VERSION 5.8 ;
BUSBITCHARS "[]" ;
DIVIDERCHAR "/" ;
UNITS
    DATABASE MICRONS 1000 ;
END UNITS

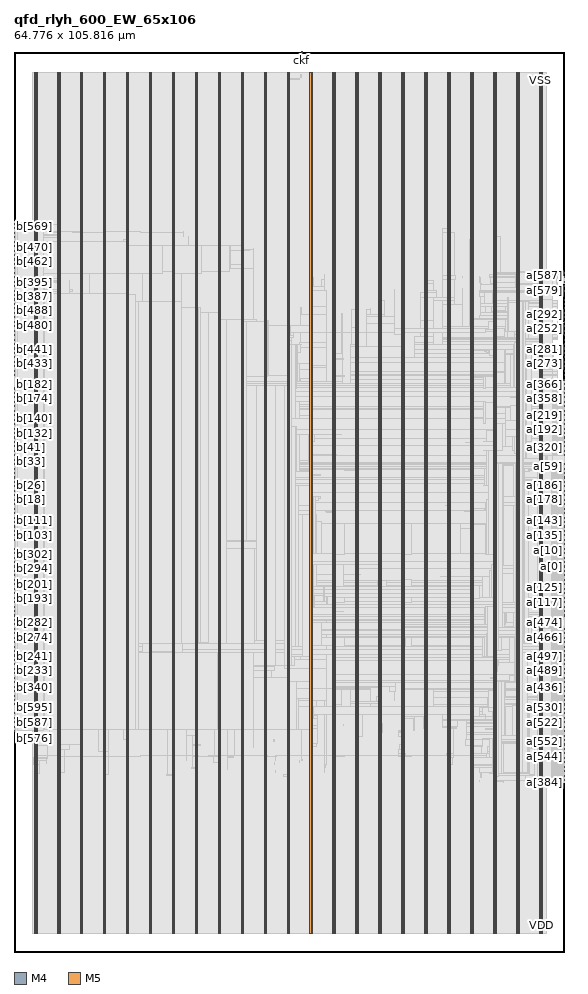
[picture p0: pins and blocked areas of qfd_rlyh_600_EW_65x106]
MACRO qfd_rlyh_600_EW_65x106
  FOREIGN qfd_rlyh_600_EW_65x106 0 0 ;
  CLASS BLOCK ;
  SIZE 64.776 BY 105.816 ;
  PIN a[0]
    DIRECTION INPUT ;
    USE SIGNAL ;
    PORT
      LAYER M4 ;
        RECT  64.692 45.264 64.776 45.288 ;
    END
  END a[0]
  PIN a[100]
    DIRECTION INPUT ;
    USE SIGNAL ;
    PORT
      LAYER M4 ;
        RECT  64.692 39.504 64.776 39.528 ;
    END
  END a[100]
  PIN a[101]
    DIRECTION INPUT ;
    USE SIGNAL ;
    PORT
      LAYER M4 ;
        RECT  64.692 39.6 64.776 39.624 ;
    END
  END a[101]
  PIN a[102]
    DIRECTION INPUT ;
    USE SIGNAL ;
    PORT
      LAYER M4 ;
        RECT  64.692 39.696 64.776 39.72 ;
    END
  END a[102]
  PIN a[103]
    DIRECTION INPUT ;
    USE SIGNAL ;
    PORT
      LAYER M4 ;
        RECT  64.692 39.792 64.776 39.816 ;
    END
  END a[103]
  PIN a[104]
    DIRECTION INPUT ;
    USE SIGNAL ;
    PORT
      LAYER M4 ;
        RECT  64.692 39.888 64.776 39.912 ;
    END
  END a[104]
  PIN a[105]
    DIRECTION INPUT ;
    USE SIGNAL ;
    PORT
      LAYER M4 ;
        RECT  64.692 39.984 64.776 40.008 ;
    END
  END a[105]
  PIN a[106]
    DIRECTION INPUT ;
    USE SIGNAL ;
    PORT
      LAYER M4 ;
        RECT  64.692 40.08 64.776 40.104 ;
    END
  END a[106]
  PIN a[107]
    DIRECTION INPUT ;
    USE SIGNAL ;
    PORT
      LAYER M4 ;
        RECT  64.692 40.176 64.776 40.2 ;
    END
  END a[107]
  PIN a[108]
    DIRECTION INPUT ;
    USE SIGNAL ;
    PORT
      LAYER M4 ;
        RECT  64.692 40.272 64.776 40.296 ;
    END
  END a[108]
  PIN a[109]
    DIRECTION INPUT ;
    USE SIGNAL ;
    PORT
      LAYER M4 ;
        RECT  64.692 40.368 64.776 40.392 ;
    END
  END a[109]
  PIN a[10]
    DIRECTION INPUT ;
    USE SIGNAL ;
    PORT
      LAYER M4 ;
        RECT  64.692 46.224 64.776 46.248 ;
    END
  END a[10]
  PIN a[110]
    DIRECTION INPUT ;
    USE SIGNAL ;
    PORT
      LAYER M4 ;
        RECT  64.692 40.464 64.776 40.488 ;
    END
  END a[110]
  PIN a[111]
    DIRECTION INPUT ;
    USE SIGNAL ;
    PORT
      LAYER M4 ;
        RECT  64.692 40.56 64.776 40.584 ;
    END
  END a[111]
  PIN a[112]
    DIRECTION INPUT ;
    USE SIGNAL ;
    PORT
      LAYER M4 ;
        RECT  64.692 40.656 64.776 40.68 ;
    END
  END a[112]
  PIN a[113]
    DIRECTION INPUT ;
    USE SIGNAL ;
    PORT
      LAYER M4 ;
        RECT  64.692 40.752 64.776 40.776 ;
    END
  END a[113]
  PIN a[114]
    DIRECTION INPUT ;
    USE SIGNAL ;
    PORT
      LAYER M4 ;
        RECT  64.692 40.848 64.776 40.872 ;
    END
  END a[114]
  PIN a[115]
    DIRECTION INPUT ;
    USE SIGNAL ;
    PORT
      LAYER M4 ;
        RECT  64.692 40.944 64.776 40.968 ;
    END
  END a[115]
  PIN a[116]
    DIRECTION INPUT ;
    USE SIGNAL ;
    PORT
      LAYER M4 ;
        RECT  64.692 41.04 64.776 41.064 ;
    END
  END a[116]
  PIN a[117]
    DIRECTION INPUT ;
    USE SIGNAL ;
    PORT
      LAYER M4 ;
        RECT  64.692 41.136 64.776 41.16 ;
    END
  END a[117]
  PIN a[118]
    DIRECTION INPUT ;
    USE SIGNAL ;
    PORT
      LAYER M4 ;
        RECT  64.692 41.232 64.776 41.256 ;
    END
  END a[118]
  PIN a[119]
    DIRECTION INPUT ;
    USE SIGNAL ;
    PORT
      LAYER M4 ;
        RECT  64.692 41.328 64.776 41.352 ;
    END
  END a[119]
  PIN a[11]
    DIRECTION INPUT ;
    USE SIGNAL ;
    PORT
      LAYER M4 ;
        RECT  64.692 46.32 64.776 46.344 ;
    END
  END a[11]
  PIN a[120]
    DIRECTION INPUT ;
    USE SIGNAL ;
    PORT
      LAYER M4 ;
        RECT  64.692 41.424 64.776 41.448 ;
    END
  END a[120]
  PIN a[121]
    DIRECTION INPUT ;
    USE SIGNAL ;
    PORT
      LAYER M4 ;
        RECT  64.692 41.52 64.776 41.544 ;
    END
  END a[121]
  PIN a[122]
    DIRECTION INPUT ;
    USE SIGNAL ;
    PORT
      LAYER M4 ;
        RECT  64.692 41.616 64.776 41.64 ;
    END
  END a[122]
  PIN a[123]
    DIRECTION INPUT ;
    USE SIGNAL ;
    PORT
      LAYER M4 ;
        RECT  64.692 41.712 64.776 41.736 ;
    END
  END a[123]
  PIN a[124]
    DIRECTION INPUT ;
    USE SIGNAL ;
    PORT
      LAYER M4 ;
        RECT  64.692 41.808 64.776 41.832 ;
    END
  END a[124]
  PIN a[125]
    DIRECTION INPUT ;
    USE SIGNAL ;
    PORT
      LAYER M4 ;
        RECT  64.692 41.904 64.776 41.928 ;
    END
  END a[125]
  PIN a[126]
    DIRECTION INPUT ;
    USE SIGNAL ;
    PORT
      LAYER M4 ;
        RECT  64.692 42 64.776 42.024 ;
    END
  END a[126]
  PIN a[127]
    DIRECTION INPUT ;
    USE SIGNAL ;
    PORT
      LAYER M4 ;
        RECT  64.692 42.096 64.776 42.12 ;
    END
  END a[127]
  PIN a[128]
    DIRECTION INPUT ;
    USE SIGNAL ;
    PORT
      LAYER M4 ;
        RECT  64.692 48.336 64.776 48.36 ;
    END
  END a[128]
  PIN a[129]
    DIRECTION INPUT ;
    USE SIGNAL ;
    PORT
      LAYER M4 ;
        RECT  64.692 48.432 64.776 48.456 ;
    END
  END a[129]
  PIN a[12]
    DIRECTION INPUT ;
    USE SIGNAL ;
    PORT
      LAYER M4 ;
        RECT  64.692 46.416 64.776 46.44 ;
    END
  END a[12]
  PIN a[130]
    DIRECTION INPUT ;
    USE SIGNAL ;
    PORT
      LAYER M4 ;
        RECT  64.692 48.528 64.776 48.552 ;
    END
  END a[130]
  PIN a[131]
    DIRECTION INPUT ;
    USE SIGNAL ;
    PORT
      LAYER M4 ;
        RECT  64.692 48.624 64.776 48.648 ;
    END
  END a[131]
  PIN a[132]
    DIRECTION INPUT ;
    USE SIGNAL ;
    PORT
      LAYER M4 ;
        RECT  64.692 48.72 64.776 48.744 ;
    END
  END a[132]
  PIN a[133]
    DIRECTION INPUT ;
    USE SIGNAL ;
    PORT
      LAYER M4 ;
        RECT  64.692 48.816 64.776 48.84 ;
    END
  END a[133]
  PIN a[134]
    DIRECTION INPUT ;
    USE SIGNAL ;
    PORT
      LAYER M4 ;
        RECT  64.692 48.912 64.776 48.936 ;
    END
  END a[134]
  PIN a[135]
    DIRECTION INPUT ;
    USE SIGNAL ;
    PORT
      LAYER M4 ;
        RECT  64.692 49.008 64.776 49.032 ;
    END
  END a[135]
  PIN a[136]
    DIRECTION INPUT ;
    USE SIGNAL ;
    PORT
      LAYER M4 ;
        RECT  64.692 49.104 64.776 49.128 ;
    END
  END a[136]
  PIN a[137]
    DIRECTION INPUT ;
    USE SIGNAL ;
    PORT
      LAYER M4 ;
        RECT  64.692 49.2 64.776 49.224 ;
    END
  END a[137]
  PIN a[138]
    DIRECTION INPUT ;
    USE SIGNAL ;
    PORT
      LAYER M4 ;
        RECT  64.692 49.296 64.776 49.32 ;
    END
  END a[138]
  PIN a[139]
    DIRECTION INPUT ;
    USE SIGNAL ;
    PORT
      LAYER M4 ;
        RECT  64.692 49.392 64.776 49.416 ;
    END
  END a[139]
  PIN a[13]
    DIRECTION INPUT ;
    USE SIGNAL ;
    PORT
      LAYER M4 ;
        RECT  64.692 46.512 64.776 46.536 ;
    END
  END a[13]
  PIN a[140]
    DIRECTION INPUT ;
    USE SIGNAL ;
    PORT
      LAYER M4 ;
        RECT  64.692 49.488 64.776 49.512 ;
    END
  END a[140]
  PIN a[141]
    DIRECTION INPUT ;
    USE SIGNAL ;
    PORT
      LAYER M4 ;
        RECT  64.692 49.584 64.776 49.608 ;
    END
  END a[141]
  PIN a[142]
    DIRECTION INPUT ;
    USE SIGNAL ;
    PORT
      LAYER M4 ;
        RECT  64.692 49.68 64.776 49.704 ;
    END
  END a[142]
  PIN a[143]
    DIRECTION INPUT ;
    USE SIGNAL ;
    PORT
      LAYER M4 ;
        RECT  64.692 49.776 64.776 49.8 ;
    END
  END a[143]
  PIN a[144]
    DIRECTION INPUT ;
    USE SIGNAL ;
    PORT
      LAYER M4 ;
        RECT  64.692 49.872 64.776 49.896 ;
    END
  END a[144]
  PIN a[145]
    DIRECTION INPUT ;
    USE SIGNAL ;
    PORT
      LAYER M4 ;
        RECT  64.692 49.968 64.776 49.992 ;
    END
  END a[145]
  PIN a[146]
    DIRECTION INPUT ;
    USE SIGNAL ;
    PORT
      LAYER M4 ;
        RECT  64.692 50.064 64.776 50.088 ;
    END
  END a[146]
  PIN a[147]
    DIRECTION INPUT ;
    USE SIGNAL ;
    PORT
      LAYER M4 ;
        RECT  64.692 50.16 64.776 50.184 ;
    END
  END a[147]
  PIN a[148]
    DIRECTION INPUT ;
    USE SIGNAL ;
    PORT
      LAYER M4 ;
        RECT  64.692 50.256 64.776 50.28 ;
    END
  END a[148]
  PIN a[149]
    DIRECTION INPUT ;
    USE SIGNAL ;
    PORT
      LAYER M4 ;
        RECT  64.692 50.352 64.776 50.376 ;
    END
  END a[149]
  PIN a[14]
    DIRECTION INPUT ;
    USE SIGNAL ;
    PORT
      LAYER M4 ;
        RECT  64.692 46.608 64.776 46.632 ;
    END
  END a[14]
  PIN a[150]
    DIRECTION INPUT ;
    USE SIGNAL ;
    PORT
      LAYER M4 ;
        RECT  64.692 50.448 64.776 50.472 ;
    END
  END a[150]
  PIN a[151]
    DIRECTION INPUT ;
    USE SIGNAL ;
    PORT
      LAYER M4 ;
        RECT  64.692 50.544 64.776 50.568 ;
    END
  END a[151]
  PIN a[152]
    DIRECTION INPUT ;
    USE SIGNAL ;
    PORT
      LAYER M4 ;
        RECT  64.692 50.64 64.776 50.664 ;
    END
  END a[152]
  PIN a[153]
    DIRECTION INPUT ;
    USE SIGNAL ;
    PORT
      LAYER M4 ;
        RECT  64.692 50.736 64.776 50.76 ;
    END
  END a[153]
  PIN a[154]
    DIRECTION INPUT ;
    USE SIGNAL ;
    PORT
      LAYER M4 ;
        RECT  64.692 50.832 64.776 50.856 ;
    END
  END a[154]
  PIN a[155]
    DIRECTION INPUT ;
    USE SIGNAL ;
    PORT
      LAYER M4 ;
        RECT  64.692 50.928 64.776 50.952 ;
    END
  END a[155]
  PIN a[156]
    DIRECTION INPUT ;
    USE SIGNAL ;
    PORT
      LAYER M4 ;
        RECT  64.692 51.024 64.776 51.048 ;
    END
  END a[156]
  PIN a[157]
    DIRECTION INPUT ;
    USE SIGNAL ;
    PORT
      LAYER M4 ;
        RECT  64.692 51.12 64.776 51.144 ;
    END
  END a[157]
  PIN a[158]
    DIRECTION INPUT ;
    USE SIGNAL ;
    PORT
      LAYER M4 ;
        RECT  64.692 51.216 64.776 51.24 ;
    END
  END a[158]
  PIN a[159]
    DIRECTION INPUT ;
    USE SIGNAL ;
    PORT
      LAYER M4 ;
        RECT  64.692 51.312 64.776 51.336 ;
    END
  END a[159]
  PIN a[15]
    DIRECTION INPUT ;
    USE SIGNAL ;
    PORT
      LAYER M4 ;
        RECT  64.692 46.704 64.776 46.728 ;
    END
  END a[15]
  PIN a[160]
    DIRECTION INPUT ;
    USE SIGNAL ;
    PORT
      LAYER M4 ;
        RECT  64.692 51.408 64.776 51.432 ;
    END
  END a[160]
  PIN a[161]
    DIRECTION INPUT ;
    USE SIGNAL ;
    PORT
      LAYER M4 ;
        RECT  64.692 51.504 64.776 51.528 ;
    END
  END a[161]
  PIN a[162]
    DIRECTION INPUT ;
    USE SIGNAL ;
    PORT
      LAYER M4 ;
        RECT  64.692 51.6 64.776 51.624 ;
    END
  END a[162]
  PIN a[163]
    DIRECTION INPUT ;
    USE SIGNAL ;
    PORT
      LAYER M4 ;
        RECT  64.692 51.696 64.776 51.72 ;
    END
  END a[163]
  PIN a[164]
    DIRECTION INPUT ;
    USE SIGNAL ;
    PORT
      LAYER M4 ;
        RECT  64.692 51.792 64.776 51.816 ;
    END
  END a[164]
  PIN a[165]
    DIRECTION INPUT ;
    USE SIGNAL ;
    PORT
      LAYER M4 ;
        RECT  64.692 51.888 64.776 51.912 ;
    END
  END a[165]
  PIN a[166]
    DIRECTION INPUT ;
    USE SIGNAL ;
    PORT
      LAYER M4 ;
        RECT  64.692 51.984 64.776 52.008 ;
    END
  END a[166]
  PIN a[167]
    DIRECTION INPUT ;
    USE SIGNAL ;
    PORT
      LAYER M4 ;
        RECT  64.692 52.08 64.776 52.104 ;
    END
  END a[167]
  PIN a[168]
    DIRECTION INPUT ;
    USE SIGNAL ;
    PORT
      LAYER M4 ;
        RECT  64.692 52.176 64.776 52.2 ;
    END
  END a[168]
  PIN a[169]
    DIRECTION INPUT ;
    USE SIGNAL ;
    PORT
      LAYER M4 ;
        RECT  64.692 52.272 64.776 52.296 ;
    END
  END a[169]
  PIN a[16]
    DIRECTION INPUT ;
    USE SIGNAL ;
    PORT
      LAYER M4 ;
        RECT  64.692 46.8 64.776 46.824 ;
    END
  END a[16]
  PIN a[170]
    DIRECTION INPUT ;
    USE SIGNAL ;
    PORT
      LAYER M4 ;
        RECT  64.692 52.368 64.776 52.392 ;
    END
  END a[170]
  PIN a[171]
    DIRECTION INPUT ;
    USE SIGNAL ;
    PORT
      LAYER M4 ;
        RECT  64.692 52.464 64.776 52.488 ;
    END
  END a[171]
  PIN a[172]
    DIRECTION INPUT ;
    USE SIGNAL ;
    PORT
      LAYER M4 ;
        RECT  64.692 52.56 64.776 52.584 ;
    END
  END a[172]
  PIN a[173]
    DIRECTION INPUT ;
    USE SIGNAL ;
    PORT
      LAYER M4 ;
        RECT  64.692 52.656 64.776 52.68 ;
    END
  END a[173]
  PIN a[174]
    DIRECTION INPUT ;
    USE SIGNAL ;
    PORT
      LAYER M4 ;
        RECT  64.692 52.752 64.776 52.776 ;
    END
  END a[174]
  PIN a[175]
    DIRECTION INPUT ;
    USE SIGNAL ;
    PORT
      LAYER M4 ;
        RECT  64.692 52.848 64.776 52.872 ;
    END
  END a[175]
  PIN a[176]
    DIRECTION INPUT ;
    USE SIGNAL ;
    PORT
      LAYER M4 ;
        RECT  64.692 52.944 64.776 52.968 ;
    END
  END a[176]
  PIN a[177]
    DIRECTION INPUT ;
    USE SIGNAL ;
    PORT
      LAYER M4 ;
        RECT  64.692 53.04 64.776 53.064 ;
    END
  END a[177]
  PIN a[178]
    DIRECTION INPUT ;
    USE SIGNAL ;
    PORT
      LAYER M4 ;
        RECT  64.692 53.136 64.776 53.16 ;
    END
  END a[178]
  PIN a[179]
    DIRECTION INPUT ;
    USE SIGNAL ;
    PORT
      LAYER M4 ;
        RECT  64.692 53.232 64.776 53.256 ;
    END
  END a[179]
  PIN a[17]
    DIRECTION INPUT ;
    USE SIGNAL ;
    PORT
      LAYER M4 ;
        RECT  64.692 46.896 64.776 46.92 ;
    END
  END a[17]
  PIN a[180]
    DIRECTION INPUT ;
    USE SIGNAL ;
    PORT
      LAYER M4 ;
        RECT  64.692 53.328 64.776 53.352 ;
    END
  END a[180]
  PIN a[181]
    DIRECTION INPUT ;
    USE SIGNAL ;
    PORT
      LAYER M4 ;
        RECT  64.692 53.424 64.776 53.448 ;
    END
  END a[181]
  PIN a[182]
    DIRECTION INPUT ;
    USE SIGNAL ;
    PORT
      LAYER M4 ;
        RECT  64.692 53.52 64.776 53.544 ;
    END
  END a[182]
  PIN a[183]
    DIRECTION INPUT ;
    USE SIGNAL ;
    PORT
      LAYER M4 ;
        RECT  64.692 53.616 64.776 53.64 ;
    END
  END a[183]
  PIN a[184]
    DIRECTION INPUT ;
    USE SIGNAL ;
    PORT
      LAYER M4 ;
        RECT  64.692 53.712 64.776 53.736 ;
    END
  END a[184]
  PIN a[185]
    DIRECTION INPUT ;
    USE SIGNAL ;
    PORT
      LAYER M4 ;
        RECT  64.692 53.808 64.776 53.832 ;
    END
  END a[185]
  PIN a[186]
    DIRECTION INPUT ;
    USE SIGNAL ;
    PORT
      LAYER M4 ;
        RECT  64.692 53.904 64.776 53.928 ;
    END
  END a[186]
  PIN a[187]
    DIRECTION INPUT ;
    USE SIGNAL ;
    PORT
      LAYER M4 ;
        RECT  64.692 54 64.776 54.024 ;
    END
  END a[187]
  PIN a[188]
    DIRECTION INPUT ;
    USE SIGNAL ;
    PORT
      LAYER M4 ;
        RECT  64.692 54.096 64.776 54.12 ;
    END
  END a[188]
  PIN a[189]
    DIRECTION INPUT ;
    USE SIGNAL ;
    PORT
      LAYER M4 ;
        RECT  64.692 54.192 64.776 54.216 ;
    END
  END a[189]
  PIN a[18]
    DIRECTION INPUT ;
    USE SIGNAL ;
    PORT
      LAYER M4 ;
        RECT  64.692 46.992 64.776 47.016 ;
    END
  END a[18]
  PIN a[190]
    DIRECTION INPUT ;
    USE SIGNAL ;
    PORT
      LAYER M4 ;
        RECT  64.692 54.288 64.776 54.312 ;
    END
  END a[190]
  PIN a[191]
    DIRECTION INPUT ;
    USE SIGNAL ;
    PORT
      LAYER M4 ;
        RECT  64.692 54.384 64.776 54.408 ;
    END
  END a[191]
  PIN a[192]
    DIRECTION INPUT ;
    USE SIGNAL ;
    PORT
      LAYER M4 ;
        RECT  64.692 61.392 64.776 61.416 ;
    END
  END a[192]
  PIN a[193]
    DIRECTION INPUT ;
    USE SIGNAL ;
    PORT
      LAYER M4 ;
        RECT  64.692 61.488 64.776 61.512 ;
    END
  END a[193]
  PIN a[194]
    DIRECTION INPUT ;
    USE SIGNAL ;
    PORT
      LAYER M4 ;
        RECT  64.692 61.584 64.776 61.608 ;
    END
  END a[194]
  PIN a[195]
    DIRECTION INPUT ;
    USE SIGNAL ;
    PORT
      LAYER M4 ;
        RECT  64.692 61.68 64.776 61.704 ;
    END
  END a[195]
  PIN a[196]
    DIRECTION INPUT ;
    USE SIGNAL ;
    PORT
      LAYER M4 ;
        RECT  64.692 61.776 64.776 61.8 ;
    END
  END a[196]
  PIN a[197]
    DIRECTION INPUT ;
    USE SIGNAL ;
    PORT
      LAYER M4 ;
        RECT  64.692 61.872 64.776 61.896 ;
    END
  END a[197]
  PIN a[198]
    DIRECTION INPUT ;
    USE SIGNAL ;
    PORT
      LAYER M4 ;
        RECT  64.692 61.968 64.776 61.992 ;
    END
  END a[198]
  PIN a[199]
    DIRECTION INPUT ;
    USE SIGNAL ;
    PORT
      LAYER M4 ;
        RECT  64.692 62.064 64.776 62.088 ;
    END
  END a[199]
  PIN a[19]
    DIRECTION INPUT ;
    USE SIGNAL ;
    PORT
      LAYER M4 ;
        RECT  64.692 47.088 64.776 47.112 ;
    END
  END a[19]
  PIN a[1]
    DIRECTION INPUT ;
    USE SIGNAL ;
    PORT
      LAYER M4 ;
        RECT  64.692 45.36 64.776 45.384 ;
    END
  END a[1]
  PIN a[200]
    DIRECTION INPUT ;
    USE SIGNAL ;
    PORT
      LAYER M4 ;
        RECT  64.692 62.16 64.776 62.184 ;
    END
  END a[200]
  PIN a[201]
    DIRECTION INPUT ;
    USE SIGNAL ;
    PORT
      LAYER M4 ;
        RECT  64.692 62.256 64.776 62.28 ;
    END
  END a[201]
  PIN a[202]
    DIRECTION INPUT ;
    USE SIGNAL ;
    PORT
      LAYER M4 ;
        RECT  64.692 62.352 64.776 62.376 ;
    END
  END a[202]
  PIN a[203]
    DIRECTION INPUT ;
    USE SIGNAL ;
    PORT
      LAYER M4 ;
        RECT  64.692 62.448 64.776 62.472 ;
    END
  END a[203]
  PIN a[204]
    DIRECTION INPUT ;
    USE SIGNAL ;
    PORT
      LAYER M4 ;
        RECT  64.692 62.544 64.776 62.568 ;
    END
  END a[204]
  PIN a[205]
    DIRECTION INPUT ;
    USE SIGNAL ;
    PORT
      LAYER M4 ;
        RECT  64.692 62.64 64.776 62.664 ;
    END
  END a[205]
  PIN a[206]
    DIRECTION INPUT ;
    USE SIGNAL ;
    PORT
      LAYER M4 ;
        RECT  64.692 62.736 64.776 62.76 ;
    END
  END a[206]
  PIN a[207]
    DIRECTION INPUT ;
    USE SIGNAL ;
    PORT
      LAYER M4 ;
        RECT  64.692 62.832 64.776 62.856 ;
    END
  END a[207]
  PIN a[208]
    DIRECTION INPUT ;
    USE SIGNAL ;
    PORT
      LAYER M4 ;
        RECT  64.692 62.928 64.776 62.952 ;
    END
  END a[208]
  PIN a[209]
    DIRECTION INPUT ;
    USE SIGNAL ;
    PORT
      LAYER M4 ;
        RECT  64.692 63.024 64.776 63.048 ;
    END
  END a[209]
  PIN a[20]
    DIRECTION INPUT ;
    USE SIGNAL ;
    PORT
      LAYER M4 ;
        RECT  64.692 47.184 64.776 47.208 ;
    END
  END a[20]
  PIN a[210]
    DIRECTION INPUT ;
    USE SIGNAL ;
    PORT
      LAYER M4 ;
        RECT  64.692 63.12 64.776 63.144 ;
    END
  END a[210]
  PIN a[211]
    DIRECTION INPUT ;
    USE SIGNAL ;
    PORT
      LAYER M4 ;
        RECT  64.692 63.216 64.776 63.24 ;
    END
  END a[211]
  PIN a[212]
    DIRECTION INPUT ;
    USE SIGNAL ;
    PORT
      LAYER M4 ;
        RECT  64.692 63.312 64.776 63.336 ;
    END
  END a[212]
  PIN a[213]
    DIRECTION INPUT ;
    USE SIGNAL ;
    PORT
      LAYER M4 ;
        RECT  64.692 63.408 64.776 63.432 ;
    END
  END a[213]
  PIN a[214]
    DIRECTION INPUT ;
    USE SIGNAL ;
    PORT
      LAYER M4 ;
        RECT  64.692 63.504 64.776 63.528 ;
    END
  END a[214]
  PIN a[215]
    DIRECTION INPUT ;
    USE SIGNAL ;
    PORT
      LAYER M4 ;
        RECT  64.692 63.6 64.776 63.624 ;
    END
  END a[215]
  PIN a[216]
    DIRECTION INPUT ;
    USE SIGNAL ;
    PORT
      LAYER M4 ;
        RECT  64.692 63.696 64.776 63.72 ;
    END
  END a[216]
  PIN a[217]
    DIRECTION INPUT ;
    USE SIGNAL ;
    PORT
      LAYER M4 ;
        RECT  64.692 63.792 64.776 63.816 ;
    END
  END a[217]
  PIN a[218]
    DIRECTION INPUT ;
    USE SIGNAL ;
    PORT
      LAYER M4 ;
        RECT  64.692 63.888 64.776 63.912 ;
    END
  END a[218]
  PIN a[219]
    DIRECTION INPUT ;
    USE SIGNAL ;
    PORT
      LAYER M4 ;
        RECT  64.692 63.984 64.776 64.008 ;
    END
  END a[219]
  PIN a[21]
    DIRECTION INPUT ;
    USE SIGNAL ;
    PORT
      LAYER M4 ;
        RECT  64.692 47.28 64.776 47.304 ;
    END
  END a[21]
  PIN a[220]
    DIRECTION INPUT ;
    USE SIGNAL ;
    PORT
      LAYER M4 ;
        RECT  64.692 64.08 64.776 64.104 ;
    END
  END a[220]
  PIN a[221]
    DIRECTION INPUT ;
    USE SIGNAL ;
    PORT
      LAYER M4 ;
        RECT  64.692 64.176 64.776 64.2 ;
    END
  END a[221]
  PIN a[222]
    DIRECTION INPUT ;
    USE SIGNAL ;
    PORT
      LAYER M4 ;
        RECT  64.692 64.272 64.776 64.296 ;
    END
  END a[222]
  PIN a[223]
    DIRECTION INPUT ;
    USE SIGNAL ;
    PORT
      LAYER M4 ;
        RECT  64.692 64.368 64.776 64.392 ;
    END
  END a[223]
  PIN a[224]
    DIRECTION INPUT ;
    USE SIGNAL ;
    PORT
      LAYER M4 ;
        RECT  64.692 70.608 64.776 70.632 ;
    END
  END a[224]
  PIN a[225]
    DIRECTION INPUT ;
    USE SIGNAL ;
    PORT
      LAYER M4 ;
        RECT  64.692 70.704 64.776 70.728 ;
    END
  END a[225]
  PIN a[226]
    DIRECTION INPUT ;
    USE SIGNAL ;
    PORT
      LAYER M4 ;
        RECT  64.692 70.8 64.776 70.824 ;
    END
  END a[226]
  PIN a[227]
    DIRECTION INPUT ;
    USE SIGNAL ;
    PORT
      LAYER M4 ;
        RECT  64.692 70.896 64.776 70.92 ;
    END
  END a[227]
  PIN a[228]
    DIRECTION INPUT ;
    USE SIGNAL ;
    PORT
      LAYER M4 ;
        RECT  64.692 70.992 64.776 71.016 ;
    END
  END a[228]
  PIN a[229]
    DIRECTION INPUT ;
    USE SIGNAL ;
    PORT
      LAYER M4 ;
        RECT  64.692 71.088 64.776 71.112 ;
    END
  END a[229]
  PIN a[22]
    DIRECTION INPUT ;
    USE SIGNAL ;
    PORT
      LAYER M4 ;
        RECT  64.692 47.376 64.776 47.4 ;
    END
  END a[22]
  PIN a[230]
    DIRECTION INPUT ;
    USE SIGNAL ;
    PORT
      LAYER M4 ;
        RECT  64.692 71.184 64.776 71.208 ;
    END
  END a[230]
  PIN a[231]
    DIRECTION INPUT ;
    USE SIGNAL ;
    PORT
      LAYER M4 ;
        RECT  64.692 71.28 64.776 71.304 ;
    END
  END a[231]
  PIN a[232]
    DIRECTION INPUT ;
    USE SIGNAL ;
    PORT
      LAYER M4 ;
        RECT  64.692 71.376 64.776 71.4 ;
    END
  END a[232]
  PIN a[233]
    DIRECTION INPUT ;
    USE SIGNAL ;
    PORT
      LAYER M4 ;
        RECT  64.692 71.472 64.776 71.496 ;
    END
  END a[233]
  PIN a[234]
    DIRECTION INPUT ;
    USE SIGNAL ;
    PORT
      LAYER M4 ;
        RECT  64.692 71.568 64.776 71.592 ;
    END
  END a[234]
  PIN a[235]
    DIRECTION INPUT ;
    USE SIGNAL ;
    PORT
      LAYER M4 ;
        RECT  64.692 71.664 64.776 71.688 ;
    END
  END a[235]
  PIN a[236]
    DIRECTION INPUT ;
    USE SIGNAL ;
    PORT
      LAYER M4 ;
        RECT  64.692 71.76 64.776 71.784 ;
    END
  END a[236]
  PIN a[237]
    DIRECTION INPUT ;
    USE SIGNAL ;
    PORT
      LAYER M4 ;
        RECT  64.692 71.856 64.776 71.88 ;
    END
  END a[237]
  PIN a[238]
    DIRECTION INPUT ;
    USE SIGNAL ;
    PORT
      LAYER M4 ;
        RECT  64.692 71.952 64.776 71.976 ;
    END
  END a[238]
  PIN a[239]
    DIRECTION INPUT ;
    USE SIGNAL ;
    PORT
      LAYER M4 ;
        RECT  64.692 72.048 64.776 72.072 ;
    END
  END a[239]
  PIN a[23]
    DIRECTION INPUT ;
    USE SIGNAL ;
    PORT
      LAYER M4 ;
        RECT  64.692 47.472 64.776 47.496 ;
    END
  END a[23]
  PIN a[240]
    DIRECTION INPUT ;
    USE SIGNAL ;
    PORT
      LAYER M4 ;
        RECT  64.692 72.144 64.776 72.168 ;
    END
  END a[240]
  PIN a[241]
    DIRECTION INPUT ;
    USE SIGNAL ;
    PORT
      LAYER M4 ;
        RECT  64.692 72.24 64.776 72.264 ;
    END
  END a[241]
  PIN a[242]
    DIRECTION INPUT ;
    USE SIGNAL ;
    PORT
      LAYER M4 ;
        RECT  64.692 72.336 64.776 72.36 ;
    END
  END a[242]
  PIN a[243]
    DIRECTION INPUT ;
    USE SIGNAL ;
    PORT
      LAYER M4 ;
        RECT  64.692 72.432 64.776 72.456 ;
    END
  END a[243]
  PIN a[244]
    DIRECTION INPUT ;
    USE SIGNAL ;
    PORT
      LAYER M4 ;
        RECT  64.692 72.528 64.776 72.552 ;
    END
  END a[244]
  PIN a[245]
    DIRECTION INPUT ;
    USE SIGNAL ;
    PORT
      LAYER M4 ;
        RECT  64.692 72.624 64.776 72.648 ;
    END
  END a[245]
  PIN a[246]
    DIRECTION INPUT ;
    USE SIGNAL ;
    PORT
      LAYER M4 ;
        RECT  64.692 72.72 64.776 72.744 ;
    END
  END a[246]
  PIN a[247]
    DIRECTION INPUT ;
    USE SIGNAL ;
    PORT
      LAYER M4 ;
        RECT  64.692 72.816 64.776 72.84 ;
    END
  END a[247]
  PIN a[248]
    DIRECTION INPUT ;
    USE SIGNAL ;
    PORT
      LAYER M4 ;
        RECT  64.692 72.912 64.776 72.936 ;
    END
  END a[248]
  PIN a[249]
    DIRECTION INPUT ;
    USE SIGNAL ;
    PORT
      LAYER M4 ;
        RECT  64.692 73.008 64.776 73.032 ;
    END
  END a[249]
  PIN a[24]
    DIRECTION INPUT ;
    USE SIGNAL ;
    PORT
      LAYER M4 ;
        RECT  64.692 47.568 64.776 47.592 ;
    END
  END a[24]
  PIN a[250]
    DIRECTION INPUT ;
    USE SIGNAL ;
    PORT
      LAYER M4 ;
        RECT  64.692 73.104 64.776 73.128 ;
    END
  END a[250]
  PIN a[251]
    DIRECTION INPUT ;
    USE SIGNAL ;
    PORT
      LAYER M4 ;
        RECT  64.692 73.2 64.776 73.224 ;
    END
  END a[251]
  PIN a[252]
    DIRECTION INPUT ;
    USE SIGNAL ;
    PORT
      LAYER M4 ;
        RECT  64.692 73.296 64.776 73.32 ;
    END
  END a[252]
  PIN a[253]
    DIRECTION INPUT ;
    USE SIGNAL ;
    PORT
      LAYER M4 ;
        RECT  64.692 73.392 64.776 73.416 ;
    END
  END a[253]
  PIN a[254]
    DIRECTION INPUT ;
    USE SIGNAL ;
    PORT
      LAYER M4 ;
        RECT  64.692 73.488 64.776 73.512 ;
    END
  END a[254]
  PIN a[255]
    DIRECTION INPUT ;
    USE SIGNAL ;
    PORT
      LAYER M4 ;
        RECT  64.692 73.584 64.776 73.608 ;
    END
  END a[255]
  PIN a[256]
    DIRECTION INPUT ;
    USE SIGNAL ;
    PORT
      LAYER M4 ;
        RECT  64.692 67.536 64.776 67.56 ;
    END
  END a[256]
  PIN a[257]
    DIRECTION INPUT ;
    USE SIGNAL ;
    PORT
      LAYER M4 ;
        RECT  64.692 67.632 64.776 67.656 ;
    END
  END a[257]
  PIN a[258]
    DIRECTION INPUT ;
    USE SIGNAL ;
    PORT
      LAYER M4 ;
        RECT  64.692 67.728 64.776 67.752 ;
    END
  END a[258]
  PIN a[259]
    DIRECTION INPUT ;
    USE SIGNAL ;
    PORT
      LAYER M4 ;
        RECT  64.692 67.824 64.776 67.848 ;
    END
  END a[259]
  PIN a[25]
    DIRECTION INPUT ;
    USE SIGNAL ;
    PORT
      LAYER M4 ;
        RECT  64.692 47.664 64.776 47.688 ;
    END
  END a[25]
  PIN a[260]
    DIRECTION INPUT ;
    USE SIGNAL ;
    PORT
      LAYER M4 ;
        RECT  64.692 67.92 64.776 67.944 ;
    END
  END a[260]
  PIN a[261]
    DIRECTION INPUT ;
    USE SIGNAL ;
    PORT
      LAYER M4 ;
        RECT  64.692 68.016 64.776 68.04 ;
    END
  END a[261]
  PIN a[262]
    DIRECTION INPUT ;
    USE SIGNAL ;
    PORT
      LAYER M4 ;
        RECT  64.692 68.112 64.776 68.136 ;
    END
  END a[262]
  PIN a[263]
    DIRECTION INPUT ;
    USE SIGNAL ;
    PORT
      LAYER M4 ;
        RECT  64.692 68.208 64.776 68.232 ;
    END
  END a[263]
  PIN a[264]
    DIRECTION INPUT ;
    USE SIGNAL ;
    PORT
      LAYER M4 ;
        RECT  64.692 68.304 64.776 68.328 ;
    END
  END a[264]
  PIN a[265]
    DIRECTION INPUT ;
    USE SIGNAL ;
    PORT
      LAYER M4 ;
        RECT  64.692 68.4 64.776 68.424 ;
    END
  END a[265]
  PIN a[266]
    DIRECTION INPUT ;
    USE SIGNAL ;
    PORT
      LAYER M4 ;
        RECT  64.692 68.496 64.776 68.52 ;
    END
  END a[266]
  PIN a[267]
    DIRECTION INPUT ;
    USE SIGNAL ;
    PORT
      LAYER M4 ;
        RECT  64.692 68.592 64.776 68.616 ;
    END
  END a[267]
  PIN a[268]
    DIRECTION INPUT ;
    USE SIGNAL ;
    PORT
      LAYER M4 ;
        RECT  64.692 68.688 64.776 68.712 ;
    END
  END a[268]
  PIN a[269]
    DIRECTION INPUT ;
    USE SIGNAL ;
    PORT
      LAYER M4 ;
        RECT  64.692 68.784 64.776 68.808 ;
    END
  END a[269]
  PIN a[26]
    DIRECTION INPUT ;
    USE SIGNAL ;
    PORT
      LAYER M4 ;
        RECT  64.692 47.76 64.776 47.784 ;
    END
  END a[26]
  PIN a[270]
    DIRECTION INPUT ;
    USE SIGNAL ;
    PORT
      LAYER M4 ;
        RECT  64.692 68.88 64.776 68.904 ;
    END
  END a[270]
  PIN a[271]
    DIRECTION INPUT ;
    USE SIGNAL ;
    PORT
      LAYER M4 ;
        RECT  64.692 68.976 64.776 69 ;
    END
  END a[271]
  PIN a[272]
    DIRECTION INPUT ;
    USE SIGNAL ;
    PORT
      LAYER M4 ;
        RECT  64.692 69.072 64.776 69.096 ;
    END
  END a[272]
  PIN a[273]
    DIRECTION INPUT ;
    USE SIGNAL ;
    PORT
      LAYER M4 ;
        RECT  64.692 69.168 64.776 69.192 ;
    END
  END a[273]
  PIN a[274]
    DIRECTION INPUT ;
    USE SIGNAL ;
    PORT
      LAYER M4 ;
        RECT  64.692 69.264 64.776 69.288 ;
    END
  END a[274]
  PIN a[275]
    DIRECTION INPUT ;
    USE SIGNAL ;
    PORT
      LAYER M4 ;
        RECT  64.692 69.36 64.776 69.384 ;
    END
  END a[275]
  PIN a[276]
    DIRECTION INPUT ;
    USE SIGNAL ;
    PORT
      LAYER M4 ;
        RECT  64.692 69.456 64.776 69.48 ;
    END
  END a[276]
  PIN a[277]
    DIRECTION INPUT ;
    USE SIGNAL ;
    PORT
      LAYER M4 ;
        RECT  64.692 69.552 64.776 69.576 ;
    END
  END a[277]
  PIN a[278]
    DIRECTION INPUT ;
    USE SIGNAL ;
    PORT
      LAYER M4 ;
        RECT  64.692 69.648 64.776 69.672 ;
    END
  END a[278]
  PIN a[279]
    DIRECTION INPUT ;
    USE SIGNAL ;
    PORT
      LAYER M4 ;
        RECT  64.692 69.744 64.776 69.768 ;
    END
  END a[279]
  PIN a[27]
    DIRECTION INPUT ;
    USE SIGNAL ;
    PORT
      LAYER M4 ;
        RECT  64.692 47.856 64.776 47.88 ;
    END
  END a[27]
  PIN a[280]
    DIRECTION INPUT ;
    USE SIGNAL ;
    PORT
      LAYER M4 ;
        RECT  64.692 69.84 64.776 69.864 ;
    END
  END a[280]
  PIN a[281]
    DIRECTION INPUT ;
    USE SIGNAL ;
    PORT
      LAYER M4 ;
        RECT  64.692 69.936 64.776 69.96 ;
    END
  END a[281]
  PIN a[282]
    DIRECTION INPUT ;
    USE SIGNAL ;
    PORT
      LAYER M4 ;
        RECT  64.692 70.032 64.776 70.056 ;
    END
  END a[282]
  PIN a[283]
    DIRECTION INPUT ;
    USE SIGNAL ;
    PORT
      LAYER M4 ;
        RECT  64.692 70.128 64.776 70.152 ;
    END
  END a[283]
  PIN a[284]
    DIRECTION INPUT ;
    USE SIGNAL ;
    PORT
      LAYER M4 ;
        RECT  64.692 70.224 64.776 70.248 ;
    END
  END a[284]
  PIN a[285]
    DIRECTION INPUT ;
    USE SIGNAL ;
    PORT
      LAYER M4 ;
        RECT  64.692 70.32 64.776 70.344 ;
    END
  END a[285]
  PIN a[286]
    DIRECTION INPUT ;
    USE SIGNAL ;
    PORT
      LAYER M4 ;
        RECT  64.692 70.416 64.776 70.44 ;
    END
  END a[286]
  PIN a[287]
    DIRECTION INPUT ;
    USE SIGNAL ;
    PORT
      LAYER M4 ;
        RECT  64.692 70.512 64.776 70.536 ;
    END
  END a[287]
  PIN a[288]
    DIRECTION INPUT ;
    USE SIGNAL ;
    PORT
      LAYER M4 ;
        RECT  64.692 73.68 64.776 73.704 ;
    END
  END a[288]
  PIN a[289]
    DIRECTION INPUT ;
    USE SIGNAL ;
    PORT
      LAYER M4 ;
        RECT  64.692 73.776 64.776 73.8 ;
    END
  END a[289]
  PIN a[28]
    DIRECTION INPUT ;
    USE SIGNAL ;
    PORT
      LAYER M4 ;
        RECT  64.692 47.952 64.776 47.976 ;
    END
  END a[28]
  PIN a[290]
    DIRECTION INPUT ;
    USE SIGNAL ;
    PORT
      LAYER M4 ;
        RECT  64.692 73.872 64.776 73.896 ;
    END
  END a[290]
  PIN a[291]
    DIRECTION INPUT ;
    USE SIGNAL ;
    PORT
      LAYER M4 ;
        RECT  64.692 73.968 64.776 73.992 ;
    END
  END a[291]
  PIN a[292]
    DIRECTION INPUT ;
    USE SIGNAL ;
    PORT
      LAYER M4 ;
        RECT  64.692 74.064 64.776 74.088 ;
    END
  END a[292]
  PIN a[293]
    DIRECTION INPUT ;
    USE SIGNAL ;
    PORT
      LAYER M4 ;
        RECT  64.692 74.16 64.776 74.184 ;
    END
  END a[293]
  PIN a[294]
    DIRECTION INPUT ;
    USE SIGNAL ;
    PORT
      LAYER M4 ;
        RECT  64.692 74.256 64.776 74.28 ;
    END
  END a[294]
  PIN a[295]
    DIRECTION INPUT ;
    USE SIGNAL ;
    PORT
      LAYER M4 ;
        RECT  64.692 74.352 64.776 74.376 ;
    END
  END a[295]
  PIN a[296]
    DIRECTION INPUT ;
    USE SIGNAL ;
    PORT
      LAYER M4 ;
        RECT  64.692 74.448 64.776 74.472 ;
    END
  END a[296]
  PIN a[297]
    DIRECTION INPUT ;
    USE SIGNAL ;
    PORT
      LAYER M4 ;
        RECT  64.692 74.544 64.776 74.568 ;
    END
  END a[297]
  PIN a[298]
    DIRECTION INPUT ;
    USE SIGNAL ;
    PORT
      LAYER M4 ;
        RECT  64.692 74.64 64.776 74.664 ;
    END
  END a[298]
  PIN a[299]
    DIRECTION INPUT ;
    USE SIGNAL ;
    PORT
      LAYER M4 ;
        RECT  64.692 74.736 64.776 74.76 ;
    END
  END a[299]
  PIN a[29]
    DIRECTION INPUT ;
    USE SIGNAL ;
    PORT
      LAYER M4 ;
        RECT  64.692 48.048 64.776 48.072 ;
    END
  END a[29]
  PIN a[2]
    DIRECTION INPUT ;
    USE SIGNAL ;
    PORT
      LAYER M4 ;
        RECT  64.692 45.456 64.776 45.48 ;
    END
  END a[2]
  PIN a[300]
    DIRECTION INPUT ;
    USE SIGNAL ;
    PORT
      LAYER M4 ;
        RECT  64.692 74.832 64.776 74.856 ;
    END
  END a[300]
  PIN a[301]
    DIRECTION INPUT ;
    USE SIGNAL ;
    PORT
      LAYER M4 ;
        RECT  64.692 74.928 64.776 74.952 ;
    END
  END a[301]
  PIN a[302]
    DIRECTION INPUT ;
    USE SIGNAL ;
    PORT
      LAYER M4 ;
        RECT  64.692 75.024 64.776 75.048 ;
    END
  END a[302]
  PIN a[303]
    DIRECTION INPUT ;
    USE SIGNAL ;
    PORT
      LAYER M4 ;
        RECT  64.692 75.12 64.776 75.144 ;
    END
  END a[303]
  PIN a[304]
    DIRECTION INPUT ;
    USE SIGNAL ;
    PORT
      LAYER M4 ;
        RECT  64.692 75.216 64.776 75.24 ;
    END
  END a[304]
  PIN a[305]
    DIRECTION INPUT ;
    USE SIGNAL ;
    PORT
      LAYER M4 ;
        RECT  64.692 75.312 64.776 75.336 ;
    END
  END a[305]
  PIN a[306]
    DIRECTION INPUT ;
    USE SIGNAL ;
    PORT
      LAYER M4 ;
        RECT  64.692 75.408 64.776 75.432 ;
    END
  END a[306]
  PIN a[307]
    DIRECTION INPUT ;
    USE SIGNAL ;
    PORT
      LAYER M4 ;
        RECT  64.692 75.504 64.776 75.528 ;
    END
  END a[307]
  PIN a[308]
    DIRECTION INPUT ;
    USE SIGNAL ;
    PORT
      LAYER M4 ;
        RECT  64.692 75.6 64.776 75.624 ;
    END
  END a[308]
  PIN a[309]
    DIRECTION INPUT ;
    USE SIGNAL ;
    PORT
      LAYER M4 ;
        RECT  64.692 75.696 64.776 75.72 ;
    END
  END a[309]
  PIN a[30]
    DIRECTION INPUT ;
    USE SIGNAL ;
    PORT
      LAYER M4 ;
        RECT  64.692 48.144 64.776 48.168 ;
    END
  END a[30]
  PIN a[310]
    DIRECTION INPUT ;
    USE SIGNAL ;
    PORT
      LAYER M4 ;
        RECT  64.692 75.792 64.776 75.816 ;
    END
  END a[310]
  PIN a[311]
    DIRECTION INPUT ;
    USE SIGNAL ;
    PORT
      LAYER M4 ;
        RECT  64.692 75.888 64.776 75.912 ;
    END
  END a[311]
  PIN a[312]
    DIRECTION INPUT ;
    USE SIGNAL ;
    PORT
      LAYER M4 ;
        RECT  64.692 75.984 64.776 76.008 ;
    END
  END a[312]
  PIN a[313]
    DIRECTION INPUT ;
    USE SIGNAL ;
    PORT
      LAYER M4 ;
        RECT  64.692 76.08 64.776 76.104 ;
    END
  END a[313]
  PIN a[314]
    DIRECTION INPUT ;
    USE SIGNAL ;
    PORT
      LAYER M4 ;
        RECT  64.692 76.176 64.776 76.2 ;
    END
  END a[314]
  PIN a[315]
    DIRECTION INPUT ;
    USE SIGNAL ;
    PORT
      LAYER M4 ;
        RECT  64.692 76.272 64.776 76.296 ;
    END
  END a[315]
  PIN a[316]
    DIRECTION INPUT ;
    USE SIGNAL ;
    PORT
      LAYER M4 ;
        RECT  64.692 76.368 64.776 76.392 ;
    END
  END a[316]
  PIN a[317]
    DIRECTION INPUT ;
    USE SIGNAL ;
    PORT
      LAYER M4 ;
        RECT  64.692 76.464 64.776 76.488 ;
    END
  END a[317]
  PIN a[318]
    DIRECTION INPUT ;
    USE SIGNAL ;
    PORT
      LAYER M4 ;
        RECT  64.692 76.56 64.776 76.584 ;
    END
  END a[318]
  PIN a[319]
    DIRECTION INPUT ;
    USE SIGNAL ;
    PORT
      LAYER M4 ;
        RECT  64.692 76.656 64.776 76.68 ;
    END
  END a[319]
  PIN a[31]
    DIRECTION INPUT ;
    USE SIGNAL ;
    PORT
      LAYER M4 ;
        RECT  64.692 48.24 64.776 48.264 ;
    END
  END a[31]
  PIN a[320]
    DIRECTION INPUT ;
    USE SIGNAL ;
    PORT
      LAYER M4 ;
        RECT  64.692 58.32 64.776 58.344 ;
    END
  END a[320]
  PIN a[321]
    DIRECTION INPUT ;
    USE SIGNAL ;
    PORT
      LAYER M4 ;
        RECT  64.692 58.416 64.776 58.44 ;
    END
  END a[321]
  PIN a[322]
    DIRECTION INPUT ;
    USE SIGNAL ;
    PORT
      LAYER M4 ;
        RECT  64.692 58.512 64.776 58.536 ;
    END
  END a[322]
  PIN a[323]
    DIRECTION INPUT ;
    USE SIGNAL ;
    PORT
      LAYER M4 ;
        RECT  64.692 58.608 64.776 58.632 ;
    END
  END a[323]
  PIN a[324]
    DIRECTION INPUT ;
    USE SIGNAL ;
    PORT
      LAYER M4 ;
        RECT  64.692 58.704 64.776 58.728 ;
    END
  END a[324]
  PIN a[325]
    DIRECTION INPUT ;
    USE SIGNAL ;
    PORT
      LAYER M4 ;
        RECT  64.692 58.8 64.776 58.824 ;
    END
  END a[325]
  PIN a[326]
    DIRECTION INPUT ;
    USE SIGNAL ;
    PORT
      LAYER M4 ;
        RECT  64.692 58.896 64.776 58.92 ;
    END
  END a[326]
  PIN a[327]
    DIRECTION INPUT ;
    USE SIGNAL ;
    PORT
      LAYER M4 ;
        RECT  64.692 58.992 64.776 59.016 ;
    END
  END a[327]
  PIN a[328]
    DIRECTION INPUT ;
    USE SIGNAL ;
    PORT
      LAYER M4 ;
        RECT  64.692 59.088 64.776 59.112 ;
    END
  END a[328]
  PIN a[329]
    DIRECTION INPUT ;
    USE SIGNAL ;
    PORT
      LAYER M4 ;
        RECT  64.692 59.184 64.776 59.208 ;
    END
  END a[329]
  PIN a[32]
    DIRECTION INPUT ;
    USE SIGNAL ;
    PORT
      LAYER M4 ;
        RECT  64.692 54.48 64.776 54.504 ;
    END
  END a[32]
  PIN a[330]
    DIRECTION INPUT ;
    USE SIGNAL ;
    PORT
      LAYER M4 ;
        RECT  64.692 59.28 64.776 59.304 ;
    END
  END a[330]
  PIN a[331]
    DIRECTION INPUT ;
    USE SIGNAL ;
    PORT
      LAYER M4 ;
        RECT  64.692 59.376 64.776 59.4 ;
    END
  END a[331]
  PIN a[332]
    DIRECTION INPUT ;
    USE SIGNAL ;
    PORT
      LAYER M4 ;
        RECT  64.692 59.472 64.776 59.496 ;
    END
  END a[332]
  PIN a[333]
    DIRECTION INPUT ;
    USE SIGNAL ;
    PORT
      LAYER M4 ;
        RECT  64.692 59.568 64.776 59.592 ;
    END
  END a[333]
  PIN a[334]
    DIRECTION INPUT ;
    USE SIGNAL ;
    PORT
      LAYER M4 ;
        RECT  64.692 59.664 64.776 59.688 ;
    END
  END a[334]
  PIN a[335]
    DIRECTION INPUT ;
    USE SIGNAL ;
    PORT
      LAYER M4 ;
        RECT  64.692 59.76 64.776 59.784 ;
    END
  END a[335]
  PIN a[336]
    DIRECTION INPUT ;
    USE SIGNAL ;
    PORT
      LAYER M4 ;
        RECT  64.692 59.856 64.776 59.88 ;
    END
  END a[336]
  PIN a[337]
    DIRECTION INPUT ;
    USE SIGNAL ;
    PORT
      LAYER M4 ;
        RECT  64.692 59.952 64.776 59.976 ;
    END
  END a[337]
  PIN a[338]
    DIRECTION INPUT ;
    USE SIGNAL ;
    PORT
      LAYER M4 ;
        RECT  64.692 60.048 64.776 60.072 ;
    END
  END a[338]
  PIN a[339]
    DIRECTION INPUT ;
    USE SIGNAL ;
    PORT
      LAYER M4 ;
        RECT  64.692 60.144 64.776 60.168 ;
    END
  END a[339]
  PIN a[33]
    DIRECTION INPUT ;
    USE SIGNAL ;
    PORT
      LAYER M4 ;
        RECT  64.692 54.576 64.776 54.6 ;
    END
  END a[33]
  PIN a[340]
    DIRECTION INPUT ;
    USE SIGNAL ;
    PORT
      LAYER M4 ;
        RECT  64.692 60.24 64.776 60.264 ;
    END
  END a[340]
  PIN a[341]
    DIRECTION INPUT ;
    USE SIGNAL ;
    PORT
      LAYER M4 ;
        RECT  64.692 60.336 64.776 60.36 ;
    END
  END a[341]
  PIN a[342]
    DIRECTION INPUT ;
    USE SIGNAL ;
    PORT
      LAYER M4 ;
        RECT  64.692 60.432 64.776 60.456 ;
    END
  END a[342]
  PIN a[343]
    DIRECTION INPUT ;
    USE SIGNAL ;
    PORT
      LAYER M4 ;
        RECT  64.692 60.528 64.776 60.552 ;
    END
  END a[343]
  PIN a[344]
    DIRECTION INPUT ;
    USE SIGNAL ;
    PORT
      LAYER M4 ;
        RECT  64.692 60.624 64.776 60.648 ;
    END
  END a[344]
  PIN a[345]
    DIRECTION INPUT ;
    USE SIGNAL ;
    PORT
      LAYER M4 ;
        RECT  64.692 60.72 64.776 60.744 ;
    END
  END a[345]
  PIN a[346]
    DIRECTION INPUT ;
    USE SIGNAL ;
    PORT
      LAYER M4 ;
        RECT  64.692 60.816 64.776 60.84 ;
    END
  END a[346]
  PIN a[347]
    DIRECTION INPUT ;
    USE SIGNAL ;
    PORT
      LAYER M4 ;
        RECT  64.692 60.912 64.776 60.936 ;
    END
  END a[347]
  PIN a[348]
    DIRECTION INPUT ;
    USE SIGNAL ;
    PORT
      LAYER M4 ;
        RECT  64.692 61.008 64.776 61.032 ;
    END
  END a[348]
  PIN a[349]
    DIRECTION INPUT ;
    USE SIGNAL ;
    PORT
      LAYER M4 ;
        RECT  64.692 61.104 64.776 61.128 ;
    END
  END a[349]
  PIN a[34]
    DIRECTION INPUT ;
    USE SIGNAL ;
    PORT
      LAYER M4 ;
        RECT  64.692 54.672 64.776 54.696 ;
    END
  END a[34]
  PIN a[350]
    DIRECTION INPUT ;
    USE SIGNAL ;
    PORT
      LAYER M4 ;
        RECT  64.692 61.2 64.776 61.224 ;
    END
  END a[350]
  PIN a[351]
    DIRECTION INPUT ;
    USE SIGNAL ;
    PORT
      LAYER M4 ;
        RECT  64.692 61.296 64.776 61.32 ;
    END
  END a[351]
  PIN a[352]
    DIRECTION INPUT ;
    USE SIGNAL ;
    PORT
      LAYER M4 ;
        RECT  64.692 64.464 64.776 64.488 ;
    END
  END a[352]
  PIN a[353]
    DIRECTION INPUT ;
    USE SIGNAL ;
    PORT
      LAYER M4 ;
        RECT  64.692 64.56 64.776 64.584 ;
    END
  END a[353]
  PIN a[354]
    DIRECTION INPUT ;
    USE SIGNAL ;
    PORT
      LAYER M4 ;
        RECT  64.692 64.656 64.776 64.68 ;
    END
  END a[354]
  PIN a[355]
    DIRECTION INPUT ;
    USE SIGNAL ;
    PORT
      LAYER M4 ;
        RECT  64.692 64.752 64.776 64.776 ;
    END
  END a[355]
  PIN a[356]
    DIRECTION INPUT ;
    USE SIGNAL ;
    PORT
      LAYER M4 ;
        RECT  64.692 64.848 64.776 64.872 ;
    END
  END a[356]
  PIN a[357]
    DIRECTION INPUT ;
    USE SIGNAL ;
    PORT
      LAYER M4 ;
        RECT  64.692 64.944 64.776 64.968 ;
    END
  END a[357]
  PIN a[358]
    DIRECTION INPUT ;
    USE SIGNAL ;
    PORT
      LAYER M4 ;
        RECT  64.692 65.04 64.776 65.064 ;
    END
  END a[358]
  PIN a[359]
    DIRECTION INPUT ;
    USE SIGNAL ;
    PORT
      LAYER M4 ;
        RECT  64.692 65.136 64.776 65.16 ;
    END
  END a[359]
  PIN a[35]
    DIRECTION INPUT ;
    USE SIGNAL ;
    PORT
      LAYER M4 ;
        RECT  64.692 54.768 64.776 54.792 ;
    END
  END a[35]
  PIN a[360]
    DIRECTION INPUT ;
    USE SIGNAL ;
    PORT
      LAYER M4 ;
        RECT  64.692 65.232 64.776 65.256 ;
    END
  END a[360]
  PIN a[361]
    DIRECTION INPUT ;
    USE SIGNAL ;
    PORT
      LAYER M4 ;
        RECT  64.692 65.328 64.776 65.352 ;
    END
  END a[361]
  PIN a[362]
    DIRECTION INPUT ;
    USE SIGNAL ;
    PORT
      LAYER M4 ;
        RECT  64.692 65.424 64.776 65.448 ;
    END
  END a[362]
  PIN a[363]
    DIRECTION INPUT ;
    USE SIGNAL ;
    PORT
      LAYER M4 ;
        RECT  64.692 65.52 64.776 65.544 ;
    END
  END a[363]
  PIN a[364]
    DIRECTION INPUT ;
    USE SIGNAL ;
    PORT
      LAYER M4 ;
        RECT  64.692 65.616 64.776 65.64 ;
    END
  END a[364]
  PIN a[365]
    DIRECTION INPUT ;
    USE SIGNAL ;
    PORT
      LAYER M4 ;
        RECT  64.692 65.712 64.776 65.736 ;
    END
  END a[365]
  PIN a[366]
    DIRECTION INPUT ;
    USE SIGNAL ;
    PORT
      LAYER M4 ;
        RECT  64.692 65.808 64.776 65.832 ;
    END
  END a[366]
  PIN a[367]
    DIRECTION INPUT ;
    USE SIGNAL ;
    PORT
      LAYER M4 ;
        RECT  64.692 65.904 64.776 65.928 ;
    END
  END a[367]
  PIN a[368]
    DIRECTION INPUT ;
    USE SIGNAL ;
    PORT
      LAYER M4 ;
        RECT  64.692 66 64.776 66.024 ;
    END
  END a[368]
  PIN a[369]
    DIRECTION INPUT ;
    USE SIGNAL ;
    PORT
      LAYER M4 ;
        RECT  64.692 66.096 64.776 66.12 ;
    END
  END a[369]
  PIN a[36]
    DIRECTION INPUT ;
    USE SIGNAL ;
    PORT
      LAYER M4 ;
        RECT  64.692 54.864 64.776 54.888 ;
    END
  END a[36]
  PIN a[370]
    DIRECTION INPUT ;
    USE SIGNAL ;
    PORT
      LAYER M4 ;
        RECT  64.692 66.192 64.776 66.216 ;
    END
  END a[370]
  PIN a[371]
    DIRECTION INPUT ;
    USE SIGNAL ;
    PORT
      LAYER M4 ;
        RECT  64.692 66.288 64.776 66.312 ;
    END
  END a[371]
  PIN a[372]
    DIRECTION INPUT ;
    USE SIGNAL ;
    PORT
      LAYER M4 ;
        RECT  64.692 66.384 64.776 66.408 ;
    END
  END a[372]
  PIN a[373]
    DIRECTION INPUT ;
    USE SIGNAL ;
    PORT
      LAYER M4 ;
        RECT  64.692 66.48 64.776 66.504 ;
    END
  END a[373]
  PIN a[374]
    DIRECTION INPUT ;
    USE SIGNAL ;
    PORT
      LAYER M4 ;
        RECT  64.692 66.576 64.776 66.6 ;
    END
  END a[374]
  PIN a[375]
    DIRECTION INPUT ;
    USE SIGNAL ;
    PORT
      LAYER M4 ;
        RECT  64.692 66.672 64.776 66.696 ;
    END
  END a[375]
  PIN a[376]
    DIRECTION INPUT ;
    USE SIGNAL ;
    PORT
      LAYER M4 ;
        RECT  64.692 66.768 64.776 66.792 ;
    END
  END a[376]
  PIN a[377]
    DIRECTION INPUT ;
    USE SIGNAL ;
    PORT
      LAYER M4 ;
        RECT  64.692 66.864 64.776 66.888 ;
    END
  END a[377]
  PIN a[378]
    DIRECTION INPUT ;
    USE SIGNAL ;
    PORT
      LAYER M4 ;
        RECT  64.692 66.96 64.776 66.984 ;
    END
  END a[378]
  PIN a[379]
    DIRECTION INPUT ;
    USE SIGNAL ;
    PORT
      LAYER M4 ;
        RECT  64.692 67.056 64.776 67.08 ;
    END
  END a[379]
  PIN a[37]
    DIRECTION INPUT ;
    USE SIGNAL ;
    PORT
      LAYER M4 ;
        RECT  64.692 54.96 64.776 54.984 ;
    END
  END a[37]
  PIN a[380]
    DIRECTION INPUT ;
    USE SIGNAL ;
    PORT
      LAYER M4 ;
        RECT  64.692 67.152 64.776 67.176 ;
    END
  END a[380]
  PIN a[381]
    DIRECTION INPUT ;
    USE SIGNAL ;
    PORT
      LAYER M4 ;
        RECT  64.692 67.248 64.776 67.272 ;
    END
  END a[381]
  PIN a[382]
    DIRECTION INPUT ;
    USE SIGNAL ;
    PORT
      LAYER M4 ;
        RECT  64.692 67.344 64.776 67.368 ;
    END
  END a[382]
  PIN a[383]
    DIRECTION INPUT ;
    USE SIGNAL ;
    PORT
      LAYER M4 ;
        RECT  64.692 67.44 64.776 67.464 ;
    END
  END a[383]
  PIN a[384]
    DIRECTION INPUT ;
    USE SIGNAL ;
    PORT
      LAYER M4 ;
        RECT  64.692 19.92 64.776 19.944 ;
    END
  END a[384]
  PIN a[385]
    DIRECTION INPUT ;
    USE SIGNAL ;
    PORT
      LAYER M4 ;
        RECT  64.692 20.016 64.776 20.04 ;
    END
  END a[385]
  PIN a[386]
    DIRECTION INPUT ;
    USE SIGNAL ;
    PORT
      LAYER M4 ;
        RECT  64.692 20.112 64.776 20.136 ;
    END
  END a[386]
  PIN a[387]
    DIRECTION INPUT ;
    USE SIGNAL ;
    PORT
      LAYER M4 ;
        RECT  64.692 20.208 64.776 20.232 ;
    END
  END a[387]
  PIN a[388]
    DIRECTION INPUT ;
    USE SIGNAL ;
    PORT
      LAYER M4 ;
        RECT  64.692 20.304 64.776 20.328 ;
    END
  END a[388]
  PIN a[389]
    DIRECTION INPUT ;
    USE SIGNAL ;
    PORT
      LAYER M4 ;
        RECT  64.692 20.4 64.776 20.424 ;
    END
  END a[389]
  PIN a[38]
    DIRECTION INPUT ;
    USE SIGNAL ;
    PORT
      LAYER M4 ;
        RECT  64.692 55.056 64.776 55.08 ;
    END
  END a[38]
  PIN a[390]
    DIRECTION INPUT ;
    USE SIGNAL ;
    PORT
      LAYER M4 ;
        RECT  64.692 20.496 64.776 20.52 ;
    END
  END a[390]
  PIN a[391]
    DIRECTION INPUT ;
    USE SIGNAL ;
    PORT
      LAYER M4 ;
        RECT  64.692 20.592 64.776 20.616 ;
    END
  END a[391]
  PIN a[392]
    DIRECTION INPUT ;
    USE SIGNAL ;
    PORT
      LAYER M4 ;
        RECT  64.692 20.688 64.776 20.712 ;
    END
  END a[392]
  PIN a[393]
    DIRECTION INPUT ;
    USE SIGNAL ;
    PORT
      LAYER M4 ;
        RECT  64.692 20.784 64.776 20.808 ;
    END
  END a[393]
  PIN a[394]
    DIRECTION INPUT ;
    USE SIGNAL ;
    PORT
      LAYER M4 ;
        RECT  64.692 20.88 64.776 20.904 ;
    END
  END a[394]
  PIN a[395]
    DIRECTION INPUT ;
    USE SIGNAL ;
    PORT
      LAYER M4 ;
        RECT  64.692 20.976 64.776 21 ;
    END
  END a[395]
  PIN a[396]
    DIRECTION INPUT ;
    USE SIGNAL ;
    PORT
      LAYER M4 ;
        RECT  64.692 21.072 64.776 21.096 ;
    END
  END a[396]
  PIN a[397]
    DIRECTION INPUT ;
    USE SIGNAL ;
    PORT
      LAYER M4 ;
        RECT  64.692 21.168 64.776 21.192 ;
    END
  END a[397]
  PIN a[398]
    DIRECTION INPUT ;
    USE SIGNAL ;
    PORT
      LAYER M4 ;
        RECT  64.692 21.264 64.776 21.288 ;
    END
  END a[398]
  PIN a[399]
    DIRECTION INPUT ;
    USE SIGNAL ;
    PORT
      LAYER M4 ;
        RECT  64.692 21.36 64.776 21.384 ;
    END
  END a[399]
  PIN a[39]
    DIRECTION INPUT ;
    USE SIGNAL ;
    PORT
      LAYER M4 ;
        RECT  64.692 55.152 64.776 55.176 ;
    END
  END a[39]
  PIN a[3]
    DIRECTION INPUT ;
    USE SIGNAL ;
    PORT
      LAYER M4 ;
        RECT  64.692 45.552 64.776 45.576 ;
    END
  END a[3]
  PIN a[400]
    DIRECTION INPUT ;
    USE SIGNAL ;
    PORT
      LAYER M4 ;
        RECT  64.692 21.456 64.776 21.48 ;
    END
  END a[400]
  PIN a[401]
    DIRECTION INPUT ;
    USE SIGNAL ;
    PORT
      LAYER M4 ;
        RECT  64.692 21.552 64.776 21.576 ;
    END
  END a[401]
  PIN a[402]
    DIRECTION INPUT ;
    USE SIGNAL ;
    PORT
      LAYER M4 ;
        RECT  64.692 21.648 64.776 21.672 ;
    END
  END a[402]
  PIN a[403]
    DIRECTION INPUT ;
    USE SIGNAL ;
    PORT
      LAYER M4 ;
        RECT  64.692 21.744 64.776 21.768 ;
    END
  END a[403]
  PIN a[404]
    DIRECTION INPUT ;
    USE SIGNAL ;
    PORT
      LAYER M4 ;
        RECT  64.692 21.84 64.776 21.864 ;
    END
  END a[404]
  PIN a[405]
    DIRECTION INPUT ;
    USE SIGNAL ;
    PORT
      LAYER M4 ;
        RECT  64.692 21.936 64.776 21.96 ;
    END
  END a[405]
  PIN a[406]
    DIRECTION INPUT ;
    USE SIGNAL ;
    PORT
      LAYER M4 ;
        RECT  64.692 22.032 64.776 22.056 ;
    END
  END a[406]
  PIN a[407]
    DIRECTION INPUT ;
    USE SIGNAL ;
    PORT
      LAYER M4 ;
        RECT  64.692 22.128 64.776 22.152 ;
    END
  END a[407]
  PIN a[408]
    DIRECTION INPUT ;
    USE SIGNAL ;
    PORT
      LAYER M4 ;
        RECT  64.692 22.224 64.776 22.248 ;
    END
  END a[408]
  PIN a[409]
    DIRECTION INPUT ;
    USE SIGNAL ;
    PORT
      LAYER M4 ;
        RECT  64.692 22.32 64.776 22.344 ;
    END
  END a[409]
  PIN a[40]
    DIRECTION INPUT ;
    USE SIGNAL ;
    PORT
      LAYER M4 ;
        RECT  64.692 55.248 64.776 55.272 ;
    END
  END a[40]
  PIN a[410]
    DIRECTION INPUT ;
    USE SIGNAL ;
    PORT
      LAYER M4 ;
        RECT  64.692 22.416 64.776 22.44 ;
    END
  END a[410]
  PIN a[411]
    DIRECTION INPUT ;
    USE SIGNAL ;
    PORT
      LAYER M4 ;
        RECT  64.692 22.512 64.776 22.536 ;
    END
  END a[411]
  PIN a[412]
    DIRECTION INPUT ;
    USE SIGNAL ;
    PORT
      LAYER M4 ;
        RECT  64.692 22.608 64.776 22.632 ;
    END
  END a[412]
  PIN a[413]
    DIRECTION INPUT ;
    USE SIGNAL ;
    PORT
      LAYER M4 ;
        RECT  64.692 22.704 64.776 22.728 ;
    END
  END a[413]
  PIN a[414]
    DIRECTION INPUT ;
    USE SIGNAL ;
    PORT
      LAYER M4 ;
        RECT  64.692 22.8 64.776 22.824 ;
    END
  END a[414]
  PIN a[415]
    DIRECTION INPUT ;
    USE SIGNAL ;
    PORT
      LAYER M4 ;
        RECT  64.692 22.896 64.776 22.92 ;
    END
  END a[415]
  PIN a[416]
    DIRECTION INPUT ;
    USE SIGNAL ;
    PORT
      LAYER M4 ;
        RECT  64.692 29.136 64.776 29.16 ;
    END
  END a[416]
  PIN a[417]
    DIRECTION INPUT ;
    USE SIGNAL ;
    PORT
      LAYER M4 ;
        RECT  64.692 29.232 64.776 29.256 ;
    END
  END a[417]
  PIN a[418]
    DIRECTION INPUT ;
    USE SIGNAL ;
    PORT
      LAYER M4 ;
        RECT  64.692 29.328 64.776 29.352 ;
    END
  END a[418]
  PIN a[419]
    DIRECTION INPUT ;
    USE SIGNAL ;
    PORT
      LAYER M4 ;
        RECT  64.692 29.424 64.776 29.448 ;
    END
  END a[419]
  PIN a[41]
    DIRECTION INPUT ;
    USE SIGNAL ;
    PORT
      LAYER M4 ;
        RECT  64.692 55.344 64.776 55.368 ;
    END
  END a[41]
  PIN a[420]
    DIRECTION INPUT ;
    USE SIGNAL ;
    PORT
      LAYER M4 ;
        RECT  64.692 29.52 64.776 29.544 ;
    END
  END a[420]
  PIN a[421]
    DIRECTION INPUT ;
    USE SIGNAL ;
    PORT
      LAYER M4 ;
        RECT  64.692 29.616 64.776 29.64 ;
    END
  END a[421]
  PIN a[422]
    DIRECTION INPUT ;
    USE SIGNAL ;
    PORT
      LAYER M4 ;
        RECT  64.692 29.712 64.776 29.736 ;
    END
  END a[422]
  PIN a[423]
    DIRECTION INPUT ;
    USE SIGNAL ;
    PORT
      LAYER M4 ;
        RECT  64.692 29.808 64.776 29.832 ;
    END
  END a[423]
  PIN a[424]
    DIRECTION INPUT ;
    USE SIGNAL ;
    PORT
      LAYER M4 ;
        RECT  64.692 29.904 64.776 29.928 ;
    END
  END a[424]
  PIN a[425]
    DIRECTION INPUT ;
    USE SIGNAL ;
    PORT
      LAYER M4 ;
        RECT  64.692 30 64.776 30.024 ;
    END
  END a[425]
  PIN a[426]
    DIRECTION INPUT ;
    USE SIGNAL ;
    PORT
      LAYER M4 ;
        RECT  64.692 30.096 64.776 30.12 ;
    END
  END a[426]
  PIN a[427]
    DIRECTION INPUT ;
    USE SIGNAL ;
    PORT
      LAYER M4 ;
        RECT  64.692 30.192 64.776 30.216 ;
    END
  END a[427]
  PIN a[428]
    DIRECTION INPUT ;
    USE SIGNAL ;
    PORT
      LAYER M4 ;
        RECT  64.692 30.288 64.776 30.312 ;
    END
  END a[428]
  PIN a[429]
    DIRECTION INPUT ;
    USE SIGNAL ;
    PORT
      LAYER M4 ;
        RECT  64.692 30.384 64.776 30.408 ;
    END
  END a[429]
  PIN a[42]
    DIRECTION INPUT ;
    USE SIGNAL ;
    PORT
      LAYER M4 ;
        RECT  64.692 55.44 64.776 55.464 ;
    END
  END a[42]
  PIN a[430]
    DIRECTION INPUT ;
    USE SIGNAL ;
    PORT
      LAYER M4 ;
        RECT  64.692 30.48 64.776 30.504 ;
    END
  END a[430]
  PIN a[431]
    DIRECTION INPUT ;
    USE SIGNAL ;
    PORT
      LAYER M4 ;
        RECT  64.692 30.576 64.776 30.6 ;
    END
  END a[431]
  PIN a[432]
    DIRECTION INPUT ;
    USE SIGNAL ;
    PORT
      LAYER M4 ;
        RECT  64.692 30.672 64.776 30.696 ;
    END
  END a[432]
  PIN a[433]
    DIRECTION INPUT ;
    USE SIGNAL ;
    PORT
      LAYER M4 ;
        RECT  64.692 30.768 64.776 30.792 ;
    END
  END a[433]
  PIN a[434]
    DIRECTION INPUT ;
    USE SIGNAL ;
    PORT
      LAYER M4 ;
        RECT  64.692 30.864 64.776 30.888 ;
    END
  END a[434]
  PIN a[435]
    DIRECTION INPUT ;
    USE SIGNAL ;
    PORT
      LAYER M4 ;
        RECT  64.692 30.96 64.776 30.984 ;
    END
  END a[435]
  PIN a[436]
    DIRECTION INPUT ;
    USE SIGNAL ;
    PORT
      LAYER M4 ;
        RECT  64.692 31.056 64.776 31.08 ;
    END
  END a[436]
  PIN a[437]
    DIRECTION INPUT ;
    USE SIGNAL ;
    PORT
      LAYER M4 ;
        RECT  64.692 31.152 64.776 31.176 ;
    END
  END a[437]
  PIN a[438]
    DIRECTION INPUT ;
    USE SIGNAL ;
    PORT
      LAYER M4 ;
        RECT  64.692 31.248 64.776 31.272 ;
    END
  END a[438]
  PIN a[439]
    DIRECTION INPUT ;
    USE SIGNAL ;
    PORT
      LAYER M4 ;
        RECT  64.692 31.344 64.776 31.368 ;
    END
  END a[439]
  PIN a[43]
    DIRECTION INPUT ;
    USE SIGNAL ;
    PORT
      LAYER M4 ;
        RECT  64.692 55.536 64.776 55.56 ;
    END
  END a[43]
  PIN a[440]
    DIRECTION INPUT ;
    USE SIGNAL ;
    PORT
      LAYER M4 ;
        RECT  64.692 31.44 64.776 31.464 ;
    END
  END a[440]
  PIN a[441]
    DIRECTION INPUT ;
    USE SIGNAL ;
    PORT
      LAYER M4 ;
        RECT  64.692 31.536 64.776 31.56 ;
    END
  END a[441]
  PIN a[442]
    DIRECTION INPUT ;
    USE SIGNAL ;
    PORT
      LAYER M4 ;
        RECT  64.692 31.632 64.776 31.656 ;
    END
  END a[442]
  PIN a[443]
    DIRECTION INPUT ;
    USE SIGNAL ;
    PORT
      LAYER M4 ;
        RECT  64.692 31.728 64.776 31.752 ;
    END
  END a[443]
  PIN a[444]
    DIRECTION INPUT ;
    USE SIGNAL ;
    PORT
      LAYER M4 ;
        RECT  64.692 31.824 64.776 31.848 ;
    END
  END a[444]
  PIN a[445]
    DIRECTION INPUT ;
    USE SIGNAL ;
    PORT
      LAYER M4 ;
        RECT  64.692 31.92 64.776 31.944 ;
    END
  END a[445]
  PIN a[446]
    DIRECTION INPUT ;
    USE SIGNAL ;
    PORT
      LAYER M4 ;
        RECT  64.692 32.016 64.776 32.04 ;
    END
  END a[446]
  PIN a[447]
    DIRECTION INPUT ;
    USE SIGNAL ;
    PORT
      LAYER M4 ;
        RECT  64.692 32.112 64.776 32.136 ;
    END
  END a[447]
  PIN a[448]
    DIRECTION INPUT ;
    USE SIGNAL ;
    PORT
      LAYER M4 ;
        RECT  64.692 35.28 64.776 35.304 ;
    END
  END a[448]
  PIN a[449]
    DIRECTION INPUT ;
    USE SIGNAL ;
    PORT
      LAYER M4 ;
        RECT  64.692 35.376 64.776 35.4 ;
    END
  END a[449]
  PIN a[44]
    DIRECTION INPUT ;
    USE SIGNAL ;
    PORT
      LAYER M4 ;
        RECT  64.692 55.632 64.776 55.656 ;
    END
  END a[44]
  PIN a[450]
    DIRECTION INPUT ;
    USE SIGNAL ;
    PORT
      LAYER M4 ;
        RECT  64.692 35.472 64.776 35.496 ;
    END
  END a[450]
  PIN a[451]
    DIRECTION INPUT ;
    USE SIGNAL ;
    PORT
      LAYER M4 ;
        RECT  64.692 35.568 64.776 35.592 ;
    END
  END a[451]
  PIN a[452]
    DIRECTION INPUT ;
    USE SIGNAL ;
    PORT
      LAYER M4 ;
        RECT  64.692 35.664 64.776 35.688 ;
    END
  END a[452]
  PIN a[453]
    DIRECTION INPUT ;
    USE SIGNAL ;
    PORT
      LAYER M4 ;
        RECT  64.692 35.76 64.776 35.784 ;
    END
  END a[453]
  PIN a[454]
    DIRECTION INPUT ;
    USE SIGNAL ;
    PORT
      LAYER M4 ;
        RECT  64.692 35.856 64.776 35.88 ;
    END
  END a[454]
  PIN a[455]
    DIRECTION INPUT ;
    USE SIGNAL ;
    PORT
      LAYER M4 ;
        RECT  64.692 35.952 64.776 35.976 ;
    END
  END a[455]
  PIN a[456]
    DIRECTION INPUT ;
    USE SIGNAL ;
    PORT
      LAYER M4 ;
        RECT  64.692 36.048 64.776 36.072 ;
    END
  END a[456]
  PIN a[457]
    DIRECTION INPUT ;
    USE SIGNAL ;
    PORT
      LAYER M4 ;
        RECT  64.692 36.144 64.776 36.168 ;
    END
  END a[457]
  PIN a[458]
    DIRECTION INPUT ;
    USE SIGNAL ;
    PORT
      LAYER M4 ;
        RECT  64.692 36.24 64.776 36.264 ;
    END
  END a[458]
  PIN a[459]
    DIRECTION INPUT ;
    USE SIGNAL ;
    PORT
      LAYER M4 ;
        RECT  64.692 36.336 64.776 36.36 ;
    END
  END a[459]
  PIN a[45]
    DIRECTION INPUT ;
    USE SIGNAL ;
    PORT
      LAYER M4 ;
        RECT  64.692 55.728 64.776 55.752 ;
    END
  END a[45]
  PIN a[460]
    DIRECTION INPUT ;
    USE SIGNAL ;
    PORT
      LAYER M4 ;
        RECT  64.692 36.432 64.776 36.456 ;
    END
  END a[460]
  PIN a[461]
    DIRECTION INPUT ;
    USE SIGNAL ;
    PORT
      LAYER M4 ;
        RECT  64.692 36.528 64.776 36.552 ;
    END
  END a[461]
  PIN a[462]
    DIRECTION INPUT ;
    USE SIGNAL ;
    PORT
      LAYER M4 ;
        RECT  64.692 36.624 64.776 36.648 ;
    END
  END a[462]
  PIN a[463]
    DIRECTION INPUT ;
    USE SIGNAL ;
    PORT
      LAYER M4 ;
        RECT  64.692 36.72 64.776 36.744 ;
    END
  END a[463]
  PIN a[464]
    DIRECTION INPUT ;
    USE SIGNAL ;
    PORT
      LAYER M4 ;
        RECT  64.692 36.816 64.776 36.84 ;
    END
  END a[464]
  PIN a[465]
    DIRECTION INPUT ;
    USE SIGNAL ;
    PORT
      LAYER M4 ;
        RECT  64.692 36.912 64.776 36.936 ;
    END
  END a[465]
  PIN a[466]
    DIRECTION INPUT ;
    USE SIGNAL ;
    PORT
      LAYER M4 ;
        RECT  64.692 37.008 64.776 37.032 ;
    END
  END a[466]
  PIN a[467]
    DIRECTION INPUT ;
    USE SIGNAL ;
    PORT
      LAYER M4 ;
        RECT  64.692 37.104 64.776 37.128 ;
    END
  END a[467]
  PIN a[468]
    DIRECTION INPUT ;
    USE SIGNAL ;
    PORT
      LAYER M4 ;
        RECT  64.692 37.2 64.776 37.224 ;
    END
  END a[468]
  PIN a[469]
    DIRECTION INPUT ;
    USE SIGNAL ;
    PORT
      LAYER M4 ;
        RECT  64.692 37.296 64.776 37.32 ;
    END
  END a[469]
  PIN a[46]
    DIRECTION INPUT ;
    USE SIGNAL ;
    PORT
      LAYER M4 ;
        RECT  64.692 55.824 64.776 55.848 ;
    END
  END a[46]
  PIN a[470]
    DIRECTION INPUT ;
    USE SIGNAL ;
    PORT
      LAYER M4 ;
        RECT  64.692 37.392 64.776 37.416 ;
    END
  END a[470]
  PIN a[471]
    DIRECTION INPUT ;
    USE SIGNAL ;
    PORT
      LAYER M4 ;
        RECT  64.692 37.488 64.776 37.512 ;
    END
  END a[471]
  PIN a[472]
    DIRECTION INPUT ;
    USE SIGNAL ;
    PORT
      LAYER M4 ;
        RECT  64.692 37.584 64.776 37.608 ;
    END
  END a[472]
  PIN a[473]
    DIRECTION INPUT ;
    USE SIGNAL ;
    PORT
      LAYER M4 ;
        RECT  64.692 37.68 64.776 37.704 ;
    END
  END a[473]
  PIN a[474]
    DIRECTION INPUT ;
    USE SIGNAL ;
    PORT
      LAYER M4 ;
        RECT  64.692 37.776 64.776 37.8 ;
    END
  END a[474]
  PIN a[475]
    DIRECTION INPUT ;
    USE SIGNAL ;
    PORT
      LAYER M4 ;
        RECT  64.692 37.872 64.776 37.896 ;
    END
  END a[475]
  PIN a[476]
    DIRECTION INPUT ;
    USE SIGNAL ;
    PORT
      LAYER M4 ;
        RECT  64.692 37.968 64.776 37.992 ;
    END
  END a[476]
  PIN a[477]
    DIRECTION INPUT ;
    USE SIGNAL ;
    PORT
      LAYER M4 ;
        RECT  64.692 38.064 64.776 38.088 ;
    END
  END a[477]
  PIN a[478]
    DIRECTION INPUT ;
    USE SIGNAL ;
    PORT
      LAYER M4 ;
        RECT  64.692 38.16 64.776 38.184 ;
    END
  END a[478]
  PIN a[479]
    DIRECTION INPUT ;
    USE SIGNAL ;
    PORT
      LAYER M4 ;
        RECT  64.692 38.256 64.776 38.28 ;
    END
  END a[479]
  PIN a[47]
    DIRECTION INPUT ;
    USE SIGNAL ;
    PORT
      LAYER M4 ;
        RECT  64.692 55.92 64.776 55.944 ;
    END
  END a[47]
  PIN a[480]
    DIRECTION INPUT ;
    USE SIGNAL ;
    PORT
      LAYER M4 ;
        RECT  64.692 32.208 64.776 32.232 ;
    END
  END a[480]
  PIN a[481]
    DIRECTION INPUT ;
    USE SIGNAL ;
    PORT
      LAYER M4 ;
        RECT  64.692 32.304 64.776 32.328 ;
    END
  END a[481]
  PIN a[482]
    DIRECTION INPUT ;
    USE SIGNAL ;
    PORT
      LAYER M4 ;
        RECT  64.692 32.4 64.776 32.424 ;
    END
  END a[482]
  PIN a[483]
    DIRECTION INPUT ;
    USE SIGNAL ;
    PORT
      LAYER M4 ;
        RECT  64.692 32.496 64.776 32.52 ;
    END
  END a[483]
  PIN a[484]
    DIRECTION INPUT ;
    USE SIGNAL ;
    PORT
      LAYER M4 ;
        RECT  64.692 32.592 64.776 32.616 ;
    END
  END a[484]
  PIN a[485]
    DIRECTION INPUT ;
    USE SIGNAL ;
    PORT
      LAYER M4 ;
        RECT  64.692 32.688 64.776 32.712 ;
    END
  END a[485]
  PIN a[486]
    DIRECTION INPUT ;
    USE SIGNAL ;
    PORT
      LAYER M4 ;
        RECT  64.692 32.784 64.776 32.808 ;
    END
  END a[486]
  PIN a[487]
    DIRECTION INPUT ;
    USE SIGNAL ;
    PORT
      LAYER M4 ;
        RECT  64.692 32.88 64.776 32.904 ;
    END
  END a[487]
  PIN a[488]
    DIRECTION INPUT ;
    USE SIGNAL ;
    PORT
      LAYER M4 ;
        RECT  64.692 32.976 64.776 33 ;
    END
  END a[488]
  PIN a[489]
    DIRECTION INPUT ;
    USE SIGNAL ;
    PORT
      LAYER M4 ;
        RECT  64.692 33.072 64.776 33.096 ;
    END
  END a[489]
  PIN a[48]
    DIRECTION INPUT ;
    USE SIGNAL ;
    PORT
      LAYER M4 ;
        RECT  64.692 56.016 64.776 56.04 ;
    END
  END a[48]
  PIN a[490]
    DIRECTION INPUT ;
    USE SIGNAL ;
    PORT
      LAYER M4 ;
        RECT  64.692 33.168 64.776 33.192 ;
    END
  END a[490]
  PIN a[491]
    DIRECTION INPUT ;
    USE SIGNAL ;
    PORT
      LAYER M4 ;
        RECT  64.692 33.264 64.776 33.288 ;
    END
  END a[491]
  PIN a[492]
    DIRECTION INPUT ;
    USE SIGNAL ;
    PORT
      LAYER M4 ;
        RECT  64.692 33.36 64.776 33.384 ;
    END
  END a[492]
  PIN a[493]
    DIRECTION INPUT ;
    USE SIGNAL ;
    PORT
      LAYER M4 ;
        RECT  64.692 33.456 64.776 33.48 ;
    END
  END a[493]
  PIN a[494]
    DIRECTION INPUT ;
    USE SIGNAL ;
    PORT
      LAYER M4 ;
        RECT  64.692 33.552 64.776 33.576 ;
    END
  END a[494]
  PIN a[495]
    DIRECTION INPUT ;
    USE SIGNAL ;
    PORT
      LAYER M4 ;
        RECT  64.692 33.648 64.776 33.672 ;
    END
  END a[495]
  PIN a[496]
    DIRECTION INPUT ;
    USE SIGNAL ;
    PORT
      LAYER M4 ;
        RECT  64.692 33.744 64.776 33.768 ;
    END
  END a[496]
  PIN a[497]
    DIRECTION INPUT ;
    USE SIGNAL ;
    PORT
      LAYER M4 ;
        RECT  64.692 33.84 64.776 33.864 ;
    END
  END a[497]
  PIN a[498]
    DIRECTION INPUT ;
    USE SIGNAL ;
    PORT
      LAYER M4 ;
        RECT  64.692 33.936 64.776 33.96 ;
    END
  END a[498]
  PIN a[499]
    DIRECTION INPUT ;
    USE SIGNAL ;
    PORT
      LAYER M4 ;
        RECT  64.692 34.032 64.776 34.056 ;
    END
  END a[499]
  PIN a[49]
    DIRECTION INPUT ;
    USE SIGNAL ;
    PORT
      LAYER M4 ;
        RECT  64.692 56.112 64.776 56.136 ;
    END
  END a[49]
  PIN a[4]
    DIRECTION INPUT ;
    USE SIGNAL ;
    PORT
      LAYER M4 ;
        RECT  64.692 45.648 64.776 45.672 ;
    END
  END a[4]
  PIN a[500]
    DIRECTION INPUT ;
    USE SIGNAL ;
    PORT
      LAYER M4 ;
        RECT  64.692 34.128 64.776 34.152 ;
    END
  END a[500]
  PIN a[501]
    DIRECTION INPUT ;
    USE SIGNAL ;
    PORT
      LAYER M4 ;
        RECT  64.692 34.224 64.776 34.248 ;
    END
  END a[501]
  PIN a[502]
    DIRECTION INPUT ;
    USE SIGNAL ;
    PORT
      LAYER M4 ;
        RECT  64.692 34.32 64.776 34.344 ;
    END
  END a[502]
  PIN a[503]
    DIRECTION INPUT ;
    USE SIGNAL ;
    PORT
      LAYER M4 ;
        RECT  64.692 34.416 64.776 34.44 ;
    END
  END a[503]
  PIN a[504]
    DIRECTION INPUT ;
    USE SIGNAL ;
    PORT
      LAYER M4 ;
        RECT  64.692 34.512 64.776 34.536 ;
    END
  END a[504]
  PIN a[505]
    DIRECTION INPUT ;
    USE SIGNAL ;
    PORT
      LAYER M4 ;
        RECT  64.692 34.608 64.776 34.632 ;
    END
  END a[505]
  PIN a[506]
    DIRECTION INPUT ;
    USE SIGNAL ;
    PORT
      LAYER M4 ;
        RECT  64.692 34.704 64.776 34.728 ;
    END
  END a[506]
  PIN a[507]
    DIRECTION INPUT ;
    USE SIGNAL ;
    PORT
      LAYER M4 ;
        RECT  64.692 34.8 64.776 34.824 ;
    END
  END a[507]
  PIN a[508]
    DIRECTION INPUT ;
    USE SIGNAL ;
    PORT
      LAYER M4 ;
        RECT  64.692 34.896 64.776 34.92 ;
    END
  END a[508]
  PIN a[509]
    DIRECTION INPUT ;
    USE SIGNAL ;
    PORT
      LAYER M4 ;
        RECT  64.692 34.992 64.776 35.016 ;
    END
  END a[509]
  PIN a[50]
    DIRECTION INPUT ;
    USE SIGNAL ;
    PORT
      LAYER M4 ;
        RECT  64.692 56.208 64.776 56.232 ;
    END
  END a[50]
  PIN a[510]
    DIRECTION INPUT ;
    USE SIGNAL ;
    PORT
      LAYER M4 ;
        RECT  64.692 35.088 64.776 35.112 ;
    END
  END a[510]
  PIN a[511]
    DIRECTION INPUT ;
    USE SIGNAL ;
    PORT
      LAYER M4 ;
        RECT  64.692 35.184 64.776 35.208 ;
    END
  END a[511]
  PIN a[512]
    DIRECTION INPUT ;
    USE SIGNAL ;
    PORT
      LAYER M4 ;
        RECT  64.692 26.064 64.776 26.088 ;
    END
  END a[512]
  PIN a[513]
    DIRECTION INPUT ;
    USE SIGNAL ;
    PORT
      LAYER M4 ;
        RECT  64.692 26.16 64.776 26.184 ;
    END
  END a[513]
  PIN a[514]
    DIRECTION INPUT ;
    USE SIGNAL ;
    PORT
      LAYER M4 ;
        RECT  64.692 26.256 64.776 26.28 ;
    END
  END a[514]
  PIN a[515]
    DIRECTION INPUT ;
    USE SIGNAL ;
    PORT
      LAYER M4 ;
        RECT  64.692 26.352 64.776 26.376 ;
    END
  END a[515]
  PIN a[516]
    DIRECTION INPUT ;
    USE SIGNAL ;
    PORT
      LAYER M4 ;
        RECT  64.692 26.448 64.776 26.472 ;
    END
  END a[516]
  PIN a[517]
    DIRECTION INPUT ;
    USE SIGNAL ;
    PORT
      LAYER M4 ;
        RECT  64.692 26.544 64.776 26.568 ;
    END
  END a[517]
  PIN a[518]
    DIRECTION INPUT ;
    USE SIGNAL ;
    PORT
      LAYER M4 ;
        RECT  64.692 26.64 64.776 26.664 ;
    END
  END a[518]
  PIN a[519]
    DIRECTION INPUT ;
    USE SIGNAL ;
    PORT
      LAYER M4 ;
        RECT  64.692 26.736 64.776 26.76 ;
    END
  END a[519]
  PIN a[51]
    DIRECTION INPUT ;
    USE SIGNAL ;
    PORT
      LAYER M4 ;
        RECT  64.692 56.304 64.776 56.328 ;
    END
  END a[51]
  PIN a[520]
    DIRECTION INPUT ;
    USE SIGNAL ;
    PORT
      LAYER M4 ;
        RECT  64.692 26.832 64.776 26.856 ;
    END
  END a[520]
  PIN a[521]
    DIRECTION INPUT ;
    USE SIGNAL ;
    PORT
      LAYER M4 ;
        RECT  64.692 26.928 64.776 26.952 ;
    END
  END a[521]
  PIN a[522]
    DIRECTION INPUT ;
    USE SIGNAL ;
    PORT
      LAYER M4 ;
        RECT  64.692 27.024 64.776 27.048 ;
    END
  END a[522]
  PIN a[523]
    DIRECTION INPUT ;
    USE SIGNAL ;
    PORT
      LAYER M4 ;
        RECT  64.692 27.12 64.776 27.144 ;
    END
  END a[523]
  PIN a[524]
    DIRECTION INPUT ;
    USE SIGNAL ;
    PORT
      LAYER M4 ;
        RECT  64.692 27.216 64.776 27.24 ;
    END
  END a[524]
  PIN a[525]
    DIRECTION INPUT ;
    USE SIGNAL ;
    PORT
      LAYER M4 ;
        RECT  64.692 27.312 64.776 27.336 ;
    END
  END a[525]
  PIN a[526]
    DIRECTION INPUT ;
    USE SIGNAL ;
    PORT
      LAYER M4 ;
        RECT  64.692 27.408 64.776 27.432 ;
    END
  END a[526]
  PIN a[527]
    DIRECTION INPUT ;
    USE SIGNAL ;
    PORT
      LAYER M4 ;
        RECT  64.692 27.504 64.776 27.528 ;
    END
  END a[527]
  PIN a[528]
    DIRECTION INPUT ;
    USE SIGNAL ;
    PORT
      LAYER M4 ;
        RECT  64.692 27.6 64.776 27.624 ;
    END
  END a[528]
  PIN a[529]
    DIRECTION INPUT ;
    USE SIGNAL ;
    PORT
      LAYER M4 ;
        RECT  64.692 27.696 64.776 27.72 ;
    END
  END a[529]
  PIN a[52]
    DIRECTION INPUT ;
    USE SIGNAL ;
    PORT
      LAYER M4 ;
        RECT  64.692 56.4 64.776 56.424 ;
    END
  END a[52]
  PIN a[530]
    DIRECTION INPUT ;
    USE SIGNAL ;
    PORT
      LAYER M4 ;
        RECT  64.692 27.792 64.776 27.816 ;
    END
  END a[530]
  PIN a[531]
    DIRECTION INPUT ;
    USE SIGNAL ;
    PORT
      LAYER M4 ;
        RECT  64.692 27.888 64.776 27.912 ;
    END
  END a[531]
  PIN a[532]
    DIRECTION INPUT ;
    USE SIGNAL ;
    PORT
      LAYER M4 ;
        RECT  64.692 27.984 64.776 28.008 ;
    END
  END a[532]
  PIN a[533]
    DIRECTION INPUT ;
    USE SIGNAL ;
    PORT
      LAYER M4 ;
        RECT  64.692 28.08 64.776 28.104 ;
    END
  END a[533]
  PIN a[534]
    DIRECTION INPUT ;
    USE SIGNAL ;
    PORT
      LAYER M4 ;
        RECT  64.692 28.176 64.776 28.2 ;
    END
  END a[534]
  PIN a[535]
    DIRECTION INPUT ;
    USE SIGNAL ;
    PORT
      LAYER M4 ;
        RECT  64.692 28.272 64.776 28.296 ;
    END
  END a[535]
  PIN a[536]
    DIRECTION INPUT ;
    USE SIGNAL ;
    PORT
      LAYER M4 ;
        RECT  64.692 28.368 64.776 28.392 ;
    END
  END a[536]
  PIN a[537]
    DIRECTION INPUT ;
    USE SIGNAL ;
    PORT
      LAYER M4 ;
        RECT  64.692 28.464 64.776 28.488 ;
    END
  END a[537]
  PIN a[538]
    DIRECTION INPUT ;
    USE SIGNAL ;
    PORT
      LAYER M4 ;
        RECT  64.692 28.56 64.776 28.584 ;
    END
  END a[538]
  PIN a[539]
    DIRECTION INPUT ;
    USE SIGNAL ;
    PORT
      LAYER M4 ;
        RECT  64.692 28.656 64.776 28.68 ;
    END
  END a[539]
  PIN a[53]
    DIRECTION INPUT ;
    USE SIGNAL ;
    PORT
      LAYER M4 ;
        RECT  64.692 56.496 64.776 56.52 ;
    END
  END a[53]
  PIN a[540]
    DIRECTION INPUT ;
    USE SIGNAL ;
    PORT
      LAYER M4 ;
        RECT  64.692 28.752 64.776 28.776 ;
    END
  END a[540]
  PIN a[541]
    DIRECTION INPUT ;
    USE SIGNAL ;
    PORT
      LAYER M4 ;
        RECT  64.692 28.848 64.776 28.872 ;
    END
  END a[541]
  PIN a[542]
    DIRECTION INPUT ;
    USE SIGNAL ;
    PORT
      LAYER M4 ;
        RECT  64.692 28.944 64.776 28.968 ;
    END
  END a[542]
  PIN a[543]
    DIRECTION INPUT ;
    USE SIGNAL ;
    PORT
      LAYER M4 ;
        RECT  64.692 29.04 64.776 29.064 ;
    END
  END a[543]
  PIN a[544]
    DIRECTION INPUT ;
    USE SIGNAL ;
    PORT
      LAYER M4 ;
        RECT  64.692 22.992 64.776 23.016 ;
    END
  END a[544]
  PIN a[545]
    DIRECTION INPUT ;
    USE SIGNAL ;
    PORT
      LAYER M4 ;
        RECT  64.692 23.088 64.776 23.112 ;
    END
  END a[545]
  PIN a[546]
    DIRECTION INPUT ;
    USE SIGNAL ;
    PORT
      LAYER M4 ;
        RECT  64.692 23.184 64.776 23.208 ;
    END
  END a[546]
  PIN a[547]
    DIRECTION INPUT ;
    USE SIGNAL ;
    PORT
      LAYER M4 ;
        RECT  64.692 23.28 64.776 23.304 ;
    END
  END a[547]
  PIN a[548]
    DIRECTION INPUT ;
    USE SIGNAL ;
    PORT
      LAYER M4 ;
        RECT  64.692 23.376 64.776 23.4 ;
    END
  END a[548]
  PIN a[549]
    DIRECTION INPUT ;
    USE SIGNAL ;
    PORT
      LAYER M4 ;
        RECT  64.692 23.472 64.776 23.496 ;
    END
  END a[549]
  PIN a[54]
    DIRECTION INPUT ;
    USE SIGNAL ;
    PORT
      LAYER M4 ;
        RECT  64.692 56.592 64.776 56.616 ;
    END
  END a[54]
  PIN a[550]
    DIRECTION INPUT ;
    USE SIGNAL ;
    PORT
      LAYER M4 ;
        RECT  64.692 23.568 64.776 23.592 ;
    END
  END a[550]
  PIN a[551]
    DIRECTION INPUT ;
    USE SIGNAL ;
    PORT
      LAYER M4 ;
        RECT  64.692 23.664 64.776 23.688 ;
    END
  END a[551]
  PIN a[552]
    DIRECTION INPUT ;
    USE SIGNAL ;
    PORT
      LAYER M4 ;
        RECT  64.692 23.76 64.776 23.784 ;
    END
  END a[552]
  PIN a[553]
    DIRECTION INPUT ;
    USE SIGNAL ;
    PORT
      LAYER M4 ;
        RECT  64.692 23.856 64.776 23.88 ;
    END
  END a[553]
  PIN a[554]
    DIRECTION INPUT ;
    USE SIGNAL ;
    PORT
      LAYER M4 ;
        RECT  64.692 23.952 64.776 23.976 ;
    END
  END a[554]
  PIN a[555]
    DIRECTION INPUT ;
    USE SIGNAL ;
    PORT
      LAYER M4 ;
        RECT  64.692 24.048 64.776 24.072 ;
    END
  END a[555]
  PIN a[556]
    DIRECTION INPUT ;
    USE SIGNAL ;
    PORT
      LAYER M4 ;
        RECT  64.692 24.144 64.776 24.168 ;
    END
  END a[556]
  PIN a[557]
    DIRECTION INPUT ;
    USE SIGNAL ;
    PORT
      LAYER M4 ;
        RECT  64.692 24.24 64.776 24.264 ;
    END
  END a[557]
  PIN a[558]
    DIRECTION INPUT ;
    USE SIGNAL ;
    PORT
      LAYER M4 ;
        RECT  64.692 24.336 64.776 24.36 ;
    END
  END a[558]
  PIN a[559]
    DIRECTION INPUT ;
    USE SIGNAL ;
    PORT
      LAYER M4 ;
        RECT  64.692 24.432 64.776 24.456 ;
    END
  END a[559]
  PIN a[55]
    DIRECTION INPUT ;
    USE SIGNAL ;
    PORT
      LAYER M4 ;
        RECT  64.692 56.688 64.776 56.712 ;
    END
  END a[55]
  PIN a[560]
    DIRECTION INPUT ;
    USE SIGNAL ;
    PORT
      LAYER M4 ;
        RECT  64.692 24.528 64.776 24.552 ;
    END
  END a[560]
  PIN a[561]
    DIRECTION INPUT ;
    USE SIGNAL ;
    PORT
      LAYER M4 ;
        RECT  64.692 24.624 64.776 24.648 ;
    END
  END a[561]
  PIN a[562]
    DIRECTION INPUT ;
    USE SIGNAL ;
    PORT
      LAYER M4 ;
        RECT  64.692 24.72 64.776 24.744 ;
    END
  END a[562]
  PIN a[563]
    DIRECTION INPUT ;
    USE SIGNAL ;
    PORT
      LAYER M4 ;
        RECT  64.692 24.816 64.776 24.84 ;
    END
  END a[563]
  PIN a[564]
    DIRECTION INPUT ;
    USE SIGNAL ;
    PORT
      LAYER M4 ;
        RECT  64.692 24.912 64.776 24.936 ;
    END
  END a[564]
  PIN a[565]
    DIRECTION INPUT ;
    USE SIGNAL ;
    PORT
      LAYER M4 ;
        RECT  64.692 25.008 64.776 25.032 ;
    END
  END a[565]
  PIN a[566]
    DIRECTION INPUT ;
    USE SIGNAL ;
    PORT
      LAYER M4 ;
        RECT  64.692 25.104 64.776 25.128 ;
    END
  END a[566]
  PIN a[567]
    DIRECTION INPUT ;
    USE SIGNAL ;
    PORT
      LAYER M4 ;
        RECT  64.692 25.2 64.776 25.224 ;
    END
  END a[567]
  PIN a[568]
    DIRECTION INPUT ;
    USE SIGNAL ;
    PORT
      LAYER M4 ;
        RECT  64.692 25.296 64.776 25.32 ;
    END
  END a[568]
  PIN a[569]
    DIRECTION INPUT ;
    USE SIGNAL ;
    PORT
      LAYER M4 ;
        RECT  64.692 25.392 64.776 25.416 ;
    END
  END a[569]
  PIN a[56]
    DIRECTION INPUT ;
    USE SIGNAL ;
    PORT
      LAYER M4 ;
        RECT  64.692 56.784 64.776 56.808 ;
    END
  END a[56]
  PIN a[570]
    DIRECTION INPUT ;
    USE SIGNAL ;
    PORT
      LAYER M4 ;
        RECT  64.692 25.488 64.776 25.512 ;
    END
  END a[570]
  PIN a[571]
    DIRECTION INPUT ;
    USE SIGNAL ;
    PORT
      LAYER M4 ;
        RECT  64.692 25.584 64.776 25.608 ;
    END
  END a[571]
  PIN a[572]
    DIRECTION INPUT ;
    USE SIGNAL ;
    PORT
      LAYER M4 ;
        RECT  64.692 25.68 64.776 25.704 ;
    END
  END a[572]
  PIN a[573]
    DIRECTION INPUT ;
    USE SIGNAL ;
    PORT
      LAYER M4 ;
        RECT  64.692 25.776 64.776 25.8 ;
    END
  END a[573]
  PIN a[574]
    DIRECTION INPUT ;
    USE SIGNAL ;
    PORT
      LAYER M4 ;
        RECT  64.692 25.872 64.776 25.896 ;
    END
  END a[574]
  PIN a[575]
    DIRECTION INPUT ;
    USE SIGNAL ;
    PORT
      LAYER M4 ;
        RECT  64.692 25.968 64.776 25.992 ;
    END
  END a[575]
  PIN a[576]
    DIRECTION INPUT ;
    USE SIGNAL ;
    PORT
      LAYER M4 ;
        RECT  64.692 77.52 64.776 77.544 ;
    END
  END a[576]
  PIN a[577]
    DIRECTION INPUT ;
    USE SIGNAL ;
    PORT
      LAYER M4 ;
        RECT  64.692 77.616 64.776 77.64 ;
    END
  END a[577]
  PIN a[578]
    DIRECTION INPUT ;
    USE SIGNAL ;
    PORT
      LAYER M4 ;
        RECT  64.692 77.712 64.776 77.736 ;
    END
  END a[578]
  PIN a[579]
    DIRECTION INPUT ;
    USE SIGNAL ;
    PORT
      LAYER M4 ;
        RECT  64.692 77.808 64.776 77.832 ;
    END
  END a[579]
  PIN a[57]
    DIRECTION INPUT ;
    USE SIGNAL ;
    PORT
      LAYER M4 ;
        RECT  64.692 56.88 64.776 56.904 ;
    END
  END a[57]
  PIN a[580]
    DIRECTION INPUT ;
    USE SIGNAL ;
    PORT
      LAYER M4 ;
        RECT  64.692 77.904 64.776 77.928 ;
    END
  END a[580]
  PIN a[581]
    DIRECTION INPUT ;
    USE SIGNAL ;
    PORT
      LAYER M4 ;
        RECT  64.692 78 64.776 78.024 ;
    END
  END a[581]
  PIN a[582]
    DIRECTION INPUT ;
    USE SIGNAL ;
    PORT
      LAYER M4 ;
        RECT  64.692 78.096 64.776 78.12 ;
    END
  END a[582]
  PIN a[583]
    DIRECTION INPUT ;
    USE SIGNAL ;
    PORT
      LAYER M4 ;
        RECT  64.692 78.192 64.776 78.216 ;
    END
  END a[583]
  PIN a[584]
    DIRECTION INPUT ;
    USE SIGNAL ;
    PORT
      LAYER M4 ;
        RECT  64.692 78.288 64.776 78.312 ;
    END
  END a[584]
  PIN a[585]
    DIRECTION INPUT ;
    USE SIGNAL ;
    PORT
      LAYER M4 ;
        RECT  64.692 78.384 64.776 78.408 ;
    END
  END a[585]
  PIN a[586]
    DIRECTION INPUT ;
    USE SIGNAL ;
    PORT
      LAYER M4 ;
        RECT  64.692 78.48 64.776 78.504 ;
    END
  END a[586]
  PIN a[587]
    DIRECTION INPUT ;
    USE SIGNAL ;
    PORT
      LAYER M4 ;
        RECT  64.692 78.576 64.776 78.6 ;
    END
  END a[587]
  PIN a[588]
    DIRECTION INPUT ;
    USE SIGNAL ;
    PORT
      LAYER M4 ;
        RECT  64.692 78.672 64.776 78.696 ;
    END
  END a[588]
  PIN a[589]
    DIRECTION INPUT ;
    USE SIGNAL ;
    PORT
      LAYER M4 ;
        RECT  64.692 78.768 64.776 78.792 ;
    END
  END a[589]
  PIN a[58]
    DIRECTION INPUT ;
    USE SIGNAL ;
    PORT
      LAYER M4 ;
        RECT  64.692 56.976 64.776 57 ;
    END
  END a[58]
  PIN a[590]
    DIRECTION INPUT ;
    USE SIGNAL ;
    PORT
      LAYER M4 ;
        RECT  64.692 78.864 64.776 78.888 ;
    END
  END a[590]
  PIN a[591]
    DIRECTION INPUT ;
    USE SIGNAL ;
    PORT
      LAYER M4 ;
        RECT  64.692 78.96 64.776 78.984 ;
    END
  END a[591]
  PIN a[592]
    DIRECTION INPUT ;
    USE SIGNAL ;
    PORT
      LAYER M4 ;
        RECT  64.692 79.056 64.776 79.08 ;
    END
  END a[592]
  PIN a[593]
    DIRECTION INPUT ;
    USE SIGNAL ;
    PORT
      LAYER M4 ;
        RECT  64.692 79.152 64.776 79.176 ;
    END
  END a[593]
  PIN a[594]
    DIRECTION INPUT ;
    USE SIGNAL ;
    PORT
      LAYER M4 ;
        RECT  64.692 79.248 64.776 79.272 ;
    END
  END a[594]
  PIN a[595]
    DIRECTION INPUT ;
    USE SIGNAL ;
    PORT
      LAYER M4 ;
        RECT  64.692 79.344 64.776 79.368 ;
    END
  END a[595]
  PIN a[596]
    DIRECTION INPUT ;
    USE SIGNAL ;
    PORT
      LAYER M4 ;
        RECT  64.692 79.44 64.776 79.464 ;
    END
  END a[596]
  PIN a[597]
    DIRECTION INPUT ;
    USE SIGNAL ;
    PORT
      LAYER M4 ;
        RECT  64.692 79.536 64.776 79.56 ;
    END
  END a[597]
  PIN a[598]
    DIRECTION INPUT ;
    USE SIGNAL ;
    PORT
      LAYER M4 ;
        RECT  64.692 79.632 64.776 79.656 ;
    END
  END a[598]
  PIN a[599]
    DIRECTION INPUT ;
    USE SIGNAL ;
    PORT
      LAYER M4 ;
        RECT  64.692 79.728 64.776 79.752 ;
    END
  END a[599]
  PIN a[59]
    DIRECTION INPUT ;
    USE SIGNAL ;
    PORT
      LAYER M4 ;
        RECT  64.692 57.072 64.776 57.096 ;
    END
  END a[59]
  PIN a[5]
    DIRECTION INPUT ;
    USE SIGNAL ;
    PORT
      LAYER M4 ;
        RECT  64.692 45.744 64.776 45.768 ;
    END
  END a[5]
  PIN a[60]
    DIRECTION INPUT ;
    USE SIGNAL ;
    PORT
      LAYER M4 ;
        RECT  64.692 57.168 64.776 57.192 ;
    END
  END a[60]
  PIN a[61]
    DIRECTION INPUT ;
    USE SIGNAL ;
    PORT
      LAYER M4 ;
        RECT  64.692 57.264 64.776 57.288 ;
    END
  END a[61]
  PIN a[62]
    DIRECTION INPUT ;
    USE SIGNAL ;
    PORT
      LAYER M4 ;
        RECT  64.692 57.36 64.776 57.384 ;
    END
  END a[62]
  PIN a[63]
    DIRECTION INPUT ;
    USE SIGNAL ;
    PORT
      LAYER M4 ;
        RECT  64.692 57.456 64.776 57.48 ;
    END
  END a[63]
  PIN a[64]
    DIRECTION INPUT ;
    USE SIGNAL ;
    PORT
      LAYER M4 ;
        RECT  64.692 42.192 64.776 42.216 ;
    END
  END a[64]
  PIN a[65]
    DIRECTION INPUT ;
    USE SIGNAL ;
    PORT
      LAYER M4 ;
        RECT  64.692 42.288 64.776 42.312 ;
    END
  END a[65]
  PIN a[66]
    DIRECTION INPUT ;
    USE SIGNAL ;
    PORT
      LAYER M4 ;
        RECT  64.692 42.384 64.776 42.408 ;
    END
  END a[66]
  PIN a[67]
    DIRECTION INPUT ;
    USE SIGNAL ;
    PORT
      LAYER M4 ;
        RECT  64.692 42.48 64.776 42.504 ;
    END
  END a[67]
  PIN a[68]
    DIRECTION INPUT ;
    USE SIGNAL ;
    PORT
      LAYER M4 ;
        RECT  64.692 42.576 64.776 42.6 ;
    END
  END a[68]
  PIN a[69]
    DIRECTION INPUT ;
    USE SIGNAL ;
    PORT
      LAYER M4 ;
        RECT  64.692 42.672 64.776 42.696 ;
    END
  END a[69]
  PIN a[6]
    DIRECTION INPUT ;
    USE SIGNAL ;
    PORT
      LAYER M4 ;
        RECT  64.692 45.84 64.776 45.864 ;
    END
  END a[6]
  PIN a[70]
    DIRECTION INPUT ;
    USE SIGNAL ;
    PORT
      LAYER M4 ;
        RECT  64.692 42.768 64.776 42.792 ;
    END
  END a[70]
  PIN a[71]
    DIRECTION INPUT ;
    USE SIGNAL ;
    PORT
      LAYER M4 ;
        RECT  64.692 42.864 64.776 42.888 ;
    END
  END a[71]
  PIN a[72]
    DIRECTION INPUT ;
    USE SIGNAL ;
    PORT
      LAYER M4 ;
        RECT  64.692 42.96 64.776 42.984 ;
    END
  END a[72]
  PIN a[73]
    DIRECTION INPUT ;
    USE SIGNAL ;
    PORT
      LAYER M4 ;
        RECT  64.692 43.056 64.776 43.08 ;
    END
  END a[73]
  PIN a[74]
    DIRECTION INPUT ;
    USE SIGNAL ;
    PORT
      LAYER M4 ;
        RECT  64.692 43.152 64.776 43.176 ;
    END
  END a[74]
  PIN a[75]
    DIRECTION INPUT ;
    USE SIGNAL ;
    PORT
      LAYER M4 ;
        RECT  64.692 43.248 64.776 43.272 ;
    END
  END a[75]
  PIN a[76]
    DIRECTION INPUT ;
    USE SIGNAL ;
    PORT
      LAYER M4 ;
        RECT  64.692 43.344 64.776 43.368 ;
    END
  END a[76]
  PIN a[77]
    DIRECTION INPUT ;
    USE SIGNAL ;
    PORT
      LAYER M4 ;
        RECT  64.692 43.44 64.776 43.464 ;
    END
  END a[77]
  PIN a[78]
    DIRECTION INPUT ;
    USE SIGNAL ;
    PORT
      LAYER M4 ;
        RECT  64.692 43.536 64.776 43.56 ;
    END
  END a[78]
  PIN a[79]
    DIRECTION INPUT ;
    USE SIGNAL ;
    PORT
      LAYER M4 ;
        RECT  64.692 43.632 64.776 43.656 ;
    END
  END a[79]
  PIN a[7]
    DIRECTION INPUT ;
    USE SIGNAL ;
    PORT
      LAYER M4 ;
        RECT  64.692 45.936 64.776 45.96 ;
    END
  END a[7]
  PIN a[80]
    DIRECTION INPUT ;
    USE SIGNAL ;
    PORT
      LAYER M4 ;
        RECT  64.692 43.728 64.776 43.752 ;
    END
  END a[80]
  PIN a[81]
    DIRECTION INPUT ;
    USE SIGNAL ;
    PORT
      LAYER M4 ;
        RECT  64.692 43.824 64.776 43.848 ;
    END
  END a[81]
  PIN a[82]
    DIRECTION INPUT ;
    USE SIGNAL ;
    PORT
      LAYER M4 ;
        RECT  64.692 43.92 64.776 43.944 ;
    END
  END a[82]
  PIN a[83]
    DIRECTION INPUT ;
    USE SIGNAL ;
    PORT
      LAYER M4 ;
        RECT  64.692 44.016 64.776 44.04 ;
    END
  END a[83]
  PIN a[84]
    DIRECTION INPUT ;
    USE SIGNAL ;
    PORT
      LAYER M4 ;
        RECT  64.692 44.112 64.776 44.136 ;
    END
  END a[84]
  PIN a[85]
    DIRECTION INPUT ;
    USE SIGNAL ;
    PORT
      LAYER M4 ;
        RECT  64.692 44.208 64.776 44.232 ;
    END
  END a[85]
  PIN a[86]
    DIRECTION INPUT ;
    USE SIGNAL ;
    PORT
      LAYER M4 ;
        RECT  64.692 44.304 64.776 44.328 ;
    END
  END a[86]
  PIN a[87]
    DIRECTION INPUT ;
    USE SIGNAL ;
    PORT
      LAYER M4 ;
        RECT  64.692 44.4 64.776 44.424 ;
    END
  END a[87]
  PIN a[88]
    DIRECTION INPUT ;
    USE SIGNAL ;
    PORT
      LAYER M4 ;
        RECT  64.692 44.496 64.776 44.52 ;
    END
  END a[88]
  PIN a[89]
    DIRECTION INPUT ;
    USE SIGNAL ;
    PORT
      LAYER M4 ;
        RECT  64.692 44.592 64.776 44.616 ;
    END
  END a[89]
  PIN a[8]
    DIRECTION INPUT ;
    USE SIGNAL ;
    PORT
      LAYER M4 ;
        RECT  64.692 46.032 64.776 46.056 ;
    END
  END a[8]
  PIN a[90]
    DIRECTION INPUT ;
    USE SIGNAL ;
    PORT
      LAYER M4 ;
        RECT  64.692 44.688 64.776 44.712 ;
    END
  END a[90]
  PIN a[91]
    DIRECTION INPUT ;
    USE SIGNAL ;
    PORT
      LAYER M4 ;
        RECT  64.692 44.784 64.776 44.808 ;
    END
  END a[91]
  PIN a[92]
    DIRECTION INPUT ;
    USE SIGNAL ;
    PORT
      LAYER M4 ;
        RECT  64.692 44.88 64.776 44.904 ;
    END
  END a[92]
  PIN a[93]
    DIRECTION INPUT ;
    USE SIGNAL ;
    PORT
      LAYER M4 ;
        RECT  64.692 44.976 64.776 45 ;
    END
  END a[93]
  PIN a[94]
    DIRECTION INPUT ;
    USE SIGNAL ;
    PORT
      LAYER M4 ;
        RECT  64.692 45.072 64.776 45.096 ;
    END
  END a[94]
  PIN a[95]
    DIRECTION INPUT ;
    USE SIGNAL ;
    PORT
      LAYER M4 ;
        RECT  64.692 45.168 64.776 45.192 ;
    END
  END a[95]
  PIN a[96]
    DIRECTION INPUT ;
    USE SIGNAL ;
    PORT
      LAYER M4 ;
        RECT  64.692 39.12 64.776 39.144 ;
    END
  END a[96]
  PIN a[97]
    DIRECTION INPUT ;
    USE SIGNAL ;
    PORT
      LAYER M4 ;
        RECT  64.692 39.216 64.776 39.24 ;
    END
  END a[97]
  PIN a[98]
    DIRECTION INPUT ;
    USE SIGNAL ;
    PORT
      LAYER M4 ;
        RECT  64.692 39.312 64.776 39.336 ;
    END
  END a[98]
  PIN a[99]
    DIRECTION INPUT ;
    USE SIGNAL ;
    PORT
      LAYER M4 ;
        RECT  64.692 39.408 64.776 39.432 ;
    END
  END a[99]
  PIN a[9]
    DIRECTION INPUT ;
    USE SIGNAL ;
    PORT
      LAYER M4 ;
        RECT  64.692 46.128 64.776 46.152 ;
    END
  END a[9]
  PIN b[0]
    DIRECTION OUTPUT ;
    USE SIGNAL ;
    PORT
      LAYER M4 ;
        RECT  0 51.408 0.084 51.432 ;
    END
  END b[0]
  PIN b[100]
    DIRECTION OUTPUT ;
    USE SIGNAL ;
    PORT
      LAYER M4 ;
        RECT  0 48.72 0.084 48.744 ;
    END
  END b[100]
  PIN b[101]
    DIRECTION OUTPUT ;
    USE SIGNAL ;
    PORT
      LAYER M4 ;
        RECT  0 48.816 0.084 48.84 ;
    END
  END b[101]
  PIN b[102]
    DIRECTION OUTPUT ;
    USE SIGNAL ;
    PORT
      LAYER M4 ;
        RECT  0 48.912 0.084 48.936 ;
    END
  END b[102]
  PIN b[103]
    DIRECTION OUTPUT ;
    USE SIGNAL ;
    PORT
      LAYER M4 ;
        RECT  0 49.008 0.084 49.032 ;
    END
  END b[103]
  PIN b[104]
    DIRECTION OUTPUT ;
    USE SIGNAL ;
    PORT
      LAYER M4 ;
        RECT  0 49.104 0.084 49.128 ;
    END
  END b[104]
  PIN b[105]
    DIRECTION OUTPUT ;
    USE SIGNAL ;
    PORT
      LAYER M4 ;
        RECT  0 49.2 0.084 49.224 ;
    END
  END b[105]
  PIN b[106]
    DIRECTION OUTPUT ;
    USE SIGNAL ;
    PORT
      LAYER M4 ;
        RECT  0 49.296 0.084 49.32 ;
    END
  END b[106]
  PIN b[107]
    DIRECTION OUTPUT ;
    USE SIGNAL ;
    PORT
      LAYER M4 ;
        RECT  0 49.392 0.084 49.416 ;
    END
  END b[107]
  PIN b[108]
    DIRECTION OUTPUT ;
    USE SIGNAL ;
    PORT
      LAYER M4 ;
        RECT  0 49.488 0.084 49.512 ;
    END
  END b[108]
  PIN b[109]
    DIRECTION OUTPUT ;
    USE SIGNAL ;
    PORT
      LAYER M4 ;
        RECT  0 49.584 0.084 49.608 ;
    END
  END b[109]
  PIN b[10]
    DIRECTION OUTPUT ;
    USE SIGNAL ;
    PORT
      LAYER M4 ;
        RECT  0 52.368 0.084 52.392 ;
    END
  END b[10]
  PIN b[110]
    DIRECTION OUTPUT ;
    USE SIGNAL ;
    PORT
      LAYER M4 ;
        RECT  0 49.68 0.084 49.704 ;
    END
  END b[110]
  PIN b[111]
    DIRECTION OUTPUT ;
    USE SIGNAL ;
    PORT
      LAYER M4 ;
        RECT  0 49.776 0.084 49.8 ;
    END
  END b[111]
  PIN b[112]
    DIRECTION OUTPUT ;
    USE SIGNAL ;
    PORT
      LAYER M4 ;
        RECT  0 49.872 0.084 49.896 ;
    END
  END b[112]
  PIN b[113]
    DIRECTION OUTPUT ;
    USE SIGNAL ;
    PORT
      LAYER M4 ;
        RECT  0 49.968 0.084 49.992 ;
    END
  END b[113]
  PIN b[114]
    DIRECTION OUTPUT ;
    USE SIGNAL ;
    PORT
      LAYER M4 ;
        RECT  0 50.064 0.084 50.088 ;
    END
  END b[114]
  PIN b[115]
    DIRECTION OUTPUT ;
    USE SIGNAL ;
    PORT
      LAYER M4 ;
        RECT  0 50.16 0.084 50.184 ;
    END
  END b[115]
  PIN b[116]
    DIRECTION OUTPUT ;
    USE SIGNAL ;
    PORT
      LAYER M4 ;
        RECT  0 50.256 0.084 50.28 ;
    END
  END b[116]
  PIN b[117]
    DIRECTION OUTPUT ;
    USE SIGNAL ;
    PORT
      LAYER M4 ;
        RECT  0 50.352 0.084 50.376 ;
    END
  END b[117]
  PIN b[118]
    DIRECTION OUTPUT ;
    USE SIGNAL ;
    PORT
      LAYER M4 ;
        RECT  0 50.448 0.084 50.472 ;
    END
  END b[118]
  PIN b[119]
    DIRECTION OUTPUT ;
    USE SIGNAL ;
    PORT
      LAYER M4 ;
        RECT  0 50.544 0.084 50.568 ;
    END
  END b[119]
  PIN b[11]
    DIRECTION OUTPUT ;
    USE SIGNAL ;
    PORT
      LAYER M4 ;
        RECT  0 52.464 0.084 52.488 ;
    END
  END b[11]
  PIN b[120]
    DIRECTION OUTPUT ;
    USE SIGNAL ;
    PORT
      LAYER M4 ;
        RECT  0 50.64 0.084 50.664 ;
    END
  END b[120]
  PIN b[121]
    DIRECTION OUTPUT ;
    USE SIGNAL ;
    PORT
      LAYER M4 ;
        RECT  0 50.736 0.084 50.76 ;
    END
  END b[121]
  PIN b[122]
    DIRECTION OUTPUT ;
    USE SIGNAL ;
    PORT
      LAYER M4 ;
        RECT  0 50.832 0.084 50.856 ;
    END
  END b[122]
  PIN b[123]
    DIRECTION OUTPUT ;
    USE SIGNAL ;
    PORT
      LAYER M4 ;
        RECT  0 50.928 0.084 50.952 ;
    END
  END b[123]
  PIN b[124]
    DIRECTION OUTPUT ;
    USE SIGNAL ;
    PORT
      LAYER M4 ;
        RECT  0 51.024 0.084 51.048 ;
    END
  END b[124]
  PIN b[125]
    DIRECTION OUTPUT ;
    USE SIGNAL ;
    PORT
      LAYER M4 ;
        RECT  0 51.12 0.084 51.144 ;
    END
  END b[125]
  PIN b[126]
    DIRECTION OUTPUT ;
    USE SIGNAL ;
    PORT
      LAYER M4 ;
        RECT  0 51.216 0.084 51.24 ;
    END
  END b[126]
  PIN b[127]
    DIRECTION OUTPUT ;
    USE SIGNAL ;
    PORT
      LAYER M4 ;
        RECT  0 51.312 0.084 51.336 ;
    END
  END b[127]
  PIN b[128]
    DIRECTION OUTPUT ;
    USE SIGNAL ;
    PORT
      LAYER M4 ;
        RECT  0 60.624 0.084 60.648 ;
    END
  END b[128]
  PIN b[129]
    DIRECTION OUTPUT ;
    USE SIGNAL ;
    PORT
      LAYER M4 ;
        RECT  0 60.72 0.084 60.744 ;
    END
  END b[129]
  PIN b[12]
    DIRECTION OUTPUT ;
    USE SIGNAL ;
    PORT
      LAYER M4 ;
        RECT  0 52.56 0.084 52.584 ;
    END
  END b[12]
  PIN b[130]
    DIRECTION OUTPUT ;
    USE SIGNAL ;
    PORT
      LAYER M4 ;
        RECT  0 60.816 0.084 60.84 ;
    END
  END b[130]
  PIN b[131]
    DIRECTION OUTPUT ;
    USE SIGNAL ;
    PORT
      LAYER M4 ;
        RECT  0 60.912 0.084 60.936 ;
    END
  END b[131]
  PIN b[132]
    DIRECTION OUTPUT ;
    USE SIGNAL ;
    PORT
      LAYER M4 ;
        RECT  0 61.008 0.084 61.032 ;
    END
  END b[132]
  PIN b[133]
    DIRECTION OUTPUT ;
    USE SIGNAL ;
    PORT
      LAYER M4 ;
        RECT  0 61.104 0.084 61.128 ;
    END
  END b[133]
  PIN b[134]
    DIRECTION OUTPUT ;
    USE SIGNAL ;
    PORT
      LAYER M4 ;
        RECT  0 61.2 0.084 61.224 ;
    END
  END b[134]
  PIN b[135]
    DIRECTION OUTPUT ;
    USE SIGNAL ;
    PORT
      LAYER M4 ;
        RECT  0 61.296 0.084 61.32 ;
    END
  END b[135]
  PIN b[136]
    DIRECTION OUTPUT ;
    USE SIGNAL ;
    PORT
      LAYER M4 ;
        RECT  0 61.392 0.084 61.416 ;
    END
  END b[136]
  PIN b[137]
    DIRECTION OUTPUT ;
    USE SIGNAL ;
    PORT
      LAYER M4 ;
        RECT  0 61.488 0.084 61.512 ;
    END
  END b[137]
  PIN b[138]
    DIRECTION OUTPUT ;
    USE SIGNAL ;
    PORT
      LAYER M4 ;
        RECT  0 61.584 0.084 61.608 ;
    END
  END b[138]
  PIN b[139]
    DIRECTION OUTPUT ;
    USE SIGNAL ;
    PORT
      LAYER M4 ;
        RECT  0 61.68 0.084 61.704 ;
    END
  END b[139]
  PIN b[13]
    DIRECTION OUTPUT ;
    USE SIGNAL ;
    PORT
      LAYER M4 ;
        RECT  0 52.656 0.084 52.68 ;
    END
  END b[13]
  PIN b[140]
    DIRECTION OUTPUT ;
    USE SIGNAL ;
    PORT
      LAYER M4 ;
        RECT  0 61.776 0.084 61.8 ;
    END
  END b[140]
  PIN b[141]
    DIRECTION OUTPUT ;
    USE SIGNAL ;
    PORT
      LAYER M4 ;
        RECT  0 61.872 0.084 61.896 ;
    END
  END b[141]
  PIN b[142]
    DIRECTION OUTPUT ;
    USE SIGNAL ;
    PORT
      LAYER M4 ;
        RECT  0 61.968 0.084 61.992 ;
    END
  END b[142]
  PIN b[143]
    DIRECTION OUTPUT ;
    USE SIGNAL ;
    PORT
      LAYER M4 ;
        RECT  0 62.064 0.084 62.088 ;
    END
  END b[143]
  PIN b[144]
    DIRECTION OUTPUT ;
    USE SIGNAL ;
    PORT
      LAYER M4 ;
        RECT  0 62.16 0.084 62.184 ;
    END
  END b[144]
  PIN b[145]
    DIRECTION OUTPUT ;
    USE SIGNAL ;
    PORT
      LAYER M4 ;
        RECT  0 62.256 0.084 62.28 ;
    END
  END b[145]
  PIN b[146]
    DIRECTION OUTPUT ;
    USE SIGNAL ;
    PORT
      LAYER M4 ;
        RECT  0 62.352 0.084 62.376 ;
    END
  END b[146]
  PIN b[147]
    DIRECTION OUTPUT ;
    USE SIGNAL ;
    PORT
      LAYER M4 ;
        RECT  0 62.448 0.084 62.472 ;
    END
  END b[147]
  PIN b[148]
    DIRECTION OUTPUT ;
    USE SIGNAL ;
    PORT
      LAYER M4 ;
        RECT  0 62.544 0.084 62.568 ;
    END
  END b[148]
  PIN b[149]
    DIRECTION OUTPUT ;
    USE SIGNAL ;
    PORT
      LAYER M4 ;
        RECT  0 62.64 0.084 62.664 ;
    END
  END b[149]
  PIN b[14]
    DIRECTION OUTPUT ;
    USE SIGNAL ;
    PORT
      LAYER M4 ;
        RECT  0 52.752 0.084 52.776 ;
    END
  END b[14]
  PIN b[150]
    DIRECTION OUTPUT ;
    USE SIGNAL ;
    PORT
      LAYER M4 ;
        RECT  0 62.736 0.084 62.76 ;
    END
  END b[150]
  PIN b[151]
    DIRECTION OUTPUT ;
    USE SIGNAL ;
    PORT
      LAYER M4 ;
        RECT  0 62.832 0.084 62.856 ;
    END
  END b[151]
  PIN b[152]
    DIRECTION OUTPUT ;
    USE SIGNAL ;
    PORT
      LAYER M4 ;
        RECT  0 62.928 0.084 62.952 ;
    END
  END b[152]
  PIN b[153]
    DIRECTION OUTPUT ;
    USE SIGNAL ;
    PORT
      LAYER M4 ;
        RECT  0 63.024 0.084 63.048 ;
    END
  END b[153]
  PIN b[154]
    DIRECTION OUTPUT ;
    USE SIGNAL ;
    PORT
      LAYER M4 ;
        RECT  0 63.12 0.084 63.144 ;
    END
  END b[154]
  PIN b[155]
    DIRECTION OUTPUT ;
    USE SIGNAL ;
    PORT
      LAYER M4 ;
        RECT  0 63.216 0.084 63.24 ;
    END
  END b[155]
  PIN b[156]
    DIRECTION OUTPUT ;
    USE SIGNAL ;
    PORT
      LAYER M4 ;
        RECT  0 63.312 0.084 63.336 ;
    END
  END b[156]
  PIN b[157]
    DIRECTION OUTPUT ;
    USE SIGNAL ;
    PORT
      LAYER M4 ;
        RECT  0 63.408 0.084 63.432 ;
    END
  END b[157]
  PIN b[158]
    DIRECTION OUTPUT ;
    USE SIGNAL ;
    PORT
      LAYER M4 ;
        RECT  0 63.504 0.084 63.528 ;
    END
  END b[158]
  PIN b[159]
    DIRECTION OUTPUT ;
    USE SIGNAL ;
    PORT
      LAYER M4 ;
        RECT  0 63.6 0.084 63.624 ;
    END
  END b[159]
  PIN b[15]
    DIRECTION OUTPUT ;
    USE SIGNAL ;
    PORT
      LAYER M4 ;
        RECT  0 52.848 0.084 52.872 ;
    END
  END b[15]
  PIN b[160]
    DIRECTION OUTPUT ;
    USE SIGNAL ;
    PORT
      LAYER M4 ;
        RECT  0 63.696 0.084 63.72 ;
    END
  END b[160]
  PIN b[161]
    DIRECTION OUTPUT ;
    USE SIGNAL ;
    PORT
      LAYER M4 ;
        RECT  0 63.792 0.084 63.816 ;
    END
  END b[161]
  PIN b[162]
    DIRECTION OUTPUT ;
    USE SIGNAL ;
    PORT
      LAYER M4 ;
        RECT  0 63.888 0.084 63.912 ;
    END
  END b[162]
  PIN b[163]
    DIRECTION OUTPUT ;
    USE SIGNAL ;
    PORT
      LAYER M4 ;
        RECT  0 63.984 0.084 64.008 ;
    END
  END b[163]
  PIN b[164]
    DIRECTION OUTPUT ;
    USE SIGNAL ;
    PORT
      LAYER M4 ;
        RECT  0 64.08 0.084 64.104 ;
    END
  END b[164]
  PIN b[165]
    DIRECTION OUTPUT ;
    USE SIGNAL ;
    PORT
      LAYER M4 ;
        RECT  0 64.176 0.084 64.2 ;
    END
  END b[165]
  PIN b[166]
    DIRECTION OUTPUT ;
    USE SIGNAL ;
    PORT
      LAYER M4 ;
        RECT  0 64.272 0.084 64.296 ;
    END
  END b[166]
  PIN b[167]
    DIRECTION OUTPUT ;
    USE SIGNAL ;
    PORT
      LAYER M4 ;
        RECT  0 64.368 0.084 64.392 ;
    END
  END b[167]
  PIN b[168]
    DIRECTION OUTPUT ;
    USE SIGNAL ;
    PORT
      LAYER M4 ;
        RECT  0 64.464 0.084 64.488 ;
    END
  END b[168]
  PIN b[169]
    DIRECTION OUTPUT ;
    USE SIGNAL ;
    PORT
      LAYER M4 ;
        RECT  0 64.56 0.084 64.584 ;
    END
  END b[169]
  PIN b[16]
    DIRECTION OUTPUT ;
    USE SIGNAL ;
    PORT
      LAYER M4 ;
        RECT  0 52.944 0.084 52.968 ;
    END
  END b[16]
  PIN b[170]
    DIRECTION OUTPUT ;
    USE SIGNAL ;
    PORT
      LAYER M4 ;
        RECT  0 64.656 0.084 64.68 ;
    END
  END b[170]
  PIN b[171]
    DIRECTION OUTPUT ;
    USE SIGNAL ;
    PORT
      LAYER M4 ;
        RECT  0 64.752 0.084 64.776 ;
    END
  END b[171]
  PIN b[172]
    DIRECTION OUTPUT ;
    USE SIGNAL ;
    PORT
      LAYER M4 ;
        RECT  0 64.848 0.084 64.872 ;
    END
  END b[172]
  PIN b[173]
    DIRECTION OUTPUT ;
    USE SIGNAL ;
    PORT
      LAYER M4 ;
        RECT  0 64.944 0.084 64.968 ;
    END
  END b[173]
  PIN b[174]
    DIRECTION OUTPUT ;
    USE SIGNAL ;
    PORT
      LAYER M4 ;
        RECT  0 65.04 0.084 65.064 ;
    END
  END b[174]
  PIN b[175]
    DIRECTION OUTPUT ;
    USE SIGNAL ;
    PORT
      LAYER M4 ;
        RECT  0 65.136 0.084 65.16 ;
    END
  END b[175]
  PIN b[176]
    DIRECTION OUTPUT ;
    USE SIGNAL ;
    PORT
      LAYER M4 ;
        RECT  0 65.232 0.084 65.256 ;
    END
  END b[176]
  PIN b[177]
    DIRECTION OUTPUT ;
    USE SIGNAL ;
    PORT
      LAYER M4 ;
        RECT  0 65.328 0.084 65.352 ;
    END
  END b[177]
  PIN b[178]
    DIRECTION OUTPUT ;
    USE SIGNAL ;
    PORT
      LAYER M4 ;
        RECT  0 65.424 0.084 65.448 ;
    END
  END b[178]
  PIN b[179]
    DIRECTION OUTPUT ;
    USE SIGNAL ;
    PORT
      LAYER M4 ;
        RECT  0 65.52 0.084 65.544 ;
    END
  END b[179]
  PIN b[17]
    DIRECTION OUTPUT ;
    USE SIGNAL ;
    PORT
      LAYER M4 ;
        RECT  0 53.04 0.084 53.064 ;
    END
  END b[17]
  PIN b[180]
    DIRECTION OUTPUT ;
    USE SIGNAL ;
    PORT
      LAYER M4 ;
        RECT  0 65.616 0.084 65.64 ;
    END
  END b[180]
  PIN b[181]
    DIRECTION OUTPUT ;
    USE SIGNAL ;
    PORT
      LAYER M4 ;
        RECT  0 65.712 0.084 65.736 ;
    END
  END b[181]
  PIN b[182]
    DIRECTION OUTPUT ;
    USE SIGNAL ;
    PORT
      LAYER M4 ;
        RECT  0 65.808 0.084 65.832 ;
    END
  END b[182]
  PIN b[183]
    DIRECTION OUTPUT ;
    USE SIGNAL ;
    PORT
      LAYER M4 ;
        RECT  0 65.904 0.084 65.928 ;
    END
  END b[183]
  PIN b[184]
    DIRECTION OUTPUT ;
    USE SIGNAL ;
    PORT
      LAYER M4 ;
        RECT  0 66 0.084 66.024 ;
    END
  END b[184]
  PIN b[185]
    DIRECTION OUTPUT ;
    USE SIGNAL ;
    PORT
      LAYER M4 ;
        RECT  0 66.096 0.084 66.12 ;
    END
  END b[185]
  PIN b[186]
    DIRECTION OUTPUT ;
    USE SIGNAL ;
    PORT
      LAYER M4 ;
        RECT  0 66.192 0.084 66.216 ;
    END
  END b[186]
  PIN b[187]
    DIRECTION OUTPUT ;
    USE SIGNAL ;
    PORT
      LAYER M4 ;
        RECT  0 66.288 0.084 66.312 ;
    END
  END b[187]
  PIN b[188]
    DIRECTION OUTPUT ;
    USE SIGNAL ;
    PORT
      LAYER M4 ;
        RECT  0 66.384 0.084 66.408 ;
    END
  END b[188]
  PIN b[189]
    DIRECTION OUTPUT ;
    USE SIGNAL ;
    PORT
      LAYER M4 ;
        RECT  0 66.48 0.084 66.504 ;
    END
  END b[189]
  PIN b[18]
    DIRECTION OUTPUT ;
    USE SIGNAL ;
    PORT
      LAYER M4 ;
        RECT  0 53.136 0.084 53.16 ;
    END
  END b[18]
  PIN b[190]
    DIRECTION OUTPUT ;
    USE SIGNAL ;
    PORT
      LAYER M4 ;
        RECT  0 66.576 0.084 66.6 ;
    END
  END b[190]
  PIN b[191]
    DIRECTION OUTPUT ;
    USE SIGNAL ;
    PORT
      LAYER M4 ;
        RECT  0 66.672 0.084 66.696 ;
    END
  END b[191]
  PIN b[192]
    DIRECTION OUTPUT ;
    USE SIGNAL ;
    PORT
      LAYER M4 ;
        RECT  0 41.424 0.084 41.448 ;
    END
  END b[192]
  PIN b[193]
    DIRECTION OUTPUT ;
    USE SIGNAL ;
    PORT
      LAYER M4 ;
        RECT  0 41.52 0.084 41.544 ;
    END
  END b[193]
  PIN b[194]
    DIRECTION OUTPUT ;
    USE SIGNAL ;
    PORT
      LAYER M4 ;
        RECT  0 41.616 0.084 41.64 ;
    END
  END b[194]
  PIN b[195]
    DIRECTION OUTPUT ;
    USE SIGNAL ;
    PORT
      LAYER M4 ;
        RECT  0 41.712 0.084 41.736 ;
    END
  END b[195]
  PIN b[196]
    DIRECTION OUTPUT ;
    USE SIGNAL ;
    PORT
      LAYER M4 ;
        RECT  0 41.808 0.084 41.832 ;
    END
  END b[196]
  PIN b[197]
    DIRECTION OUTPUT ;
    USE SIGNAL ;
    PORT
      LAYER M4 ;
        RECT  0 41.904 0.084 41.928 ;
    END
  END b[197]
  PIN b[198]
    DIRECTION OUTPUT ;
    USE SIGNAL ;
    PORT
      LAYER M4 ;
        RECT  0 42 0.084 42.024 ;
    END
  END b[198]
  PIN b[199]
    DIRECTION OUTPUT ;
    USE SIGNAL ;
    PORT
      LAYER M4 ;
        RECT  0 42.096 0.084 42.12 ;
    END
  END b[199]
  PIN b[19]
    DIRECTION OUTPUT ;
    USE SIGNAL ;
    PORT
      LAYER M4 ;
        RECT  0 53.232 0.084 53.256 ;
    END
  END b[19]
  PIN b[1]
    DIRECTION OUTPUT ;
    USE SIGNAL ;
    PORT
      LAYER M4 ;
        RECT  0 51.504 0.084 51.528 ;
    END
  END b[1]
  PIN b[200]
    DIRECTION OUTPUT ;
    USE SIGNAL ;
    PORT
      LAYER M4 ;
        RECT  0 42.192 0.084 42.216 ;
    END
  END b[200]
  PIN b[201]
    DIRECTION OUTPUT ;
    USE SIGNAL ;
    PORT
      LAYER M4 ;
        RECT  0 42.288 0.084 42.312 ;
    END
  END b[201]
  PIN b[202]
    DIRECTION OUTPUT ;
    USE SIGNAL ;
    PORT
      LAYER M4 ;
        RECT  0 42.384 0.084 42.408 ;
    END
  END b[202]
  PIN b[203]
    DIRECTION OUTPUT ;
    USE SIGNAL ;
    PORT
      LAYER M4 ;
        RECT  0 42.48 0.084 42.504 ;
    END
  END b[203]
  PIN b[204]
    DIRECTION OUTPUT ;
    USE SIGNAL ;
    PORT
      LAYER M4 ;
        RECT  0 42.576 0.084 42.6 ;
    END
  END b[204]
  PIN b[205]
    DIRECTION OUTPUT ;
    USE SIGNAL ;
    PORT
      LAYER M4 ;
        RECT  0 42.672 0.084 42.696 ;
    END
  END b[205]
  PIN b[206]
    DIRECTION OUTPUT ;
    USE SIGNAL ;
    PORT
      LAYER M4 ;
        RECT  0 42.768 0.084 42.792 ;
    END
  END b[206]
  PIN b[207]
    DIRECTION OUTPUT ;
    USE SIGNAL ;
    PORT
      LAYER M4 ;
        RECT  0 42.864 0.084 42.888 ;
    END
  END b[207]
  PIN b[208]
    DIRECTION OUTPUT ;
    USE SIGNAL ;
    PORT
      LAYER M4 ;
        RECT  0 42.96 0.084 42.984 ;
    END
  END b[208]
  PIN b[209]
    DIRECTION OUTPUT ;
    USE SIGNAL ;
    PORT
      LAYER M4 ;
        RECT  0 43.056 0.084 43.08 ;
    END
  END b[209]
  PIN b[20]
    DIRECTION OUTPUT ;
    USE SIGNAL ;
    PORT
      LAYER M4 ;
        RECT  0 53.328 0.084 53.352 ;
    END
  END b[20]
  PIN b[210]
    DIRECTION OUTPUT ;
    USE SIGNAL ;
    PORT
      LAYER M4 ;
        RECT  0 43.152 0.084 43.176 ;
    END
  END b[210]
  PIN b[211]
    DIRECTION OUTPUT ;
    USE SIGNAL ;
    PORT
      LAYER M4 ;
        RECT  0 43.248 0.084 43.272 ;
    END
  END b[211]
  PIN b[212]
    DIRECTION OUTPUT ;
    USE SIGNAL ;
    PORT
      LAYER M4 ;
        RECT  0 43.344 0.084 43.368 ;
    END
  END b[212]
  PIN b[213]
    DIRECTION OUTPUT ;
    USE SIGNAL ;
    PORT
      LAYER M4 ;
        RECT  0 43.44 0.084 43.464 ;
    END
  END b[213]
  PIN b[214]
    DIRECTION OUTPUT ;
    USE SIGNAL ;
    PORT
      LAYER M4 ;
        RECT  0 43.536 0.084 43.56 ;
    END
  END b[214]
  PIN b[215]
    DIRECTION OUTPUT ;
    USE SIGNAL ;
    PORT
      LAYER M4 ;
        RECT  0 43.632 0.084 43.656 ;
    END
  END b[215]
  PIN b[216]
    DIRECTION OUTPUT ;
    USE SIGNAL ;
    PORT
      LAYER M4 ;
        RECT  0 43.728 0.084 43.752 ;
    END
  END b[216]
  PIN b[217]
    DIRECTION OUTPUT ;
    USE SIGNAL ;
    PORT
      LAYER M4 ;
        RECT  0 43.824 0.084 43.848 ;
    END
  END b[217]
  PIN b[218]
    DIRECTION OUTPUT ;
    USE SIGNAL ;
    PORT
      LAYER M4 ;
        RECT  0 43.92 0.084 43.944 ;
    END
  END b[218]
  PIN b[219]
    DIRECTION OUTPUT ;
    USE SIGNAL ;
    PORT
      LAYER M4 ;
        RECT  0 44.016 0.084 44.04 ;
    END
  END b[219]
  PIN b[21]
    DIRECTION OUTPUT ;
    USE SIGNAL ;
    PORT
      LAYER M4 ;
        RECT  0 53.424 0.084 53.448 ;
    END
  END b[21]
  PIN b[220]
    DIRECTION OUTPUT ;
    USE SIGNAL ;
    PORT
      LAYER M4 ;
        RECT  0 44.112 0.084 44.136 ;
    END
  END b[220]
  PIN b[221]
    DIRECTION OUTPUT ;
    USE SIGNAL ;
    PORT
      LAYER M4 ;
        RECT  0 44.208 0.084 44.232 ;
    END
  END b[221]
  PIN b[222]
    DIRECTION OUTPUT ;
    USE SIGNAL ;
    PORT
      LAYER M4 ;
        RECT  0 44.304 0.084 44.328 ;
    END
  END b[222]
  PIN b[223]
    DIRECTION OUTPUT ;
    USE SIGNAL ;
    PORT
      LAYER M4 ;
        RECT  0 44.4 0.084 44.424 ;
    END
  END b[223]
  PIN b[224]
    DIRECTION OUTPUT ;
    USE SIGNAL ;
    PORT
      LAYER M4 ;
        RECT  0 32.208 0.084 32.232 ;
    END
  END b[224]
  PIN b[225]
    DIRECTION OUTPUT ;
    USE SIGNAL ;
    PORT
      LAYER M4 ;
        RECT  0 32.304 0.084 32.328 ;
    END
  END b[225]
  PIN b[226]
    DIRECTION OUTPUT ;
    USE SIGNAL ;
    PORT
      LAYER M4 ;
        RECT  0 32.4 0.084 32.424 ;
    END
  END b[226]
  PIN b[227]
    DIRECTION OUTPUT ;
    USE SIGNAL ;
    PORT
      LAYER M4 ;
        RECT  0 32.496 0.084 32.52 ;
    END
  END b[227]
  PIN b[228]
    DIRECTION OUTPUT ;
    USE SIGNAL ;
    PORT
      LAYER M4 ;
        RECT  0 32.592 0.084 32.616 ;
    END
  END b[228]
  PIN b[229]
    DIRECTION OUTPUT ;
    USE SIGNAL ;
    PORT
      LAYER M4 ;
        RECT  0 32.688 0.084 32.712 ;
    END
  END b[229]
  PIN b[22]
    DIRECTION OUTPUT ;
    USE SIGNAL ;
    PORT
      LAYER M4 ;
        RECT  0 53.52 0.084 53.544 ;
    END
  END b[22]
  PIN b[230]
    DIRECTION OUTPUT ;
    USE SIGNAL ;
    PORT
      LAYER M4 ;
        RECT  0 32.784 0.084 32.808 ;
    END
  END b[230]
  PIN b[231]
    DIRECTION OUTPUT ;
    USE SIGNAL ;
    PORT
      LAYER M4 ;
        RECT  0 32.88 0.084 32.904 ;
    END
  END b[231]
  PIN b[232]
    DIRECTION OUTPUT ;
    USE SIGNAL ;
    PORT
      LAYER M4 ;
        RECT  0 32.976 0.084 33 ;
    END
  END b[232]
  PIN b[233]
    DIRECTION OUTPUT ;
    USE SIGNAL ;
    PORT
      LAYER M4 ;
        RECT  0 33.072 0.084 33.096 ;
    END
  END b[233]
  PIN b[234]
    DIRECTION OUTPUT ;
    USE SIGNAL ;
    PORT
      LAYER M4 ;
        RECT  0 33.168 0.084 33.192 ;
    END
  END b[234]
  PIN b[235]
    DIRECTION OUTPUT ;
    USE SIGNAL ;
    PORT
      LAYER M4 ;
        RECT  0 33.264 0.084 33.288 ;
    END
  END b[235]
  PIN b[236]
    DIRECTION OUTPUT ;
    USE SIGNAL ;
    PORT
      LAYER M4 ;
        RECT  0 33.36 0.084 33.384 ;
    END
  END b[236]
  PIN b[237]
    DIRECTION OUTPUT ;
    USE SIGNAL ;
    PORT
      LAYER M4 ;
        RECT  0 33.456 0.084 33.48 ;
    END
  END b[237]
  PIN b[238]
    DIRECTION OUTPUT ;
    USE SIGNAL ;
    PORT
      LAYER M4 ;
        RECT  0 33.552 0.084 33.576 ;
    END
  END b[238]
  PIN b[239]
    DIRECTION OUTPUT ;
    USE SIGNAL ;
    PORT
      LAYER M4 ;
        RECT  0 33.648 0.084 33.672 ;
    END
  END b[239]
  PIN b[23]
    DIRECTION OUTPUT ;
    USE SIGNAL ;
    PORT
      LAYER M4 ;
        RECT  0 53.616 0.084 53.64 ;
    END
  END b[23]
  PIN b[240]
    DIRECTION OUTPUT ;
    USE SIGNAL ;
    PORT
      LAYER M4 ;
        RECT  0 33.744 0.084 33.768 ;
    END
  END b[240]
  PIN b[241]
    DIRECTION OUTPUT ;
    USE SIGNAL ;
    PORT
      LAYER M4 ;
        RECT  0 33.84 0.084 33.864 ;
    END
  END b[241]
  PIN b[242]
    DIRECTION OUTPUT ;
    USE SIGNAL ;
    PORT
      LAYER M4 ;
        RECT  0 33.936 0.084 33.96 ;
    END
  END b[242]
  PIN b[243]
    DIRECTION OUTPUT ;
    USE SIGNAL ;
    PORT
      LAYER M4 ;
        RECT  0 34.032 0.084 34.056 ;
    END
  END b[243]
  PIN b[244]
    DIRECTION OUTPUT ;
    USE SIGNAL ;
    PORT
      LAYER M4 ;
        RECT  0 34.128 0.084 34.152 ;
    END
  END b[244]
  PIN b[245]
    DIRECTION OUTPUT ;
    USE SIGNAL ;
    PORT
      LAYER M4 ;
        RECT  0 34.224 0.084 34.248 ;
    END
  END b[245]
  PIN b[246]
    DIRECTION OUTPUT ;
    USE SIGNAL ;
    PORT
      LAYER M4 ;
        RECT  0 34.32 0.084 34.344 ;
    END
  END b[246]
  PIN b[247]
    DIRECTION OUTPUT ;
    USE SIGNAL ;
    PORT
      LAYER M4 ;
        RECT  0 34.416 0.084 34.44 ;
    END
  END b[247]
  PIN b[248]
    DIRECTION OUTPUT ;
    USE SIGNAL ;
    PORT
      LAYER M4 ;
        RECT  0 34.512 0.084 34.536 ;
    END
  END b[248]
  PIN b[249]
    DIRECTION OUTPUT ;
    USE SIGNAL ;
    PORT
      LAYER M4 ;
        RECT  0 34.608 0.084 34.632 ;
    END
  END b[249]
  PIN b[24]
    DIRECTION OUTPUT ;
    USE SIGNAL ;
    PORT
      LAYER M4 ;
        RECT  0 53.712 0.084 53.736 ;
    END
  END b[24]
  PIN b[250]
    DIRECTION OUTPUT ;
    USE SIGNAL ;
    PORT
      LAYER M4 ;
        RECT  0 34.704 0.084 34.728 ;
    END
  END b[250]
  PIN b[251]
    DIRECTION OUTPUT ;
    USE SIGNAL ;
    PORT
      LAYER M4 ;
        RECT  0 34.8 0.084 34.824 ;
    END
  END b[251]
  PIN b[252]
    DIRECTION OUTPUT ;
    USE SIGNAL ;
    PORT
      LAYER M4 ;
        RECT  0 34.896 0.084 34.92 ;
    END
  END b[252]
  PIN b[253]
    DIRECTION OUTPUT ;
    USE SIGNAL ;
    PORT
      LAYER M4 ;
        RECT  0 34.992 0.084 35.016 ;
    END
  END b[253]
  PIN b[254]
    DIRECTION OUTPUT ;
    USE SIGNAL ;
    PORT
      LAYER M4 ;
        RECT  0 35.088 0.084 35.112 ;
    END
  END b[254]
  PIN b[255]
    DIRECTION OUTPUT ;
    USE SIGNAL ;
    PORT
      LAYER M4 ;
        RECT  0 35.184 0.084 35.208 ;
    END
  END b[255]
  PIN b[256]
    DIRECTION OUTPUT ;
    USE SIGNAL ;
    PORT
      LAYER M4 ;
        RECT  0 35.28 0.084 35.304 ;
    END
  END b[256]
  PIN b[257]
    DIRECTION OUTPUT ;
    USE SIGNAL ;
    PORT
      LAYER M4 ;
        RECT  0 35.376 0.084 35.4 ;
    END
  END b[257]
  PIN b[258]
    DIRECTION OUTPUT ;
    USE SIGNAL ;
    PORT
      LAYER M4 ;
        RECT  0 35.472 0.084 35.496 ;
    END
  END b[258]
  PIN b[259]
    DIRECTION OUTPUT ;
    USE SIGNAL ;
    PORT
      LAYER M4 ;
        RECT  0 35.568 0.084 35.592 ;
    END
  END b[259]
  PIN b[25]
    DIRECTION OUTPUT ;
    USE SIGNAL ;
    PORT
      LAYER M4 ;
        RECT  0 53.808 0.084 53.832 ;
    END
  END b[25]
  PIN b[260]
    DIRECTION OUTPUT ;
    USE SIGNAL ;
    PORT
      LAYER M4 ;
        RECT  0 35.664 0.084 35.688 ;
    END
  END b[260]
  PIN b[261]
    DIRECTION OUTPUT ;
    USE SIGNAL ;
    PORT
      LAYER M4 ;
        RECT  0 35.76 0.084 35.784 ;
    END
  END b[261]
  PIN b[262]
    DIRECTION OUTPUT ;
    USE SIGNAL ;
    PORT
      LAYER M4 ;
        RECT  0 35.856 0.084 35.88 ;
    END
  END b[262]
  PIN b[263]
    DIRECTION OUTPUT ;
    USE SIGNAL ;
    PORT
      LAYER M4 ;
        RECT  0 35.952 0.084 35.976 ;
    END
  END b[263]
  PIN b[264]
    DIRECTION OUTPUT ;
    USE SIGNAL ;
    PORT
      LAYER M4 ;
        RECT  0 36.048 0.084 36.072 ;
    END
  END b[264]
  PIN b[265]
    DIRECTION OUTPUT ;
    USE SIGNAL ;
    PORT
      LAYER M4 ;
        RECT  0 36.144 0.084 36.168 ;
    END
  END b[265]
  PIN b[266]
    DIRECTION OUTPUT ;
    USE SIGNAL ;
    PORT
      LAYER M4 ;
        RECT  0 36.24 0.084 36.264 ;
    END
  END b[266]
  PIN b[267]
    DIRECTION OUTPUT ;
    USE SIGNAL ;
    PORT
      LAYER M4 ;
        RECT  0 36.336 0.084 36.36 ;
    END
  END b[267]
  PIN b[268]
    DIRECTION OUTPUT ;
    USE SIGNAL ;
    PORT
      LAYER M4 ;
        RECT  0 36.432 0.084 36.456 ;
    END
  END b[268]
  PIN b[269]
    DIRECTION OUTPUT ;
    USE SIGNAL ;
    PORT
      LAYER M4 ;
        RECT  0 36.528 0.084 36.552 ;
    END
  END b[269]
  PIN b[26]
    DIRECTION OUTPUT ;
    USE SIGNAL ;
    PORT
      LAYER M4 ;
        RECT  0 53.904 0.084 53.928 ;
    END
  END b[26]
  PIN b[270]
    DIRECTION OUTPUT ;
    USE SIGNAL ;
    PORT
      LAYER M4 ;
        RECT  0 36.624 0.084 36.648 ;
    END
  END b[270]
  PIN b[271]
    DIRECTION OUTPUT ;
    USE SIGNAL ;
    PORT
      LAYER M4 ;
        RECT  0 36.72 0.084 36.744 ;
    END
  END b[271]
  PIN b[272]
    DIRECTION OUTPUT ;
    USE SIGNAL ;
    PORT
      LAYER M4 ;
        RECT  0 36.816 0.084 36.84 ;
    END
  END b[272]
  PIN b[273]
    DIRECTION OUTPUT ;
    USE SIGNAL ;
    PORT
      LAYER M4 ;
        RECT  0 36.912 0.084 36.936 ;
    END
  END b[273]
  PIN b[274]
    DIRECTION OUTPUT ;
    USE SIGNAL ;
    PORT
      LAYER M4 ;
        RECT  0 37.008 0.084 37.032 ;
    END
  END b[274]
  PIN b[275]
    DIRECTION OUTPUT ;
    USE SIGNAL ;
    PORT
      LAYER M4 ;
        RECT  0 37.104 0.084 37.128 ;
    END
  END b[275]
  PIN b[276]
    DIRECTION OUTPUT ;
    USE SIGNAL ;
    PORT
      LAYER M4 ;
        RECT  0 37.2 0.084 37.224 ;
    END
  END b[276]
  PIN b[277]
    DIRECTION OUTPUT ;
    USE SIGNAL ;
    PORT
      LAYER M4 ;
        RECT  0 37.296 0.084 37.32 ;
    END
  END b[277]
  PIN b[278]
    DIRECTION OUTPUT ;
    USE SIGNAL ;
    PORT
      LAYER M4 ;
        RECT  0 37.392 0.084 37.416 ;
    END
  END b[278]
  PIN b[279]
    DIRECTION OUTPUT ;
    USE SIGNAL ;
    PORT
      LAYER M4 ;
        RECT  0 37.488 0.084 37.512 ;
    END
  END b[279]
  PIN b[27]
    DIRECTION OUTPUT ;
    USE SIGNAL ;
    PORT
      LAYER M4 ;
        RECT  0 54 0.084 54.024 ;
    END
  END b[27]
  PIN b[280]
    DIRECTION OUTPUT ;
    USE SIGNAL ;
    PORT
      LAYER M4 ;
        RECT  0 37.584 0.084 37.608 ;
    END
  END b[280]
  PIN b[281]
    DIRECTION OUTPUT ;
    USE SIGNAL ;
    PORT
      LAYER M4 ;
        RECT  0 37.68 0.084 37.704 ;
    END
  END b[281]
  PIN b[282]
    DIRECTION OUTPUT ;
    USE SIGNAL ;
    PORT
      LAYER M4 ;
        RECT  0 37.776 0.084 37.8 ;
    END
  END b[282]
  PIN b[283]
    DIRECTION OUTPUT ;
    USE SIGNAL ;
    PORT
      LAYER M4 ;
        RECT  0 37.872 0.084 37.896 ;
    END
  END b[283]
  PIN b[284]
    DIRECTION OUTPUT ;
    USE SIGNAL ;
    PORT
      LAYER M4 ;
        RECT  0 37.968 0.084 37.992 ;
    END
  END b[284]
  PIN b[285]
    DIRECTION OUTPUT ;
    USE SIGNAL ;
    PORT
      LAYER M4 ;
        RECT  0 38.064 0.084 38.088 ;
    END
  END b[285]
  PIN b[286]
    DIRECTION OUTPUT ;
    USE SIGNAL ;
    PORT
      LAYER M4 ;
        RECT  0 38.16 0.084 38.184 ;
    END
  END b[286]
  PIN b[287]
    DIRECTION OUTPUT ;
    USE SIGNAL ;
    PORT
      LAYER M4 ;
        RECT  0 38.256 0.084 38.28 ;
    END
  END b[287]
  PIN b[288]
    DIRECTION OUTPUT ;
    USE SIGNAL ;
    PORT
      LAYER M4 ;
        RECT  0 44.496 0.084 44.52 ;
    END
  END b[288]
  PIN b[289]
    DIRECTION OUTPUT ;
    USE SIGNAL ;
    PORT
      LAYER M4 ;
        RECT  0 44.592 0.084 44.616 ;
    END
  END b[289]
  PIN b[28]
    DIRECTION OUTPUT ;
    USE SIGNAL ;
    PORT
      LAYER M4 ;
        RECT  0 54.096 0.084 54.12 ;
    END
  END b[28]
  PIN b[290]
    DIRECTION OUTPUT ;
    USE SIGNAL ;
    PORT
      LAYER M4 ;
        RECT  0 44.688 0.084 44.712 ;
    END
  END b[290]
  PIN b[291]
    DIRECTION OUTPUT ;
    USE SIGNAL ;
    PORT
      LAYER M4 ;
        RECT  0 44.784 0.084 44.808 ;
    END
  END b[291]
  PIN b[292]
    DIRECTION OUTPUT ;
    USE SIGNAL ;
    PORT
      LAYER M4 ;
        RECT  0 44.88 0.084 44.904 ;
    END
  END b[292]
  PIN b[293]
    DIRECTION OUTPUT ;
    USE SIGNAL ;
    PORT
      LAYER M4 ;
        RECT  0 44.976 0.084 45 ;
    END
  END b[293]
  PIN b[294]
    DIRECTION OUTPUT ;
    USE SIGNAL ;
    PORT
      LAYER M4 ;
        RECT  0 45.072 0.084 45.096 ;
    END
  END b[294]
  PIN b[295]
    DIRECTION OUTPUT ;
    USE SIGNAL ;
    PORT
      LAYER M4 ;
        RECT  0 45.168 0.084 45.192 ;
    END
  END b[295]
  PIN b[296]
    DIRECTION OUTPUT ;
    USE SIGNAL ;
    PORT
      LAYER M4 ;
        RECT  0 45.264 0.084 45.288 ;
    END
  END b[296]
  PIN b[297]
    DIRECTION OUTPUT ;
    USE SIGNAL ;
    PORT
      LAYER M4 ;
        RECT  0 45.36 0.084 45.384 ;
    END
  END b[297]
  PIN b[298]
    DIRECTION OUTPUT ;
    USE SIGNAL ;
    PORT
      LAYER M4 ;
        RECT  0 45.456 0.084 45.48 ;
    END
  END b[298]
  PIN b[299]
    DIRECTION OUTPUT ;
    USE SIGNAL ;
    PORT
      LAYER M4 ;
        RECT  0 45.552 0.084 45.576 ;
    END
  END b[299]
  PIN b[29]
    DIRECTION OUTPUT ;
    USE SIGNAL ;
    PORT
      LAYER M4 ;
        RECT  0 54.192 0.084 54.216 ;
    END
  END b[29]
  PIN b[2]
    DIRECTION OUTPUT ;
    USE SIGNAL ;
    PORT
      LAYER M4 ;
        RECT  0 51.6 0.084 51.624 ;
    END
  END b[2]
  PIN b[300]
    DIRECTION OUTPUT ;
    USE SIGNAL ;
    PORT
      LAYER M4 ;
        RECT  0 45.648 0.084 45.672 ;
    END
  END b[300]
  PIN b[301]
    DIRECTION OUTPUT ;
    USE SIGNAL ;
    PORT
      LAYER M4 ;
        RECT  0 45.744 0.084 45.768 ;
    END
  END b[301]
  PIN b[302]
    DIRECTION OUTPUT ;
    USE SIGNAL ;
    PORT
      LAYER M4 ;
        RECT  0 45.84 0.084 45.864 ;
    END
  END b[302]
  PIN b[303]
    DIRECTION OUTPUT ;
    USE SIGNAL ;
    PORT
      LAYER M4 ;
        RECT  0 45.936 0.084 45.96 ;
    END
  END b[303]
  PIN b[304]
    DIRECTION OUTPUT ;
    USE SIGNAL ;
    PORT
      LAYER M4 ;
        RECT  0 46.032 0.084 46.056 ;
    END
  END b[304]
  PIN b[305]
    DIRECTION OUTPUT ;
    USE SIGNAL ;
    PORT
      LAYER M4 ;
        RECT  0 46.128 0.084 46.152 ;
    END
  END b[305]
  PIN b[306]
    DIRECTION OUTPUT ;
    USE SIGNAL ;
    PORT
      LAYER M4 ;
        RECT  0 46.224 0.084 46.248 ;
    END
  END b[306]
  PIN b[307]
    DIRECTION OUTPUT ;
    USE SIGNAL ;
    PORT
      LAYER M4 ;
        RECT  0 46.32 0.084 46.344 ;
    END
  END b[307]
  PIN b[308]
    DIRECTION OUTPUT ;
    USE SIGNAL ;
    PORT
      LAYER M4 ;
        RECT  0 46.416 0.084 46.44 ;
    END
  END b[308]
  PIN b[309]
    DIRECTION OUTPUT ;
    USE SIGNAL ;
    PORT
      LAYER M4 ;
        RECT  0 46.512 0.084 46.536 ;
    END
  END b[309]
  PIN b[30]
    DIRECTION OUTPUT ;
    USE SIGNAL ;
    PORT
      LAYER M4 ;
        RECT  0 54.288 0.084 54.312 ;
    END
  END b[30]
  PIN b[310]
    DIRECTION OUTPUT ;
    USE SIGNAL ;
    PORT
      LAYER M4 ;
        RECT  0 46.608 0.084 46.632 ;
    END
  END b[310]
  PIN b[311]
    DIRECTION OUTPUT ;
    USE SIGNAL ;
    PORT
      LAYER M4 ;
        RECT  0 46.704 0.084 46.728 ;
    END
  END b[311]
  PIN b[312]
    DIRECTION OUTPUT ;
    USE SIGNAL ;
    PORT
      LAYER M4 ;
        RECT  0 46.8 0.084 46.824 ;
    END
  END b[312]
  PIN b[313]
    DIRECTION OUTPUT ;
    USE SIGNAL ;
    PORT
      LAYER M4 ;
        RECT  0 46.896 0.084 46.92 ;
    END
  END b[313]
  PIN b[314]
    DIRECTION OUTPUT ;
    USE SIGNAL ;
    PORT
      LAYER M4 ;
        RECT  0 46.992 0.084 47.016 ;
    END
  END b[314]
  PIN b[315]
    DIRECTION OUTPUT ;
    USE SIGNAL ;
    PORT
      LAYER M4 ;
        RECT  0 47.088 0.084 47.112 ;
    END
  END b[315]
  PIN b[316]
    DIRECTION OUTPUT ;
    USE SIGNAL ;
    PORT
      LAYER M4 ;
        RECT  0 47.184 0.084 47.208 ;
    END
  END b[316]
  PIN b[317]
    DIRECTION OUTPUT ;
    USE SIGNAL ;
    PORT
      LAYER M4 ;
        RECT  0 47.28 0.084 47.304 ;
    END
  END b[317]
  PIN b[318]
    DIRECTION OUTPUT ;
    USE SIGNAL ;
    PORT
      LAYER M4 ;
        RECT  0 47.376 0.084 47.4 ;
    END
  END b[318]
  PIN b[319]
    DIRECTION OUTPUT ;
    USE SIGNAL ;
    PORT
      LAYER M4 ;
        RECT  0 47.472 0.084 47.496 ;
    END
  END b[319]
  PIN b[31]
    DIRECTION OUTPUT ;
    USE SIGNAL ;
    PORT
      LAYER M4 ;
        RECT  0 54.384 0.084 54.408 ;
    END
  END b[31]
  PIN b[320]
    DIRECTION OUTPUT ;
    USE SIGNAL ;
    PORT
      LAYER M4 ;
        RECT  0 29.136 0.084 29.16 ;
    END
  END b[320]
  PIN b[321]
    DIRECTION OUTPUT ;
    USE SIGNAL ;
    PORT
      LAYER M4 ;
        RECT  0 29.232 0.084 29.256 ;
    END
  END b[321]
  PIN b[322]
    DIRECTION OUTPUT ;
    USE SIGNAL ;
    PORT
      LAYER M4 ;
        RECT  0 29.328 0.084 29.352 ;
    END
  END b[322]
  PIN b[323]
    DIRECTION OUTPUT ;
    USE SIGNAL ;
    PORT
      LAYER M4 ;
        RECT  0 29.424 0.084 29.448 ;
    END
  END b[323]
  PIN b[324]
    DIRECTION OUTPUT ;
    USE SIGNAL ;
    PORT
      LAYER M4 ;
        RECT  0 29.52 0.084 29.544 ;
    END
  END b[324]
  PIN b[325]
    DIRECTION OUTPUT ;
    USE SIGNAL ;
    PORT
      LAYER M4 ;
        RECT  0 29.616 0.084 29.64 ;
    END
  END b[325]
  PIN b[326]
    DIRECTION OUTPUT ;
    USE SIGNAL ;
    PORT
      LAYER M4 ;
        RECT  0 29.712 0.084 29.736 ;
    END
  END b[326]
  PIN b[327]
    DIRECTION OUTPUT ;
    USE SIGNAL ;
    PORT
      LAYER M4 ;
        RECT  0 29.808 0.084 29.832 ;
    END
  END b[327]
  PIN b[328]
    DIRECTION OUTPUT ;
    USE SIGNAL ;
    PORT
      LAYER M4 ;
        RECT  0 29.904 0.084 29.928 ;
    END
  END b[328]
  PIN b[329]
    DIRECTION OUTPUT ;
    USE SIGNAL ;
    PORT
      LAYER M4 ;
        RECT  0 30 0.084 30.024 ;
    END
  END b[329]
  PIN b[32]
    DIRECTION OUTPUT ;
    USE SIGNAL ;
    PORT
      LAYER M4 ;
        RECT  0 57.552 0.084 57.576 ;
    END
  END b[32]
  PIN b[330]
    DIRECTION OUTPUT ;
    USE SIGNAL ;
    PORT
      LAYER M4 ;
        RECT  0 30.096 0.084 30.12 ;
    END
  END b[330]
  PIN b[331]
    DIRECTION OUTPUT ;
    USE SIGNAL ;
    PORT
      LAYER M4 ;
        RECT  0 30.192 0.084 30.216 ;
    END
  END b[331]
  PIN b[332]
    DIRECTION OUTPUT ;
    USE SIGNAL ;
    PORT
      LAYER M4 ;
        RECT  0 30.288 0.084 30.312 ;
    END
  END b[332]
  PIN b[333]
    DIRECTION OUTPUT ;
    USE SIGNAL ;
    PORT
      LAYER M4 ;
        RECT  0 30.384 0.084 30.408 ;
    END
  END b[333]
  PIN b[334]
    DIRECTION OUTPUT ;
    USE SIGNAL ;
    PORT
      LAYER M4 ;
        RECT  0 30.48 0.084 30.504 ;
    END
  END b[334]
  PIN b[335]
    DIRECTION OUTPUT ;
    USE SIGNAL ;
    PORT
      LAYER M4 ;
        RECT  0 30.576 0.084 30.6 ;
    END
  END b[335]
  PIN b[336]
    DIRECTION OUTPUT ;
    USE SIGNAL ;
    PORT
      LAYER M4 ;
        RECT  0 30.672 0.084 30.696 ;
    END
  END b[336]
  PIN b[337]
    DIRECTION OUTPUT ;
    USE SIGNAL ;
    PORT
      LAYER M4 ;
        RECT  0 30.768 0.084 30.792 ;
    END
  END b[337]
  PIN b[338]
    DIRECTION OUTPUT ;
    USE SIGNAL ;
    PORT
      LAYER M4 ;
        RECT  0 30.864 0.084 30.888 ;
    END
  END b[338]
  PIN b[339]
    DIRECTION OUTPUT ;
    USE SIGNAL ;
    PORT
      LAYER M4 ;
        RECT  0 30.96 0.084 30.984 ;
    END
  END b[339]
  PIN b[33]
    DIRECTION OUTPUT ;
    USE SIGNAL ;
    PORT
      LAYER M4 ;
        RECT  0 57.648 0.084 57.672 ;
    END
  END b[33]
  PIN b[340]
    DIRECTION OUTPUT ;
    USE SIGNAL ;
    PORT
      LAYER M4 ;
        RECT  0 31.056 0.084 31.08 ;
    END
  END b[340]
  PIN b[341]
    DIRECTION OUTPUT ;
    USE SIGNAL ;
    PORT
      LAYER M4 ;
        RECT  0 31.152 0.084 31.176 ;
    END
  END b[341]
  PIN b[342]
    DIRECTION OUTPUT ;
    USE SIGNAL ;
    PORT
      LAYER M4 ;
        RECT  0 31.248 0.084 31.272 ;
    END
  END b[342]
  PIN b[343]
    DIRECTION OUTPUT ;
    USE SIGNAL ;
    PORT
      LAYER M4 ;
        RECT  0 31.344 0.084 31.368 ;
    END
  END b[343]
  PIN b[344]
    DIRECTION OUTPUT ;
    USE SIGNAL ;
    PORT
      LAYER M4 ;
        RECT  0 31.44 0.084 31.464 ;
    END
  END b[344]
  PIN b[345]
    DIRECTION OUTPUT ;
    USE SIGNAL ;
    PORT
      LAYER M4 ;
        RECT  0 31.536 0.084 31.56 ;
    END
  END b[345]
  PIN b[346]
    DIRECTION OUTPUT ;
    USE SIGNAL ;
    PORT
      LAYER M4 ;
        RECT  0 31.632 0.084 31.656 ;
    END
  END b[346]
  PIN b[347]
    DIRECTION OUTPUT ;
    USE SIGNAL ;
    PORT
      LAYER M4 ;
        RECT  0 31.728 0.084 31.752 ;
    END
  END b[347]
  PIN b[348]
    DIRECTION OUTPUT ;
    USE SIGNAL ;
    PORT
      LAYER M4 ;
        RECT  0 31.824 0.084 31.848 ;
    END
  END b[348]
  PIN b[349]
    DIRECTION OUTPUT ;
    USE SIGNAL ;
    PORT
      LAYER M4 ;
        RECT  0 31.92 0.084 31.944 ;
    END
  END b[349]
  PIN b[34]
    DIRECTION OUTPUT ;
    USE SIGNAL ;
    PORT
      LAYER M4 ;
        RECT  0 57.744 0.084 57.768 ;
    END
  END b[34]
  PIN b[350]
    DIRECTION OUTPUT ;
    USE SIGNAL ;
    PORT
      LAYER M4 ;
        RECT  0 32.016 0.084 32.04 ;
    END
  END b[350]
  PIN b[351]
    DIRECTION OUTPUT ;
    USE SIGNAL ;
    PORT
      LAYER M4 ;
        RECT  0 32.112 0.084 32.136 ;
    END
  END b[351]
  PIN b[352]
    DIRECTION OUTPUT ;
    USE SIGNAL ;
    PORT
      LAYER M4 ;
        RECT  0 38.352 0.084 38.376 ;
    END
  END b[352]
  PIN b[353]
    DIRECTION OUTPUT ;
    USE SIGNAL ;
    PORT
      LAYER M4 ;
        RECT  0 38.448 0.084 38.472 ;
    END
  END b[353]
  PIN b[354]
    DIRECTION OUTPUT ;
    USE SIGNAL ;
    PORT
      LAYER M4 ;
        RECT  0 38.544 0.084 38.568 ;
    END
  END b[354]
  PIN b[355]
    DIRECTION OUTPUT ;
    USE SIGNAL ;
    PORT
      LAYER M4 ;
        RECT  0 38.64 0.084 38.664 ;
    END
  END b[355]
  PIN b[356]
    DIRECTION OUTPUT ;
    USE SIGNAL ;
    PORT
      LAYER M4 ;
        RECT  0 38.736 0.084 38.76 ;
    END
  END b[356]
  PIN b[357]
    DIRECTION OUTPUT ;
    USE SIGNAL ;
    PORT
      LAYER M4 ;
        RECT  0 38.832 0.084 38.856 ;
    END
  END b[357]
  PIN b[358]
    DIRECTION OUTPUT ;
    USE SIGNAL ;
    PORT
      LAYER M4 ;
        RECT  0 38.928 0.084 38.952 ;
    END
  END b[358]
  PIN b[359]
    DIRECTION OUTPUT ;
    USE SIGNAL ;
    PORT
      LAYER M4 ;
        RECT  0 39.024 0.084 39.048 ;
    END
  END b[359]
  PIN b[35]
    DIRECTION OUTPUT ;
    USE SIGNAL ;
    PORT
      LAYER M4 ;
        RECT  0 57.84 0.084 57.864 ;
    END
  END b[35]
  PIN b[360]
    DIRECTION OUTPUT ;
    USE SIGNAL ;
    PORT
      LAYER M4 ;
        RECT  0 39.12 0.084 39.144 ;
    END
  END b[360]
  PIN b[361]
    DIRECTION OUTPUT ;
    USE SIGNAL ;
    PORT
      LAYER M4 ;
        RECT  0 39.216 0.084 39.24 ;
    END
  END b[361]
  PIN b[362]
    DIRECTION OUTPUT ;
    USE SIGNAL ;
    PORT
      LAYER M4 ;
        RECT  0 39.312 0.084 39.336 ;
    END
  END b[362]
  PIN b[363]
    DIRECTION OUTPUT ;
    USE SIGNAL ;
    PORT
      LAYER M4 ;
        RECT  0 39.408 0.084 39.432 ;
    END
  END b[363]
  PIN b[364]
    DIRECTION OUTPUT ;
    USE SIGNAL ;
    PORT
      LAYER M4 ;
        RECT  0 39.504 0.084 39.528 ;
    END
  END b[364]
  PIN b[365]
    DIRECTION OUTPUT ;
    USE SIGNAL ;
    PORT
      LAYER M4 ;
        RECT  0 39.6 0.084 39.624 ;
    END
  END b[365]
  PIN b[366]
    DIRECTION OUTPUT ;
    USE SIGNAL ;
    PORT
      LAYER M4 ;
        RECT  0 39.696 0.084 39.72 ;
    END
  END b[366]
  PIN b[367]
    DIRECTION OUTPUT ;
    USE SIGNAL ;
    PORT
      LAYER M4 ;
        RECT  0 39.792 0.084 39.816 ;
    END
  END b[367]
  PIN b[368]
    DIRECTION OUTPUT ;
    USE SIGNAL ;
    PORT
      LAYER M4 ;
        RECT  0 39.888 0.084 39.912 ;
    END
  END b[368]
  PIN b[369]
    DIRECTION OUTPUT ;
    USE SIGNAL ;
    PORT
      LAYER M4 ;
        RECT  0 39.984 0.084 40.008 ;
    END
  END b[369]
  PIN b[36]
    DIRECTION OUTPUT ;
    USE SIGNAL ;
    PORT
      LAYER M4 ;
        RECT  0 57.936 0.084 57.96 ;
    END
  END b[36]
  PIN b[370]
    DIRECTION OUTPUT ;
    USE SIGNAL ;
    PORT
      LAYER M4 ;
        RECT  0 40.08 0.084 40.104 ;
    END
  END b[370]
  PIN b[371]
    DIRECTION OUTPUT ;
    USE SIGNAL ;
    PORT
      LAYER M4 ;
        RECT  0 40.176 0.084 40.2 ;
    END
  END b[371]
  PIN b[372]
    DIRECTION OUTPUT ;
    USE SIGNAL ;
    PORT
      LAYER M4 ;
        RECT  0 40.272 0.084 40.296 ;
    END
  END b[372]
  PIN b[373]
    DIRECTION OUTPUT ;
    USE SIGNAL ;
    PORT
      LAYER M4 ;
        RECT  0 40.368 0.084 40.392 ;
    END
  END b[373]
  PIN b[374]
    DIRECTION OUTPUT ;
    USE SIGNAL ;
    PORT
      LAYER M4 ;
        RECT  0 40.464 0.084 40.488 ;
    END
  END b[374]
  PIN b[375]
    DIRECTION OUTPUT ;
    USE SIGNAL ;
    PORT
      LAYER M4 ;
        RECT  0 40.56 0.084 40.584 ;
    END
  END b[375]
  PIN b[376]
    DIRECTION OUTPUT ;
    USE SIGNAL ;
    PORT
      LAYER M4 ;
        RECT  0 40.656 0.084 40.68 ;
    END
  END b[376]
  PIN b[377]
    DIRECTION OUTPUT ;
    USE SIGNAL ;
    PORT
      LAYER M4 ;
        RECT  0 40.752 0.084 40.776 ;
    END
  END b[377]
  PIN b[378]
    DIRECTION OUTPUT ;
    USE SIGNAL ;
    PORT
      LAYER M4 ;
        RECT  0 40.848 0.084 40.872 ;
    END
  END b[378]
  PIN b[379]
    DIRECTION OUTPUT ;
    USE SIGNAL ;
    PORT
      LAYER M4 ;
        RECT  0 40.944 0.084 40.968 ;
    END
  END b[379]
  PIN b[37]
    DIRECTION OUTPUT ;
    USE SIGNAL ;
    PORT
      LAYER M4 ;
        RECT  0 58.032 0.084 58.056 ;
    END
  END b[37]
  PIN b[380]
    DIRECTION OUTPUT ;
    USE SIGNAL ;
    PORT
      LAYER M4 ;
        RECT  0 41.04 0.084 41.064 ;
    END
  END b[380]
  PIN b[381]
    DIRECTION OUTPUT ;
    USE SIGNAL ;
    PORT
      LAYER M4 ;
        RECT  0 41.136 0.084 41.16 ;
    END
  END b[381]
  PIN b[382]
    DIRECTION OUTPUT ;
    USE SIGNAL ;
    PORT
      LAYER M4 ;
        RECT  0 41.232 0.084 41.256 ;
    END
  END b[382]
  PIN b[383]
    DIRECTION OUTPUT ;
    USE SIGNAL ;
    PORT
      LAYER M4 ;
        RECT  0 41.328 0.084 41.352 ;
    END
  END b[383]
  PIN b[384]
    DIRECTION OUTPUT ;
    USE SIGNAL ;
    PORT
      LAYER M4 ;
        RECT  0 76.752 0.084 76.776 ;
    END
  END b[384]
  PIN b[385]
    DIRECTION OUTPUT ;
    USE SIGNAL ;
    PORT
      LAYER M4 ;
        RECT  0 76.848 0.084 76.872 ;
    END
  END b[385]
  PIN b[386]
    DIRECTION OUTPUT ;
    USE SIGNAL ;
    PORT
      LAYER M4 ;
        RECT  0 76.944 0.084 76.968 ;
    END
  END b[386]
  PIN b[387]
    DIRECTION OUTPUT ;
    USE SIGNAL ;
    PORT
      LAYER M4 ;
        RECT  0 77.04 0.084 77.064 ;
    END
  END b[387]
  PIN b[388]
    DIRECTION OUTPUT ;
    USE SIGNAL ;
    PORT
      LAYER M4 ;
        RECT  0 77.136 0.084 77.16 ;
    END
  END b[388]
  PIN b[389]
    DIRECTION OUTPUT ;
    USE SIGNAL ;
    PORT
      LAYER M4 ;
        RECT  0 77.232 0.084 77.256 ;
    END
  END b[389]
  PIN b[38]
    DIRECTION OUTPUT ;
    USE SIGNAL ;
    PORT
      LAYER M4 ;
        RECT  0 58.128 0.084 58.152 ;
    END
  END b[38]
  PIN b[390]
    DIRECTION OUTPUT ;
    USE SIGNAL ;
    PORT
      LAYER M4 ;
        RECT  0 77.328 0.084 77.352 ;
    END
  END b[390]
  PIN b[391]
    DIRECTION OUTPUT ;
    USE SIGNAL ;
    PORT
      LAYER M4 ;
        RECT  0 77.424 0.084 77.448 ;
    END
  END b[391]
  PIN b[392]
    DIRECTION OUTPUT ;
    USE SIGNAL ;
    PORT
      LAYER M4 ;
        RECT  0 77.52 0.084 77.544 ;
    END
  END b[392]
  PIN b[393]
    DIRECTION OUTPUT ;
    USE SIGNAL ;
    PORT
      LAYER M4 ;
        RECT  0 77.616 0.084 77.64 ;
    END
  END b[393]
  PIN b[394]
    DIRECTION OUTPUT ;
    USE SIGNAL ;
    PORT
      LAYER M4 ;
        RECT  0 77.712 0.084 77.736 ;
    END
  END b[394]
  PIN b[395]
    DIRECTION OUTPUT ;
    USE SIGNAL ;
    PORT
      LAYER M4 ;
        RECT  0 77.808 0.084 77.832 ;
    END
  END b[395]
  PIN b[396]
    DIRECTION OUTPUT ;
    USE SIGNAL ;
    PORT
      LAYER M4 ;
        RECT  0 77.904 0.084 77.928 ;
    END
  END b[396]
  PIN b[397]
    DIRECTION OUTPUT ;
    USE SIGNAL ;
    PORT
      LAYER M4 ;
        RECT  0 78 0.084 78.024 ;
    END
  END b[397]
  PIN b[398]
    DIRECTION OUTPUT ;
    USE SIGNAL ;
    PORT
      LAYER M4 ;
        RECT  0 78.096 0.084 78.12 ;
    END
  END b[398]
  PIN b[399]
    DIRECTION OUTPUT ;
    USE SIGNAL ;
    PORT
      LAYER M4 ;
        RECT  0 78.192 0.084 78.216 ;
    END
  END b[399]
  PIN b[39]
    DIRECTION OUTPUT ;
    USE SIGNAL ;
    PORT
      LAYER M4 ;
        RECT  0 58.224 0.084 58.248 ;
    END
  END b[39]
  PIN b[3]
    DIRECTION OUTPUT ;
    USE SIGNAL ;
    PORT
      LAYER M4 ;
        RECT  0 51.696 0.084 51.72 ;
    END
  END b[3]
  PIN b[400]
    DIRECTION OUTPUT ;
    USE SIGNAL ;
    PORT
      LAYER M4 ;
        RECT  0 78.288 0.084 78.312 ;
    END
  END b[400]
  PIN b[401]
    DIRECTION OUTPUT ;
    USE SIGNAL ;
    PORT
      LAYER M4 ;
        RECT  0 78.384 0.084 78.408 ;
    END
  END b[401]
  PIN b[402]
    DIRECTION OUTPUT ;
    USE SIGNAL ;
    PORT
      LAYER M4 ;
        RECT  0 78.48 0.084 78.504 ;
    END
  END b[402]
  PIN b[403]
    DIRECTION OUTPUT ;
    USE SIGNAL ;
    PORT
      LAYER M4 ;
        RECT  0 78.576 0.084 78.6 ;
    END
  END b[403]
  PIN b[404]
    DIRECTION OUTPUT ;
    USE SIGNAL ;
    PORT
      LAYER M4 ;
        RECT  0 78.672 0.084 78.696 ;
    END
  END b[404]
  PIN b[405]
    DIRECTION OUTPUT ;
    USE SIGNAL ;
    PORT
      LAYER M4 ;
        RECT  0 78.768 0.084 78.792 ;
    END
  END b[405]
  PIN b[406]
    DIRECTION OUTPUT ;
    USE SIGNAL ;
    PORT
      LAYER M4 ;
        RECT  0 78.864 0.084 78.888 ;
    END
  END b[406]
  PIN b[407]
    DIRECTION OUTPUT ;
    USE SIGNAL ;
    PORT
      LAYER M4 ;
        RECT  0 78.96 0.084 78.984 ;
    END
  END b[407]
  PIN b[408]
    DIRECTION OUTPUT ;
    USE SIGNAL ;
    PORT
      LAYER M4 ;
        RECT  0 79.056 0.084 79.08 ;
    END
  END b[408]
  PIN b[409]
    DIRECTION OUTPUT ;
    USE SIGNAL ;
    PORT
      LAYER M4 ;
        RECT  0 79.152 0.084 79.176 ;
    END
  END b[409]
  PIN b[40]
    DIRECTION OUTPUT ;
    USE SIGNAL ;
    PORT
      LAYER M4 ;
        RECT  0 58.32 0.084 58.344 ;
    END
  END b[40]
  PIN b[410]
    DIRECTION OUTPUT ;
    USE SIGNAL ;
    PORT
      LAYER M4 ;
        RECT  0 79.248 0.084 79.272 ;
    END
  END b[410]
  PIN b[411]
    DIRECTION OUTPUT ;
    USE SIGNAL ;
    PORT
      LAYER M4 ;
        RECT  0 79.344 0.084 79.368 ;
    END
  END b[411]
  PIN b[412]
    DIRECTION OUTPUT ;
    USE SIGNAL ;
    PORT
      LAYER M4 ;
        RECT  0 79.44 0.084 79.464 ;
    END
  END b[412]
  PIN b[413]
    DIRECTION OUTPUT ;
    USE SIGNAL ;
    PORT
      LAYER M4 ;
        RECT  0 79.536 0.084 79.56 ;
    END
  END b[413]
  PIN b[414]
    DIRECTION OUTPUT ;
    USE SIGNAL ;
    PORT
      LAYER M4 ;
        RECT  0 79.632 0.084 79.656 ;
    END
  END b[414]
  PIN b[415]
    DIRECTION OUTPUT ;
    USE SIGNAL ;
    PORT
      LAYER M4 ;
        RECT  0 79.728 0.084 79.752 ;
    END
  END b[415]
  PIN b[416]
    DIRECTION OUTPUT ;
    USE SIGNAL ;
    PORT
      LAYER M4 ;
        RECT  0 67.536 0.084 67.56 ;
    END
  END b[416]
  PIN b[417]
    DIRECTION OUTPUT ;
    USE SIGNAL ;
    PORT
      LAYER M4 ;
        RECT  0 67.632 0.084 67.656 ;
    END
  END b[417]
  PIN b[418]
    DIRECTION OUTPUT ;
    USE SIGNAL ;
    PORT
      LAYER M4 ;
        RECT  0 67.728 0.084 67.752 ;
    END
  END b[418]
  PIN b[419]
    DIRECTION OUTPUT ;
    USE SIGNAL ;
    PORT
      LAYER M4 ;
        RECT  0 67.824 0.084 67.848 ;
    END
  END b[419]
  PIN b[41]
    DIRECTION OUTPUT ;
    USE SIGNAL ;
    PORT
      LAYER M4 ;
        RECT  0 58.416 0.084 58.44 ;
    END
  END b[41]
  PIN b[420]
    DIRECTION OUTPUT ;
    USE SIGNAL ;
    PORT
      LAYER M4 ;
        RECT  0 67.92 0.084 67.944 ;
    END
  END b[420]
  PIN b[421]
    DIRECTION OUTPUT ;
    USE SIGNAL ;
    PORT
      LAYER M4 ;
        RECT  0 68.016 0.084 68.04 ;
    END
  END b[421]
  PIN b[422]
    DIRECTION OUTPUT ;
    USE SIGNAL ;
    PORT
      LAYER M4 ;
        RECT  0 68.112 0.084 68.136 ;
    END
  END b[422]
  PIN b[423]
    DIRECTION OUTPUT ;
    USE SIGNAL ;
    PORT
      LAYER M4 ;
        RECT  0 68.208 0.084 68.232 ;
    END
  END b[423]
  PIN b[424]
    DIRECTION OUTPUT ;
    USE SIGNAL ;
    PORT
      LAYER M4 ;
        RECT  0 68.304 0.084 68.328 ;
    END
  END b[424]
  PIN b[425]
    DIRECTION OUTPUT ;
    USE SIGNAL ;
    PORT
      LAYER M4 ;
        RECT  0 68.4 0.084 68.424 ;
    END
  END b[425]
  PIN b[426]
    DIRECTION OUTPUT ;
    USE SIGNAL ;
    PORT
      LAYER M4 ;
        RECT  0 68.496 0.084 68.52 ;
    END
  END b[426]
  PIN b[427]
    DIRECTION OUTPUT ;
    USE SIGNAL ;
    PORT
      LAYER M4 ;
        RECT  0 68.592 0.084 68.616 ;
    END
  END b[427]
  PIN b[428]
    DIRECTION OUTPUT ;
    USE SIGNAL ;
    PORT
      LAYER M4 ;
        RECT  0 68.688 0.084 68.712 ;
    END
  END b[428]
  PIN b[429]
    DIRECTION OUTPUT ;
    USE SIGNAL ;
    PORT
      LAYER M4 ;
        RECT  0 68.784 0.084 68.808 ;
    END
  END b[429]
  PIN b[42]
    DIRECTION OUTPUT ;
    USE SIGNAL ;
    PORT
      LAYER M4 ;
        RECT  0 58.512 0.084 58.536 ;
    END
  END b[42]
  PIN b[430]
    DIRECTION OUTPUT ;
    USE SIGNAL ;
    PORT
      LAYER M4 ;
        RECT  0 68.88 0.084 68.904 ;
    END
  END b[430]
  PIN b[431]
    DIRECTION OUTPUT ;
    USE SIGNAL ;
    PORT
      LAYER M4 ;
        RECT  0 68.976 0.084 69 ;
    END
  END b[431]
  PIN b[432]
    DIRECTION OUTPUT ;
    USE SIGNAL ;
    PORT
      LAYER M4 ;
        RECT  0 69.072 0.084 69.096 ;
    END
  END b[432]
  PIN b[433]
    DIRECTION OUTPUT ;
    USE SIGNAL ;
    PORT
      LAYER M4 ;
        RECT  0 69.168 0.084 69.192 ;
    END
  END b[433]
  PIN b[434]
    DIRECTION OUTPUT ;
    USE SIGNAL ;
    PORT
      LAYER M4 ;
        RECT  0 69.264 0.084 69.288 ;
    END
  END b[434]
  PIN b[435]
    DIRECTION OUTPUT ;
    USE SIGNAL ;
    PORT
      LAYER M4 ;
        RECT  0 69.36 0.084 69.384 ;
    END
  END b[435]
  PIN b[436]
    DIRECTION OUTPUT ;
    USE SIGNAL ;
    PORT
      LAYER M4 ;
        RECT  0 69.456 0.084 69.48 ;
    END
  END b[436]
  PIN b[437]
    DIRECTION OUTPUT ;
    USE SIGNAL ;
    PORT
      LAYER M4 ;
        RECT  0 69.552 0.084 69.576 ;
    END
  END b[437]
  PIN b[438]
    DIRECTION OUTPUT ;
    USE SIGNAL ;
    PORT
      LAYER M4 ;
        RECT  0 69.648 0.084 69.672 ;
    END
  END b[438]
  PIN b[439]
    DIRECTION OUTPUT ;
    USE SIGNAL ;
    PORT
      LAYER M4 ;
        RECT  0 69.744 0.084 69.768 ;
    END
  END b[439]
  PIN b[43]
    DIRECTION OUTPUT ;
    USE SIGNAL ;
    PORT
      LAYER M4 ;
        RECT  0 58.608 0.084 58.632 ;
    END
  END b[43]
  PIN b[440]
    DIRECTION OUTPUT ;
    USE SIGNAL ;
    PORT
      LAYER M4 ;
        RECT  0 69.84 0.084 69.864 ;
    END
  END b[440]
  PIN b[441]
    DIRECTION OUTPUT ;
    USE SIGNAL ;
    PORT
      LAYER M4 ;
        RECT  0 69.936 0.084 69.96 ;
    END
  END b[441]
  PIN b[442]
    DIRECTION OUTPUT ;
    USE SIGNAL ;
    PORT
      LAYER M4 ;
        RECT  0 70.032 0.084 70.056 ;
    END
  END b[442]
  PIN b[443]
    DIRECTION OUTPUT ;
    USE SIGNAL ;
    PORT
      LAYER M4 ;
        RECT  0 70.128 0.084 70.152 ;
    END
  END b[443]
  PIN b[444]
    DIRECTION OUTPUT ;
    USE SIGNAL ;
    PORT
      LAYER M4 ;
        RECT  0 70.224 0.084 70.248 ;
    END
  END b[444]
  PIN b[445]
    DIRECTION OUTPUT ;
    USE SIGNAL ;
    PORT
      LAYER M4 ;
        RECT  0 70.32 0.084 70.344 ;
    END
  END b[445]
  PIN b[446]
    DIRECTION OUTPUT ;
    USE SIGNAL ;
    PORT
      LAYER M4 ;
        RECT  0 70.416 0.084 70.44 ;
    END
  END b[446]
  PIN b[447]
    DIRECTION OUTPUT ;
    USE SIGNAL ;
    PORT
      LAYER M4 ;
        RECT  0 70.512 0.084 70.536 ;
    END
  END b[447]
  PIN b[448]
    DIRECTION OUTPUT ;
    USE SIGNAL ;
    PORT
      LAYER M4 ;
        RECT  0 79.824 0.084 79.848 ;
    END
  END b[448]
  PIN b[449]
    DIRECTION OUTPUT ;
    USE SIGNAL ;
    PORT
      LAYER M4 ;
        RECT  0 79.92 0.084 79.944 ;
    END
  END b[449]
  PIN b[44]
    DIRECTION OUTPUT ;
    USE SIGNAL ;
    PORT
      LAYER M4 ;
        RECT  0 58.704 0.084 58.728 ;
    END
  END b[44]
  PIN b[450]
    DIRECTION OUTPUT ;
    USE SIGNAL ;
    PORT
      LAYER M4 ;
        RECT  0 80.016 0.084 80.04 ;
    END
  END b[450]
  PIN b[451]
    DIRECTION OUTPUT ;
    USE SIGNAL ;
    PORT
      LAYER M4 ;
        RECT  0 80.112 0.084 80.136 ;
    END
  END b[451]
  PIN b[452]
    DIRECTION OUTPUT ;
    USE SIGNAL ;
    PORT
      LAYER M4 ;
        RECT  0 80.208 0.084 80.232 ;
    END
  END b[452]
  PIN b[453]
    DIRECTION OUTPUT ;
    USE SIGNAL ;
    PORT
      LAYER M4 ;
        RECT  0 80.304 0.084 80.328 ;
    END
  END b[453]
  PIN b[454]
    DIRECTION OUTPUT ;
    USE SIGNAL ;
    PORT
      LAYER M4 ;
        RECT  0 80.4 0.084 80.424 ;
    END
  END b[454]
  PIN b[455]
    DIRECTION OUTPUT ;
    USE SIGNAL ;
    PORT
      LAYER M4 ;
        RECT  0 80.496 0.084 80.52 ;
    END
  END b[455]
  PIN b[456]
    DIRECTION OUTPUT ;
    USE SIGNAL ;
    PORT
      LAYER M4 ;
        RECT  0 80.592 0.084 80.616 ;
    END
  END b[456]
  PIN b[457]
    DIRECTION OUTPUT ;
    USE SIGNAL ;
    PORT
      LAYER M4 ;
        RECT  0 80.688 0.084 80.712 ;
    END
  END b[457]
  PIN b[458]
    DIRECTION OUTPUT ;
    USE SIGNAL ;
    PORT
      LAYER M4 ;
        RECT  0 80.784 0.084 80.808 ;
    END
  END b[458]
  PIN b[459]
    DIRECTION OUTPUT ;
    USE SIGNAL ;
    PORT
      LAYER M4 ;
        RECT  0 80.88 0.084 80.904 ;
    END
  END b[459]
  PIN b[45]
    DIRECTION OUTPUT ;
    USE SIGNAL ;
    PORT
      LAYER M4 ;
        RECT  0 58.8 0.084 58.824 ;
    END
  END b[45]
  PIN b[460]
    DIRECTION OUTPUT ;
    USE SIGNAL ;
    PORT
      LAYER M4 ;
        RECT  0 80.976 0.084 81 ;
    END
  END b[460]
  PIN b[461]
    DIRECTION OUTPUT ;
    USE SIGNAL ;
    PORT
      LAYER M4 ;
        RECT  0 81.072 0.084 81.096 ;
    END
  END b[461]
  PIN b[462]
    DIRECTION OUTPUT ;
    USE SIGNAL ;
    PORT
      LAYER M4 ;
        RECT  0 81.168 0.084 81.192 ;
    END
  END b[462]
  PIN b[463]
    DIRECTION OUTPUT ;
    USE SIGNAL ;
    PORT
      LAYER M4 ;
        RECT  0 81.264 0.084 81.288 ;
    END
  END b[463]
  PIN b[464]
    DIRECTION OUTPUT ;
    USE SIGNAL ;
    PORT
      LAYER M4 ;
        RECT  0 81.36 0.084 81.384 ;
    END
  END b[464]
  PIN b[465]
    DIRECTION OUTPUT ;
    USE SIGNAL ;
    PORT
      LAYER M4 ;
        RECT  0 81.456 0.084 81.48 ;
    END
  END b[465]
  PIN b[466]
    DIRECTION OUTPUT ;
    USE SIGNAL ;
    PORT
      LAYER M4 ;
        RECT  0 81.552 0.084 81.576 ;
    END
  END b[466]
  PIN b[467]
    DIRECTION OUTPUT ;
    USE SIGNAL ;
    PORT
      LAYER M4 ;
        RECT  0 81.648 0.084 81.672 ;
    END
  END b[467]
  PIN b[468]
    DIRECTION OUTPUT ;
    USE SIGNAL ;
    PORT
      LAYER M4 ;
        RECT  0 81.744 0.084 81.768 ;
    END
  END b[468]
  PIN b[469]
    DIRECTION OUTPUT ;
    USE SIGNAL ;
    PORT
      LAYER M4 ;
        RECT  0 81.84 0.084 81.864 ;
    END
  END b[469]
  PIN b[46]
    DIRECTION OUTPUT ;
    USE SIGNAL ;
    PORT
      LAYER M4 ;
        RECT  0 58.896 0.084 58.92 ;
    END
  END b[46]
  PIN b[470]
    DIRECTION OUTPUT ;
    USE SIGNAL ;
    PORT
      LAYER M4 ;
        RECT  0 81.936 0.084 81.96 ;
    END
  END b[470]
  PIN b[471]
    DIRECTION OUTPUT ;
    USE SIGNAL ;
    PORT
      LAYER M4 ;
        RECT  0 82.032 0.084 82.056 ;
    END
  END b[471]
  PIN b[472]
    DIRECTION OUTPUT ;
    USE SIGNAL ;
    PORT
      LAYER M4 ;
        RECT  0 82.128 0.084 82.152 ;
    END
  END b[472]
  PIN b[473]
    DIRECTION OUTPUT ;
    USE SIGNAL ;
    PORT
      LAYER M4 ;
        RECT  0 82.224 0.084 82.248 ;
    END
  END b[473]
  PIN b[474]
    DIRECTION OUTPUT ;
    USE SIGNAL ;
    PORT
      LAYER M4 ;
        RECT  0 82.32 0.084 82.344 ;
    END
  END b[474]
  PIN b[475]
    DIRECTION OUTPUT ;
    USE SIGNAL ;
    PORT
      LAYER M4 ;
        RECT  0 82.416 0.084 82.44 ;
    END
  END b[475]
  PIN b[476]
    DIRECTION OUTPUT ;
    USE SIGNAL ;
    PORT
      LAYER M4 ;
        RECT  0 82.512 0.084 82.536 ;
    END
  END b[476]
  PIN b[477]
    DIRECTION OUTPUT ;
    USE SIGNAL ;
    PORT
      LAYER M4 ;
        RECT  0 82.608 0.084 82.632 ;
    END
  END b[477]
  PIN b[478]
    DIRECTION OUTPUT ;
    USE SIGNAL ;
    PORT
      LAYER M4 ;
        RECT  0 82.704 0.084 82.728 ;
    END
  END b[478]
  PIN b[479]
    DIRECTION OUTPUT ;
    USE SIGNAL ;
    PORT
      LAYER M4 ;
        RECT  0 82.8 0.084 82.824 ;
    END
  END b[479]
  PIN b[47]
    DIRECTION OUTPUT ;
    USE SIGNAL ;
    PORT
      LAYER M4 ;
        RECT  0 58.992 0.084 59.016 ;
    END
  END b[47]
  PIN b[480]
    DIRECTION OUTPUT ;
    USE SIGNAL ;
    PORT
      LAYER M4 ;
        RECT  0 73.68 0.084 73.704 ;
    END
  END b[480]
  PIN b[481]
    DIRECTION OUTPUT ;
    USE SIGNAL ;
    PORT
      LAYER M4 ;
        RECT  0 73.776 0.084 73.8 ;
    END
  END b[481]
  PIN b[482]
    DIRECTION OUTPUT ;
    USE SIGNAL ;
    PORT
      LAYER M4 ;
        RECT  0 73.872 0.084 73.896 ;
    END
  END b[482]
  PIN b[483]
    DIRECTION OUTPUT ;
    USE SIGNAL ;
    PORT
      LAYER M4 ;
        RECT  0 73.968 0.084 73.992 ;
    END
  END b[483]
  PIN b[484]
    DIRECTION OUTPUT ;
    USE SIGNAL ;
    PORT
      LAYER M4 ;
        RECT  0 74.064 0.084 74.088 ;
    END
  END b[484]
  PIN b[485]
    DIRECTION OUTPUT ;
    USE SIGNAL ;
    PORT
      LAYER M4 ;
        RECT  0 74.16 0.084 74.184 ;
    END
  END b[485]
  PIN b[486]
    DIRECTION OUTPUT ;
    USE SIGNAL ;
    PORT
      LAYER M4 ;
        RECT  0 74.256 0.084 74.28 ;
    END
  END b[486]
  PIN b[487]
    DIRECTION OUTPUT ;
    USE SIGNAL ;
    PORT
      LAYER M4 ;
        RECT  0 74.352 0.084 74.376 ;
    END
  END b[487]
  PIN b[488]
    DIRECTION OUTPUT ;
    USE SIGNAL ;
    PORT
      LAYER M4 ;
        RECT  0 74.448 0.084 74.472 ;
    END
  END b[488]
  PIN b[489]
    DIRECTION OUTPUT ;
    USE SIGNAL ;
    PORT
      LAYER M4 ;
        RECT  0 74.544 0.084 74.568 ;
    END
  END b[489]
  PIN b[48]
    DIRECTION OUTPUT ;
    USE SIGNAL ;
    PORT
      LAYER M4 ;
        RECT  0 59.088 0.084 59.112 ;
    END
  END b[48]
  PIN b[490]
    DIRECTION OUTPUT ;
    USE SIGNAL ;
    PORT
      LAYER M4 ;
        RECT  0 74.64 0.084 74.664 ;
    END
  END b[490]
  PIN b[491]
    DIRECTION OUTPUT ;
    USE SIGNAL ;
    PORT
      LAYER M4 ;
        RECT  0 74.736 0.084 74.76 ;
    END
  END b[491]
  PIN b[492]
    DIRECTION OUTPUT ;
    USE SIGNAL ;
    PORT
      LAYER M4 ;
        RECT  0 74.832 0.084 74.856 ;
    END
  END b[492]
  PIN b[493]
    DIRECTION OUTPUT ;
    USE SIGNAL ;
    PORT
      LAYER M4 ;
        RECT  0 74.928 0.084 74.952 ;
    END
  END b[493]
  PIN b[494]
    DIRECTION OUTPUT ;
    USE SIGNAL ;
    PORT
      LAYER M4 ;
        RECT  0 75.024 0.084 75.048 ;
    END
  END b[494]
  PIN b[495]
    DIRECTION OUTPUT ;
    USE SIGNAL ;
    PORT
      LAYER M4 ;
        RECT  0 75.12 0.084 75.144 ;
    END
  END b[495]
  PIN b[496]
    DIRECTION OUTPUT ;
    USE SIGNAL ;
    PORT
      LAYER M4 ;
        RECT  0 75.216 0.084 75.24 ;
    END
  END b[496]
  PIN b[497]
    DIRECTION OUTPUT ;
    USE SIGNAL ;
    PORT
      LAYER M4 ;
        RECT  0 75.312 0.084 75.336 ;
    END
  END b[497]
  PIN b[498]
    DIRECTION OUTPUT ;
    USE SIGNAL ;
    PORT
      LAYER M4 ;
        RECT  0 75.408 0.084 75.432 ;
    END
  END b[498]
  PIN b[499]
    DIRECTION OUTPUT ;
    USE SIGNAL ;
    PORT
      LAYER M4 ;
        RECT  0 75.504 0.084 75.528 ;
    END
  END b[499]
  PIN b[49]
    DIRECTION OUTPUT ;
    USE SIGNAL ;
    PORT
      LAYER M4 ;
        RECT  0 59.184 0.084 59.208 ;
    END
  END b[49]
  PIN b[4]
    DIRECTION OUTPUT ;
    USE SIGNAL ;
    PORT
      LAYER M4 ;
        RECT  0 51.792 0.084 51.816 ;
    END
  END b[4]
  PIN b[500]
    DIRECTION OUTPUT ;
    USE SIGNAL ;
    PORT
      LAYER M4 ;
        RECT  0 75.6 0.084 75.624 ;
    END
  END b[500]
  PIN b[501]
    DIRECTION OUTPUT ;
    USE SIGNAL ;
    PORT
      LAYER M4 ;
        RECT  0 75.696 0.084 75.72 ;
    END
  END b[501]
  PIN b[502]
    DIRECTION OUTPUT ;
    USE SIGNAL ;
    PORT
      LAYER M4 ;
        RECT  0 75.792 0.084 75.816 ;
    END
  END b[502]
  PIN b[503]
    DIRECTION OUTPUT ;
    USE SIGNAL ;
    PORT
      LAYER M4 ;
        RECT  0 75.888 0.084 75.912 ;
    END
  END b[503]
  PIN b[504]
    DIRECTION OUTPUT ;
    USE SIGNAL ;
    PORT
      LAYER M4 ;
        RECT  0 75.984 0.084 76.008 ;
    END
  END b[504]
  PIN b[505]
    DIRECTION OUTPUT ;
    USE SIGNAL ;
    PORT
      LAYER M4 ;
        RECT  0 76.08 0.084 76.104 ;
    END
  END b[505]
  PIN b[506]
    DIRECTION OUTPUT ;
    USE SIGNAL ;
    PORT
      LAYER M4 ;
        RECT  0 76.176 0.084 76.2 ;
    END
  END b[506]
  PIN b[507]
    DIRECTION OUTPUT ;
    USE SIGNAL ;
    PORT
      LAYER M4 ;
        RECT  0 76.272 0.084 76.296 ;
    END
  END b[507]
  PIN b[508]
    DIRECTION OUTPUT ;
    USE SIGNAL ;
    PORT
      LAYER M4 ;
        RECT  0 76.368 0.084 76.392 ;
    END
  END b[508]
  PIN b[509]
    DIRECTION OUTPUT ;
    USE SIGNAL ;
    PORT
      LAYER M4 ;
        RECT  0 76.464 0.084 76.488 ;
    END
  END b[509]
  PIN b[50]
    DIRECTION OUTPUT ;
    USE SIGNAL ;
    PORT
      LAYER M4 ;
        RECT  0 59.28 0.084 59.304 ;
    END
  END b[50]
  PIN b[510]
    DIRECTION OUTPUT ;
    USE SIGNAL ;
    PORT
      LAYER M4 ;
        RECT  0 76.56 0.084 76.584 ;
    END
  END b[510]
  PIN b[511]
    DIRECTION OUTPUT ;
    USE SIGNAL ;
    PORT
      LAYER M4 ;
        RECT  0 76.656 0.084 76.68 ;
    END
  END b[511]
  PIN b[512]
    DIRECTION OUTPUT ;
    USE SIGNAL ;
    PORT
      LAYER M4 ;
        RECT  0 70.608 0.084 70.632 ;
    END
  END b[512]
  PIN b[513]
    DIRECTION OUTPUT ;
    USE SIGNAL ;
    PORT
      LAYER M4 ;
        RECT  0 70.704 0.084 70.728 ;
    END
  END b[513]
  PIN b[514]
    DIRECTION OUTPUT ;
    USE SIGNAL ;
    PORT
      LAYER M4 ;
        RECT  0 70.8 0.084 70.824 ;
    END
  END b[514]
  PIN b[515]
    DIRECTION OUTPUT ;
    USE SIGNAL ;
    PORT
      LAYER M4 ;
        RECT  0 70.896 0.084 70.92 ;
    END
  END b[515]
  PIN b[516]
    DIRECTION OUTPUT ;
    USE SIGNAL ;
    PORT
      LAYER M4 ;
        RECT  0 70.992 0.084 71.016 ;
    END
  END b[516]
  PIN b[517]
    DIRECTION OUTPUT ;
    USE SIGNAL ;
    PORT
      LAYER M4 ;
        RECT  0 71.088 0.084 71.112 ;
    END
  END b[517]
  PIN b[518]
    DIRECTION OUTPUT ;
    USE SIGNAL ;
    PORT
      LAYER M4 ;
        RECT  0 71.184 0.084 71.208 ;
    END
  END b[518]
  PIN b[519]
    DIRECTION OUTPUT ;
    USE SIGNAL ;
    PORT
      LAYER M4 ;
        RECT  0 71.28 0.084 71.304 ;
    END
  END b[519]
  PIN b[51]
    DIRECTION OUTPUT ;
    USE SIGNAL ;
    PORT
      LAYER M4 ;
        RECT  0 59.376 0.084 59.4 ;
    END
  END b[51]
  PIN b[520]
    DIRECTION OUTPUT ;
    USE SIGNAL ;
    PORT
      LAYER M4 ;
        RECT  0 71.376 0.084 71.4 ;
    END
  END b[520]
  PIN b[521]
    DIRECTION OUTPUT ;
    USE SIGNAL ;
    PORT
      LAYER M4 ;
        RECT  0 71.472 0.084 71.496 ;
    END
  END b[521]
  PIN b[522]
    DIRECTION OUTPUT ;
    USE SIGNAL ;
    PORT
      LAYER M4 ;
        RECT  0 71.568 0.084 71.592 ;
    END
  END b[522]
  PIN b[523]
    DIRECTION OUTPUT ;
    USE SIGNAL ;
    PORT
      LAYER M4 ;
        RECT  0 71.664 0.084 71.688 ;
    END
  END b[523]
  PIN b[524]
    DIRECTION OUTPUT ;
    USE SIGNAL ;
    PORT
      LAYER M4 ;
        RECT  0 71.76 0.084 71.784 ;
    END
  END b[524]
  PIN b[525]
    DIRECTION OUTPUT ;
    USE SIGNAL ;
    PORT
      LAYER M4 ;
        RECT  0 71.856 0.084 71.88 ;
    END
  END b[525]
  PIN b[526]
    DIRECTION OUTPUT ;
    USE SIGNAL ;
    PORT
      LAYER M4 ;
        RECT  0 71.952 0.084 71.976 ;
    END
  END b[526]
  PIN b[527]
    DIRECTION OUTPUT ;
    USE SIGNAL ;
    PORT
      LAYER M4 ;
        RECT  0 72.048 0.084 72.072 ;
    END
  END b[527]
  PIN b[528]
    DIRECTION OUTPUT ;
    USE SIGNAL ;
    PORT
      LAYER M4 ;
        RECT  0 72.144 0.084 72.168 ;
    END
  END b[528]
  PIN b[529]
    DIRECTION OUTPUT ;
    USE SIGNAL ;
    PORT
      LAYER M4 ;
        RECT  0 72.24 0.084 72.264 ;
    END
  END b[529]
  PIN b[52]
    DIRECTION OUTPUT ;
    USE SIGNAL ;
    PORT
      LAYER M4 ;
        RECT  0 59.472 0.084 59.496 ;
    END
  END b[52]
  PIN b[530]
    DIRECTION OUTPUT ;
    USE SIGNAL ;
    PORT
      LAYER M4 ;
        RECT  0 72.336 0.084 72.36 ;
    END
  END b[530]
  PIN b[531]
    DIRECTION OUTPUT ;
    USE SIGNAL ;
    PORT
      LAYER M4 ;
        RECT  0 72.432 0.084 72.456 ;
    END
  END b[531]
  PIN b[532]
    DIRECTION OUTPUT ;
    USE SIGNAL ;
    PORT
      LAYER M4 ;
        RECT  0 72.528 0.084 72.552 ;
    END
  END b[532]
  PIN b[533]
    DIRECTION OUTPUT ;
    USE SIGNAL ;
    PORT
      LAYER M4 ;
        RECT  0 72.624 0.084 72.648 ;
    END
  END b[533]
  PIN b[534]
    DIRECTION OUTPUT ;
    USE SIGNAL ;
    PORT
      LAYER M4 ;
        RECT  0 72.72 0.084 72.744 ;
    END
  END b[534]
  PIN b[535]
    DIRECTION OUTPUT ;
    USE SIGNAL ;
    PORT
      LAYER M4 ;
        RECT  0 72.816 0.084 72.84 ;
    END
  END b[535]
  PIN b[536]
    DIRECTION OUTPUT ;
    USE SIGNAL ;
    PORT
      LAYER M4 ;
        RECT  0 72.912 0.084 72.936 ;
    END
  END b[536]
  PIN b[537]
    DIRECTION OUTPUT ;
    USE SIGNAL ;
    PORT
      LAYER M4 ;
        RECT  0 73.008 0.084 73.032 ;
    END
  END b[537]
  PIN b[538]
    DIRECTION OUTPUT ;
    USE SIGNAL ;
    PORT
      LAYER M4 ;
        RECT  0 73.104 0.084 73.128 ;
    END
  END b[538]
  PIN b[539]
    DIRECTION OUTPUT ;
    USE SIGNAL ;
    PORT
      LAYER M4 ;
        RECT  0 73.2 0.084 73.224 ;
    END
  END b[539]
  PIN b[53]
    DIRECTION OUTPUT ;
    USE SIGNAL ;
    PORT
      LAYER M4 ;
        RECT  0 59.568 0.084 59.592 ;
    END
  END b[53]
  PIN b[540]
    DIRECTION OUTPUT ;
    USE SIGNAL ;
    PORT
      LAYER M4 ;
        RECT  0 73.296 0.084 73.32 ;
    END
  END b[540]
  PIN b[541]
    DIRECTION OUTPUT ;
    USE SIGNAL ;
    PORT
      LAYER M4 ;
        RECT  0 73.392 0.084 73.416 ;
    END
  END b[541]
  PIN b[542]
    DIRECTION OUTPUT ;
    USE SIGNAL ;
    PORT
      LAYER M4 ;
        RECT  0 73.488 0.084 73.512 ;
    END
  END b[542]
  PIN b[543]
    DIRECTION OUTPUT ;
    USE SIGNAL ;
    PORT
      LAYER M4 ;
        RECT  0 73.584 0.084 73.608 ;
    END
  END b[543]
  PIN b[544]
    DIRECTION OUTPUT ;
    USE SIGNAL ;
    PORT
      LAYER M4 ;
        RECT  0 82.896 0.084 82.92 ;
    END
  END b[544]
  PIN b[545]
    DIRECTION OUTPUT ;
    USE SIGNAL ;
    PORT
      LAYER M4 ;
        RECT  0 82.992 0.084 83.016 ;
    END
  END b[545]
  PIN b[546]
    DIRECTION OUTPUT ;
    USE SIGNAL ;
    PORT
      LAYER M4 ;
        RECT  0 83.088 0.084 83.112 ;
    END
  END b[546]
  PIN b[547]
    DIRECTION OUTPUT ;
    USE SIGNAL ;
    PORT
      LAYER M4 ;
        RECT  0 83.184 0.084 83.208 ;
    END
  END b[547]
  PIN b[548]
    DIRECTION OUTPUT ;
    USE SIGNAL ;
    PORT
      LAYER M4 ;
        RECT  0 83.28 0.084 83.304 ;
    END
  END b[548]
  PIN b[549]
    DIRECTION OUTPUT ;
    USE SIGNAL ;
    PORT
      LAYER M4 ;
        RECT  0 83.376 0.084 83.4 ;
    END
  END b[549]
  PIN b[54]
    DIRECTION OUTPUT ;
    USE SIGNAL ;
    PORT
      LAYER M4 ;
        RECT  0 59.664 0.084 59.688 ;
    END
  END b[54]
  PIN b[550]
    DIRECTION OUTPUT ;
    USE SIGNAL ;
    PORT
      LAYER M4 ;
        RECT  0 83.472 0.084 83.496 ;
    END
  END b[550]
  PIN b[551]
    DIRECTION OUTPUT ;
    USE SIGNAL ;
    PORT
      LAYER M4 ;
        RECT  0 83.568 0.084 83.592 ;
    END
  END b[551]
  PIN b[552]
    DIRECTION OUTPUT ;
    USE SIGNAL ;
    PORT
      LAYER M4 ;
        RECT  0 83.664 0.084 83.688 ;
    END
  END b[552]
  PIN b[553]
    DIRECTION OUTPUT ;
    USE SIGNAL ;
    PORT
      LAYER M4 ;
        RECT  0 83.76 0.084 83.784 ;
    END
  END b[553]
  PIN b[554]
    DIRECTION OUTPUT ;
    USE SIGNAL ;
    PORT
      LAYER M4 ;
        RECT  0 83.856 0.084 83.88 ;
    END
  END b[554]
  PIN b[555]
    DIRECTION OUTPUT ;
    USE SIGNAL ;
    PORT
      LAYER M4 ;
        RECT  0 83.952 0.084 83.976 ;
    END
  END b[555]
  PIN b[556]
    DIRECTION OUTPUT ;
    USE SIGNAL ;
    PORT
      LAYER M4 ;
        RECT  0 84.048 0.084 84.072 ;
    END
  END b[556]
  PIN b[557]
    DIRECTION OUTPUT ;
    USE SIGNAL ;
    PORT
      LAYER M4 ;
        RECT  0 84.144 0.084 84.168 ;
    END
  END b[557]
  PIN b[558]
    DIRECTION OUTPUT ;
    USE SIGNAL ;
    PORT
      LAYER M4 ;
        RECT  0 84.24 0.084 84.264 ;
    END
  END b[558]
  PIN b[559]
    DIRECTION OUTPUT ;
    USE SIGNAL ;
    PORT
      LAYER M4 ;
        RECT  0 84.336 0.084 84.36 ;
    END
  END b[559]
  PIN b[55]
    DIRECTION OUTPUT ;
    USE SIGNAL ;
    PORT
      LAYER M4 ;
        RECT  0 59.76 0.084 59.784 ;
    END
  END b[55]
  PIN b[560]
    DIRECTION OUTPUT ;
    USE SIGNAL ;
    PORT
      LAYER M4 ;
        RECT  0 84.432 0.084 84.456 ;
    END
  END b[560]
  PIN b[561]
    DIRECTION OUTPUT ;
    USE SIGNAL ;
    PORT
      LAYER M4 ;
        RECT  0 84.528 0.084 84.552 ;
    END
  END b[561]
  PIN b[562]
    DIRECTION OUTPUT ;
    USE SIGNAL ;
    PORT
      LAYER M4 ;
        RECT  0 84.624 0.084 84.648 ;
    END
  END b[562]
  PIN b[563]
    DIRECTION OUTPUT ;
    USE SIGNAL ;
    PORT
      LAYER M4 ;
        RECT  0 84.72 0.084 84.744 ;
    END
  END b[563]
  PIN b[564]
    DIRECTION OUTPUT ;
    USE SIGNAL ;
    PORT
      LAYER M4 ;
        RECT  0 84.816 0.084 84.84 ;
    END
  END b[564]
  PIN b[565]
    DIRECTION OUTPUT ;
    USE SIGNAL ;
    PORT
      LAYER M4 ;
        RECT  0 84.912 0.084 84.936 ;
    END
  END b[565]
  PIN b[566]
    DIRECTION OUTPUT ;
    USE SIGNAL ;
    PORT
      LAYER M4 ;
        RECT  0 85.008 0.084 85.032 ;
    END
  END b[566]
  PIN b[567]
    DIRECTION OUTPUT ;
    USE SIGNAL ;
    PORT
      LAYER M4 ;
        RECT  0 85.104 0.084 85.128 ;
    END
  END b[567]
  PIN b[568]
    DIRECTION OUTPUT ;
    USE SIGNAL ;
    PORT
      LAYER M4 ;
        RECT  0 85.2 0.084 85.224 ;
    END
  END b[568]
  PIN b[569]
    DIRECTION OUTPUT ;
    USE SIGNAL ;
    PORT
      LAYER M4 ;
        RECT  0 85.296 0.084 85.32 ;
    END
  END b[569]
  PIN b[56]
    DIRECTION OUTPUT ;
    USE SIGNAL ;
    PORT
      LAYER M4 ;
        RECT  0 59.856 0.084 59.88 ;
    END
  END b[56]
  PIN b[570]
    DIRECTION OUTPUT ;
    USE SIGNAL ;
    PORT
      LAYER M4 ;
        RECT  0 85.392 0.084 85.416 ;
    END
  END b[570]
  PIN b[571]
    DIRECTION OUTPUT ;
    USE SIGNAL ;
    PORT
      LAYER M4 ;
        RECT  0 85.488 0.084 85.512 ;
    END
  END b[571]
  PIN b[572]
    DIRECTION OUTPUT ;
    USE SIGNAL ;
    PORT
      LAYER M4 ;
        RECT  0 85.584 0.084 85.608 ;
    END
  END b[572]
  PIN b[573]
    DIRECTION OUTPUT ;
    USE SIGNAL ;
    PORT
      LAYER M4 ;
        RECT  0 85.68 0.084 85.704 ;
    END
  END b[573]
  PIN b[574]
    DIRECTION OUTPUT ;
    USE SIGNAL ;
    PORT
      LAYER M4 ;
        RECT  0 85.776 0.084 85.8 ;
    END
  END b[574]
  PIN b[575]
    DIRECTION OUTPUT ;
    USE SIGNAL ;
    PORT
      LAYER M4 ;
        RECT  0 85.872 0.084 85.896 ;
    END
  END b[575]
  PIN b[576]
    DIRECTION OUTPUT ;
    USE SIGNAL ;
    PORT
      LAYER M4 ;
        RECT  0 25.968 0.084 25.992 ;
    END
  END b[576]
  PIN b[577]
    DIRECTION OUTPUT ;
    USE SIGNAL ;
    PORT
      LAYER M4 ;
        RECT  0 26.064 0.084 26.088 ;
    END
  END b[577]
  PIN b[578]
    DIRECTION OUTPUT ;
    USE SIGNAL ;
    PORT
      LAYER M4 ;
        RECT  0 26.16 0.084 26.184 ;
    END
  END b[578]
  PIN b[579]
    DIRECTION OUTPUT ;
    USE SIGNAL ;
    PORT
      LAYER M4 ;
        RECT  0 26.256 0.084 26.28 ;
    END
  END b[579]
  PIN b[57]
    DIRECTION OUTPUT ;
    USE SIGNAL ;
    PORT
      LAYER M4 ;
        RECT  0 59.952 0.084 59.976 ;
    END
  END b[57]
  PIN b[580]
    DIRECTION OUTPUT ;
    USE SIGNAL ;
    PORT
      LAYER M4 ;
        RECT  0 26.352 0.084 26.376 ;
    END
  END b[580]
  PIN b[581]
    DIRECTION OUTPUT ;
    USE SIGNAL ;
    PORT
      LAYER M4 ;
        RECT  0 26.448 0.084 26.472 ;
    END
  END b[581]
  PIN b[582]
    DIRECTION OUTPUT ;
    USE SIGNAL ;
    PORT
      LAYER M4 ;
        RECT  0 26.544 0.084 26.568 ;
    END
  END b[582]
  PIN b[583]
    DIRECTION OUTPUT ;
    USE SIGNAL ;
    PORT
      LAYER M4 ;
        RECT  0 26.64 0.084 26.664 ;
    END
  END b[583]
  PIN b[584]
    DIRECTION OUTPUT ;
    USE SIGNAL ;
    PORT
      LAYER M4 ;
        RECT  0 26.736 0.084 26.76 ;
    END
  END b[584]
  PIN b[585]
    DIRECTION OUTPUT ;
    USE SIGNAL ;
    PORT
      LAYER M4 ;
        RECT  0 26.832 0.084 26.856 ;
    END
  END b[585]
  PIN b[586]
    DIRECTION OUTPUT ;
    USE SIGNAL ;
    PORT
      LAYER M4 ;
        RECT  0 26.928 0.084 26.952 ;
    END
  END b[586]
  PIN b[587]
    DIRECTION OUTPUT ;
    USE SIGNAL ;
    PORT
      LAYER M4 ;
        RECT  0 27.024 0.084 27.048 ;
    END
  END b[587]
  PIN b[588]
    DIRECTION OUTPUT ;
    USE SIGNAL ;
    PORT
      LAYER M4 ;
        RECT  0 27.12 0.084 27.144 ;
    END
  END b[588]
  PIN b[589]
    DIRECTION OUTPUT ;
    USE SIGNAL ;
    PORT
      LAYER M4 ;
        RECT  0 27.216 0.084 27.24 ;
    END
  END b[589]
  PIN b[58]
    DIRECTION OUTPUT ;
    USE SIGNAL ;
    PORT
      LAYER M4 ;
        RECT  0 60.048 0.084 60.072 ;
    END
  END b[58]
  PIN b[590]
    DIRECTION OUTPUT ;
    USE SIGNAL ;
    PORT
      LAYER M4 ;
        RECT  0 27.312 0.084 27.336 ;
    END
  END b[590]
  PIN b[591]
    DIRECTION OUTPUT ;
    USE SIGNAL ;
    PORT
      LAYER M4 ;
        RECT  0 27.408 0.084 27.432 ;
    END
  END b[591]
  PIN b[592]
    DIRECTION OUTPUT ;
    USE SIGNAL ;
    PORT
      LAYER M4 ;
        RECT  0 27.504 0.084 27.528 ;
    END
  END b[592]
  PIN b[593]
    DIRECTION OUTPUT ;
    USE SIGNAL ;
    PORT
      LAYER M4 ;
        RECT  0 27.6 0.084 27.624 ;
    END
  END b[593]
  PIN b[594]
    DIRECTION OUTPUT ;
    USE SIGNAL ;
    PORT
      LAYER M4 ;
        RECT  0 27.696 0.084 27.72 ;
    END
  END b[594]
  PIN b[595]
    DIRECTION OUTPUT ;
    USE SIGNAL ;
    PORT
      LAYER M4 ;
        RECT  0 27.792 0.084 27.816 ;
    END
  END b[595]
  PIN b[596]
    DIRECTION OUTPUT ;
    USE SIGNAL ;
    PORT
      LAYER M4 ;
        RECT  0 27.888 0.084 27.912 ;
    END
  END b[596]
  PIN b[597]
    DIRECTION OUTPUT ;
    USE SIGNAL ;
    PORT
      LAYER M4 ;
        RECT  0 27.984 0.084 28.008 ;
    END
  END b[597]
  PIN b[598]
    DIRECTION OUTPUT ;
    USE SIGNAL ;
    PORT
      LAYER M4 ;
        RECT  0 28.08 0.084 28.104 ;
    END
  END b[598]
  PIN b[599]
    DIRECTION OUTPUT ;
    USE SIGNAL ;
    PORT
      LAYER M4 ;
        RECT  0 28.176 0.084 28.2 ;
    END
  END b[599]
  PIN b[59]
    DIRECTION OUTPUT ;
    USE SIGNAL ;
    PORT
      LAYER M4 ;
        RECT  0 60.144 0.084 60.168 ;
    END
  END b[59]
  PIN b[5]
    DIRECTION OUTPUT ;
    USE SIGNAL ;
    PORT
      LAYER M4 ;
        RECT  0 51.888 0.084 51.912 ;
    END
  END b[5]
  PIN b[60]
    DIRECTION OUTPUT ;
    USE SIGNAL ;
    PORT
      LAYER M4 ;
        RECT  0 60.24 0.084 60.264 ;
    END
  END b[60]
  PIN b[61]
    DIRECTION OUTPUT ;
    USE SIGNAL ;
    PORT
      LAYER M4 ;
        RECT  0 60.336 0.084 60.36 ;
    END
  END b[61]
  PIN b[62]
    DIRECTION OUTPUT ;
    USE SIGNAL ;
    PORT
      LAYER M4 ;
        RECT  0 60.432 0.084 60.456 ;
    END
  END b[62]
  PIN b[63]
    DIRECTION OUTPUT ;
    USE SIGNAL ;
    PORT
      LAYER M4 ;
        RECT  0 60.528 0.084 60.552 ;
    END
  END b[63]
  PIN b[64]
    DIRECTION OUTPUT ;
    USE SIGNAL ;
    PORT
      LAYER M4 ;
        RECT  0 54.48 0.084 54.504 ;
    END
  END b[64]
  PIN b[65]
    DIRECTION OUTPUT ;
    USE SIGNAL ;
    PORT
      LAYER M4 ;
        RECT  0 54.576 0.084 54.6 ;
    END
  END b[65]
  PIN b[66]
    DIRECTION OUTPUT ;
    USE SIGNAL ;
    PORT
      LAYER M4 ;
        RECT  0 54.672 0.084 54.696 ;
    END
  END b[66]
  PIN b[67]
    DIRECTION OUTPUT ;
    USE SIGNAL ;
    PORT
      LAYER M4 ;
        RECT  0 54.768 0.084 54.792 ;
    END
  END b[67]
  PIN b[68]
    DIRECTION OUTPUT ;
    USE SIGNAL ;
    PORT
      LAYER M4 ;
        RECT  0 54.864 0.084 54.888 ;
    END
  END b[68]
  PIN b[69]
    DIRECTION OUTPUT ;
    USE SIGNAL ;
    PORT
      LAYER M4 ;
        RECT  0 54.96 0.084 54.984 ;
    END
  END b[69]
  PIN b[6]
    DIRECTION OUTPUT ;
    USE SIGNAL ;
    PORT
      LAYER M4 ;
        RECT  0 51.984 0.084 52.008 ;
    END
  END b[6]
  PIN b[70]
    DIRECTION OUTPUT ;
    USE SIGNAL ;
    PORT
      LAYER M4 ;
        RECT  0 55.056 0.084 55.08 ;
    END
  END b[70]
  PIN b[71]
    DIRECTION OUTPUT ;
    USE SIGNAL ;
    PORT
      LAYER M4 ;
        RECT  0 55.152 0.084 55.176 ;
    END
  END b[71]
  PIN b[72]
    DIRECTION OUTPUT ;
    USE SIGNAL ;
    PORT
      LAYER M4 ;
        RECT  0 55.248 0.084 55.272 ;
    END
  END b[72]
  PIN b[73]
    DIRECTION OUTPUT ;
    USE SIGNAL ;
    PORT
      LAYER M4 ;
        RECT  0 55.344 0.084 55.368 ;
    END
  END b[73]
  PIN b[74]
    DIRECTION OUTPUT ;
    USE SIGNAL ;
    PORT
      LAYER M4 ;
        RECT  0 55.44 0.084 55.464 ;
    END
  END b[74]
  PIN b[75]
    DIRECTION OUTPUT ;
    USE SIGNAL ;
    PORT
      LAYER M4 ;
        RECT  0 55.536 0.084 55.56 ;
    END
  END b[75]
  PIN b[76]
    DIRECTION OUTPUT ;
    USE SIGNAL ;
    PORT
      LAYER M4 ;
        RECT  0 55.632 0.084 55.656 ;
    END
  END b[76]
  PIN b[77]
    DIRECTION OUTPUT ;
    USE SIGNAL ;
    PORT
      LAYER M4 ;
        RECT  0 55.728 0.084 55.752 ;
    END
  END b[77]
  PIN b[78]
    DIRECTION OUTPUT ;
    USE SIGNAL ;
    PORT
      LAYER M4 ;
        RECT  0 55.824 0.084 55.848 ;
    END
  END b[78]
  PIN b[79]
    DIRECTION OUTPUT ;
    USE SIGNAL ;
    PORT
      LAYER M4 ;
        RECT  0 55.92 0.084 55.944 ;
    END
  END b[79]
  PIN b[7]
    DIRECTION OUTPUT ;
    USE SIGNAL ;
    PORT
      LAYER M4 ;
        RECT  0 52.08 0.084 52.104 ;
    END
  END b[7]
  PIN b[80]
    DIRECTION OUTPUT ;
    USE SIGNAL ;
    PORT
      LAYER M4 ;
        RECT  0 56.016 0.084 56.04 ;
    END
  END b[80]
  PIN b[81]
    DIRECTION OUTPUT ;
    USE SIGNAL ;
    PORT
      LAYER M4 ;
        RECT  0 56.112 0.084 56.136 ;
    END
  END b[81]
  PIN b[82]
    DIRECTION OUTPUT ;
    USE SIGNAL ;
    PORT
      LAYER M4 ;
        RECT  0 56.208 0.084 56.232 ;
    END
  END b[82]
  PIN b[83]
    DIRECTION OUTPUT ;
    USE SIGNAL ;
    PORT
      LAYER M4 ;
        RECT  0 56.304 0.084 56.328 ;
    END
  END b[83]
  PIN b[84]
    DIRECTION OUTPUT ;
    USE SIGNAL ;
    PORT
      LAYER M4 ;
        RECT  0 56.4 0.084 56.424 ;
    END
  END b[84]
  PIN b[85]
    DIRECTION OUTPUT ;
    USE SIGNAL ;
    PORT
      LAYER M4 ;
        RECT  0 56.496 0.084 56.52 ;
    END
  END b[85]
  PIN b[86]
    DIRECTION OUTPUT ;
    USE SIGNAL ;
    PORT
      LAYER M4 ;
        RECT  0 56.592 0.084 56.616 ;
    END
  END b[86]
  PIN b[87]
    DIRECTION OUTPUT ;
    USE SIGNAL ;
    PORT
      LAYER M4 ;
        RECT  0 56.688 0.084 56.712 ;
    END
  END b[87]
  PIN b[88]
    DIRECTION OUTPUT ;
    USE SIGNAL ;
    PORT
      LAYER M4 ;
        RECT  0 56.784 0.084 56.808 ;
    END
  END b[88]
  PIN b[89]
    DIRECTION OUTPUT ;
    USE SIGNAL ;
    PORT
      LAYER M4 ;
        RECT  0 56.88 0.084 56.904 ;
    END
  END b[89]
  PIN b[8]
    DIRECTION OUTPUT ;
    USE SIGNAL ;
    PORT
      LAYER M4 ;
        RECT  0 52.176 0.084 52.2 ;
    END
  END b[8]
  PIN b[90]
    DIRECTION OUTPUT ;
    USE SIGNAL ;
    PORT
      LAYER M4 ;
        RECT  0 56.976 0.084 57 ;
    END
  END b[90]
  PIN b[91]
    DIRECTION OUTPUT ;
    USE SIGNAL ;
    PORT
      LAYER M4 ;
        RECT  0 57.072 0.084 57.096 ;
    END
  END b[91]
  PIN b[92]
    DIRECTION OUTPUT ;
    USE SIGNAL ;
    PORT
      LAYER M4 ;
        RECT  0 57.168 0.084 57.192 ;
    END
  END b[92]
  PIN b[93]
    DIRECTION OUTPUT ;
    USE SIGNAL ;
    PORT
      LAYER M4 ;
        RECT  0 57.264 0.084 57.288 ;
    END
  END b[93]
  PIN b[94]
    DIRECTION OUTPUT ;
    USE SIGNAL ;
    PORT
      LAYER M4 ;
        RECT  0 57.36 0.084 57.384 ;
    END
  END b[94]
  PIN b[95]
    DIRECTION OUTPUT ;
    USE SIGNAL ;
    PORT
      LAYER M4 ;
        RECT  0 57.456 0.084 57.48 ;
    END
  END b[95]
  PIN b[96]
    DIRECTION OUTPUT ;
    USE SIGNAL ;
    PORT
      LAYER M4 ;
        RECT  0 48.336 0.084 48.36 ;
    END
  END b[96]
  PIN b[97]
    DIRECTION OUTPUT ;
    USE SIGNAL ;
    PORT
      LAYER M4 ;
        RECT  0 48.432 0.084 48.456 ;
    END
  END b[97]
  PIN b[98]
    DIRECTION OUTPUT ;
    USE SIGNAL ;
    PORT
      LAYER M4 ;
        RECT  0 48.528 0.084 48.552 ;
    END
  END b[98]
  PIN b[99]
    DIRECTION OUTPUT ;
    USE SIGNAL ;
    PORT
      LAYER M4 ;
        RECT  0 48.624 0.084 48.648 ;
    END
  END b[99]
  PIN b[9]
    DIRECTION OUTPUT ;
    USE SIGNAL ;
    PORT
      LAYER M4 ;
        RECT  0 52.272 0.084 52.296 ;
    END
  END b[9]
  PIN ck_o
    DIRECTION OUTPUT ;
    USE SIGNAL ;
    PORT
      LAYER M5 ;
        RECT  33.744 105.732 33.768 105.816 ;
    END
  END ck_o
  PIN ckf
    DIRECTION INPUT ;
    USE SIGNAL ;
    PORT
      LAYER M5 ;
        RECT  33.84 105.732 33.864 105.816 ;
    END
  END ckf
  PIN ea
    DIRECTION INPUT ;
    USE SIGNAL ;
    PORT
      LAYER M4 ;
        RECT  64.692 79.824 64.776 79.848 ;
    END
  END ea
  PIN eb
    DIRECTION OUTPUT ;
    USE SIGNAL ;
    PORT
      LAYER M4 ;
        RECT  0 28.272 0.084 28.296 ;
    END
  END eb
  PIN VDD
    DIRECTION INOUT ;
    USE POWER ;
    PORT
      LAYER M5 ;
        RECT  61.992 2.151 62.112 103.433 ;
        RECT  59.292 2.151 59.412 103.433 ;
        RECT  56.592 2.151 56.712 103.433 ;
        RECT  53.892 2.151 54.012 103.433 ;
        RECT  51.192 2.151 51.312 103.433 ;
        RECT  48.492 2.151 48.612 103.433 ;
        RECT  45.792 2.151 45.912 103.433 ;
        RECT  43.092 2.151 43.212 103.433 ;
        RECT  40.392 2.151 40.512 103.433 ;
        RECT  37.692 2.151 37.812 103.433 ;
        RECT  34.992 2.151 35.112 103.433 ;
        RECT  32.292 2.151 32.412 103.433 ;
        RECT  29.592 2.151 29.712 103.433 ;
        RECT  26.892 2.151 27.012 103.433 ;
        RECT  24.192 2.151 24.312 103.433 ;
        RECT  21.492 2.151 21.612 103.433 ;
        RECT  18.792 2.151 18.912 103.433 ;
        RECT  16.092 2.151 16.212 103.433 ;
        RECT  13.392 2.151 13.512 103.433 ;
        RECT  10.692 2.151 10.812 103.433 ;
        RECT  7.992 2.151 8.112 103.433 ;
        RECT  5.292 2.151 5.412 103.433 ;
        RECT  2.592 2.151 2.712 103.433 ;
    END
  END VDD
  PIN VSS
    DIRECTION INOUT ;
    USE GROUND ;
    PORT
      LAYER M5 ;
        RECT  61.8 2.137 61.92 103.419 ;
        RECT  59.1 2.137 59.22 103.419 ;
        RECT  56.4 2.137 56.52 103.419 ;
        RECT  53.7 2.137 53.82 103.419 ;
        RECT  51 2.137 51.12 103.419 ;
        RECT  48.3 2.137 48.42 103.419 ;
        RECT  45.6 2.137 45.72 103.419 ;
        RECT  42.9 2.137 43.02 103.419 ;
        RECT  40.2 2.137 40.32 103.419 ;
        RECT  37.5 2.137 37.62 103.419 ;
        RECT  34.8 2.137 34.92 103.419 ;
        RECT  32.1 2.137 32.22 103.419 ;
        RECT  29.4 2.137 29.52 103.419 ;
        RECT  26.7 2.137 26.82 103.419 ;
        RECT  24 2.137 24.12 103.419 ;
        RECT  21.3 2.137 21.42 103.419 ;
        RECT  18.6 2.137 18.72 103.419 ;
        RECT  15.9 2.137 16.02 103.419 ;
        RECT  13.2 2.137 13.32 103.419 ;
        RECT  10.5 2.137 10.62 103.419 ;
        RECT  7.8 2.137 7.92 103.419 ;
        RECT  5.1 2.137 5.22 103.419 ;
        RECT  2.4 2.137 2.52 103.419 ;
    END
  END VSS
  # OT_OBS_CLOSED layer=M5 d_um=1.536 added=100
  OBS
    LAYER RVTN ;
     RECT  2.16 2.16 62.586 2.295 ;
     RECT  2.16 2.565 62.586 2.835 ;
     RECT  2.16 3.105 62.586 3.375 ;
     RECT  2.16 3.645 62.586 3.915 ;
     RECT  2.16 4.185 62.586 4.455 ;
     RECT  2.16 4.725 62.586 4.995 ;
     RECT  2.16 5.265 62.586 5.535 ;
     RECT  2.16 5.805 62.586 6.075 ;
     RECT  2.16 6.345 62.586 6.615 ;
     RECT  2.16 6.885 62.586 7.155 ;
     RECT  2.16 7.425 62.586 7.695 ;
     RECT  2.16 7.965 62.586 8.235 ;
     RECT  2.16 8.505 62.586 8.775 ;
     RECT  2.16 9.045 62.586 9.315 ;
     RECT  2.16 9.585 62.586 9.855 ;
     RECT  2.16 10.125 62.586 10.395 ;
     RECT  2.16 10.665 62.586 10.935 ;
     RECT  2.16 11.205 62.586 11.475 ;
     RECT  2.16 11.745 62.586 12.015 ;
     RECT  2.16 12.285 62.586 12.555 ;
     RECT  2.16 12.825 62.586 13.095 ;
     RECT  2.16 13.365 62.586 13.635 ;
     RECT  2.16 13.905 62.586 14.175 ;
     RECT  2.16 14.445 62.586 14.715 ;
     RECT  2.16 14.985 62.586 15.255 ;
     RECT  2.16 15.525 62.586 15.795 ;
     RECT  2.16 16.065 62.586 16.335 ;
     RECT  2.16 16.605 62.586 16.875 ;
     RECT  2.16 17.145 62.586 17.415 ;
     RECT  2.16 17.685 62.586 17.955 ;
     RECT  2.16 18.225 62.586 18.495 ;
     RECT  2.16 18.765 62.586 19.035 ;
     RECT  2.16 19.305 62.586 19.575 ;
     RECT  2.16 19.845 62.586 20.115 ;
     RECT  2.16 20.385 62.586 20.655 ;
     RECT  2.16 20.925 62.586 21.195 ;
     RECT  2.16 21.465 62.586 21.735 ;
     RECT  2.16 22.005 62.586 22.275 ;
     RECT  2.16 22.545 62.586 22.815 ;
     RECT  2.16 23.085 62.586 23.355 ;
     RECT  2.16 23.625 62.586 23.895 ;
     RECT  2.16 24.165 62.586 24.435 ;
     RECT  2.16 24.705 62.586 24.975 ;
     RECT  2.16 25.245 62.586 25.515 ;
     RECT  2.16 25.785 62.586 26.055 ;
     RECT  2.16 26.325 62.586 26.595 ;
     RECT  2.16 26.865 62.586 27.135 ;
     RECT  2.16 27.405 62.586 27.675 ;
     RECT  2.16 27.945 62.586 28.215 ;
     RECT  2.16 28.485 62.586 28.755 ;
     RECT  2.16 29.025 62.586 29.295 ;
     RECT  2.16 29.565 62.586 29.835 ;
     RECT  2.16 30.105 62.586 30.375 ;
     RECT  2.16 30.645 62.586 30.915 ;
     RECT  2.16 31.185 62.586 31.455 ;
     RECT  2.16 31.725 62.586 31.995 ;
     RECT  2.16 32.265 62.586 32.535 ;
     RECT  2.16 32.805 62.586 33.075 ;
     RECT  2.16 33.345 62.586 33.615 ;
     RECT  2.16 33.885 62.586 34.155 ;
     RECT  2.16 34.425 62.586 34.695 ;
     RECT  2.16 34.965 62.586 35.235 ;
     RECT  2.16 35.505 62.586 35.775 ;
     RECT  2.16 36.045 62.586 36.315 ;
     RECT  2.16 36.585 62.586 36.855 ;
     RECT  2.16 37.125 62.586 37.395 ;
     RECT  2.16 37.665 62.586 37.935 ;
     RECT  2.16 38.205 62.586 38.475 ;
     RECT  2.16 38.745 62.586 39.015 ;
     RECT  2.16 39.285 62.586 39.555 ;
     RECT  2.16 39.825 62.586 40.095 ;
     RECT  2.16 40.365 62.586 40.635 ;
     RECT  2.16 40.905 62.586 41.175 ;
     RECT  2.16 41.445 62.586 41.715 ;
     RECT  2.16 41.985 62.586 42.255 ;
     RECT  2.16 42.525 62.586 42.795 ;
     RECT  2.16 43.065 62.586 43.335 ;
     RECT  2.16 43.605 62.586 43.875 ;
     RECT  2.16 44.145 62.586 44.415 ;
     RECT  2.16 44.685 62.586 44.955 ;
     RECT  2.16 45.225 62.586 45.495 ;
     RECT  2.16 45.765 62.586 46.035 ;
     RECT  2.16 46.305 62.586 46.575 ;
     RECT  2.16 46.845 62.586 47.115 ;
     RECT  2.16 47.385 62.586 47.655 ;
     RECT  2.16 47.925 62.586 48.195 ;
     RECT  2.16 48.465 62.586 48.735 ;
     RECT  2.16 49.005 62.586 49.275 ;
     RECT  2.16 49.545 62.586 49.815 ;
     RECT  2.16 50.085 62.586 50.355 ;
     RECT  2.16 50.625 62.586 50.895 ;
     RECT  2.16 51.165 62.586 51.435 ;
     RECT  2.16 51.705 62.586 51.975 ;
     RECT  2.16 52.245 62.586 52.515 ;
     RECT  2.16 52.785 62.586 53.055 ;
     RECT  2.16 53.325 62.586 53.595 ;
     RECT  2.16 53.865 62.586 54.135 ;
     RECT  2.16 54.405 62.586 54.675 ;
     RECT  2.16 54.945 62.586 55.215 ;
     RECT  2.16 55.485 62.586 55.755 ;
     RECT  2.16 56.025 62.586 56.295 ;
     RECT  2.16 56.565 62.586 56.835 ;
     RECT  2.16 57.105 62.586 57.375 ;
     RECT  2.16 57.645 62.586 57.915 ;
     RECT  2.16 58.185 62.586 58.455 ;
     RECT  2.16 58.725 62.586 58.995 ;
     RECT  2.16 59.265 62.586 59.535 ;
     RECT  2.16 59.805 62.586 60.075 ;
     RECT  2.16 60.345 62.586 60.615 ;
     RECT  2.16 60.885 62.586 61.155 ;
     RECT  2.16 61.425 62.586 61.695 ;
     RECT  2.16 61.965 62.586 62.235 ;
     RECT  2.16 62.505 62.586 62.775 ;
     RECT  2.16 63.045 62.586 63.315 ;
     RECT  2.16 63.585 62.586 63.855 ;
     RECT  2.16 64.125 62.586 64.395 ;
     RECT  2.16 64.665 62.586 64.935 ;
     RECT  2.16 65.205 62.586 65.475 ;
     RECT  2.16 65.745 62.586 66.015 ;
     RECT  2.16 66.285 62.586 66.555 ;
     RECT  2.16 66.825 62.586 67.095 ;
     RECT  2.16 67.365 62.586 67.635 ;
     RECT  2.16 67.905 62.586 68.175 ;
     RECT  2.16 68.445 62.586 68.715 ;
     RECT  2.16 68.985 62.586 69.255 ;
     RECT  2.16 69.525 62.586 69.795 ;
     RECT  2.16 70.065 62.586 70.335 ;
     RECT  2.16 70.605 62.586 70.875 ;
     RECT  2.16 71.145 62.586 71.415 ;
     RECT  2.16 71.685 62.586 71.955 ;
     RECT  2.16 72.225 62.586 72.495 ;
     RECT  2.16 72.765 62.586 73.035 ;
     RECT  2.16 73.305 62.586 73.575 ;
     RECT  2.16 73.845 62.586 74.115 ;
     RECT  2.16 74.385 62.586 74.655 ;
     RECT  2.16 74.925 62.586 75.195 ;
     RECT  2.16 75.465 62.586 75.735 ;
     RECT  2.16 76.005 62.586 76.275 ;
     RECT  2.16 76.545 62.586 76.815 ;
     RECT  2.16 77.085 62.586 77.355 ;
     RECT  2.16 77.625 62.586 77.895 ;
     RECT  2.16 78.165 62.586 78.435 ;
     RECT  2.16 78.705 62.586 78.975 ;
     RECT  2.16 79.245 62.586 79.515 ;
     RECT  2.16 79.785 62.586 80.055 ;
     RECT  2.16 80.325 62.586 80.595 ;
     RECT  2.16 80.865 62.586 81.135 ;
     RECT  2.16 81.405 62.586 81.675 ;
     RECT  2.16 81.945 62.586 82.215 ;
     RECT  2.16 82.485 62.586 82.755 ;
     RECT  2.16 83.025 62.586 83.295 ;
     RECT  2.16 83.565 62.586 83.835 ;
     RECT  2.16 84.105 62.586 84.375 ;
     RECT  2.16 84.645 62.586 84.915 ;
     RECT  2.16 85.185 62.586 85.455 ;
     RECT  2.16 85.725 62.586 85.995 ;
     RECT  2.16 86.265 62.586 86.535 ;
     RECT  2.16 86.805 62.586 87.075 ;
     RECT  2.16 87.345 62.586 87.615 ;
     RECT  2.16 87.885 62.586 88.155 ;
     RECT  2.16 88.425 62.586 88.695 ;
     RECT  2.16 88.965 62.586 89.235 ;
     RECT  2.16 89.505 62.586 89.775 ;
     RECT  2.16 90.045 62.586 90.315 ;
     RECT  2.16 90.585 62.586 90.855 ;
     RECT  2.16 91.125 62.586 91.395 ;
     RECT  2.16 91.665 62.586 91.935 ;
     RECT  2.16 92.205 62.586 92.475 ;
     RECT  2.16 92.745 62.586 93.015 ;
     RECT  2.16 93.285 62.586 93.555 ;
     RECT  2.16 93.825 62.586 94.095 ;
     RECT  2.16 94.365 62.586 94.635 ;
     RECT  2.16 94.905 62.586 95.175 ;
     RECT  2.16 95.445 62.586 95.715 ;
     RECT  2.16 95.985 62.586 96.255 ;
     RECT  2.16 96.525 62.586 96.795 ;
     RECT  2.16 97.065 62.586 97.335 ;
     RECT  2.16 97.605 62.586 97.875 ;
     RECT  2.16 98.145 62.586 98.415 ;
     RECT  2.16 98.685 62.586 98.955 ;
     RECT  2.16 99.225 62.586 99.495 ;
     RECT  2.16 99.765 62.586 100.035 ;
     RECT  2.16 100.305 62.586 100.575 ;
     RECT  2.16 100.845 62.586 101.115 ;
     RECT  2.16 101.385 62.586 101.655 ;
     RECT  2.16 101.925 62.586 102.195 ;
     RECT  2.16 102.465 62.586 102.735 ;
     RECT  2.16 103.005 62.586 103.275 ;
    LAYER RVTP ;
     RECT  2.16 2.295 62.586 2.565 ;
     RECT  2.16 2.835 62.586 3.105 ;
     RECT  2.16 3.375 62.586 3.645 ;
     RECT  2.16 3.915 62.586 4.185 ;
     RECT  2.16 4.455 62.586 4.725 ;
     RECT  2.16 4.995 62.586 5.265 ;
     RECT  2.16 5.535 62.586 5.805 ;
     RECT  2.16 6.075 62.586 6.345 ;
     RECT  2.16 6.615 62.586 6.885 ;
     RECT  2.16 7.155 62.586 7.425 ;
     RECT  2.16 7.695 62.586 7.965 ;
     RECT  2.16 8.235 62.586 8.505 ;
     RECT  2.16 8.775 62.586 9.045 ;
     RECT  2.16 9.315 62.586 9.585 ;
     RECT  2.16 9.855 62.586 10.125 ;
     RECT  2.16 10.395 62.586 10.665 ;
     RECT  2.16 10.935 62.586 11.205 ;
     RECT  2.16 11.475 62.586 11.745 ;
     RECT  2.16 12.015 62.586 12.285 ;
     RECT  2.16 12.555 62.586 12.825 ;
     RECT  2.16 13.095 62.586 13.365 ;
     RECT  2.16 13.635 62.586 13.905 ;
     RECT  2.16 14.175 62.586 14.445 ;
     RECT  2.16 14.715 62.586 14.985 ;
     RECT  2.16 15.255 62.586 15.525 ;
     RECT  2.16 15.795 62.586 16.065 ;
     RECT  2.16 16.335 62.586 16.605 ;
     RECT  2.16 16.875 62.586 17.145 ;
     RECT  2.16 17.415 62.586 17.685 ;
     RECT  2.16 17.955 62.586 18.225 ;
     RECT  2.16 18.495 62.586 18.765 ;
     RECT  2.16 19.035 62.586 19.305 ;
     RECT  2.16 19.575 62.586 19.845 ;
     RECT  2.16 20.115 62.586 20.385 ;
     RECT  2.16 20.655 62.586 20.925 ;
     RECT  2.16 21.195 62.586 21.465 ;
     RECT  2.16 21.735 62.586 22.005 ;
     RECT  2.16 22.275 62.586 22.545 ;
     RECT  2.16 22.815 62.586 23.085 ;
     RECT  2.16 23.355 62.586 23.625 ;
     RECT  2.16 23.895 62.586 24.165 ;
     RECT  2.16 24.435 62.586 24.705 ;
     RECT  2.16 24.975 62.586 25.245 ;
     RECT  2.16 25.515 62.586 25.785 ;
     RECT  2.16 26.055 62.586 26.325 ;
     RECT  2.16 26.595 62.586 26.865 ;
     RECT  2.16 27.135 62.586 27.405 ;
     RECT  2.16 27.675 62.586 27.945 ;
     RECT  2.16 28.215 62.586 28.485 ;
     RECT  2.16 28.755 62.586 29.025 ;
     RECT  2.16 29.295 62.586 29.565 ;
     RECT  2.16 29.835 62.586 30.105 ;
     RECT  2.16 30.375 62.586 30.645 ;
     RECT  2.16 30.915 62.586 31.185 ;
     RECT  2.16 31.455 62.586 31.725 ;
     RECT  2.16 31.995 62.586 32.265 ;
     RECT  2.16 32.535 62.586 32.805 ;
     RECT  2.16 33.075 62.586 33.345 ;
     RECT  2.16 33.615 62.586 33.885 ;
     RECT  2.16 34.155 62.586 34.425 ;
     RECT  2.16 34.695 62.586 34.965 ;
     RECT  2.16 35.235 62.586 35.505 ;
     RECT  2.16 35.775 62.586 36.045 ;
     RECT  2.16 36.315 62.586 36.585 ;
     RECT  2.16 36.855 62.586 37.125 ;
     RECT  2.16 37.395 62.586 37.665 ;
     RECT  2.16 37.935 62.586 38.205 ;
     RECT  2.16 38.475 62.586 38.745 ;
     RECT  2.16 39.015 62.586 39.285 ;
     RECT  2.16 39.555 62.586 39.825 ;
     RECT  2.16 40.095 62.586 40.365 ;
     RECT  2.16 40.635 62.586 40.905 ;
     RECT  2.16 41.175 62.586 41.445 ;
     RECT  2.16 41.715 62.586 41.985 ;
     RECT  2.16 42.255 62.586 42.525 ;
     RECT  2.16 42.795 62.586 43.065 ;
     RECT  2.16 43.335 62.586 43.605 ;
     RECT  2.16 43.875 62.586 44.145 ;
     RECT  2.16 44.415 62.586 44.685 ;
     RECT  2.16 44.955 62.586 45.225 ;
     RECT  2.16 45.495 62.586 45.765 ;
     RECT  2.16 46.035 62.586 46.305 ;
     RECT  2.16 46.575 62.586 46.845 ;
     RECT  2.16 47.115 62.586 47.385 ;
     RECT  2.16 47.655 62.586 47.925 ;
     RECT  2.16 48.195 62.586 48.465 ;
     RECT  2.16 48.735 62.586 49.005 ;
     RECT  2.16 49.275 62.586 49.545 ;
     RECT  2.16 49.815 62.586 50.085 ;
     RECT  2.16 50.355 62.586 50.625 ;
     RECT  2.16 50.895 62.586 51.165 ;
     RECT  2.16 51.435 62.586 51.705 ;
     RECT  2.16 51.975 62.586 52.245 ;
     RECT  2.16 52.515 62.586 52.785 ;
     RECT  2.16 53.055 62.586 53.325 ;
     RECT  2.16 53.595 62.586 53.865 ;
     RECT  2.16 54.135 62.586 54.405 ;
     RECT  2.16 54.675 62.586 54.945 ;
     RECT  2.16 55.215 62.586 55.485 ;
     RECT  2.16 55.755 62.586 56.025 ;
     RECT  2.16 56.295 62.586 56.565 ;
     RECT  2.16 56.835 62.586 57.105 ;
     RECT  2.16 57.375 62.586 57.645 ;
     RECT  2.16 57.915 62.586 58.185 ;
     RECT  2.16 58.455 62.586 58.725 ;
     RECT  2.16 58.995 62.586 59.265 ;
     RECT  2.16 59.535 62.586 59.805 ;
     RECT  2.16 60.075 62.586 60.345 ;
     RECT  2.16 60.615 62.586 60.885 ;
     RECT  2.16 61.155 62.586 61.425 ;
     RECT  2.16 61.695 62.586 61.965 ;
     RECT  2.16 62.235 62.586 62.505 ;
     RECT  2.16 62.775 62.586 63.045 ;
     RECT  2.16 63.315 62.586 63.585 ;
     RECT  2.16 63.855 62.586 64.125 ;
     RECT  2.16 64.395 62.586 64.665 ;
     RECT  2.16 64.935 62.586 65.205 ;
     RECT  2.16 65.475 62.586 65.745 ;
     RECT  2.16 66.015 62.586 66.285 ;
     RECT  2.16 66.555 62.586 66.825 ;
     RECT  2.16 67.095 62.586 67.365 ;
     RECT  2.16 67.635 62.586 67.905 ;
     RECT  2.16 68.175 62.586 68.445 ;
     RECT  2.16 68.715 62.586 68.985 ;
     RECT  2.16 69.255 62.586 69.525 ;
     RECT  2.16 69.795 62.586 70.065 ;
     RECT  2.16 70.335 62.586 70.605 ;
     RECT  2.16 70.875 62.586 71.145 ;
     RECT  2.16 71.415 62.586 71.685 ;
     RECT  2.16 71.955 62.586 72.225 ;
     RECT  2.16 72.495 62.586 72.765 ;
     RECT  2.16 73.035 62.586 73.305 ;
     RECT  2.16 73.575 62.586 73.845 ;
     RECT  2.16 74.115 62.586 74.385 ;
     RECT  2.16 74.655 62.586 74.925 ;
     RECT  2.16 75.195 62.586 75.465 ;
     RECT  2.16 75.735 62.586 76.005 ;
     RECT  2.16 76.275 62.586 76.545 ;
     RECT  2.16 76.815 62.586 77.085 ;
     RECT  2.16 77.355 62.586 77.625 ;
     RECT  2.16 77.895 62.586 78.165 ;
     RECT  2.16 78.435 62.586 78.705 ;
     RECT  2.16 78.975 62.586 79.245 ;
     RECT  2.16 79.515 62.586 79.785 ;
     RECT  2.16 80.055 62.586 80.325 ;
     RECT  2.16 80.595 62.586 80.865 ;
     RECT  2.16 81.135 62.586 81.405 ;
     RECT  2.16 81.675 62.586 81.945 ;
     RECT  2.16 82.215 62.586 82.485 ;
     RECT  2.16 82.755 62.586 83.025 ;
     RECT  2.16 83.295 62.586 83.565 ;
     RECT  2.16 83.835 62.586 84.105 ;
     RECT  2.16 84.375 62.586 84.645 ;
     RECT  2.16 84.915 62.586 85.185 ;
     RECT  2.16 85.455 62.586 85.725 ;
     RECT  2.16 85.995 62.586 86.265 ;
     RECT  2.16 86.535 62.586 86.805 ;
     RECT  2.16 87.075 62.586 87.345 ;
     RECT  2.16 87.615 62.586 87.885 ;
     RECT  2.16 88.155 62.586 88.425 ;
     RECT  2.16 88.695 62.586 88.965 ;
     RECT  2.16 89.235 62.586 89.505 ;
     RECT  2.16 89.775 62.586 90.045 ;
     RECT  2.16 90.315 62.586 90.585 ;
     RECT  2.16 90.855 62.586 91.125 ;
     RECT  2.16 91.395 62.586 91.665 ;
     RECT  2.16 91.935 62.586 92.205 ;
     RECT  2.16 92.475 62.586 92.745 ;
     RECT  2.16 93.015 62.586 93.285 ;
     RECT  2.16 93.555 62.586 93.825 ;
     RECT  2.16 94.095 62.586 94.365 ;
     RECT  2.16 94.635 62.586 94.905 ;
     RECT  2.16 95.175 62.586 95.445 ;
     RECT  2.16 95.715 62.586 95.985 ;
     RECT  2.16 96.255 62.586 96.525 ;
     RECT  2.16 96.795 62.586 97.065 ;
     RECT  2.16 97.335 62.586 97.605 ;
     RECT  2.16 97.875 62.586 98.145 ;
     RECT  2.16 98.415 62.586 98.685 ;
     RECT  2.16 98.955 62.586 99.225 ;
     RECT  2.16 99.495 62.586 99.765 ;
     RECT  2.16 100.035 62.586 100.305 ;
     RECT  2.16 100.575 62.586 100.845 ;
     RECT  2.16 101.115 62.586 101.385 ;
     RECT  2.16 101.655 62.586 101.925 ;
     RECT  2.16 102.195 62.586 102.465 ;
     RECT  2.16 102.735 62.586 103.005 ;
     RECT  2.16 103.275 62.586 103.41 ;
    LAYER M1 ;
     RECT  2.16 2.151 62.586 103.419 ;
    LAYER M2 ;
     RECT  0.103 32.202 0.139 32.724 ;
     RECT  0.103 48.474 0.175 48.492 ;
     RECT  0.103 33.93 0.203 34.488 ;
     RECT  0.103 36.09 0.203 36.108 ;
     RECT  0.103 39.834 0.203 39.852 ;
     RECT  0.103 41.571 0.203 41.742 ;
     RECT  0.103 42.768 0.203 42.786 ;
     RECT  0.103 44.118 0.203 44.136 ;
     RECT  0.103 45.774 0.203 47.34 ;
     RECT  0.103 50.706 0.203 51.66 ;
     RECT  0.103 52.992 0.203 53.424 ;
     RECT  0.103 55.566 0.203 56.169 ;
     RECT  0.103 57.312 0.203 57.33 ;
     RECT  0.103 58.356 0.203 59.724 ;
     RECT  0.103 60.624 0.203 60.642 ;
     RECT  0.103 61.668 0.203 61.686 ;
     RECT  0.103 63.522 0.203 63.774 ;
     RECT  0.103 64.602 0.203 64.62 ;
     RECT  0.103 65.718 0.203 66.159 ;
     RECT  0.103 67.842 0.203 68.976 ;
     RECT  0.103 69.966 0.203 70.668 ;
     RECT  0.103 73.242 0.203 73.674 ;
     RECT  0.103 74.592 0.203 75.654 ;
     RECT  0.103 81.306 0.203 82.206 ;
     RECT  0.175 48.474 0.275 49.032 ;
     RECT  0.211 52.056 0.311 52.074 ;
     RECT  0.319 26.136 0.419 26.154 ;
     RECT  0.283 61.2 0.419 61.218 ;
     RECT  0.391 77.751 0.427 77.769 ;
     RECT  0.103 83.151 0.427 83.169 ;
     RECT  0.103 85.464 0.427 85.482 ;
     RECT  0.427 77.634 0.463 77.769 ;
     RECT  0.427 78.984 0.463 79.002 ;
     RECT  0.427 83.151 0.463 83.214 ;
     RECT  0.427 84.114 0.463 84.132 ;
     RECT  0.463 75.78 0.499 76.104 ;
     RECT  0.463 77.634 0.499 78.084 ;
     RECT  0.463 78.984 0.499 79.074 ;
     RECT  0.203 82.188 0.499 82.206 ;
     RECT  0.463 83.034 0.499 84.132 ;
     RECT  0.427 84.888 0.499 85.482 ;
     RECT  0.499 75.78 0.535 76.842 ;
     RECT  0.499 77.634 0.535 79.074 ;
     RECT  0.787 64.98 0.887 65.16 ;
     RECT  0.203 68.958 0.887 68.976 ;
     RECT  0.887 65.061 0.959 65.16 ;
     RECT  0.823 66.906 1.471 66.924 ;
     RECT  0.859 64.206 1.507 64.224 ;
     RECT  0.275 48.474 1.543 48.492 ;
     RECT  1.363 42.57 1.615 42.786 ;
     RECT  0.203 45.774 2.011 46.134 ;
     RECT  0.959 65.142 2.047 65.16 ;
     RECT  1.471 66.366 2.047 66.924 ;
     RECT  1.399 68.688 2.047 68.706 ;
     RECT  0.139 30.186 2.16 30.204 ;
     RECT  0.139 31.086 2.16 32.724 ;
     RECT  1.615 42.57 2.16 43.056 ;
     RECT  2.011 45.306 2.16 46.134 ;
     RECT  1.543 48.474 2.16 48.564 ;
     RECT  0.203 53.406 2.16 53.424 ;
     RECT  0.203 55.566 2.16 55.584 ;
     RECT  0.203 59.076 2.16 59.094 ;
     RECT  2.155 60.12 2.16 60.138 ;
     RECT  1.507 64.098 2.16 64.224 ;
     RECT  2.047 65.142 2.16 66.924 ;
     RECT  2.047 67.986 2.16 68.706 ;
     RECT  1.399 72.576 2.16 72.594 ;
     RECT  0.203 73.656 2.16 73.674 ;
     RECT  0.203 75.006 2.16 75.024 ;
     RECT  0.535 75.78 2.16 79.236 ;
     RECT  0.499 82.188 2.16 85.482 ;
     RECT  2.16 2.151 62.586 103.419 ;
     RECT  62.586 20.358 62.735 80.118 ;
     RECT  62.735 20.394 62.771 80.118 ;
     RECT  62.771 25.758 62.807 39.546 ;
     RECT  62.771 40.41 62.807 55.818 ;
     RECT  62.771 20.466 62.843 25.002 ;
     RECT  62.807 26.838 62.843 39.546 ;
     RECT  62.807 54.99 62.915 55.818 ;
     RECT  62.843 26.838 63.203 27.936 ;
     RECT  62.843 20.466 63.311 24.804 ;
     RECT  62.807 25.758 63.311 26.046 ;
     RECT  63.203 26.946 63.311 27.936 ;
     RECT  62.843 28.728 63.311 39.546 ;
     RECT  62.807 40.41 63.311 54.234 ;
     RECT  62.771 56.61 63.311 63.918 ;
     RECT  62.771 64.746 63.311 80.118 ;
     RECT  63.311 28.8 63.347 34.758 ;
     RECT  63.311 40.536 63.347 41.814 ;
     RECT  63.311 42.651 63.347 45.216 ;
     RECT  63.311 50.328 63.347 54.234 ;
     RECT  63.311 60.39 63.347 62.838 ;
     RECT  63.311 63.711 63.347 63.918 ;
     RECT  63.311 64.746 63.347 66.546 ;
     RECT  63.311 67.536 63.347 68.238 ;
     RECT  63.311 71.928 63.347 73.674 ;
     RECT  63.311 74.592 63.347 76.608 ;
     RECT  63.347 40.536 63.383 40.554 ;
     RECT  63.311 68.994 63.383 69.354 ;
     RECT  63.347 64.746 63.419 66.474 ;
     RECT  63.311 77.634 63.851 80.118 ;
     RECT  63.311 20.511 63.887 24.804 ;
     RECT  63.311 25.83 63.887 26.046 ;
     RECT  63.311 26.946 63.887 27.819 ;
     RECT  63.347 29.268 63.887 34.758 ;
     RECT  63.311 35.586 63.887 35.604 ;
     RECT  63.311 36.792 63.887 37.584 ;
     RECT  63.311 38.646 63.887 39.384 ;
     RECT  63.347 41.796 63.887 41.814 ;
     RECT  63.347 42.651 63.887 43.668 ;
     RECT  63.347 44.766 63.887 44.784 ;
     RECT  63.311 46.08 63.887 47.799 ;
     RECT  63.311 48.744 63.887 49.572 ;
     RECT  63.347 50.328 63.887 50.724 ;
     RECT  63.347 51.75 63.887 54.234 ;
     RECT  62.915 55.026 63.887 55.818 ;
     RECT  63.311 56.88 63.887 59.634 ;
     RECT  63.347 60.39 63.887 62.496 ;
     RECT  63.347 63.828 63.887 63.918 ;
     RECT  63.419 64.746 63.887 66.348 ;
     RECT  63.347 67.536 63.887 67.968 ;
     RECT  63.383 69.066 63.887 69.354 ;
     RECT  63.311 70.344 63.887 70.704 ;
     RECT  63.347 72.234 63.887 73.674 ;
     RECT  63.347 75.168 63.887 76.608 ;
     RECT  63.851 77.634 63.887 78.264 ;
     RECT  63.887 21.474 63.923 22.068 ;
     RECT  63.887 26.028 63.923 26.046 ;
     RECT  63.887 29.268 63.923 29.286 ;
     RECT  63.887 31.626 63.923 32.058 ;
     RECT  63.887 34.326 63.923 34.344 ;
     RECT  63.887 43.65 63.923 43.668 ;
     RECT  63.887 49.086 63.923 49.104 ;
     RECT  63.887 50.328 63.923 50.346 ;
     RECT  63.887 51.876 63.923 51.894 ;
     RECT  63.887 52.83 63.923 52.848 ;
     RECT  63.887 55.8 63.923 55.818 ;
     RECT  63.887 57.114 63.923 57.132 ;
     RECT  63.887 57.996 63.923 58.014 ;
     RECT  63.887 59.202 63.923 59.22 ;
     RECT  63.887 60.588 63.923 60.606 ;
     RECT  63.887 61.398 63.923 61.416 ;
     RECT  63.887 63.9 63.923 63.918 ;
     RECT  63.887 64.746 63.923 64.764 ;
     RECT  63.887 65.988 63.923 66.348 ;
     RECT  63.887 67.842 63.923 67.968 ;
     RECT  63.887 72.234 63.923 72.558 ;
     RECT  63.887 75.168 63.923 75.186 ;
     RECT  63.887 76.59 63.923 76.608 ;
     RECT  63.851 79.056 63.923 80.118 ;
     RECT  63.923 22.05 63.959 22.068 ;
     RECT  63.887 23.868 63.959 23.886 ;
     RECT  63.923 32.04 63.959 32.058 ;
     RECT  63.887 42.876 63.959 42.894 ;
     RECT  63.923 67.95 63.959 67.968 ;
     RECT  63.923 72.54 63.959 72.558 ;
     RECT  63.923 79.686 63.959 80.01 ;
     RECT  63.959 79.686 63.995 79.704 ;
     RECT  64.651 22.86 64.751 22.878 ;
     RECT  64.651 36.288 64.751 36.306 ;
     RECT  64.651 42.066 64.751 42.084 ;
     RECT  64.651 49.716 64.751 49.734 ;
     RECT  64.651 55.962 64.751 55.98 ;
     RECT  64.651 73.971 64.751 73.989 ;
     RECT  64.651 78.606 64.751 79.344 ;
    LAYER M3 ;
     RECT  2.415 2.143 2.505 2.413 ;
     RECT  5.115 2.143 5.205 2.413 ;
     RECT  7.815 2.143 7.905 2.413 ;
     RECT  10.515 2.143 10.605 2.413 ;
     RECT  13.215 2.143 13.305 2.413 ;
     RECT  15.915 2.143 16.005 2.413 ;
     RECT  18.615 2.143 18.705 2.413 ;
     RECT  21.315 2.143 21.405 2.413 ;
     RECT  24.015 2.143 24.105 2.413 ;
     RECT  26.715 2.143 26.805 2.413 ;
     RECT  29.415 2.143 29.505 2.413 ;
     RECT  32.115 2.143 32.205 2.413 ;
     RECT  34.815 2.143 34.905 2.413 ;
     RECT  37.515 2.143 37.605 2.413 ;
     RECT  40.215 2.143 40.305 2.413 ;
     RECT  42.915 2.143 43.005 2.413 ;
     RECT  45.615 2.143 45.705 2.413 ;
     RECT  48.315 2.143 48.405 2.413 ;
     RECT  51.015 2.143 51.105 2.413 ;
     RECT  53.715 2.143 53.805 2.413 ;
     RECT  56.415 2.143 56.505 2.413 ;
     RECT  59.115 2.143 59.205 2.413 ;
     RECT  61.815 2.143 61.905 2.413 ;
     RECT  61.815 2.413 62.097 19.777 ;
     RECT  61.56 19.777 62.097 19.915 ;
     RECT  61.56 19.915 62.154 20.011 ;
     RECT  56.415 2.413 56.697 20.047 ;
     RECT  57.528 19.921 57.546 20.047 ;
     RECT  56.415 20.047 57.546 20.155 ;
     RECT  59.115 2.413 59.397 20.155 ;
     RECT  56.415 20.155 57.906 20.191 ;
     RECT  59.115 20.155 60.102 20.191 ;
     RECT  61.56 20.011 62.766 20.191 ;
     RECT  61.02 20.191 62.766 20.203 ;
     RECT  54.72 20.047 54.738 20.219 ;
     RECT  61.02 20.203 63.306 20.491 ;
     RECT  32.115 2.413 32.397 20.623 ;
     RECT  18.615 2.413 18.897 20.731 ;
     RECT  56.415 20.191 60.102 20.731 ;
     RECT  61.02 20.491 63.882 20.731 ;
     RECT  17.892 20.731 18.897 20.849 ;
     RECT  31.716 20.623 32.397 20.849 ;
     RECT  10.515 2.413 10.797 20.893 ;
     RECT  2.415 2.413 2.697 20.929 ;
     RECT  56.415 20.731 63.882 21.001 ;
     RECT  55.908 21.001 63.882 21.005 ;
     RECT  54.9 20.461 54.918 21.127 ;
     RECT  55.908 21.005 62.766 21.127 ;
     RECT  5.115 2.413 5.397 21.163 ;
     RECT  63.864 21.005 63.882 21.163 ;
     RECT  30.78 21.127 30.798 21.299 ;
     RECT  21.315 2.413 21.597 21.541 ;
     RECT  20.916 21.541 21.597 21.659 ;
     RECT  53.715 2.413 53.997 21.667 ;
     RECT  54.72 21.127 62.766 21.667 ;
     RECT  36.54 21.163 36.558 21.703 ;
     RECT  63.864 21.163 63.918 21.739 ;
     RECT  53.715 21.667 62.766 21.931 ;
     RECT  63.864 21.739 63.954 21.931 ;
     RECT  53.715 21.931 63.954 22.073 ;
     RECT  2.415 20.929 3.042 22.081 ;
     RECT  36.54 21.703 36.594 22.081 ;
     RECT  51.015 2.413 51.297 22.081 ;
     RECT  30.636 22.081 30.654 22.271 ;
     RECT  24.015 2.413 24.297 22.315 ;
     RECT  33.552 22.243 33.57 22.469 ;
     RECT  2.304 22.081 3.042 22.549 ;
     RECT  3.852 22.171 3.87 22.549 ;
     RECT  33.804 22.513 33.894 22.613 ;
     RECT  2.304 22.549 3.87 22.783 ;
     RECT  51.015 22.081 51.57 22.819 ;
     RECT  2.304 22.783 3.906 22.847 ;
     RECT  64.728 22.843 64.746 22.855 ;
     RECT  64.656 22.855 64.746 22.883 ;
     RECT  25.128 21.469 25.146 22.891 ;
     RECT  64.656 22.883 64.674 22.925 ;
     RECT  45.615 2.413 45.897 22.981 ;
     RECT  21.024 21.659 21.597 22.987 ;
     RECT  23.472 22.315 24.297 22.987 ;
     RECT  29.415 2.413 29.697 22.987 ;
     RECT  37.515 2.413 37.797 22.987 ;
     RECT  45.216 22.981 45.897 22.987 ;
     RECT  25.128 22.891 25.794 23.009 ;
     RECT  53.715 22.073 63.882 23.081 ;
     RECT  51.015 22.819 51.642 23.089 ;
     RECT  14.832 22.987 14.85 23.117 ;
     RECT  21.024 22.987 21.69 23.117 ;
     RECT  22.824 22.987 24.297 23.117 ;
     RECT  29.415 22.987 29.79 23.117 ;
     RECT  30.78 22.513 30.798 23.117 ;
     RECT  37.515 22.987 37.89 23.117 ;
     RECT  38.772 22.987 38.79 23.117 ;
     RECT  46.764 22.987 46.782 23.117 ;
     RECT  45.216 22.987 45.99 23.161 ;
     RECT  45.216 23.161 46.062 23.315 ;
     RECT  50.796 23.089 51.642 23.315 ;
     RECT  53.715 23.081 62.766 23.351 ;
     RECT  55.728 23.351 62.766 23.597 ;
     RECT  10.515 20.893 11.106 23.629 ;
     RECT  61.632 23.597 62.766 23.819 ;
     RECT  45.216 23.315 45.897 23.855 ;
     RECT  5.115 21.163 5.994 23.863 ;
     RECT  63.864 23.081 63.882 23.863 ;
     RECT  55.728 23.597 60.786 24.125 ;
     RECT  53.715 23.351 54.954 24.169 ;
     RECT  34.815 2.413 35.097 24.205 ;
     RECT  21.024 23.117 21.597 24.241 ;
     RECT  2.415 22.847 3.906 24.331 ;
     RECT  53.715 24.169 55.026 24.331 ;
     RECT  21.024 24.241 21.978 24.359 ;
     RECT  45.288 23.855 45.897 24.359 ;
     RECT  63.864 23.863 63.954 24.365 ;
     RECT  5.115 23.863 6.534 24.403 ;
     RECT  7.815 2.413 8.097 24.403 ;
     RECT  61.815 23.819 62.766 24.427 ;
     RECT  63.864 24.365 63.882 24.427 ;
     RECT  34.815 24.205 35.586 24.511 ;
     RECT  55.872 24.125 60.786 24.673 ;
     RECT  61.815 24.427 63.882 24.673 ;
     RECT  55.872 24.673 63.882 24.773 ;
     RECT  2.415 24.331 4.122 24.871 ;
     RECT  53.028 24.331 55.026 24.935 ;
     RECT  13.215 2.413 13.497 24.943 ;
     RECT  30.564 24.781 30.582 25.007 ;
     RECT  53.172 24.935 55.026 25.015 ;
     RECT  55.872 24.773 62.838 25.015 ;
     RECT  40.215 2.413 40.497 25.321 ;
     RECT  45.615 24.359 45.897 25.321 ;
     RECT  20.232 22.513 20.25 25.447 ;
     RECT  21.024 24.359 21.597 25.447 ;
     RECT  53.172 25.015 62.838 25.583 ;
     RECT  53.244 25.583 62.838 25.753 ;
     RECT  63.864 24.773 63.882 25.753 ;
     RECT  42.915 2.413 43.197 25.789 ;
     RECT  53.244 25.753 63.882 25.805 ;
     RECT  63.864 25.805 63.882 25.852 ;
     RECT  45.252 25.321 45.897 25.861 ;
     RECT  42.915 25.789 43.29 25.951 ;
     RECT  45.216 25.861 45.897 25.979 ;
     RECT  42.804 25.951 43.29 26.051 ;
     RECT  45.252 25.979 45.897 26.051 ;
     RECT  63.864 25.852 63.918 26.051 ;
     RECT  0.324 25.963 0.342 26.107 ;
     RECT  33.804 22.613 33.822 26.107 ;
     RECT  0.324 26.107 0.414 26.159 ;
     RECT  0.324 26.159 0.342 26.189 ;
     RECT  2.415 24.871 4.158 26.203 ;
     RECT  2.412 26.203 4.158 26.249 ;
     RECT  33.804 26.107 34.074 26.251 ;
     RECT  34.815 24.511 35.658 26.251 ;
     RECT  51.015 23.315 51.642 26.257 ;
     RECT  48.315 2.413 48.597 26.293 ;
     RECT  32.115 20.849 32.397 26.401 ;
     RECT  51.015 26.257 52.038 26.401 ;
     RECT  1.152 26.299 1.17 26.443 ;
     RECT  2.415 26.249 4.158 26.527 ;
     RECT  2.415 26.527 4.194 26.539 ;
     RECT  5.115 24.403 8.097 26.539 ;
     RECT  53.244 25.805 62.802 26.539 ;
     RECT  50.436 26.401 52.038 26.563 ;
     RECT  1.152 26.443 1.386 26.573 ;
     RECT  29.415 23.117 29.697 26.599 ;
     RECT  30.672 26.563 30.69 26.599 ;
     RECT  32.115 26.401 32.922 26.635 ;
     RECT  33.804 26.251 35.658 26.635 ;
     RECT  28.116 24.061 28.134 26.671 ;
     RECT  29.415 26.599 30.69 26.671 ;
     RECT  38.772 26.671 38.79 26.789 ;
     RECT  23.544 23.117 24.297 26.827 ;
     RECT  42.915 26.051 43.29 26.861 ;
     RECT  28.116 26.671 30.69 26.923 ;
     RECT  53.244 26.539 63.198 26.923 ;
     RECT  53.244 26.923 63.306 26.941 ;
     RECT  1.152 26.573 1.242 26.957 ;
     RECT  1.224 26.957 1.242 27.053 ;
     RECT  2.415 26.539 8.097 27.095 ;
     RECT  5.076 27.095 8.097 27.101 ;
     RECT  2.415 27.095 4.266 27.115 ;
     RECT  20.232 25.447 21.597 27.115 ;
     RECT  50.436 26.563 52.146 27.211 ;
     RECT  53.244 26.941 63.882 27.211 ;
     RECT  50.436 27.211 63.882 27.329 ;
     RECT  45.615 26.051 45.897 27.409 ;
     RECT  47.016 26.023 47.034 27.409 ;
     RECT  28.116 26.923 30.906 27.445 ;
     RECT  32.115 26.635 35.658 27.445 ;
     RECT  14.832 26.827 14.85 27.571 ;
     RECT  18 20.849 18.897 27.571 ;
     RECT  20.232 27.115 21.69 27.571 ;
     RECT  45.615 27.409 47.034 27.643 ;
     RECT  48.132 26.293 48.597 27.643 ;
     RECT  14.832 27.571 14.886 27.671 ;
     RECT  18 27.571 21.69 27.671 ;
     RECT  14.832 27.671 14.85 27.773 ;
     RECT  20.232 27.671 21.69 27.773 ;
     RECT  22.824 26.827 24.297 27.773 ;
     RECT  18 27.671 19.314 27.779 ;
     RECT  28.116 27.445 35.658 27.779 ;
     RECT  50.436 27.329 55.422 27.905 ;
     RECT  28.116 27.779 30.906 27.917 ;
     RECT  40.215 25.321 41.022 27.985 ;
     RECT  56.304 27.329 63.882 28.013 ;
     RECT  2.304 27.115 4.266 28.075 ;
     RECT  49.32 28.183 49.41 28.219 ;
     RECT  50.436 27.905 55.062 28.219 ;
     RECT  2.268 28.075 4.266 28.247 ;
     RECT  56.304 28.013 63.306 28.255 ;
     RECT  2.304 28.247 4.266 28.319 ;
     RECT  2.34 28.319 4.266 28.561 ;
     RECT  5.115 27.101 8.097 28.561 ;
     RECT  40.215 27.985 41.31 28.561 ;
     RECT  2.34 28.561 8.097 28.679 ;
     RECT  39.6 28.561 41.31 28.723 ;
     RECT  55.8 28.255 63.306 28.747 ;
     RECT  26.715 2.413 26.997 28.759 ;
     RECT  49.32 28.219 55.062 28.795 ;
     RECT  55.8 28.747 63.342 28.795 ;
     RECT  9.936 23.629 11.106 28.831 ;
     RECT  37.515 23.117 37.797 28.831 ;
     RECT  32.115 27.779 35.658 28.859 ;
     RECT  49.32 28.795 63.342 29.069 ;
     RECT  37.515 28.831 38.466 29.101 ;
     RECT  20.232 27.773 21.597 29.227 ;
     RECT  39.6 28.723 41.886 29.263 ;
     RECT  42.915 26.861 43.197 29.263 ;
     RECT  56.415 29.069 63.342 29.263 ;
     RECT  39.6 29.263 43.197 29.489 ;
     RECT  28.116 27.917 30.294 29.515 ;
     RECT  32.115 28.859 35.622 29.605 ;
     RECT  36.54 22.081 36.702 29.605 ;
     RECT  23.544 27.773 24.297 29.611 ;
     RECT  25.128 23.009 25.146 29.611 ;
     RECT  56.415 29.263 63.918 29.741 ;
     RECT  19.764 29.227 21.597 29.899 ;
     RECT  23.544 29.611 25.146 29.899 ;
     RECT  49.32 29.069 55.674 29.899 ;
     RECT  56.415 29.741 63.882 29.899 ;
     RECT  0.144 29.131 0.162 29.995 ;
     RECT  26.715 28.759 27.054 30.043 ;
     RECT  27.792 29.515 30.294 30.043 ;
     RECT  42.66 29.489 43.197 30.065 ;
     RECT  22.824 29.899 25.146 30.091 ;
     RECT  2.34 28.679 4.266 30.271 ;
     RECT  5.115 28.679 8.097 30.271 ;
     RECT  2.304 30.271 4.266 30.317 ;
     RECT  49.32 29.899 63.882 30.605 ;
     RECT  19.764 29.899 21.69 30.619 ;
     RECT  22.536 30.091 25.146 30.619 ;
     RECT  44.748 29.569 44.766 30.649 ;
     RECT  44.172 30.649 44.766 30.685 ;
     RECT  26.715 30.043 30.294 30.811 ;
     RECT  37.515 29.101 38.502 30.847 ;
     RECT  39.6 29.489 41.922 30.847 ;
     RECT  45.615 27.643 48.597 30.883 ;
     RECT  49.32 30.605 62.766 30.883 ;
     RECT  14.832 29.467 14.85 30.941 ;
     RECT  26.676 30.811 30.798 30.941 ;
     RECT  37.515 30.847 41.922 30.955 ;
     RECT  45.615 30.883 62.766 30.983 ;
     RECT  37.476 30.955 41.922 31.117 ;
     RECT  42.915 30.065 43.197 31.117 ;
     RECT  37.476 31.117 43.197 31.189 ;
     RECT  44.172 30.685 44.802 31.189 ;
     RECT  2.376 30.317 4.266 31.243 ;
     RECT  15.915 2.413 16.197 31.243 ;
     RECT  25.884 23.161 25.902 31.243 ;
     RECT  26.676 30.941 30.33 31.243 ;
     RECT  2.304 31.243 4.266 31.289 ;
     RECT  5.004 30.271 8.097 31.289 ;
     RECT  15.804 31.243 16.197 31.289 ;
     RECT  63.864 30.605 63.882 31.339 ;
     RECT  63.864 31.339 63.918 31.627 ;
     RECT  45.615 30.983 62.73 31.723 ;
     RECT  63.864 31.627 63.954 31.723 ;
     RECT  37.476 31.189 44.802 31.729 ;
     RECT  45.615 31.723 63.954 31.729 ;
     RECT  14.94 31.627 14.958 31.757 ;
     RECT  37.476 31.729 63.954 31.955 ;
     RECT  63.864 31.955 63.954 32.063 ;
     RECT  0.108 29.995 0.162 32.285 ;
     RECT  2.415 31.289 4.266 32.395 ;
     RECT  8.856 28.795 8.874 32.491 ;
     RECT  9.936 28.831 11.142 32.491 ;
     RECT  37.476 31.955 62.73 32.683 ;
     RECT  63.864 32.063 63.882 32.683 ;
     RECT  0.108 32.285 0.126 32.729 ;
     RECT  5.115 31.289 8.097 32.872 ;
     RECT  15.915 31.289 16.197 32.971 ;
     RECT  2.304 32.395 4.266 33.008 ;
     RECT  5.004 32.872 8.097 33.008 ;
     RECT  15.804 32.971 16.197 33.008 ;
     RECT  14.832 32.875 14.85 33.053 ;
     RECT  25.884 31.243 30.33 33.079 ;
     RECT  32.115 29.605 36.702 33.349 ;
     RECT  19.764 30.619 25.146 33.547 ;
     RECT  25.884 33.079 30.654 33.547 ;
     RECT  0.144 33.163 0.162 33.916 ;
     RECT  19.764 33.547 30.654 33.961 ;
     RECT  15.915 33.008 16.197 34.123 ;
     RECT  37.476 32.683 63.882 34.321 ;
     RECT  19.764 33.961 30.726 34.363 ;
     RECT  31.824 33.349 36.702 34.363 ;
     RECT  0.108 33.916 0.198 34.508 ;
     RECT  2.376 33.008 4.266 34.591 ;
     RECT  5.115 33.008 8.097 34.591 ;
     RECT  14.832 33.787 14.85 34.591 ;
     RECT  37.476 34.321 63.918 34.637 ;
     RECT  18 27.779 18.897 34.663 ;
     RECT  8.856 32.491 11.142 34.933 ;
     RECT  19.764 34.363 36.702 34.969 ;
     RECT  37.476 34.637 63.882 34.969 ;
     RECT  0.144 34.508 0.162 34.973 ;
     RECT  19.764 34.969 63.882 34.997 ;
     RECT  5.004 34.591 8.097 35.168 ;
     RECT  1.404 32.299 1.422 35.275 ;
     RECT  2.304 34.591 4.266 35.275 ;
     RECT  14.832 34.591 15.138 35.275 ;
     RECT  15.915 34.123 16.866 35.311 ;
     RECT  17.964 34.663 18.897 35.311 ;
     RECT  1.404 35.275 4.266 35.371 ;
     RECT  19.764 34.997 62.802 35.537 ;
     RECT  63.864 34.997 63.882 35.609 ;
     RECT  0.828 35.371 4.266 35.803 ;
     RECT  8.856 34.933 11.718 35.815 ;
     RECT  12.816 24.943 13.497 35.815 ;
     RECT  0.18 35.803 4.266 35.851 ;
     RECT  8.856 35.815 13.497 35.941 ;
     RECT  14.544 35.275 15.138 35.941 ;
     RECT  37.476 35.537 62.802 35.941 ;
     RECT  0.108 35.851 4.266 36.113 ;
     RECT  19.764 35.537 36.702 36.283 ;
     RECT  64.656 36.235 64.674 36.283 ;
     RECT  64.656 36.283 64.746 36.311 ;
     RECT  64.728 36.311 64.746 36.32 ;
     RECT  0.144 36.113 4.266 36.331 ;
     RECT  5.115 35.168 8.097 36.331 ;
     RECT  37.476 35.941 63.306 36.383 ;
     RECT  15.915 35.311 18.897 36.751 ;
     RECT  15.915 36.751 18.918 36.851 ;
     RECT  0.144 36.331 8.097 36.931 ;
     RECT  8.856 35.941 15.138 36.931 ;
     RECT  0.144 36.931 15.138 36.941 ;
     RECT  0.216 36.941 15.138 36.989 ;
     RECT  0.216 36.989 8.097 37.037 ;
     RECT  37.476 36.383 62.838 37.037 ;
     RECT  8.856 36.989 15.138 37.291 ;
     RECT  15.915 36.851 18.897 37.291 ;
     RECT  8.856 37.291 18.897 37.328 ;
     RECT  19.692 36.283 36.702 37.363 ;
     RECT  37.476 37.037 62.766 37.363 ;
     RECT  19.692 37.363 62.766 37.771 ;
     RECT  63.864 36.787 63.882 37.771 ;
     RECT  19.692 37.771 63.882 38.201 ;
     RECT  37.476 38.201 63.882 38.309 ;
     RECT  0.828 37.037 8.097 38.395 ;
     RECT  0.18 38.395 8.097 38.491 ;
     RECT  8.856 37.328 15.138 38.749 ;
     RECT  19.692 38.201 36.702 38.983 ;
     RECT  37.476 38.309 62.73 38.983 ;
     RECT  19.656 38.983 62.73 39.055 ;
     RECT  63.864 38.309 63.882 39.055 ;
     RECT  19.656 39.055 63.882 39.389 ;
     RECT  0.144 38.491 8.097 39.691 ;
     RECT  19.656 39.389 63.342 39.725 ;
     RECT  0.108 39.691 8.097 39.857 ;
     RECT  15.915 37.328 18.897 40.027 ;
     RECT  15.915 40.027 18.918 40.397 ;
     RECT  19.656 39.725 63.306 40.531 ;
     RECT  19.656 40.531 63.378 40.877 ;
     RECT  19.656 40.877 63.342 41.207 ;
     RECT  0.144 39.857 8.097 41.323 ;
     RECT  0.108 41.323 8.097 41.837 ;
     RECT  64.728 42.043 64.746 42.061 ;
     RECT  64.656 42.061 64.746 42.089 ;
     RECT  64.656 42.089 64.674 42.125 ;
     RECT  19.656 41.207 62.766 42.187 ;
     RECT  63.864 41.611 63.882 42.187 ;
     RECT  19.656 42.187 63.882 42.629 ;
     RECT  0.828 41.837 8.097 42.748 ;
     RECT  63.828 42.629 63.882 42.871 ;
     RECT  0.108 42.748 8.097 42.989 ;
     RECT  15.915 40.397 18.897 43.003 ;
     RECT  15.915 43.003 18.918 43.133 ;
     RECT  63.828 42.871 63.954 43.277 ;
     RECT  19.656 42.629 62.766 43.411 ;
     RECT  63.828 43.277 63.918 43.411 ;
     RECT  19.656 43.411 63.918 43.673 ;
     RECT  0.144 42.989 8.097 44.113 ;
     RECT  0.108 44.113 8.097 44.333 ;
     RECT  0.144 44.333 8.097 44.765 ;
     RECT  0.216 44.765 8.097 44.813 ;
     RECT  19.656 43.673 63.882 45.101 ;
     RECT  0.828 44.813 8.097 45.643 ;
     RECT  8.82 38.749 15.138 45.931 ;
     RECT  15.915 43.133 18.897 45.931 ;
     RECT  19.656 45.101 63.342 45.931 ;
     RECT  8.82 45.931 18.897 45.968 ;
     RECT  0.108 45.643 8.097 47.501 ;
     RECT  0.828 47.501 8.097 48.235 ;
     RECT  19.656 45.931 63.882 48.299 ;
     RECT  8.82 45.968 15.138 48.523 ;
     RECT  15.915 45.968 18.897 48.523 ;
     RECT  0.108 48.235 8.097 48.557 ;
     RECT  8.82 48.523 18.897 48.569 ;
     RECT  63.864 48.299 63.882 49.081 ;
     RECT  19.656 48.299 62.838 49.195 ;
     RECT  63.864 49.081 63.918 49.195 ;
     RECT  19.656 49.195 63.918 49.421 ;
     RECT  64.656 49.675 64.674 49.711 ;
     RECT  64.656 49.711 64.746 49.739 ;
     RECT  64.728 49.739 64.746 49.757 ;
     RECT  8.82 48.569 15.138 50.251 ;
     RECT  15.915 48.569 18.897 50.251 ;
     RECT  8.82 50.251 18.897 50.288 ;
     RECT  19.656 49.421 63.882 50.323 ;
     RECT  19.656 50.323 63.918 50.381 ;
     RECT  0.144 48.557 8.097 50.443 ;
     RECT  0.108 50.443 8.097 51.821 ;
     RECT  19.656 50.381 63.882 51.871 ;
     RECT  19.656 51.871 63.918 52.853 ;
     RECT  0.144 51.821 8.097 52.972 ;
     RECT  0.108 52.972 8.097 53.453 ;
     RECT  19.656 52.853 63.882 54.029 ;
     RECT  63.864 54.029 63.882 54.239 ;
     RECT  0.144 53.453 8.097 54.317 ;
     RECT  8.82 50.288 15.138 54.571 ;
     RECT  15.915 50.288 18.897 54.571 ;
     RECT  8.82 54.571 18.897 54.608 ;
     RECT  19.656 54.029 62.91 55.051 ;
     RECT  63.864 55.021 63.882 55.051 ;
     RECT  19.656 55.051 63.882 55.531 ;
     RECT  0.828 54.317 8.097 55.561 ;
     RECT  19.656 55.531 63.918 55.823 ;
     RECT  64.656 55.915 64.674 55.957 ;
     RECT  64.656 55.957 64.746 55.985 ;
     RECT  64.728 55.985 64.746 55.997 ;
     RECT  0.108 55.561 8.097 56.371 ;
     RECT  8.82 54.608 15.138 56.371 ;
     RECT  0.108 56.371 15.138 56.429 ;
     RECT  19.656 55.823 63.306 56.683 ;
     RECT  19.656 56.683 63.882 56.875 ;
     RECT  19.656 56.875 63.918 57.137 ;
     RECT  0.144 56.429 8.097 57.292 ;
     RECT  19.656 57.137 63.882 57.371 ;
     RECT  15.915 54.608 18.897 57.403 ;
     RECT  19.656 57.371 62.442 57.403 ;
     RECT  0.108 57.292 8.097 57.485 ;
     RECT  15.915 57.403 62.442 57.581 ;
     RECT  63.288 57.371 63.882 57.991 ;
     RECT  0.144 57.485 8.097 58.348 ;
     RECT  19.656 57.581 62.442 58.411 ;
     RECT  63.288 57.991 63.918 58.411 ;
     RECT  8.82 56.429 15.138 58.891 ;
     RECT  15.915 57.581 18.897 58.891 ;
     RECT  8.82 58.891 18.897 58.928 ;
     RECT  19.656 58.411 63.918 59.501 ;
     RECT  19.656 59.501 63.882 60.377 ;
     RECT  63.864 60.377 63.882 60.412 ;
     RECT  8.82 58.928 15.138 60.511 ;
     RECT  15.915 58.928 18.897 60.511 ;
     RECT  8.82 60.511 18.897 60.557 ;
     RECT  0.108 58.348 8.097 60.749 ;
     RECT  19.656 60.377 62.73 61.387 ;
     RECT  63.864 60.412 63.918 61.387 ;
     RECT  19.656 61.387 63.918 61.421 ;
     RECT  8.82 60.557 15.138 61.483 ;
     RECT  15.915 60.557 18.897 61.483 ;
     RECT  0.18 60.749 8.097 61.66 ;
     RECT  0.108 61.66 8.097 61.805 ;
     RECT  8.82 61.483 18.897 62.093 ;
     RECT  19.656 61.421 63.882 62.669 ;
     RECT  0.144 61.805 8.097 63.403 ;
     RECT  8.82 62.093 15.138 63.643 ;
     RECT  15.915 62.093 18.897 63.643 ;
     RECT  8.82 63.643 18.897 63.689 ;
     RECT  19.656 62.669 63.342 63.823 ;
     RECT  19.656 63.823 63.882 63.895 ;
     RECT  19.656 63.895 63.918 64.109 ;
     RECT  0.108 63.403 8.097 64.781 ;
     RECT  8.82 63.689 15.138 64.795 ;
     RECT  15.915 63.689 18.897 64.795 ;
     RECT  8.82 64.795 18.897 64.859 ;
     RECT  63.9 64.109 63.918 64.939 ;
     RECT  63.864 64.939 63.918 65.165 ;
     RECT  19.656 64.109 62.766 65.281 ;
     RECT  63.864 65.165 63.882 65.281 ;
     RECT  0.18 64.781 8.097 65.713 ;
     RECT  8.82 64.859 15.138 65.803 ;
     RECT  15.915 64.859 18.897 65.803 ;
     RECT  8.82 65.803 18.897 65.849 ;
     RECT  19.656 65.281 63.882 65.899 ;
     RECT  19.656 65.899 63.918 66.353 ;
     RECT  0.108 65.713 8.097 66.413 ;
     RECT  19.656 66.353 63.414 66.605 ;
     RECT  19.656 66.605 63.306 66.893 ;
     RECT  19.656 66.893 38.574 67.055 ;
     RECT  39.6 66.893 63.306 67.339 ;
     RECT  0.792 66.413 8.097 67.675 ;
     RECT  37.515 67.055 38.574 67.675 ;
     RECT  0.18 67.675 8.097 67.723 ;
     RECT  37.515 67.675 38.826 67.829 ;
     RECT  39.6 67.339 63.882 67.837 ;
     RECT  39.6 67.837 63.918 67.945 ;
     RECT  39.6 67.945 63.954 68.237 ;
     RECT  15.915 65.849 18.897 68.731 ;
     RECT  19.656 67.055 36.774 68.731 ;
     RECT  15.915 68.731 36.774 68.957 ;
     RECT  0.108 67.723 8.097 69.101 ;
     RECT  39.6 68.237 63.882 69.359 ;
     RECT  37.515 67.829 38.574 69.691 ;
     RECT  37.515 69.691 38.754 69.791 ;
     RECT  39.6 69.359 63.378 69.899 ;
     RECT  0.144 69.101 8.097 69.961 ;
     RECT  47.088 69.899 63.378 70.315 ;
     RECT  37.515 69.791 38.574 70.367 ;
     RECT  8.82 65.849 15.138 70.645 ;
     RECT  0.108 69.961 8.097 70.673 ;
     RECT  8.82 70.645 15.174 70.685 ;
     RECT  47.088 70.315 63.882 70.829 ;
     RECT  19.656 68.957 36.774 71.105 ;
     RECT  39.6 69.899 45.897 71.177 ;
     RECT  41.364 71.177 45.897 71.213 ;
     RECT  39.6 71.177 40.497 71.375 ;
     RECT  47.088 70.829 63.306 71.411 ;
     RECT  0.144 70.673 8.097 71.597 ;
     RECT  33.588 71.105 36.774 71.645 ;
     RECT  47.088 71.411 49.374 71.645 ;
     RECT  50.436 71.411 63.306 71.752 ;
     RECT  19.656 71.105 32.67 71.879 ;
     RECT  19.656 71.879 30.942 71.885 ;
     RECT  50.436 71.752 63.342 72.043 ;
     RECT  50.436 72.043 63.882 72.139 ;
     RECT  50.436 72.139 63.918 72.235 ;
     RECT  50.436 72.235 63.954 72.257 ;
     RECT  29.268 71.885 30.942 72.269 ;
     RECT  8.82 70.685 15.138 72.283 ;
     RECT  15.915 68.957 18.897 72.283 ;
     RECT  31.824 71.879 32.67 72.301 ;
     RECT  8.82 72.283 18.897 72.329 ;
     RECT  47.088 71.645 49.338 72.329 ;
     RECT  0.864 71.597 8.097 72.475 ;
     RECT  31.824 72.301 32.85 72.509 ;
     RECT  58.824 72.257 63.954 72.563 ;
     RECT  19.656 71.885 28.494 72.599 ;
     RECT  30.744 72.269 30.942 72.689 ;
     RECT  41.436 71.213 45.897 72.797 ;
     RECT  31.86 72.509 32.85 72.845 ;
     RECT  41.436 72.797 44.838 72.845 ;
     RECT  50.436 72.257 58.014 73.003 ;
     RECT  58.824 72.563 63.882 73.003 ;
     RECT  31.86 72.845 32.397 73.085 ;
     RECT  0.144 72.475 8.097 73.228 ;
     RECT  50.436 73.003 63.882 73.325 ;
     RECT  0.108 73.228 8.097 73.373 ;
     RECT  30.924 72.689 30.942 73.373 ;
     RECT  39.672 71.375 40.497 73.409 ;
     RECT  8.82 72.329 15.138 73.471 ;
     RECT  15.915 72.329 18.897 73.471 ;
     RECT  8.82 73.471 18.897 73.517 ;
     RECT  50.436 73.325 62.802 73.571 ;
     RECT  29.268 72.269 29.934 73.679 ;
     RECT  0.108 73.373 0.126 73.709 ;
     RECT  41.436 72.845 44.73 73.877 ;
     RECT  64.656 73.96 64.674 73.966 ;
     RECT  64.656 73.966 64.746 73.997 ;
     RECT  64.728 73.997 64.746 74.045 ;
     RECT  0.864 73.373 8.097 74.107 ;
     RECT  29.415 73.679 29.934 74.189 ;
     RECT  47.736 72.329 49.338 74.219 ;
     RECT  53.568 73.571 62.802 74.353 ;
     RECT  63.864 73.325 63.882 74.353 ;
     RECT  53.568 74.353 63.882 74.381 ;
     RECT  19.656 72.599 28.458 74.417 ;
     RECT  53.568 74.381 58.05 74.489 ;
     RECT  0.144 74.107 8.097 74.572 ;
     RECT  0.108 74.572 8.097 74.717 ;
     RECT  41.472 73.877 44.73 74.759 ;
     RECT  58.788 74.381 63.882 74.765 ;
     RECT  54.72 74.489 58.05 74.885 ;
     RECT  33.732 71.645 36.774 74.957 ;
     RECT  41.472 74.759 43.614 74.993 ;
     RECT  38.556 70.367 38.574 75.029 ;
     RECT  63.864 74.765 63.882 75.115 ;
     RECT  54.9 74.885 58.05 75.155 ;
     RECT  56.16 75.155 58.05 75.355 ;
     RECT  58.788 74.765 62.802 75.355 ;
     RECT  8.82 73.517 15.138 75.437 ;
     RECT  0.108 74.717 0.126 75.451 ;
     RECT  0.864 74.717 8.097 75.451 ;
     RECT  39.708 73.409 40.497 75.533 ;
     RECT  41.472 74.993 41.922 75.569 ;
     RECT  41.904 75.569 41.922 75.695 ;
     RECT  33.732 74.957 33.75 75.731 ;
     RECT  34.815 74.957 36.774 75.839 ;
     RECT  56.16 75.355 62.802 75.883 ;
     RECT  63.864 75.115 63.918 75.883 ;
     RECT  54.9 75.155 55.422 75.901 ;
     RECT  56.16 75.883 63.918 75.901 ;
     RECT  0.108 75.451 8.097 75.917 ;
     RECT  50.436 73.571 52.758 76.073 ;
     RECT  54.9 75.901 63.918 76.199 ;
     RECT  0.144 75.917 8.097 76.301 ;
     RECT  0.144 76.301 6.858 76.505 ;
     RECT  0.144 76.505 5.397 76.541 ;
     RECT  49.32 74.219 49.338 76.585 ;
     RECT  50.436 76.073 51.822 76.585 ;
     RECT  56.268 76.199 63.918 76.613 ;
     RECT  42.915 74.993 43.614 76.649 ;
     RECT  6.516 76.505 6.858 76.781 ;
     RECT  47.736 74.219 48.597 76.981 ;
     RECT  49.32 76.585 51.822 76.981 ;
     RECT  47.736 76.981 51.822 77.009 ;
     RECT  54.9 76.199 55.278 77.089 ;
     RECT  0.468 76.541 5.397 77.419 ;
     RECT  0.468 77.419 5.49 77.459 ;
     RECT  56.268 76.613 63.306 77.521 ;
     RECT  47.736 77.009 49.626 77.549 ;
     RECT  54.72 77.089 55.278 77.557 ;
     RECT  56.16 77.521 63.306 77.557 ;
     RECT  54.72 77.557 63.306 77.611 ;
     RECT  0.468 77.459 5.397 77.629 ;
     RECT  0.432 77.629 5.397 77.659 ;
     RECT  6.516 76.781 6.534 77.701 ;
     RECT  34.815 75.839 36.702 77.729 ;
     RECT  34.815 77.729 36.63 77.819 ;
     RECT  48.315 77.549 49.626 77.819 ;
     RECT  54.72 77.611 63.882 77.819 ;
     RECT  0.144 77.659 5.397 77.837 ;
     RECT  44.712 74.759 44.73 77.855 ;
     RECT  6.516 77.701 6.822 77.891 ;
     RECT  52.74 76.073 52.758 77.999 ;
     RECT  34.815 77.819 36.486 78.233 ;
     RECT  54.9 77.819 63.882 78.431 ;
     RECT  54.9 78.431 54.918 78.539 ;
     RECT  64.656 78.571 64.674 78.601 ;
     RECT  48.315 77.819 49.338 78.629 ;
     RECT  56.016 78.431 62.766 78.629 ;
     RECT  48.315 78.629 49.266 78.899 ;
     RECT  6.516 77.891 6.534 78.935 ;
     RECT  0.396 77.837 5.397 79.003 ;
     RECT  50.436 77.009 51.822 79.015 ;
     RECT  63.828 78.431 63.882 79.051 ;
     RECT  36.108 78.233 36.486 79.079 ;
     RECT  0.144 79.003 5.397 79.181 ;
     RECT  61.815 78.629 62.766 79.243 ;
     RECT  63.828 79.051 63.918 79.243 ;
     RECT  34.815 78.233 35.262 79.277 ;
     RECT  56.016 78.629 60.75 79.285 ;
     RECT  61.815 79.243 63.918 79.313 ;
     RECT  54.72 78.709 54.81 79.349 ;
     RECT  64.656 78.601 64.746 79.349 ;
     RECT  64.656 79.349 64.674 79.373 ;
     RECT  52.74 79.321 52.758 79.439 ;
     RECT  54.72 79.349 54.738 79.439 ;
     RECT  55.944 79.285 60.75 79.475 ;
     RECT  50.436 79.015 51.894 79.511 ;
     RECT  61.815 79.313 62.73 79.583 ;
     RECT  36.468 79.079 36.486 79.619 ;
     RECT  63.864 79.313 63.918 79.627 ;
     RECT  55.944 79.475 60.606 79.709 ;
     RECT  56.415 79.709 58.374 79.745 ;
     RECT  63.864 79.627 63.99 79.757 ;
     RECT  63.864 79.757 63.954 79.781 ;
     RECT  56.415 79.745 57.942 79.853 ;
     RECT  59.115 79.709 59.994 79.979 ;
     RECT  63.9 79.781 63.954 80.015 ;
     RECT  0.432 79.181 5.397 80.059 ;
     RECT  6.948 79.963 6.966 80.059 ;
     RECT  61.815 79.583 62.694 80.087 ;
     RECT  63.9 80.015 63.918 80.123 ;
     RECT  0.144 80.059 5.397 80.237 ;
     RECT  19.656 74.417 28.134 80.333 ;
     RECT  8.82 75.437 15.102 80.395 ;
     RECT  6.84 80.059 6.966 80.491 ;
     RECT  8.82 80.395 15.138 80.573 ;
     RECT  19.656 80.333 25.938 80.573 ;
     RECT  19.656 80.573 22.518 80.621 ;
     RECT  23.616 80.573 25.938 80.813 ;
     RECT  8.82 80.573 15.102 80.909 ;
     RECT  6.84 80.491 7.002 80.923 ;
     RECT  6.84 80.923 7.038 81.101 ;
     RECT  0.864 80.237 5.397 81.115 ;
     RECT  15.915 73.517 18.897 81.149 ;
     RECT  6.84 81.101 6.966 81.197 ;
     RECT  21.315 80.621 22.518 81.197 ;
     RECT  0.144 81.115 5.397 81.292 ;
     RECT  23.616 80.813 25.398 81.389 ;
     RECT  6.84 81.197 6.858 81.437 ;
     RECT  21.315 81.197 21.978 81.437 ;
     RECT  10.515 80.909 15.102 81.485 ;
     RECT  25.38 81.389 25.398 81.629 ;
     RECT  15.915 81.149 16.83 81.677 ;
     RECT  12.24 81.485 15.102 81.725 ;
     RECT  0.108 81.292 5.397 81.739 ;
     RECT  0.108 81.739 5.49 81.779 ;
     RECT  19.656 80.621 20.502 81.917 ;
     RECT  8.82 80.909 9.414 81.965 ;
     RECT  0.108 81.779 5.397 82.013 ;
     RECT  18 81.149 18.897 82.013 ;
     RECT  18.615 82.013 18.897 82.123 ;
     RECT  19.656 81.917 19.674 82.123 ;
     RECT  7.056 82.123 7.074 82.171 ;
     RECT  8.82 81.965 8.838 82.205 ;
     RECT  14.508 81.725 15.102 82.211 ;
     RECT  6.984 82.171 7.074 82.219 ;
     RECT  18.615 82.123 19.674 82.247 ;
     RECT  6.84 82.219 7.074 82.253 ;
     RECT  18.615 82.247 18.99 82.253 ;
     RECT  23.616 81.389 24.297 82.253 ;
     RECT  14.508 82.211 14.958 82.301 ;
     RECT  0.108 82.013 0.126 82.349 ;
     RECT  14.508 82.301 14.526 82.445 ;
     RECT  6.84 82.253 7.002 82.493 ;
     RECT  26.715 80.333 28.134 82.541 ;
     RECT  6.984 82.493 7.002 82.589 ;
     RECT  28.116 82.541 28.134 82.715 ;
     RECT  0.864 82.013 5.397 82.759 ;
     RECT  12.24 81.725 13.497 82.829 ;
     RECT  0.144 82.759 5.397 83.146 ;
     RECT  10.515 81.485 11.142 83.525 ;
     RECT  12.312 82.829 13.497 83.549 ;
     RECT  12.816 83.549 13.497 83.759 ;
     RECT  53.568 74.489 53.997 83.795 ;
     RECT  0.108 83.146 5.397 83.981 ;
     RECT  20.484 81.917 20.502 84.065 ;
     RECT  56.415 79.853 57.258 84.173 ;
     RECT  0.144 83.981 5.397 84.269 ;
     RECT  0.432 84.269 5.397 84.335 ;
     RECT  0.432 84.335 3.438 84.461 ;
     RECT  4.176 84.335 5.397 84.605 ;
     RECT  50.436 79.511 51.822 84.641 ;
     RECT  19.908 84.181 19.926 84.653 ;
     RECT  13.215 83.759 13.497 84.712 ;
     RECT  6.84 84.619 6.858 84.749 ;
     RECT  13.104 84.712 13.497 84.749 ;
     RECT  14.832 84.619 14.85 84.749 ;
     RECT  2.052 84.461 3.438 84.845 ;
     RECT  50.436 84.641 51.297 85.019 ;
     RECT  4.248 84.605 5.397 85.133 ;
     RECT  2.376 84.845 3.438 85.451 ;
     RECT  0.432 84.461 0.882 85.459 ;
     RECT  4.464 85.133 5.397 85.517 ;
     RECT  0.108 85.459 0.882 85.613 ;
     RECT  2.376 85.451 2.898 85.685 ;
     RECT  0.864 85.613 0.882 85.709 ;
     RECT  2.376 85.685 2.697 85.771 ;
     RECT  2.304 85.771 2.697 85.829 ;
     RECT  0.108 85.613 0.126 85.901 ;
     RECT  33.3 102.619 33.318 102.631 ;
     RECT  33.3 102.631 33.57 102.659 ;
     RECT  33.552 102.659 33.57 102.731 ;
     RECT  2.415 85.829 2.697 103.157 ;
     RECT  5.115 85.517 5.397 103.157 ;
     RECT  7.815 76.301 8.097 103.157 ;
     RECT  10.515 83.525 10.797 103.157 ;
     RECT  13.215 84.749 13.497 103.157 ;
     RECT  15.915 81.677 16.197 103.157 ;
     RECT  18.615 82.253 18.897 103.157 ;
     RECT  21.315 81.437 21.597 103.157 ;
     RECT  24.015 82.253 24.297 103.157 ;
     RECT  26.715 82.541 26.997 103.157 ;
     RECT  29.415 74.189 29.697 103.157 ;
     RECT  32.115 73.085 32.397 103.157 ;
     RECT  34.815 79.277 35.097 103.157 ;
     RECT  37.515 70.367 37.797 103.157 ;
     RECT  40.215 75.533 40.497 103.157 ;
     RECT  42.915 76.649 43.197 103.157 ;
     RECT  45.615 72.797 45.897 103.157 ;
     RECT  48.315 78.899 48.597 103.157 ;
     RECT  51.015 85.019 51.297 103.157 ;
     RECT  53.715 83.795 53.997 103.157 ;
     RECT  56.415 84.173 56.697 103.157 ;
     RECT  59.115 79.979 59.397 103.157 ;
     RECT  61.815 80.087 62.097 103.157 ;
     RECT  33.732 102.811 33.75 103.181 ;
     RECT  2.607 103.157 2.697 103.427 ;
     RECT  5.307 103.157 5.397 103.427 ;
     RECT  8.007 103.157 8.097 103.427 ;
     RECT  10.707 103.157 10.797 103.427 ;
     RECT  13.407 103.157 13.497 103.427 ;
     RECT  16.107 103.157 16.197 103.427 ;
     RECT  18.807 103.157 18.897 103.427 ;
     RECT  21.507 103.157 21.597 103.427 ;
     RECT  24.207 103.157 24.297 103.427 ;
     RECT  26.907 103.157 26.997 103.427 ;
     RECT  29.607 103.157 29.697 103.427 ;
     RECT  32.307 103.157 32.397 103.427 ;
     RECT  35.007 103.157 35.097 103.427 ;
     RECT  37.707 103.157 37.797 103.427 ;
     RECT  40.407 103.157 40.497 103.427 ;
     RECT  43.107 103.157 43.197 103.427 ;
     RECT  45.807 103.157 45.897 103.427 ;
     RECT  48.507 103.157 48.597 103.427 ;
     RECT  51.207 103.157 51.297 103.427 ;
     RECT  53.907 103.157 53.997 103.427 ;
     RECT  56.607 103.157 56.697 103.427 ;
     RECT  59.307 103.157 59.397 103.427 ;
     RECT  62.007 103.157 62.097 103.427 ;
    LAYER M4 ;
     RECT  0.084 25.968 0.137 25.992 ;
     RECT  0.06 25.992 0.137 26.064 ;
     RECT  0.084 26.064 0.137 26.088 ;
     RECT  0.06 26.088 0.137 26.16 ;
     RECT  0.084 26.16 0.137 26.184 ;
     RECT  0.06 26.184 0.137 26.256 ;
     RECT  0.084 26.256 0.137 26.28 ;
     RECT  0.06 26.28 0.137 26.352 ;
     RECT  0.084 26.352 0.137 26.376 ;
     RECT  0.06 26.376 0.137 26.448 ;
     RECT  0.084 26.448 0.137 26.472 ;
     RECT  0.06 26.472 0.137 26.544 ;
     RECT  0.084 26.544 0.137 26.568 ;
     RECT  0.06 26.568 0.137 26.64 ;
     RECT  0.084 26.64 0.137 26.664 ;
     RECT  0.06 26.664 0.137 26.736 ;
     RECT  0.084 26.736 0.137 26.76 ;
     RECT  0.06 26.76 0.137 26.832 ;
     RECT  0.084 26.832 0.137 26.856 ;
     RECT  0.06 26.856 0.137 26.928 ;
     RECT  0.084 26.928 0.137 26.952 ;
     RECT  0.06 26.952 0.137 27.024 ;
     RECT  0.084 27.024 0.137 27.048 ;
     RECT  0.06 27.048 0.137 27.12 ;
     RECT  0.084 27.12 0.137 27.144 ;
     RECT  0.06 27.144 0.137 27.216 ;
     RECT  0.084 27.216 0.137 27.24 ;
     RECT  0.06 27.24 0.137 27.312 ;
     RECT  0.084 27.312 0.137 27.336 ;
     RECT  0.06 27.336 0.137 27.408 ;
     RECT  0.084 27.408 0.137 27.432 ;
     RECT  0.06 27.432 0.137 27.504 ;
     RECT  0.084 27.504 0.137 27.528 ;
     RECT  0.06 27.528 0.137 27.6 ;
     RECT  0.084 27.6 0.137 27.624 ;
     RECT  0.06 27.624 0.137 27.696 ;
     RECT  0.084 27.696 0.137 27.72 ;
     RECT  0.06 27.72 0.137 27.792 ;
     RECT  0.084 27.792 0.137 27.816 ;
     RECT  0.06 27.816 0.137 27.888 ;
     RECT  0.084 27.888 0.137 27.912 ;
     RECT  0.06 27.912 0.137 27.984 ;
     RECT  0.084 27.984 0.137 28.008 ;
     RECT  0.06 28.008 0.137 28.08 ;
     RECT  0.084 28.08 0.137 28.104 ;
     RECT  0.06 28.104 0.137 28.176 ;
     RECT  0.084 28.176 0.137 28.2 ;
     RECT  0.06 28.2 0.137 28.272 ;
     RECT  0.084 28.272 0.137 28.296 ;
     RECT  0.06 28.296 0.137 29.136 ;
     RECT  0.084 29.136 0.137 29.16 ;
     RECT  0.06 29.16 0.137 29.232 ;
     RECT  0.084 29.232 0.137 29.256 ;
     RECT  0.06 29.256 0.137 29.328 ;
     RECT  0.084 29.328 0.137 29.352 ;
     RECT  0.06 29.352 0.137 29.424 ;
     RECT  0.084 29.424 0.137 29.448 ;
     RECT  0.06 29.448 0.137 29.52 ;
     RECT  0.084 29.52 0.137 29.544 ;
     RECT  0.06 29.544 0.137 29.616 ;
     RECT  0.084 29.616 0.137 29.64 ;
     RECT  0.06 29.64 0.137 29.712 ;
     RECT  0.084 29.712 0.137 29.736 ;
     RECT  0.06 29.736 0.137 29.808 ;
     RECT  0.084 29.808 0.137 29.832 ;
     RECT  0.06 29.832 0.137 29.904 ;
     RECT  0.084 29.904 0.137 29.928 ;
     RECT  0.06 29.928 0.137 30 ;
     RECT  0.084 30 0.137 30.024 ;
     RECT  0.06 30.024 0.137 30.096 ;
     RECT  0.084 30.096 0.137 30.12 ;
     RECT  0.06 30.12 0.137 30.192 ;
     RECT  0.084 30.192 0.137 30.216 ;
     RECT  0.06 30.216 0.137 30.288 ;
     RECT  0.084 30.288 0.137 30.312 ;
     RECT  0.06 30.312 0.137 30.384 ;
     RECT  0.084 30.384 0.137 30.408 ;
     RECT  0.06 30.408 0.137 30.48 ;
     RECT  0.084 30.48 0.137 30.504 ;
     RECT  0.06 30.504 0.137 30.576 ;
     RECT  0.084 30.576 0.137 30.6 ;
     RECT  0.06 30.6 0.137 30.672 ;
     RECT  0.084 30.672 0.137 30.696 ;
     RECT  0.06 30.696 0.137 30.768 ;
     RECT  0.084 30.768 0.137 30.792 ;
     RECT  0.06 30.792 0.137 30.864 ;
     RECT  0.084 30.864 0.137 30.888 ;
     RECT  0.06 30.888 0.137 30.96 ;
     RECT  0.084 30.96 0.137 30.984 ;
     RECT  0.06 30.984 0.137 31.056 ;
     RECT  0.084 31.056 0.137 31.08 ;
     RECT  0.06 31.08 0.137 31.152 ;
     RECT  0.084 31.152 0.137 31.176 ;
     RECT  0.06 31.176 0.137 31.248 ;
     RECT  0.084 31.248 0.137 31.272 ;
     RECT  0.06 31.272 0.137 31.344 ;
     RECT  0.084 31.344 0.137 31.368 ;
     RECT  0.06 31.368 0.137 31.44 ;
     RECT  0.084 31.44 0.137 31.464 ;
     RECT  0.06 31.464 0.137 31.536 ;
     RECT  0.084 31.536 0.137 31.56 ;
     RECT  0.06 31.56 0.137 31.632 ;
     RECT  0.084 31.632 0.137 31.656 ;
     RECT  0.06 31.656 0.137 31.728 ;
     RECT  0.084 31.728 0.137 31.752 ;
     RECT  0.06 31.752 0.137 31.824 ;
     RECT  0.084 31.824 0.137 31.848 ;
     RECT  0.06 31.848 0.137 31.92 ;
     RECT  0.084 31.92 0.137 31.944 ;
     RECT  0.06 31.944 0.137 32.016 ;
     RECT  0.084 32.016 0.137 32.04 ;
     RECT  0.06 32.04 0.137 32.112 ;
     RECT  0.084 32.112 0.137 32.136 ;
     RECT  0.06 32.136 0.137 32.208 ;
     RECT  0.084 32.208 0.137 32.232 ;
     RECT  0.06 32.232 0.137 32.304 ;
     RECT  0.084 32.304 0.137 32.328 ;
     RECT  0.06 32.328 0.137 32.4 ;
     RECT  0.084 32.4 0.137 32.424 ;
     RECT  0.06 32.424 0.137 32.496 ;
     RECT  0.084 32.496 0.137 32.52 ;
     RECT  0.06 32.52 0.137 32.592 ;
     RECT  0.084 32.592 0.137 32.616 ;
     RECT  0.06 32.616 0.137 32.688 ;
     RECT  0.084 32.688 0.137 32.712 ;
     RECT  0.06 32.712 0.137 32.784 ;
     RECT  0.084 32.784 0.137 32.808 ;
     RECT  0.06 32.808 0.137 32.88 ;
     RECT  0.084 32.88 0.137 32.904 ;
     RECT  0.06 32.904 0.137 32.976 ;
     RECT  0.084 32.976 0.137 33 ;
     RECT  0.06 33 0.137 33.072 ;
     RECT  0.084 33.072 0.137 33.096 ;
     RECT  0.06 33.096 0.137 33.168 ;
     RECT  0.084 33.168 0.137 33.192 ;
     RECT  0.06 33.192 0.137 33.264 ;
     RECT  0.084 33.264 0.137 33.288 ;
     RECT  0.06 33.288 0.137 33.36 ;
     RECT  0.084 33.36 0.137 33.384 ;
     RECT  0.06 33.384 0.137 33.456 ;
     RECT  0.084 33.456 0.137 33.48 ;
     RECT  0.06 33.48 0.137 33.552 ;
     RECT  0.084 33.552 0.137 33.576 ;
     RECT  0.06 33.576 0.137 33.648 ;
     RECT  0.084 33.648 0.137 33.672 ;
     RECT  0.06 33.672 0.137 33.744 ;
     RECT  0.084 33.744 0.137 33.768 ;
     RECT  0.06 33.768 0.137 33.84 ;
     RECT  0.084 33.84 0.137 33.864 ;
     RECT  0.06 33.864 0.137 33.936 ;
     RECT  0.084 33.936 0.137 33.96 ;
     RECT  0.06 33.96 0.137 34.032 ;
     RECT  0.084 34.032 0.137 34.056 ;
     RECT  0.06 34.056 0.137 34.128 ;
     RECT  0.084 34.128 0.137 34.152 ;
     RECT  0.06 34.152 0.137 34.224 ;
     RECT  0.084 34.224 0.137 34.248 ;
     RECT  0.06 34.248 0.137 34.32 ;
     RECT  0.084 34.32 0.137 34.344 ;
     RECT  0.06 34.344 0.137 34.416 ;
     RECT  0.084 34.416 0.137 34.44 ;
     RECT  0.06 34.44 0.137 34.512 ;
     RECT  0.084 34.512 0.137 34.536 ;
     RECT  0.06 34.536 0.137 34.608 ;
     RECT  0.084 34.608 0.137 34.632 ;
     RECT  0.06 34.632 0.137 34.704 ;
     RECT  0.084 34.704 0.137 34.728 ;
     RECT  0.06 34.728 0.137 34.8 ;
     RECT  0.084 34.8 0.137 34.824 ;
     RECT  0.06 34.824 0.137 34.896 ;
     RECT  0.084 34.896 0.137 34.92 ;
     RECT  0.06 34.92 0.137 34.992 ;
     RECT  0.084 34.992 0.137 35.016 ;
     RECT  0.06 35.016 0.137 35.088 ;
     RECT  0.084 35.088 0.137 35.112 ;
     RECT  0.06 35.112 0.137 35.184 ;
     RECT  0.084 35.184 0.137 35.208 ;
     RECT  0.06 35.208 0.137 35.28 ;
     RECT  0.084 35.28 0.137 35.304 ;
     RECT  0.06 35.304 0.137 35.376 ;
     RECT  0.084 35.376 0.137 35.4 ;
     RECT  0.06 35.4 0.137 35.472 ;
     RECT  0.084 35.472 0.137 35.496 ;
     RECT  0.06 35.496 0.137 35.568 ;
     RECT  0.084 35.568 0.137 35.592 ;
     RECT  0.06 35.592 0.137 35.664 ;
     RECT  0.084 35.664 0.137 35.688 ;
     RECT  0.06 35.688 0.137 35.76 ;
     RECT  0.084 35.76 0.137 35.784 ;
     RECT  0.06 35.784 0.137 35.856 ;
     RECT  0.084 35.856 0.137 35.88 ;
     RECT  0.06 35.88 0.137 35.952 ;
     RECT  0.084 35.952 0.137 35.976 ;
     RECT  0.06 35.976 0.137 36.048 ;
     RECT  0.084 36.048 0.137 36.072 ;
     RECT  0.06 36.072 0.137 36.144 ;
     RECT  0.084 36.144 0.137 36.168 ;
     RECT  0.06 36.168 0.137 36.24 ;
     RECT  0.084 36.24 0.137 36.264 ;
     RECT  0.06 36.264 0.137 36.336 ;
     RECT  0.084 36.336 0.137 36.36 ;
     RECT  0.06 36.36 0.137 36.432 ;
     RECT  0.084 36.432 0.137 36.456 ;
     RECT  0.06 36.456 0.137 36.528 ;
     RECT  0.084 36.528 0.137 36.552 ;
     RECT  0.06 36.552 0.137 36.624 ;
     RECT  0.084 36.624 0.137 36.648 ;
     RECT  0.06 36.648 0.137 36.72 ;
     RECT  0.084 36.72 0.137 36.744 ;
     RECT  0.06 36.744 0.137 36.816 ;
     RECT  0.084 36.816 0.137 36.84 ;
     RECT  0.06 36.84 0.137 36.912 ;
     RECT  0.084 36.912 0.137 36.936 ;
     RECT  0.06 36.936 0.137 37.008 ;
     RECT  0.084 37.008 0.137 37.032 ;
     RECT  0.06 37.032 0.137 37.104 ;
     RECT  0.084 37.104 0.137 37.128 ;
     RECT  0.06 37.128 0.137 37.2 ;
     RECT  0.084 37.2 0.137 37.224 ;
     RECT  0.06 37.224 0.137 37.296 ;
     RECT  0.084 37.296 0.137 37.32 ;
     RECT  0.06 37.32 0.137 37.392 ;
     RECT  0.084 37.392 0.137 37.416 ;
     RECT  0.06 37.416 0.137 37.488 ;
     RECT  0.084 37.488 0.137 37.512 ;
     RECT  0.06 37.512 0.137 37.584 ;
     RECT  0.084 37.584 0.137 37.608 ;
     RECT  0.06 37.608 0.137 37.68 ;
     RECT  0.084 37.68 0.137 37.704 ;
     RECT  0.06 37.704 0.137 37.776 ;
     RECT  0.084 37.776 0.137 37.8 ;
     RECT  0.06 37.8 0.137 37.872 ;
     RECT  0.084 37.872 0.137 37.896 ;
     RECT  0.06 37.896 0.137 37.968 ;
     RECT  0.084 37.968 0.137 37.992 ;
     RECT  0.06 37.992 0.137 38.064 ;
     RECT  0.084 38.064 0.137 38.088 ;
     RECT  0.06 38.088 0.137 38.16 ;
     RECT  0.084 38.16 0.137 38.184 ;
     RECT  0.06 38.184 0.137 38.256 ;
     RECT  0.084 38.256 0.137 38.28 ;
     RECT  0.06 38.28 0.137 38.352 ;
     RECT  0.084 38.352 0.137 38.376 ;
     RECT  0.06 38.376 0.137 38.448 ;
     RECT  0.084 38.448 0.137 38.472 ;
     RECT  0.06 38.472 0.137 38.544 ;
     RECT  0.084 38.544 0.137 38.568 ;
     RECT  0.06 38.568 0.137 38.64 ;
     RECT  0.084 38.64 0.137 38.664 ;
     RECT  0.06 38.664 0.137 38.736 ;
     RECT  0.084 38.736 0.137 38.76 ;
     RECT  0.06 38.76 0.137 38.832 ;
     RECT  0.084 38.832 0.137 38.856 ;
     RECT  0.06 38.856 0.137 38.928 ;
     RECT  0.084 38.928 0.137 38.952 ;
     RECT  0.06 38.952 0.137 39.024 ;
     RECT  0.084 39.024 0.137 39.048 ;
     RECT  0.06 39.048 0.137 39.12 ;
     RECT  0.084 39.12 0.137 39.144 ;
     RECT  0.06 39.144 0.137 39.216 ;
     RECT  0.084 39.216 0.137 39.24 ;
     RECT  0.06 39.24 0.137 39.312 ;
     RECT  0.084 39.312 0.137 39.336 ;
     RECT  0.06 39.336 0.137 39.408 ;
     RECT  0.084 39.408 0.137 39.432 ;
     RECT  0.06 39.432 0.137 39.504 ;
     RECT  0.084 39.504 0.137 39.528 ;
     RECT  0.06 39.528 0.137 39.6 ;
     RECT  0.084 39.6 0.137 39.624 ;
     RECT  0.06 39.624 0.137 39.696 ;
     RECT  0.084 39.696 0.137 39.72 ;
     RECT  0.06 39.72 0.137 39.792 ;
     RECT  0.084 39.792 0.137 39.816 ;
     RECT  0.06 39.816 0.137 39.888 ;
     RECT  0.084 39.888 0.137 39.912 ;
     RECT  0.06 39.912 0.137 39.984 ;
     RECT  0.084 39.984 0.137 40.008 ;
     RECT  0.06 40.008 0.137 40.08 ;
     RECT  0.084 40.08 0.137 40.104 ;
     RECT  0.06 40.104 0.137 40.176 ;
     RECT  0.084 40.176 0.137 40.2 ;
     RECT  0.06 40.2 0.137 40.272 ;
     RECT  0.084 40.272 0.137 40.296 ;
     RECT  0.06 40.296 0.137 40.368 ;
     RECT  0.084 40.368 0.137 40.392 ;
     RECT  0.06 40.392 0.137 40.464 ;
     RECT  0.084 40.464 0.137 40.488 ;
     RECT  0.06 40.488 0.137 40.56 ;
     RECT  0.084 40.56 0.137 40.584 ;
     RECT  0.06 40.584 0.137 40.656 ;
     RECT  0.084 40.656 0.137 40.68 ;
     RECT  0.06 40.68 0.137 40.752 ;
     RECT  0.084 40.752 0.137 40.776 ;
     RECT  0.06 40.776 0.137 40.848 ;
     RECT  0.084 40.848 0.137 40.872 ;
     RECT  0.06 40.872 0.137 40.944 ;
     RECT  0.084 40.944 0.137 40.968 ;
     RECT  0.06 40.968 0.137 41.04 ;
     RECT  0.084 41.04 0.137 41.064 ;
     RECT  0.06 41.064 0.137 41.136 ;
     RECT  0.084 41.136 0.137 41.16 ;
     RECT  0.06 41.16 0.137 41.232 ;
     RECT  0.084 41.232 0.137 41.256 ;
     RECT  0.06 41.256 0.137 41.328 ;
     RECT  0.084 41.328 0.137 41.352 ;
     RECT  0.06 41.352 0.137 41.424 ;
     RECT  0.084 41.424 0.137 41.448 ;
     RECT  0.06 41.448 0.137 41.52 ;
     RECT  0.084 41.52 0.137 41.544 ;
     RECT  0.06 41.544 0.137 41.616 ;
     RECT  0.084 41.616 0.137 41.64 ;
     RECT  0.06 41.64 0.137 41.712 ;
     RECT  0.084 41.712 0.137 41.736 ;
     RECT  0.06 41.736 0.137 41.808 ;
     RECT  0.084 41.808 0.137 41.832 ;
     RECT  0.06 41.832 0.137 41.904 ;
     RECT  0.084 41.904 0.137 41.928 ;
     RECT  0.06 41.928 0.137 42 ;
     RECT  0.084 42 0.137 42.024 ;
     RECT  0.06 42.024 0.137 42.096 ;
     RECT  0.084 42.096 0.137 42.12 ;
     RECT  0.06 42.12 0.137 42.192 ;
     RECT  0.084 42.192 0.137 42.216 ;
     RECT  0.06 42.216 0.137 42.288 ;
     RECT  0.084 42.288 0.137 42.312 ;
     RECT  0.06 42.312 0.137 42.384 ;
     RECT  0.084 42.384 0.137 42.408 ;
     RECT  0.06 42.408 0.137 42.48 ;
     RECT  0.084 42.48 0.137 42.504 ;
     RECT  0.06 42.504 0.137 42.576 ;
     RECT  0.084 42.576 0.137 42.6 ;
     RECT  0.06 42.6 0.137 42.672 ;
     RECT  0.084 42.672 0.137 42.696 ;
     RECT  0.06 42.696 0.137 42.768 ;
     RECT  0.084 42.768 0.137 42.792 ;
     RECT  0.06 42.792 0.137 42.864 ;
     RECT  0.084 42.864 0.137 42.888 ;
     RECT  0.06 42.888 0.137 42.96 ;
     RECT  0.084 42.96 0.137 42.984 ;
     RECT  0.06 42.984 0.137 43.056 ;
     RECT  0.084 43.056 0.137 43.08 ;
     RECT  0.06 43.08 0.137 43.152 ;
     RECT  0.084 43.152 0.137 43.176 ;
     RECT  0.06 43.176 0.137 43.248 ;
     RECT  0.084 43.248 0.137 43.272 ;
     RECT  0.06 43.272 0.137 43.344 ;
     RECT  0.084 43.344 0.137 43.368 ;
     RECT  0.06 43.368 0.137 43.44 ;
     RECT  0.084 43.44 0.137 43.464 ;
     RECT  0.06 43.464 0.137 43.536 ;
     RECT  0.084 43.536 0.137 43.56 ;
     RECT  0.06 43.56 0.137 43.632 ;
     RECT  0.084 43.632 0.137 43.656 ;
     RECT  0.06 43.656 0.137 43.728 ;
     RECT  0.084 43.728 0.137 43.752 ;
     RECT  0.06 43.752 0.137 43.824 ;
     RECT  0.084 43.824 0.137 43.848 ;
     RECT  0.06 43.848 0.137 43.92 ;
     RECT  0.084 43.92 0.137 43.944 ;
     RECT  0.06 43.944 0.137 44.016 ;
     RECT  0.084 44.016 0.137 44.04 ;
     RECT  0.06 44.04 0.137 44.112 ;
     RECT  0.084 44.112 0.137 44.136 ;
     RECT  0.06 44.136 0.137 44.208 ;
     RECT  0.084 44.208 0.137 44.232 ;
     RECT  0.06 44.232 0.137 44.304 ;
     RECT  0.084 44.304 0.137 44.328 ;
     RECT  0.06 44.328 0.137 44.4 ;
     RECT  0.084 44.4 0.137 44.424 ;
     RECT  0.06 44.424 0.137 44.496 ;
     RECT  0.084 44.496 0.137 44.52 ;
     RECT  0.06 44.52 0.137 44.592 ;
     RECT  0.084 44.592 0.137 44.616 ;
     RECT  0.06 44.616 0.137 44.688 ;
     RECT  0.084 44.688 0.137 44.712 ;
     RECT  0.06 44.712 0.137 44.784 ;
     RECT  0.084 44.784 0.137 44.808 ;
     RECT  0.06 44.808 0.137 44.88 ;
     RECT  0.084 44.88 0.137 44.904 ;
     RECT  0.06 44.904 0.137 44.976 ;
     RECT  0.084 44.976 0.137 45 ;
     RECT  0.06 45 0.137 45.072 ;
     RECT  0.084 45.072 0.137 45.096 ;
     RECT  0.06 45.096 0.137 45.168 ;
     RECT  0.084 45.168 0.137 45.192 ;
     RECT  0.06 45.192 0.137 45.264 ;
     RECT  0.084 45.264 0.137 45.288 ;
     RECT  0.06 45.288 0.137 45.36 ;
     RECT  0.084 45.36 0.137 45.384 ;
     RECT  0.06 45.384 0.137 45.456 ;
     RECT  0.084 45.456 0.137 45.48 ;
     RECT  0.06 45.48 0.137 45.552 ;
     RECT  0.084 45.552 0.137 45.576 ;
     RECT  0.06 45.576 0.137 45.648 ;
     RECT  0.084 45.648 0.137 45.672 ;
     RECT  0.06 45.672 0.137 45.744 ;
     RECT  0.084 45.744 0.137 45.768 ;
     RECT  0.06 45.768 0.137 45.84 ;
     RECT  0.084 45.84 0.137 45.864 ;
     RECT  0.06 45.864 0.137 45.936 ;
     RECT  0.084 45.936 0.137 45.96 ;
     RECT  0.06 45.96 0.137 46.032 ;
     RECT  0.084 46.032 0.137 46.056 ;
     RECT  0.06 46.056 0.137 46.128 ;
     RECT  0.084 46.128 0.137 46.152 ;
     RECT  0.06 46.152 0.137 46.224 ;
     RECT  0.084 46.224 0.137 46.248 ;
     RECT  0.06 46.248 0.137 46.32 ;
     RECT  0.084 46.32 0.137 46.344 ;
     RECT  0.06 46.344 0.137 46.416 ;
     RECT  0.084 46.416 0.137 46.44 ;
     RECT  0.06 46.44 0.137 46.512 ;
     RECT  0.084 46.512 0.137 46.536 ;
     RECT  0.06 46.536 0.137 46.608 ;
     RECT  0.084 46.608 0.137 46.632 ;
     RECT  0.06 46.632 0.137 46.704 ;
     RECT  0.084 46.704 0.137 46.728 ;
     RECT  0.06 46.728 0.137 46.8 ;
     RECT  0.084 46.8 0.137 46.824 ;
     RECT  0.06 46.824 0.137 46.896 ;
     RECT  0.084 46.896 0.137 46.92 ;
     RECT  0.06 46.92 0.137 46.992 ;
     RECT  0.084 46.992 0.137 47.016 ;
     RECT  0.06 47.016 0.137 47.088 ;
     RECT  0.084 47.088 0.137 47.112 ;
     RECT  0.06 47.112 0.137 47.184 ;
     RECT  0.084 47.184 0.137 47.208 ;
     RECT  0.06 47.208 0.137 47.28 ;
     RECT  0.084 47.28 0.137 47.304 ;
     RECT  0.06 47.304 0.137 47.376 ;
     RECT  0.084 47.376 0.137 47.4 ;
     RECT  0.06 47.4 0.137 47.472 ;
     RECT  0.084 47.472 0.137 47.496 ;
     RECT  0.06 47.496 0.137 48.336 ;
     RECT  0.084 48.336 0.137 48.36 ;
     RECT  0.06 48.36 0.137 48.432 ;
     RECT  0.084 48.432 0.137 48.456 ;
     RECT  0.06 48.456 0.137 48.528 ;
     RECT  0.084 48.528 0.137 48.552 ;
     RECT  0.06 48.552 0.137 48.624 ;
     RECT  0.084 48.624 0.137 48.648 ;
     RECT  0.06 48.648 0.137 48.72 ;
     RECT  0.084 48.72 0.137 48.744 ;
     RECT  0.06 48.744 0.137 48.816 ;
     RECT  0.084 48.816 0.137 48.84 ;
     RECT  0.06 48.84 0.137 48.912 ;
     RECT  0.084 48.912 0.137 48.936 ;
     RECT  0.06 48.936 0.137 49.008 ;
     RECT  0.084 49.008 0.137 49.032 ;
     RECT  0.06 49.032 0.137 49.104 ;
     RECT  0.084 49.104 0.137 49.128 ;
     RECT  0.06 49.128 0.137 49.2 ;
     RECT  0.084 49.2 0.137 49.224 ;
     RECT  0.06 49.224 0.137 49.296 ;
     RECT  0.084 49.296 0.137 49.32 ;
     RECT  0.06 49.32 0.137 49.392 ;
     RECT  0.084 49.392 0.137 49.416 ;
     RECT  0.06 49.416 0.137 49.488 ;
     RECT  0.084 49.488 0.137 49.512 ;
     RECT  0.06 49.512 0.137 49.584 ;
     RECT  0.084 49.584 0.137 49.608 ;
     RECT  0.06 49.608 0.137 49.68 ;
     RECT  0.084 49.68 0.137 49.704 ;
     RECT  0.06 49.704 0.137 49.776 ;
     RECT  0.084 49.776 0.137 49.8 ;
     RECT  0.06 49.8 0.137 49.872 ;
     RECT  0.084 49.872 0.137 49.896 ;
     RECT  0.06 49.896 0.137 49.968 ;
     RECT  0.084 49.968 0.137 49.992 ;
     RECT  0.06 49.992 0.137 50.064 ;
     RECT  0.084 50.064 0.137 50.088 ;
     RECT  0.06 50.088 0.137 50.16 ;
     RECT  0.084 50.16 0.137 50.184 ;
     RECT  0.06 50.184 0.137 50.256 ;
     RECT  0.084 50.256 0.137 50.28 ;
     RECT  0.06 50.28 0.137 50.352 ;
     RECT  0.084 50.352 0.137 50.376 ;
     RECT  0.06 50.376 0.137 50.448 ;
     RECT  0.084 50.448 0.137 50.472 ;
     RECT  0.06 50.472 0.137 50.544 ;
     RECT  0.084 50.544 0.137 50.568 ;
     RECT  0.06 50.568 0.137 50.64 ;
     RECT  0.084 50.64 0.137 50.664 ;
     RECT  0.06 50.664 0.137 50.736 ;
     RECT  0.084 50.736 0.137 50.76 ;
     RECT  0.06 50.76 0.137 50.832 ;
     RECT  0.084 50.832 0.137 50.856 ;
     RECT  0.06 50.856 0.137 50.928 ;
     RECT  0.084 50.928 0.137 50.952 ;
     RECT  0.06 50.952 0.137 51.024 ;
     RECT  0.084 51.024 0.137 51.048 ;
     RECT  0.06 51.048 0.137 51.12 ;
     RECT  0.084 51.12 0.137 51.144 ;
     RECT  0.06 51.144 0.137 51.216 ;
     RECT  0.084 51.216 0.137 51.24 ;
     RECT  0.06 51.24 0.137 51.312 ;
     RECT  0.084 51.312 0.137 51.336 ;
     RECT  0.06 51.336 0.137 51.408 ;
     RECT  0.084 51.408 0.137 51.432 ;
     RECT  0.06 51.432 0.137 51.504 ;
     RECT  0.084 51.504 0.137 51.528 ;
     RECT  0.06 51.528 0.137 51.6 ;
     RECT  0.084 51.6 0.137 51.624 ;
     RECT  0.06 51.624 0.137 51.696 ;
     RECT  0.084 51.696 0.137 51.72 ;
     RECT  0.06 51.72 0.137 51.792 ;
     RECT  0.084 51.792 0.137 51.816 ;
     RECT  0.06 51.816 0.137 51.888 ;
     RECT  0.084 51.888 0.137 51.912 ;
     RECT  0.06 51.912 0.137 51.984 ;
     RECT  0.084 51.984 0.137 52.008 ;
     RECT  0.06 52.008 0.137 52.08 ;
     RECT  0.084 52.08 0.137 52.104 ;
     RECT  0.06 52.104 0.137 52.176 ;
     RECT  0.084 52.176 0.137 52.2 ;
     RECT  0.06 52.2 0.137 52.272 ;
     RECT  0.084 52.272 0.137 52.296 ;
     RECT  0.06 52.296 0.137 52.368 ;
     RECT  0.084 52.368 0.137 52.392 ;
     RECT  0.06 52.392 0.137 52.464 ;
     RECT  0.084 52.464 0.137 52.488 ;
     RECT  0.06 52.488 0.137 52.56 ;
     RECT  0.084 52.56 0.137 52.584 ;
     RECT  0.06 52.584 0.137 52.656 ;
     RECT  0.084 52.656 0.137 52.68 ;
     RECT  0.06 52.68 0.137 52.752 ;
     RECT  0.084 52.752 0.137 52.776 ;
     RECT  0.06 52.776 0.137 52.848 ;
     RECT  0.084 52.848 0.137 52.872 ;
     RECT  0.06 52.872 0.137 52.944 ;
     RECT  0.084 52.944 0.137 52.968 ;
     RECT  0.06 52.968 0.137 53.04 ;
     RECT  0.084 53.04 0.137 53.064 ;
     RECT  0.06 53.064 0.137 53.136 ;
     RECT  0.084 53.136 0.137 53.16 ;
     RECT  0.06 53.16 0.137 53.232 ;
     RECT  0.084 53.232 0.137 53.256 ;
     RECT  0.06 53.256 0.137 53.328 ;
     RECT  0.084 53.328 0.137 53.352 ;
     RECT  0.06 53.352 0.137 53.424 ;
     RECT  0.084 53.424 0.137 53.448 ;
     RECT  0.06 53.448 0.137 53.52 ;
     RECT  0.084 53.52 0.137 53.544 ;
     RECT  0.06 53.544 0.137 53.616 ;
     RECT  0.084 53.616 0.137 53.64 ;
     RECT  0.06 53.64 0.137 53.712 ;
     RECT  0.084 53.712 0.137 53.736 ;
     RECT  0.06 53.736 0.137 53.808 ;
     RECT  0.084 53.808 0.137 53.832 ;
     RECT  0.06 53.832 0.137 53.904 ;
     RECT  0.084 53.904 0.137 53.928 ;
     RECT  0.06 53.928 0.137 54 ;
     RECT  0.084 54 0.137 54.024 ;
     RECT  0.06 54.024 0.137 54.096 ;
     RECT  0.084 54.096 0.137 54.12 ;
     RECT  0.06 54.12 0.137 54.192 ;
     RECT  0.084 54.192 0.137 54.216 ;
     RECT  0.06 54.216 0.137 54.288 ;
     RECT  0.084 54.288 0.137 54.312 ;
     RECT  0.06 54.312 0.137 54.384 ;
     RECT  0.084 54.384 0.137 54.408 ;
     RECT  0.06 54.408 0.137 54.48 ;
     RECT  0.084 54.48 0.137 54.504 ;
     RECT  0.06 54.504 0.137 54.576 ;
     RECT  0.084 54.576 0.137 54.6 ;
     RECT  0.06 54.6 0.137 54.672 ;
     RECT  0.084 54.672 0.137 54.696 ;
     RECT  0.06 54.696 0.137 54.768 ;
     RECT  0.084 54.768 0.137 54.792 ;
     RECT  0.06 54.792 0.137 54.864 ;
     RECT  0.084 54.864 0.137 54.888 ;
     RECT  0.06 54.888 0.137 54.96 ;
     RECT  0.084 54.96 0.137 54.984 ;
     RECT  0.06 54.984 0.137 55.056 ;
     RECT  0.084 55.056 0.137 55.08 ;
     RECT  0.06 55.08 0.137 55.152 ;
     RECT  0.084 55.152 0.137 55.176 ;
     RECT  0.06 55.176 0.137 55.248 ;
     RECT  0.084 55.248 0.137 55.272 ;
     RECT  0.06 55.272 0.137 55.344 ;
     RECT  0.084 55.344 0.137 55.368 ;
     RECT  0.06 55.368 0.137 55.44 ;
     RECT  0.084 55.44 0.137 55.464 ;
     RECT  0.06 55.464 0.137 55.536 ;
     RECT  0.084 55.536 0.137 55.56 ;
     RECT  0.06 55.56 0.137 55.632 ;
     RECT  0.084 55.632 0.137 55.656 ;
     RECT  0.06 55.656 0.137 55.728 ;
     RECT  0.084 55.728 0.137 55.752 ;
     RECT  0.06 55.752 0.137 55.824 ;
     RECT  0.084 55.824 0.137 55.848 ;
     RECT  0.06 55.848 0.137 55.92 ;
     RECT  0.084 55.92 0.137 55.944 ;
     RECT  0.06 55.944 0.137 56.016 ;
     RECT  0.084 56.016 0.137 56.04 ;
     RECT  0.06 56.04 0.137 56.112 ;
     RECT  0.084 56.112 0.137 56.136 ;
     RECT  0.06 56.136 0.137 56.208 ;
     RECT  0.084 56.208 0.137 56.232 ;
     RECT  0.06 56.232 0.137 56.304 ;
     RECT  0.084 56.304 0.137 56.328 ;
     RECT  0.06 56.328 0.137 56.4 ;
     RECT  0.084 56.4 0.137 56.424 ;
     RECT  0.06 56.424 0.137 56.496 ;
     RECT  0.084 56.496 0.137 56.52 ;
     RECT  0.06 56.52 0.137 56.592 ;
     RECT  0.084 56.592 0.137 56.616 ;
     RECT  0.06 56.616 0.137 56.688 ;
     RECT  0.084 56.688 0.137 56.712 ;
     RECT  0.06 56.712 0.137 56.784 ;
     RECT  0.084 56.784 0.137 56.808 ;
     RECT  0.06 56.808 0.137 56.88 ;
     RECT  0.084 56.88 0.137 56.904 ;
     RECT  0.06 56.904 0.137 56.976 ;
     RECT  0.084 56.976 0.137 57 ;
     RECT  0.06 57 0.137 57.072 ;
     RECT  0.084 57.072 0.137 57.096 ;
     RECT  0.06 57.096 0.137 57.168 ;
     RECT  0.084 57.168 0.137 57.192 ;
     RECT  0.06 57.192 0.137 57.264 ;
     RECT  0.084 57.264 0.137 57.288 ;
     RECT  0.06 57.288 0.137 57.36 ;
     RECT  0.084 57.36 0.137 57.384 ;
     RECT  0.06 57.384 0.137 57.456 ;
     RECT  0.084 57.456 0.137 57.48 ;
     RECT  0.06 57.48 0.137 57.552 ;
     RECT  0.084 57.552 0.137 57.576 ;
     RECT  0.06 57.576 0.137 57.648 ;
     RECT  0.084 57.648 0.137 57.672 ;
     RECT  0.06 57.672 0.137 57.744 ;
     RECT  0.084 57.744 0.137 57.768 ;
     RECT  0.06 57.768 0.137 57.84 ;
     RECT  0.084 57.84 0.137 57.864 ;
     RECT  0.06 57.864 0.137 57.936 ;
     RECT  0.084 57.936 0.137 57.96 ;
     RECT  0.06 57.96 0.137 58.032 ;
     RECT  0.084 58.032 0.137 58.056 ;
     RECT  0.06 58.056 0.137 58.128 ;
     RECT  0.084 58.128 0.137 58.152 ;
     RECT  0.06 58.152 0.137 58.224 ;
     RECT  0.084 58.224 0.137 58.248 ;
     RECT  0.06 58.248 0.137 58.32 ;
     RECT  0.084 58.32 0.137 58.344 ;
     RECT  0.06 58.344 0.137 58.416 ;
     RECT  0.084 58.416 0.137 58.44 ;
     RECT  0.06 58.44 0.137 58.512 ;
     RECT  0.084 58.512 0.137 58.536 ;
     RECT  0.06 58.536 0.137 58.608 ;
     RECT  0.084 58.608 0.137 58.632 ;
     RECT  0.06 58.632 0.137 58.704 ;
     RECT  0.084 58.704 0.137 58.728 ;
     RECT  0.06 58.728 0.137 58.8 ;
     RECT  0.084 58.8 0.137 58.824 ;
     RECT  0.06 58.824 0.137 58.896 ;
     RECT  0.084 58.896 0.137 58.92 ;
     RECT  0.06 58.92 0.137 58.992 ;
     RECT  0.084 58.992 0.137 59.016 ;
     RECT  0.06 59.016 0.137 59.088 ;
     RECT  0.084 59.088 0.137 59.112 ;
     RECT  0.06 59.112 0.137 59.184 ;
     RECT  0.084 59.184 0.137 59.208 ;
     RECT  0.06 59.208 0.137 59.28 ;
     RECT  0.084 59.28 0.137 59.304 ;
     RECT  0.06 59.304 0.137 59.376 ;
     RECT  0.084 59.376 0.137 59.4 ;
     RECT  0.06 59.4 0.137 59.472 ;
     RECT  0.084 59.472 0.137 59.496 ;
     RECT  0.06 59.496 0.137 59.568 ;
     RECT  0.084 59.568 0.137 59.592 ;
     RECT  0.06 59.592 0.137 59.664 ;
     RECT  0.084 59.664 0.137 59.688 ;
     RECT  0.06 59.688 0.137 59.76 ;
     RECT  0.084 59.76 0.137 59.784 ;
     RECT  0.06 59.784 0.137 59.856 ;
     RECT  0.084 59.856 0.137 59.88 ;
     RECT  0.06 59.88 0.137 59.952 ;
     RECT  0.084 59.952 0.137 59.976 ;
     RECT  0.06 59.976 0.137 60.048 ;
     RECT  0.084 60.048 0.137 60.072 ;
     RECT  0.06 60.072 0.137 60.144 ;
     RECT  0.084 60.144 0.137 60.168 ;
     RECT  0.06 60.168 0.137 60.24 ;
     RECT  0.084 60.24 0.137 60.264 ;
     RECT  0.06 60.264 0.137 60.336 ;
     RECT  0.084 60.336 0.137 60.36 ;
     RECT  0.06 60.36 0.137 60.432 ;
     RECT  0.084 60.432 0.137 60.456 ;
     RECT  0.06 60.456 0.137 60.528 ;
     RECT  0.084 60.528 0.137 60.552 ;
     RECT  0.06 60.552 0.137 60.624 ;
     RECT  0.084 60.624 0.137 60.648 ;
     RECT  0.06 60.648 0.137 60.72 ;
     RECT  0.084 60.72 0.137 60.744 ;
     RECT  0.06 60.744 0.137 60.816 ;
     RECT  0.084 60.816 0.137 60.84 ;
     RECT  0.06 60.84 0.137 60.912 ;
     RECT  0.084 60.912 0.137 60.936 ;
     RECT  0.06 60.936 0.137 61.008 ;
     RECT  0.084 61.008 0.137 61.032 ;
     RECT  0.06 61.032 0.137 61.104 ;
     RECT  0.084 61.104 0.137 61.128 ;
     RECT  0.06 61.128 0.137 61.2 ;
     RECT  0.084 61.2 0.137 61.224 ;
     RECT  0.06 61.224 0.137 61.296 ;
     RECT  0.084 61.296 0.137 61.32 ;
     RECT  0.06 61.32 0.137 61.392 ;
     RECT  0.084 61.392 0.137 61.416 ;
     RECT  0.06 61.416 0.137 61.488 ;
     RECT  0.084 61.488 0.137 61.512 ;
     RECT  0.06 61.512 0.137 61.584 ;
     RECT  0.084 61.584 0.137 61.608 ;
     RECT  0.06 61.608 0.137 61.68 ;
     RECT  0.084 61.68 0.137 61.704 ;
     RECT  0.06 61.704 0.137 61.776 ;
     RECT  0.084 61.776 0.137 61.8 ;
     RECT  0.06 61.8 0.137 61.872 ;
     RECT  0.084 61.872 0.137 61.896 ;
     RECT  0.06 61.896 0.137 61.968 ;
     RECT  0.084 61.968 0.137 61.992 ;
     RECT  0.06 61.992 0.137 62.064 ;
     RECT  0.084 62.064 0.137 62.088 ;
     RECT  0.06 62.088 0.137 62.16 ;
     RECT  0.084 62.16 0.137 62.184 ;
     RECT  0.06 62.184 0.137 62.256 ;
     RECT  0.084 62.256 0.137 62.28 ;
     RECT  0.06 62.28 0.137 62.352 ;
     RECT  0.084 62.352 0.137 62.376 ;
     RECT  0.06 62.376 0.137 62.448 ;
     RECT  0.084 62.448 0.137 62.472 ;
     RECT  0.06 62.472 0.137 62.544 ;
     RECT  0.084 62.544 0.137 62.568 ;
     RECT  0.06 62.568 0.137 62.64 ;
     RECT  0.084 62.64 0.137 62.664 ;
     RECT  0.06 62.664 0.137 62.736 ;
     RECT  0.084 62.736 0.137 62.76 ;
     RECT  0.06 62.76 0.137 62.832 ;
     RECT  0.084 62.832 0.137 62.856 ;
     RECT  0.06 62.856 0.137 62.928 ;
     RECT  0.084 62.928 0.137 62.952 ;
     RECT  0.06 62.952 0.137 63.024 ;
     RECT  0.084 63.024 0.137 63.048 ;
     RECT  0.06 63.048 0.137 63.12 ;
     RECT  0.084 63.12 0.137 63.144 ;
     RECT  0.06 63.144 0.137 63.216 ;
     RECT  0.084 63.216 0.137 63.24 ;
     RECT  0.06 63.24 0.137 63.312 ;
     RECT  0.084 63.312 0.137 63.336 ;
     RECT  0.06 63.336 0.137 63.408 ;
     RECT  0.084 63.408 0.137 63.432 ;
     RECT  0.06 63.432 0.137 63.504 ;
     RECT  0.084 63.504 0.137 63.528 ;
     RECT  0.06 63.528 0.137 63.6 ;
     RECT  0.084 63.6 0.137 63.624 ;
     RECT  0.06 63.624 0.137 63.696 ;
     RECT  0.084 63.696 0.137 63.72 ;
     RECT  0.06 63.72 0.137 63.792 ;
     RECT  0.084 63.792 0.137 63.816 ;
     RECT  0.06 63.816 0.137 63.888 ;
     RECT  0.084 63.888 0.137 63.912 ;
     RECT  0.06 63.912 0.137 63.984 ;
     RECT  0.084 63.984 0.137 64.008 ;
     RECT  0.06 64.008 0.137 64.08 ;
     RECT  0.084 64.08 0.137 64.104 ;
     RECT  0.06 64.104 0.137 64.176 ;
     RECT  0.084 64.176 0.137 64.2 ;
     RECT  0.06 64.2 0.137 64.272 ;
     RECT  0.084 64.272 0.137 64.296 ;
     RECT  0.06 64.296 0.137 64.368 ;
     RECT  0.084 64.368 0.137 64.392 ;
     RECT  0.06 64.392 0.137 64.464 ;
     RECT  0.084 64.464 0.137 64.488 ;
     RECT  0.06 64.488 0.137 64.56 ;
     RECT  0.084 64.56 0.137 64.584 ;
     RECT  0.06 64.584 0.137 64.656 ;
     RECT  0.084 64.656 0.137 64.68 ;
     RECT  0.06 64.68 0.137 64.752 ;
     RECT  0.084 64.752 0.137 64.776 ;
     RECT  0.06 64.776 0.137 64.848 ;
     RECT  0.084 64.848 0.137 64.872 ;
     RECT  0.06 64.872 0.137 64.944 ;
     RECT  0.084 64.944 0.137 64.968 ;
     RECT  0.06 64.968 0.137 65.04 ;
     RECT  0.084 65.04 0.137 65.064 ;
     RECT  0.06 65.064 0.137 65.136 ;
     RECT  0.084 65.136 0.137 65.16 ;
     RECT  0.06 65.16 0.137 65.232 ;
     RECT  0.084 65.232 0.137 65.256 ;
     RECT  0.06 65.256 0.137 65.328 ;
     RECT  0.084 65.328 0.137 65.352 ;
     RECT  0.06 65.352 0.137 65.424 ;
     RECT  0.084 65.424 0.137 65.448 ;
     RECT  0.06 65.448 0.137 65.52 ;
     RECT  0.084 65.52 0.137 65.544 ;
     RECT  0.06 65.544 0.137 65.616 ;
     RECT  0.084 65.616 0.137 65.64 ;
     RECT  0.06 65.64 0.137 65.712 ;
     RECT  0.084 65.712 0.137 65.736 ;
     RECT  0.06 65.736 0.137 65.808 ;
     RECT  0.084 65.808 0.137 65.832 ;
     RECT  0.06 65.832 0.137 65.904 ;
     RECT  0.084 65.904 0.137 65.928 ;
     RECT  0.06 65.928 0.137 66 ;
     RECT  0.084 66 0.137 66.024 ;
     RECT  0.06 66.024 0.137 66.096 ;
     RECT  0.084 66.096 0.137 66.12 ;
     RECT  0.06 66.12 0.137 66.192 ;
     RECT  0.084 66.192 0.137 66.216 ;
     RECT  0.06 66.216 0.137 66.288 ;
     RECT  0.084 66.288 0.137 66.312 ;
     RECT  0.06 66.312 0.137 66.384 ;
     RECT  0.084 66.384 0.137 66.408 ;
     RECT  0.06 66.408 0.137 66.48 ;
     RECT  0.084 66.48 0.137 66.504 ;
     RECT  0.06 66.504 0.137 66.576 ;
     RECT  0.084 66.576 0.137 66.6 ;
     RECT  0.06 66.6 0.137 66.672 ;
     RECT  0.084 66.672 0.137 66.696 ;
     RECT  0.06 66.696 0.137 67.536 ;
     RECT  0.084 67.536 0.137 67.56 ;
     RECT  0.06 67.56 0.137 67.632 ;
     RECT  0.084 67.632 0.137 67.656 ;
     RECT  0.06 67.656 0.137 67.728 ;
     RECT  0.084 67.728 0.137 67.752 ;
     RECT  0.06 67.752 0.137 67.824 ;
     RECT  0.084 67.824 0.137 67.848 ;
     RECT  0.06 67.848 0.137 67.92 ;
     RECT  0.084 67.92 0.137 67.944 ;
     RECT  0.06 67.944 0.137 68.016 ;
     RECT  0.084 68.016 0.137 68.04 ;
     RECT  0.06 68.04 0.137 68.112 ;
     RECT  0.084 68.112 0.137 68.136 ;
     RECT  0.06 68.136 0.137 68.208 ;
     RECT  0.084 68.208 0.137 68.232 ;
     RECT  0.06 68.232 0.137 68.304 ;
     RECT  0.084 68.304 0.137 68.328 ;
     RECT  0.06 68.328 0.137 68.4 ;
     RECT  0.084 68.4 0.137 68.424 ;
     RECT  0.06 68.424 0.137 68.496 ;
     RECT  0.084 68.496 0.137 68.52 ;
     RECT  0.06 68.52 0.137 68.592 ;
     RECT  0.084 68.592 0.137 68.616 ;
     RECT  0.06 68.616 0.137 68.688 ;
     RECT  0.084 68.688 0.137 68.712 ;
     RECT  0.06 68.712 0.137 68.784 ;
     RECT  0.084 68.784 0.137 68.808 ;
     RECT  0.06 68.808 0.137 68.88 ;
     RECT  0.084 68.88 0.137 68.904 ;
     RECT  0.06 68.904 0.137 68.976 ;
     RECT  0.084 68.976 0.137 69 ;
     RECT  0.06 69 0.137 69.072 ;
     RECT  0.084 69.072 0.137 69.096 ;
     RECT  0.06 69.096 0.137 69.168 ;
     RECT  0.084 69.168 0.137 69.192 ;
     RECT  0.06 69.192 0.137 69.264 ;
     RECT  0.084 69.264 0.137 69.288 ;
     RECT  0.06 69.288 0.137 69.36 ;
     RECT  0.084 69.36 0.137 69.384 ;
     RECT  0.06 69.384 0.137 69.456 ;
     RECT  0.084 69.456 0.137 69.48 ;
     RECT  0.06 69.48 0.137 69.552 ;
     RECT  0.084 69.552 0.137 69.576 ;
     RECT  0.06 69.576 0.137 69.648 ;
     RECT  0.084 69.648 0.137 69.672 ;
     RECT  0.06 69.672 0.137 69.744 ;
     RECT  0.084 69.744 0.137 69.768 ;
     RECT  0.06 69.768 0.137 69.84 ;
     RECT  0.084 69.84 0.137 69.864 ;
     RECT  0.06 69.864 0.137 69.936 ;
     RECT  0.084 69.936 0.137 69.96 ;
     RECT  0.06 69.96 0.137 70.032 ;
     RECT  0.084 70.032 0.137 70.056 ;
     RECT  0.06 70.056 0.137 70.128 ;
     RECT  0.084 70.128 0.137 70.152 ;
     RECT  0.06 70.152 0.137 70.224 ;
     RECT  0.084 70.224 0.137 70.248 ;
     RECT  0.06 70.248 0.137 70.32 ;
     RECT  0.084 70.32 0.137 70.344 ;
     RECT  0.06 70.344 0.137 70.416 ;
     RECT  0.084 70.416 0.137 70.44 ;
     RECT  0.06 70.44 0.137 70.512 ;
     RECT  0.084 70.512 0.137 70.536 ;
     RECT  0.06 70.536 0.137 70.608 ;
     RECT  0.084 70.608 0.137 70.632 ;
     RECT  0.06 70.632 0.137 70.704 ;
     RECT  0.084 70.704 0.137 70.728 ;
     RECT  0.06 70.728 0.137 70.8 ;
     RECT  0.084 70.8 0.137 70.824 ;
     RECT  0.06 70.824 0.137 70.896 ;
     RECT  0.084 70.896 0.137 70.92 ;
     RECT  0.06 70.92 0.137 70.992 ;
     RECT  0.084 70.992 0.137 71.016 ;
     RECT  0.06 71.016 0.137 71.088 ;
     RECT  0.084 71.088 0.137 71.112 ;
     RECT  0.06 71.112 0.137 71.184 ;
     RECT  0.084 71.184 0.137 71.208 ;
     RECT  0.06 71.208 0.137 71.28 ;
     RECT  0.084 71.28 0.137 71.304 ;
     RECT  0.06 71.304 0.137 71.376 ;
     RECT  0.084 71.376 0.137 71.4 ;
     RECT  0.06 71.4 0.137 71.472 ;
     RECT  0.084 71.472 0.137 71.496 ;
     RECT  0.06 71.496 0.137 71.568 ;
     RECT  0.084 71.568 0.137 71.592 ;
     RECT  0.06 71.592 0.137 71.664 ;
     RECT  0.084 71.664 0.137 71.688 ;
     RECT  0.06 71.688 0.137 71.76 ;
     RECT  0.084 71.76 0.137 71.784 ;
     RECT  0.06 71.784 0.137 71.856 ;
     RECT  0.084 71.856 0.137 71.88 ;
     RECT  0.06 71.88 0.137 71.952 ;
     RECT  0.084 71.952 0.137 71.976 ;
     RECT  0.06 71.976 0.137 72.048 ;
     RECT  0.084 72.048 0.137 72.072 ;
     RECT  0.06 72.072 0.137 72.144 ;
     RECT  0.084 72.144 0.137 72.168 ;
     RECT  0.06 72.168 0.137 72.24 ;
     RECT  0.084 72.24 0.137 72.264 ;
     RECT  0.06 72.264 0.137 72.336 ;
     RECT  0.084 72.336 0.137 72.36 ;
     RECT  0.06 72.36 0.137 72.432 ;
     RECT  0.084 72.432 0.137 72.456 ;
     RECT  0.06 72.456 0.137 72.528 ;
     RECT  0.084 72.528 0.137 72.552 ;
     RECT  0.06 72.552 0.137 72.624 ;
     RECT  0.084 72.624 0.137 72.648 ;
     RECT  0.06 72.648 0.137 72.72 ;
     RECT  0.084 72.72 0.137 72.744 ;
     RECT  0.06 72.744 0.137 72.816 ;
     RECT  0.084 72.816 0.137 72.84 ;
     RECT  0.06 72.84 0.137 72.912 ;
     RECT  0.084 72.912 0.137 72.936 ;
     RECT  0.06 72.936 0.137 73.008 ;
     RECT  0.084 73.008 0.137 73.032 ;
     RECT  0.06 73.032 0.137 73.104 ;
     RECT  0.084 73.104 0.137 73.128 ;
     RECT  0.06 73.128 0.137 73.2 ;
     RECT  0.084 73.2 0.137 73.224 ;
     RECT  0.06 73.224 0.137 73.296 ;
     RECT  0.084 73.296 0.137 73.32 ;
     RECT  0.06 73.32 0.137 73.392 ;
     RECT  0.084 73.392 0.137 73.416 ;
     RECT  0.06 73.416 0.137 73.488 ;
     RECT  0.084 73.488 0.137 73.512 ;
     RECT  0.06 73.512 0.137 73.584 ;
     RECT  0.084 73.584 0.137 73.608 ;
     RECT  0.06 73.608 0.137 73.68 ;
     RECT  0.084 73.68 0.137 73.704 ;
     RECT  0.06 73.704 0.137 73.776 ;
     RECT  0.084 73.776 0.137 73.8 ;
     RECT  0.06 73.8 0.137 73.872 ;
     RECT  0.084 73.872 0.137 73.896 ;
     RECT  0.06 73.896 0.137 73.968 ;
     RECT  0.084 73.968 0.137 73.992 ;
     RECT  0.06 73.992 0.137 74.064 ;
     RECT  0.084 74.064 0.137 74.088 ;
     RECT  0.06 74.088 0.137 74.16 ;
     RECT  0.084 74.16 0.137 74.184 ;
     RECT  0.06 74.184 0.137 74.256 ;
     RECT  0.084 74.256 0.137 74.28 ;
     RECT  0.06 74.28 0.137 74.352 ;
     RECT  0.084 74.352 0.137 74.376 ;
     RECT  0.06 74.376 0.137 74.448 ;
     RECT  0.084 74.448 0.137 74.472 ;
     RECT  0.06 74.472 0.137 74.544 ;
     RECT  0.084 74.544 0.137 74.568 ;
     RECT  0.06 74.568 0.137 74.64 ;
     RECT  0.084 74.64 0.137 74.664 ;
     RECT  0.06 74.664 0.137 74.736 ;
     RECT  0.084 74.736 0.137 74.76 ;
     RECT  0.06 74.76 0.137 74.832 ;
     RECT  0.084 74.832 0.137 74.856 ;
     RECT  0.06 74.856 0.137 74.928 ;
     RECT  0.084 74.928 0.137 74.952 ;
     RECT  0.06 74.952 0.137 75.024 ;
     RECT  0.084 75.024 0.137 75.048 ;
     RECT  0.06 75.048 0.137 75.12 ;
     RECT  0.084 75.12 0.137 75.144 ;
     RECT  0.06 75.144 0.137 75.216 ;
     RECT  0.084 75.216 0.137 75.24 ;
     RECT  0.06 75.24 0.137 75.312 ;
     RECT  0.084 75.312 0.137 75.336 ;
     RECT  0.06 75.336 0.137 75.408 ;
     RECT  0.084 75.408 0.137 75.432 ;
     RECT  0.06 75.432 0.137 75.504 ;
     RECT  0.084 75.504 0.137 75.528 ;
     RECT  0.06 75.528 0.137 75.6 ;
     RECT  0.084 75.6 0.137 75.624 ;
     RECT  0.06 75.624 0.137 75.696 ;
     RECT  0.084 75.696 0.137 75.72 ;
     RECT  0.06 75.72 0.137 75.792 ;
     RECT  0.084 75.792 0.137 75.816 ;
     RECT  0.06 75.816 0.137 75.888 ;
     RECT  0.084 75.888 0.137 75.912 ;
     RECT  0.06 75.912 0.137 75.984 ;
     RECT  0.084 75.984 0.137 76.008 ;
     RECT  0.06 76.008 0.137 76.08 ;
     RECT  0.084 76.08 0.137 76.104 ;
     RECT  0.06 76.104 0.137 76.176 ;
     RECT  0.084 76.176 0.137 76.2 ;
     RECT  0.06 76.2 0.137 76.272 ;
     RECT  0.084 76.272 0.137 76.296 ;
     RECT  0.06 76.296 0.137 76.368 ;
     RECT  0.084 76.368 0.137 76.392 ;
     RECT  0.06 76.392 0.137 76.464 ;
     RECT  0.084 76.464 0.137 76.488 ;
     RECT  0.06 76.488 0.137 76.56 ;
     RECT  0.084 76.56 0.137 76.584 ;
     RECT  0.06 76.584 0.137 76.656 ;
     RECT  0.084 76.656 0.137 76.68 ;
     RECT  0.06 76.68 0.137 76.752 ;
     RECT  0.084 76.752 0.137 76.776 ;
     RECT  0.06 76.776 0.137 76.848 ;
     RECT  0.084 76.848 0.137 76.872 ;
     RECT  0.06 76.872 0.137 76.944 ;
     RECT  0.084 76.944 0.137 76.968 ;
     RECT  0.06 76.968 0.137 77.04 ;
     RECT  0.084 77.04 0.137 77.064 ;
     RECT  0.06 77.064 0.137 77.136 ;
     RECT  0.084 77.136 0.137 77.16 ;
     RECT  0.06 77.16 0.137 77.232 ;
     RECT  0.084 77.232 0.137 77.256 ;
     RECT  0.06 77.256 0.137 77.328 ;
     RECT  0.084 77.328 0.137 77.352 ;
     RECT  0.06 77.352 0.137 77.424 ;
     RECT  0.084 77.424 0.137 77.448 ;
     RECT  0.06 77.448 0.137 77.52 ;
     RECT  0.084 77.52 0.137 77.544 ;
     RECT  0.06 77.544 0.137 77.616 ;
     RECT  0.084 77.616 0.137 77.64 ;
     RECT  0.06 77.64 0.137 77.712 ;
     RECT  0.084 77.712 0.137 77.736 ;
     RECT  0.06 77.736 0.137 77.808 ;
     RECT  0.084 77.808 0.137 77.832 ;
     RECT  0.06 77.832 0.137 77.904 ;
     RECT  0.084 77.904 0.137 77.928 ;
     RECT  0.06 77.928 0.137 78 ;
     RECT  0.084 78 0.137 78.024 ;
     RECT  0.06 78.024 0.137 78.096 ;
     RECT  0.084 78.096 0.137 78.12 ;
     RECT  0.06 78.12 0.137 78.192 ;
     RECT  0.084 78.192 0.137 78.216 ;
     RECT  0.06 78.216 0.137 78.288 ;
     RECT  0.084 78.288 0.137 78.312 ;
     RECT  0.06 78.312 0.137 78.384 ;
     RECT  0.084 78.384 0.137 78.408 ;
     RECT  0.06 78.408 0.137 78.48 ;
     RECT  0.084 78.48 0.137 78.504 ;
     RECT  0.06 78.504 0.137 78.576 ;
     RECT  0.084 78.576 0.137 78.6 ;
     RECT  0.06 78.6 0.137 78.672 ;
     RECT  0.084 78.672 0.137 78.696 ;
     RECT  0.06 78.696 0.137 78.768 ;
     RECT  0.084 78.768 0.137 78.792 ;
     RECT  0.06 78.792 0.137 78.864 ;
     RECT  0.084 78.864 0.137 78.888 ;
     RECT  0.06 78.888 0.137 78.96 ;
     RECT  0.084 78.96 0.137 78.984 ;
     RECT  0.06 78.984 0.137 79.056 ;
     RECT  0.084 79.056 0.137 79.08 ;
     RECT  0.06 79.08 0.137 79.152 ;
     RECT  0.084 79.152 0.137 79.176 ;
     RECT  0.06 79.176 0.137 79.248 ;
     RECT  0.084 79.248 0.137 79.272 ;
     RECT  0.06 79.272 0.137 79.344 ;
     RECT  0.084 79.344 0.137 79.368 ;
     RECT  0.06 79.368 0.137 79.44 ;
     RECT  0.084 79.44 0.137 79.464 ;
     RECT  0.06 79.464 0.137 79.536 ;
     RECT  0.084 79.536 0.137 79.56 ;
     RECT  0.06 79.56 0.137 79.632 ;
     RECT  0.084 79.632 0.137 79.656 ;
     RECT  0.06 79.656 0.137 79.728 ;
     RECT  0.084 79.728 0.137 79.752 ;
     RECT  0.06 79.752 0.137 79.824 ;
     RECT  0.084 79.824 0.137 79.848 ;
     RECT  0.06 79.848 0.137 79.92 ;
     RECT  0.084 79.92 0.137 79.944 ;
     RECT  0.06 79.944 0.137 80.016 ;
     RECT  0.084 80.016 0.137 80.04 ;
     RECT  0.06 80.04 0.137 80.112 ;
     RECT  0.084 80.112 0.137 80.136 ;
     RECT  0.06 80.136 0.137 80.208 ;
     RECT  0.084 80.208 0.137 80.232 ;
     RECT  0.06 80.232 0.137 80.304 ;
     RECT  0.084 80.304 0.137 80.328 ;
     RECT  0.06 80.328 0.137 80.4 ;
     RECT  0.084 80.4 0.137 80.424 ;
     RECT  0.06 80.424 0.137 80.496 ;
     RECT  0.084 80.496 0.137 80.52 ;
     RECT  0.06 80.52 0.137 80.592 ;
     RECT  0.084 80.592 0.137 80.616 ;
     RECT  0.06 80.616 0.137 80.688 ;
     RECT  0.084 80.688 0.137 80.712 ;
     RECT  0.06 80.712 0.137 80.784 ;
     RECT  0.084 80.784 0.137 80.808 ;
     RECT  0.06 80.808 0.137 80.88 ;
     RECT  0.084 80.88 0.137 80.904 ;
     RECT  0.06 80.904 0.137 80.976 ;
     RECT  0.084 80.976 0.137 81 ;
     RECT  0.06 81 0.137 81.072 ;
     RECT  0.084 81.072 0.137 81.096 ;
     RECT  0.06 81.096 0.137 81.168 ;
     RECT  0.084 81.168 0.137 81.192 ;
     RECT  0.06 81.192 0.137 81.264 ;
     RECT  0.084 81.264 0.137 81.288 ;
     RECT  0.06 81.288 0.137 81.36 ;
     RECT  0.084 81.36 0.137 81.384 ;
     RECT  0.06 81.384 0.137 81.456 ;
     RECT  0.084 81.456 0.137 81.48 ;
     RECT  0.06 81.48 0.137 81.552 ;
     RECT  0.084 81.552 0.137 81.576 ;
     RECT  0.06 81.576 0.137 81.648 ;
     RECT  0.084 81.648 0.137 81.672 ;
     RECT  0.06 81.672 0.137 81.744 ;
     RECT  0.084 81.744 0.137 81.768 ;
     RECT  0.06 81.768 0.137 81.84 ;
     RECT  0.084 81.84 0.137 81.864 ;
     RECT  0.06 81.864 0.137 81.936 ;
     RECT  0.084 81.936 0.137 81.96 ;
     RECT  0.06 81.96 0.137 82.032 ;
     RECT  0.084 82.032 0.137 82.056 ;
     RECT  0.06 82.056 0.137 82.128 ;
     RECT  0.084 82.128 0.137 82.152 ;
     RECT  0.06 82.152 0.137 82.224 ;
     RECT  0.084 82.224 0.137 82.248 ;
     RECT  0.06 82.248 0.137 82.32 ;
     RECT  0.084 82.32 0.137 82.344 ;
     RECT  0.06 82.344 0.137 82.416 ;
     RECT  0.084 82.416 0.137 82.44 ;
     RECT  0.06 82.44 0.137 82.512 ;
     RECT  0.084 82.512 0.137 82.536 ;
     RECT  0.06 82.536 0.137 82.608 ;
     RECT  0.084 82.608 0.137 82.632 ;
     RECT  0.06 82.632 0.137 82.704 ;
     RECT  0.084 82.704 0.137 82.728 ;
     RECT  0.06 82.728 0.137 82.8 ;
     RECT  0.084 82.8 0.137 82.824 ;
     RECT  0.06 82.824 0.137 82.896 ;
     RECT  0.084 82.896 0.137 82.92 ;
     RECT  0.06 82.92 0.137 82.992 ;
     RECT  0.084 82.992 0.137 83.016 ;
     RECT  0.06 83.016 0.137 83.088 ;
     RECT  0.084 83.088 0.137 83.112 ;
     RECT  0.06 83.112 0.137 83.184 ;
     RECT  0.084 83.184 0.137 83.208 ;
     RECT  0.06 83.208 0.137 83.28 ;
     RECT  0.084 83.28 0.137 83.304 ;
     RECT  0.06 83.304 0.137 83.376 ;
     RECT  0.084 83.376 0.137 83.4 ;
     RECT  0.06 83.4 0.137 83.472 ;
     RECT  0.084 83.472 0.137 83.496 ;
     RECT  0.06 83.496 0.137 83.568 ;
     RECT  0.084 83.568 0.137 83.592 ;
     RECT  0.06 83.592 0.137 83.664 ;
     RECT  0.084 83.664 0.137 83.688 ;
     RECT  0.06 83.688 0.137 83.76 ;
     RECT  0.084 83.76 0.137 83.784 ;
     RECT  0.06 83.784 0.137 83.856 ;
     RECT  0.084 83.856 0.137 83.88 ;
     RECT  0.06 83.88 0.137 83.952 ;
     RECT  0.084 83.952 0.137 83.976 ;
     RECT  0.06 83.976 0.137 84.048 ;
     RECT  0.084 84.048 0.137 84.072 ;
     RECT  0.06 84.072 0.137 84.144 ;
     RECT  0.084 84.144 0.137 84.168 ;
     RECT  0.06 84.168 0.137 84.24 ;
     RECT  0.084 84.24 0.137 84.264 ;
     RECT  0.06 84.264 0.137 84.336 ;
     RECT  0.084 84.336 0.137 84.36 ;
     RECT  0.06 84.36 0.137 84.432 ;
     RECT  0.084 84.432 0.137 84.456 ;
     RECT  0.06 84.456 0.137 84.528 ;
     RECT  0.084 84.528 0.137 84.552 ;
     RECT  0.06 84.552 0.137 84.624 ;
     RECT  0.084 84.624 0.137 84.648 ;
     RECT  0.06 84.648 0.137 84.72 ;
     RECT  0.084 84.72 0.137 84.744 ;
     RECT  0.06 84.744 0.137 84.816 ;
     RECT  0.084 84.816 0.137 84.84 ;
     RECT  0.06 84.84 0.137 84.912 ;
     RECT  0.084 84.912 0.137 84.936 ;
     RECT  0.06 84.936 0.137 85.008 ;
     RECT  0.084 85.008 0.137 85.032 ;
     RECT  0.06 85.032 0.137 85.104 ;
     RECT  0.084 85.104 0.137 85.128 ;
     RECT  0.06 85.128 0.137 85.2 ;
     RECT  0.084 85.2 0.137 85.224 ;
     RECT  0.06 85.224 0.137 85.296 ;
     RECT  0.084 85.296 0.137 85.32 ;
     RECT  0.06 85.32 0.137 85.392 ;
     RECT  0.084 85.392 0.137 85.416 ;
     RECT  0.06 85.416 0.137 85.488 ;
     RECT  0.084 85.488 0.137 85.512 ;
     RECT  0.06 85.512 0.137 85.584 ;
     RECT  0.084 85.584 0.137 85.608 ;
     RECT  0.06 85.608 0.137 85.68 ;
     RECT  0.084 85.68 0.137 85.704 ;
     RECT  0.06 85.704 0.137 85.776 ;
     RECT  0.084 85.776 0.137 85.8 ;
     RECT  0.06 85.8 0.137 85.872 ;
     RECT  0.084 85.872 0.137 85.896 ;
     RECT  0.137 25.968 0.353 85.8 ;
     RECT  0.353 26.064 2.408 85.8 ;
     RECT  2.408 2.148 2.512 103.152 ;
     RECT  2.512 2.418 2.6 103.152 ;
     RECT  2.6 2.418 2.704 103.422 ;
     RECT  2.704 26.064 3.413 85.512 ;
     RECT  3.413 26.112 3.449 85.512 ;
     RECT  3.449 79.824 3.485 85.512 ;
     RECT  3.449 26.112 3.593 78.792 ;
     RECT  2.704 23.088 5.108 23.112 ;
     RECT  3.593 26.112 5.108 77.448 ;
     RECT  3.593 78.768 5.108 78.792 ;
     RECT  3.485 79.824 5.108 83.592 ;
     RECT  3.485 84.72 5.108 85.512 ;
     RECT  5.108 2.148 5.212 103.152 ;
     RECT  5.212 2.418 5.3 103.152 ;
     RECT  5.3 2.418 5.404 103.422 ;
     RECT  5.404 22.992 5.501 23.112 ;
     RECT  5.404 84.72 6.829 84.744 ;
     RECT  5.501 22.992 7.808 23.016 ;
     RECT  5.404 26.112 7.808 77.448 ;
     RECT  5.404 79.824 7.808 83.544 ;
     RECT  6.829 84.624 7.808 84.744 ;
     RECT  7.808 2.148 7.912 103.152 ;
     RECT  7.912 2.418 8 103.152 ;
     RECT  8 2.418 8.104 103.422 ;
     RECT  8.104 22.992 10.508 23.016 ;
     RECT  8.104 26.112 10.508 77.448 ;
     RECT  8.104 79.824 10.508 83.544 ;
     RECT  8.104 84.624 10.508 84.648 ;
     RECT  10.508 2.148 10.612 103.152 ;
     RECT  10.612 2.418 10.7 103.152 ;
     RECT  10.7 2.418 10.804 103.422 ;
     RECT  10.804 22.992 13.208 23.016 ;
     RECT  10.804 26.112 13.208 77.448 ;
     RECT  10.804 79.824 13.208 83.544 ;
     RECT  10.804 84.72 13.208 84.744 ;
     RECT  13.208 2.148 13.312 103.152 ;
     RECT  13.312 2.418 13.4 103.152 ;
     RECT  13.4 2.418 13.504 103.422 ;
     RECT  13.504 26.112 14.249 77.352 ;
     RECT  14.249 26.112 14.609 76.536 ;
     RECT  13.504 22.992 14.821 23.016 ;
     RECT  13.504 84.72 14.821 84.744 ;
     RECT  14.821 22.992 14.861 23.112 ;
     RECT  14.821 84.624 14.861 84.744 ;
     RECT  14.861 23.088 15.908 23.112 ;
     RECT  14.609 26.112 15.908 35.256 ;
     RECT  14.609 36.288 15.908 76.536 ;
     RECT  13.504 79.824 15.908 83.064 ;
     RECT  14.861 84.624 15.908 84.648 ;
     RECT  15.908 2.148 16.012 103.152 ;
     RECT  16.012 2.418 16.1 103.152 ;
     RECT  16.1 2.418 16.204 103.422 ;
     RECT  16.204 79.824 17.453 83.064 ;
     RECT  16.204 23.088 18.608 23.112 ;
     RECT  16.204 26.112 18.608 35.256 ;
     RECT  16.204 36.288 18.608 76.536 ;
     RECT  17.453 80.016 18.608 83.064 ;
     RECT  16.204 84.624 18.608 84.648 ;
     RECT  18.608 2.148 18.712 103.152 ;
     RECT  18.712 2.418 18.8 103.152 ;
     RECT  18.8 2.418 18.904 103.422 ;
     RECT  18.904 36.288 19.721 76.536 ;
     RECT  18.904 84.624 19.937 84.648 ;
     RECT  18.904 23.088 21.308 23.112 ;
     RECT  18.904 26.112 21.308 35.208 ;
     RECT  19.721 36.288 21.308 75.72 ;
     RECT  18.904 79.824 21.308 83.064 ;
     RECT  21.308 2.148 21.412 103.152 ;
     RECT  21.412 2.418 21.5 103.152 ;
     RECT  21.5 2.418 21.604 103.422 ;
     RECT  21.604 22.992 21.701 23.112 ;
     RECT  21.604 36.288 21.701 75.72 ;
     RECT  21.701 36.384 21.953 75.72 ;
     RECT  21.604 79.824 22.025 83.064 ;
     RECT  21.701 22.992 22.813 23.016 ;
     RECT  21.953 36.384 22.813 75.24 ;
     RECT  22.813 22.992 22.853 23.112 ;
     RECT  21.604 26.112 23.893 35.208 ;
     RECT  22.853 23.088 24.008 23.112 ;
     RECT  23.893 26.112 24.008 35.256 ;
     RECT  22.813 36.288 24.008 75.24 ;
     RECT  22.025 80.016 24.008 83.064 ;
     RECT  24.008 2.148 24.112 103.152 ;
     RECT  24.112 2.418 24.2 103.152 ;
     RECT  24.2 2.418 24.304 103.422 ;
     RECT  24.304 36.288 24.977 74.376 ;
     RECT  24.304 80.016 25.373 83.064 ;
     RECT  25.373 80.304 25.409 83.064 ;
     RECT  24.304 23.088 26.708 23.112 ;
     RECT  24.304 26.112 26.708 35.256 ;
     RECT  24.977 36.288 26.708 47.448 ;
     RECT  24.977 48.432 26.708 74.376 ;
     RECT  25.409 80.304 26.708 80.808 ;
     RECT  25.409 82.512 26.708 83.064 ;
     RECT  26.708 2.148 26.812 103.152 ;
     RECT  26.812 2.418 26.9 103.152 ;
     RECT  26.9 2.418 27.004 103.422 ;
     RECT  27.004 48.432 27.353 74.184 ;
     RECT  27.004 82.512 27.677 82.536 ;
     RECT  27.004 26.112 28.217 35.256 ;
     RECT  27.004 36.288 28.289 47.448 ;
     RECT  28.289 36.576 28.501 47.448 ;
     RECT  27.353 48.432 28.501 66.6 ;
     RECT  27.004 23.088 29.408 23.112 ;
     RECT  28.217 26.112 29.408 32.28 ;
     RECT  28.217 33.648 29.408 35.256 ;
     RECT  28.501 36.576 29.408 66.6 ;
     RECT  27.353 67.68 29.408 74.184 ;
     RECT  29.408 2.148 29.512 103.152 ;
     RECT  29.512 2.418 29.6 103.152 ;
     RECT  29.6 2.418 29.704 103.422 ;
     RECT  29.704 67.68 29.765 74.184 ;
     RECT  29.704 22.992 29.801 23.112 ;
     RECT  29.765 67.824 29.945 74.184 ;
     RECT  29.801 22.992 30.769 23.016 ;
     RECT  29.704 33.648 30.773 66.648 ;
     RECT  30.769 22.992 30.809 23.112 ;
     RECT  30.773 33.648 31.777 35.256 ;
     RECT  30.773 36.576 31.777 66.648 ;
     RECT  30.809 23.088 32.108 23.112 ;
     RECT  29.704 26.112 32.108 32.28 ;
     RECT  31.777 33.648 32.108 66.648 ;
     RECT  29.945 67.824 32.108 73.608 ;
     RECT  32.108 2.148 32.212 103.152 ;
     RECT  32.212 2.418 32.3 103.152 ;
     RECT  32.3 2.418 32.404 103.422 ;
     RECT  32.404 72.432 32.537 73.608 ;
     RECT  32.404 33.648 32.609 71.448 ;
     RECT  32.609 33.648 32.645 34.776 ;
     RECT  32.609 35.952 32.681 71.448 ;
     RECT  32.645 33.648 33.005 34.728 ;
     RECT  32.681 35.952 33.077 61.752 ;
     RECT  32.681 62.736 33.077 71.448 ;
     RECT  33.077 35.952 33.113 55.56 ;
     RECT  33.077 62.736 33.113 64.728 ;
     RECT  33.077 56.544 33.185 61.752 ;
     RECT  33.077 66.288 33.221 71.448 ;
     RECT  32.404 26.112 33.251 31.752 ;
     RECT  33.221 67.056 33.329 71.448 ;
     RECT  32.404 102.624 33.373 102.648 ;
     RECT  33.251 26.112 33.437 29.832 ;
     RECT  33.113 35.952 33.473 54.888 ;
     RECT  33.185 56.544 33.509 60.84 ;
     RECT  33.113 62.784 33.581 64.728 ;
     RECT  33.329 67.056 33.617 69.24 ;
     RECT  33.005 34.416 33.653 34.728 ;
     RECT  33.329 70.512 33.653 71.448 ;
     RECT  33.617 67.056 33.725 67.416 ;
     RECT  33.653 71.424 33.797 71.448 ;
     RECT  33.721 103.152 33.805 103.176 ;
     RECT  33.653 34.704 33.901 34.728 ;
     RECT  33.473 35.952 33.901 51.48 ;
     RECT  33.509 57.84 34.621 60.84 ;
     RECT  33.509 56.544 34.765 56.616 ;
     RECT  33.581 62.784 34.765 63.096 ;
     RECT  33.581 64.368 34.765 64.728 ;
     RECT  32.404 23.088 34.808 23.112 ;
     RECT  33.437 26.112 34.808 28.824 ;
     RECT  33.437 29.808 34.808 29.832 ;
     RECT  33.251 30.96 34.808 31.752 ;
     RECT  33.901 34.704 34.808 51.48 ;
     RECT  33.473 52.464 34.808 54.888 ;
     RECT  34.765 56.064 34.808 56.616 ;
     RECT  34.621 57.6 34.808 60.84 ;
     RECT  34.765 62.784 34.808 64.728 ;
     RECT  33.725 67.392 34.808 67.416 ;
     RECT  33.617 68.496 34.808 69.24 ;
     RECT  32.537 72.816 34.808 73.608 ;
     RECT  34.808 2.148 34.912 103.152 ;
     RECT  34.912 2.418 35 103.152 ;
     RECT  35 2.418 35.104 103.422 ;
     RECT  35.104 27.408 35.201 28.824 ;
     RECT  35.104 46.8 35.201 53.544 ;
     RECT  35.201 46.848 35.219 53.544 ;
     RECT  35.104 62.736 35.219 62.76 ;
     RECT  35.104 40.512 35.237 45.528 ;
     RECT  35.104 57.072 35.237 57.096 ;
     RECT  35.104 63.888 35.267 63.912 ;
     RECT  35.237 40.512 35.309 41.928 ;
     RECT  35.104 60 35.381 60.84 ;
     RECT  35.219 46.848 35.453 53.496 ;
     RECT  35.237 43.008 35.561 45.528 ;
     RECT  35.561 44.064 35.597 45.528 ;
     RECT  35.453 46.848 35.597 51.48 ;
     RECT  35.453 53.04 35.777 53.496 ;
     RECT  35.104 56.064 35.993 56.088 ;
     RECT  35.777 53.376 36.029 53.496 ;
     RECT  36.029 53.472 36.065 53.496 ;
     RECT  35.104 36.048 36.209 38.76 ;
     RECT  35.597 46.848 36.209 50.616 ;
     RECT  35.309 41.184 36.385 41.928 ;
     RECT  35.561 43.008 36.385 43.032 ;
     RECT  36.385 41.184 36.533 43.032 ;
     RECT  36.637 51.744 36.709 51.768 ;
     RECT  36.533 41.184 36.781 41.784 ;
     RECT  36.781 40.944 36.889 41.784 ;
     RECT  35.104 23.088 37.508 23.112 ;
     RECT  35.201 27.888 37.508 28.824 ;
     RECT  35.104 30.96 37.508 30.984 ;
     RECT  36.209 36.048 37.508 36.936 ;
     RECT  36.209 37.92 37.508 38.76 ;
     RECT  36.889 40.848 37.508 41.784 ;
     RECT  36.533 43.008 37.508 43.032 ;
     RECT  35.597 44.352 37.508 45.528 ;
     RECT  36.209 46.848 37.508 50.328 ;
     RECT  36.709 51.648 37.508 51.768 ;
     RECT  35.104 58.512 37.508 58.536 ;
     RECT  35.381 60.816 37.508 60.84 ;
     RECT  35.104 72.816 37.508 72.84 ;
     RECT  37.508 2.148 37.612 103.152 ;
     RECT  37.612 2.418 37.7 103.152 ;
     RECT  37.7 2.418 37.804 103.422 ;
     RECT  37.804 58.512 37.865 58.536 ;
     RECT  37.804 60.816 38.513 60.84 ;
     RECT  37.804 40.032 38.765 40.056 ;
     RECT  37.804 43.008 38.765 45.528 ;
     RECT  37.804 22.992 38.801 23.112 ;
     RECT  37.804 35.952 38.801 36.936 ;
     RECT  37.804 41.088 38.801 41.736 ;
     RECT  37.804 46.752 38.801 50.328 ;
     RECT  38.801 23.088 40.208 23.112 ;
     RECT  37.804 27.888 40.208 28.824 ;
     RECT  38.801 36.048 40.208 36.936 ;
     RECT  37.804 37.92 40.208 38.76 ;
     RECT  38.801 41.184 40.208 41.736 ;
     RECT  38.765 43.008 40.208 43.032 ;
     RECT  38.765 44.352 40.208 45.528 ;
     RECT  38.801 46.848 40.208 50.328 ;
     RECT  38.869 56.592 40.208 56.616 ;
     RECT  37.804 72.816 40.208 72.84 ;
     RECT  40.208 2.148 40.312 103.152 ;
     RECT  40.312 2.418 40.4 103.152 ;
     RECT  40.4 2.418 40.504 103.422 ;
     RECT  40.504 44.352 40.781 44.376 ;
     RECT  40.504 43.008 42.757 43.032 ;
     RECT  40.504 23.088 42.908 23.112 ;
     RECT  40.504 27.888 42.908 28.824 ;
     RECT  40.504 36.048 42.908 36.936 ;
     RECT  40.504 37.92 42.908 38.76 ;
     RECT  40.504 41.184 42.908 41.736 ;
     RECT  42.757 43.008 42.908 43.656 ;
     RECT  40.504 45.504 42.908 45.528 ;
     RECT  40.504 46.848 42.908 50.328 ;
     RECT  40.504 72.816 42.908 72.84 ;
     RECT  42.908 2.148 43.012 103.152 ;
     RECT  43.012 2.418 43.1 103.152 ;
     RECT  43.1 2.418 43.204 103.422 ;
     RECT  43.204 43.008 43.841 43.656 ;
     RECT  43.204 72.816 44.732 72.84 ;
     RECT  44.732 72.576 44.773 72.84 ;
     RECT  43.204 23.088 45.608 23.112 ;
     RECT  43.204 27.888 45.608 28.824 ;
     RECT  43.204 36.048 45.608 36.936 ;
     RECT  43.204 37.92 45.608 38.76 ;
     RECT  43.204 41.184 45.608 41.736 ;
     RECT  43.841 43.008 45.608 43.032 ;
     RECT  43.204 46.848 45.608 50.328 ;
     RECT  44.773 72.576 45.608 73.272 ;
     RECT  45.608 2.148 45.712 103.152 ;
     RECT  45.712 2.418 45.8 103.152 ;
     RECT  45.8 2.418 45.904 103.422 ;
     RECT  45.904 35.952 46.073 37.08 ;
     RECT  45.904 43.008 46.757 43.8 ;
     RECT  45.904 22.992 46.793 23.112 ;
     RECT  46.073 35.952 46.793 36.936 ;
     RECT  45.904 41.088 46.793 41.736 ;
     RECT  45.904 46.752 46.793 50.328 ;
     RECT  46.793 23.088 48.308 23.112 ;
     RECT  45.904 27.888 48.308 28.824 ;
     RECT  46.793 36.048 48.308 36.936 ;
     RECT  45.904 38.448 48.308 38.76 ;
     RECT  46.793 41.184 48.308 41.736 ;
     RECT  46.757 43.008 48.308 43.032 ;
     RECT  46.793 46.848 48.308 50.328 ;
     RECT  45.904 72.816 48.308 73.272 ;
     RECT  48.308 2.148 48.412 103.152 ;
     RECT  48.412 2.418 48.5 103.152 ;
     RECT  48.5 2.418 48.604 103.422 ;
     RECT  48.604 23.088 51.008 23.112 ;
     RECT  48.604 27.888 51.008 28.824 ;
     RECT  48.604 36.048 51.008 36.936 ;
     RECT  48.604 38.448 51.008 38.76 ;
     RECT  48.604 41.184 51.008 41.736 ;
     RECT  48.604 43.008 51.008 43.032 ;
     RECT  50.137 44.16 51.008 44.184 ;
     RECT  48.604 46.848 51.008 50.328 ;
     RECT  50.713 52.512 51.008 52.536 ;
     RECT  48.604 72.816 51.008 73.272 ;
     RECT  51.008 2.148 51.112 103.152 ;
     RECT  51.112 2.418 51.2 103.152 ;
     RECT  51.2 2.418 51.304 103.422 ;
     RECT  51.304 46.848 52.481 50.328 ;
     RECT  51.304 23.088 53.708 23.112 ;
     RECT  51.304 27.888 53.708 28.824 ;
     RECT  51.304 36.048 53.708 36.936 ;
     RECT  51.304 38.448 53.708 38.76 ;
     RECT  51.304 41.712 53.708 41.736 ;
     RECT  51.304 43.008 53.708 43.032 ;
     RECT  51.304 44.16 53.708 44.184 ;
     RECT  52.481 46.848 53.708 49.848 ;
     RECT  53.017 51.744 53.708 51.768 ;
     RECT  53.053 59.856 53.708 59.88 ;
     RECT  51.304 72.816 53.708 73.272 ;
     RECT  53.708 2.148 53.812 103.152 ;
     RECT  53.812 2.418 53.9 103.152 ;
     RECT  53.9 2.418 54.004 103.422 ;
     RECT  54.004 27.696 54.749 28.824 ;
     RECT  54.004 41.616 54.749 43.032 ;
     RECT  54.749 41.664 55.033 43.032 ;
     RECT  54.004 44.16 55.033 44.184 ;
     RECT  54.004 35.952 55.141 36.936 ;
     RECT  54.004 62.784 55.177 62.808 ;
     RECT  54.004 64.128 55.177 64.776 ;
     RECT  55.033 66.336 55.177 66.36 ;
     RECT  54.004 67.584 55.177 67.608 ;
     RECT  54.004 52.128 55.213 52.152 ;
     RECT  55.177 66.336 55.213 67.608 ;
     RECT  54.004 38.448 55.285 39.048 ;
     RECT  55.177 40.464 55.285 40.488 ;
     RECT  55.177 54.864 55.285 54.888 ;
     RECT  54.004 56.064 55.285 56.808 ;
     RECT  54.004 70.752 55.285 70.776 ;
     RECT  55.141 34.8 55.321 36.936 ;
     RECT  55.213 52.128 55.321 52.2 ;
     RECT  55.177 62.112 55.397 64.776 ;
     RECT  54.004 72.816 55.397 73.272 ;
     RECT  55.285 38.448 55.429 40.488 ;
     RECT  54.004 46.848 55.429 50.28 ;
     RECT  55.321 52.08 55.429 52.2 ;
     RECT  55.397 62.784 55.433 64.776 ;
     RECT  55.213 66.24 55.433 67.608 ;
     RECT  54.004 22.848 55.501 23.16 ;
     RECT  55.321 34.8 55.501 37.08 ;
     RECT  55.429 46.752 55.501 50.28 ;
     RECT  55.429 51.888 55.501 52.728 ;
     RECT  55.285 54.864 55.537 56.808 ;
     RECT  55.213 58.944 55.537 58.968 ;
     RECT  55.501 46.752 55.573 52.728 ;
     RECT  55.537 54.864 55.573 57.096 ;
     RECT  55.213 60 55.573 60.024 ;
     RECT  55.532 61.296 55.573 61.368 ;
     RECT  55.285 70.608 55.573 70.776 ;
     RECT  55.573 54.816 55.609 57.096 ;
     RECT  55.537 58.944 55.609 59.016 ;
     RECT  54.749 28.8 55.645 28.824 ;
     RECT  55.429 29.904 55.645 29.928 ;
     RECT  55.501 34.8 55.676 37.416 ;
     RECT  55.676 34.8 55.717 37.464 ;
     RECT  55.429 38.448 55.717 40.584 ;
     RECT  55.609 54.816 55.772 59.016 ;
     RECT  55.573 70.512 55.789 70.776 ;
     RECT  55.645 28.8 55.825 29.928 ;
     RECT  55.573 46.752 55.825 53.256 ;
     RECT  55.772 54.624 55.825 59.016 ;
     RECT  55.397 73.248 55.825 73.272 ;
     RECT  55.789 70.512 55.861 70.824 ;
     RECT  55.501 22.848 55.868 23.304 ;
     RECT  55.141 25.056 55.868 25.08 ;
     RECT  55.033 41.664 55.957 44.184 ;
     RECT  55.537 77.568 56.113 77.592 ;
     RECT  55.645 21.648 56.149 21.672 ;
     RECT  55.957 41.664 56.185 44.904 ;
     RECT  56.149 21.648 56.293 21.72 ;
     RECT  55.868 22.848 56.293 25.08 ;
     RECT  55.429 26.208 56.293 26.232 ;
     RECT  54.749 27.696 56.293 27.72 ;
     RECT  56.185 41.664 56.329 45.576 ;
     RECT  55.825 46.752 56.329 59.016 ;
     RECT  55.573 60 56.329 61.368 ;
     RECT  56.293 26.208 56.365 26.28 ;
     RECT  56.293 27.6 56.365 27.72 ;
     RECT  55.969 32.208 56.365 32.232 ;
     RECT  56.113 77.568 56.401 77.64 ;
     RECT  56.293 20.976 56.408 25.08 ;
     RECT  56.365 26.208 56.408 27.72 ;
     RECT  55.825 28.8 56.408 30.696 ;
     RECT  56.365 31.92 56.408 32.232 ;
     RECT  55.717 34.8 56.408 40.584 ;
     RECT  56.329 41.664 56.408 61.368 ;
     RECT  55.433 62.784 56.408 64.584 ;
     RECT  55.433 66.336 56.408 67.608 ;
     RECT  55.861 70.08 56.408 70.824 ;
     RECT  55.825 73.248 56.408 74.088 ;
     RECT  56.401 77.568 56.408 78.12 ;
     RECT  56.408 2.148 56.512 103.152 ;
     RECT  56.512 2.418 56.6 103.152 ;
     RECT  56.6 2.418 56.704 103.422 ;
     RECT  56.704 66.336 56.729 68.136 ;
     RECT  56.704 77.616 56.765 78.696 ;
     RECT  56.704 33.024 56.819 34.392 ;
     RECT  56.704 35.424 56.945 57.432 ;
     RECT  56.704 20.592 56.981 31.8 ;
     RECT  56.819 33.648 56.981 34.392 ;
     RECT  56.945 35.424 57.269 36.936 ;
     RECT  56.981 20.976 57.341 31.8 ;
     RECT  56.704 58.944 57.413 62.136 ;
     RECT  56.945 38.16 57.485 57.432 ;
     RECT  57.485 45.456 57.557 57.432 ;
     RECT  57.341 20.976 57.593 24.456 ;
     RECT  57.341 25.44 57.629 31.8 ;
     RECT  57.485 38.16 57.629 39.912 ;
     RECT  56.704 72.336 57.629 73.272 ;
     RECT  56.729 66.864 57.685 68.136 ;
     RECT  56.704 69.312 57.685 70.824 ;
     RECT  57.629 73.008 57.733 73.272 ;
     RECT  56.704 74.352 57.733 74.376 ;
     RECT  57.629 30 57.737 31.8 ;
     RECT  57.629 38.448 57.737 39.912 ;
     RECT  57.685 66.864 57.737 70.824 ;
     RECT  57.413 59.472 57.772 62.136 ;
     RECT  57.772 62.112 57.805 62.136 ;
     RECT  56.704 63.264 57.805 64.056 ;
     RECT  57.805 62.112 57.809 64.056 ;
     RECT  56.704 75.408 57.841 75.864 ;
     RECT  57.629 25.44 57.845 28.824 ;
     RECT  57.737 38.736 57.878 39.912 ;
     RECT  57.841 75.36 57.985 75.864 ;
     RECT  57.733 73.008 58.021 74.376 ;
     RECT  57.985 75.36 58.021 76.392 ;
     RECT  58.021 73.008 58.057 76.392 ;
     RECT  58.057 73.008 58.141 76.968 ;
     RECT  57.737 31.776 58.273 31.8 ;
     RECT  56.981 34.08 58.309 34.392 ;
     RECT  57.269 35.52 58.309 36.936 ;
     RECT  57.809 62.496 58.381 64.056 ;
     RECT  57.737 66.864 58.381 70.296 ;
     RECT  57.845 25.488 58.669 28.824 ;
     RECT  57.772 59.472 58.669 60.648 ;
     RECT  58.381 66.336 58.7 70.296 ;
     RECT  58.669 71.376 58.7 71.4 ;
     RECT  57.557 53.52 58.705 57.144 ;
     RECT  57.485 41.088 58.741 44.472 ;
     RECT  57.557 45.456 58.741 52.536 ;
     RECT  57.878 38.736 58.777 39.864 ;
     RECT  58.273 31.776 58.849 32.52 ;
     RECT  58.669 58.944 58.849 60.648 ;
     RECT  58.7 66.336 58.849 71.4 ;
     RECT  58.849 31.776 58.885 33.048 ;
     RECT  58.309 34.08 58.885 36.936 ;
     RECT  56.765 78.096 58.921 78.696 ;
     RECT  57.913 79.824 58.921 79.848 ;
     RECT  58.777 38.208 58.957 39.864 ;
     RECT  58.741 41.088 58.957 52.536 ;
     RECT  58.885 31.776 58.993 36.936 ;
     RECT  58.957 38.208 58.993 52.536 ;
     RECT  58.705 53.52 58.993 57.432 ;
     RECT  57.593 21.12 59.108 24.456 ;
     RECT  58.669 25.488 59.108 28.968 ;
     RECT  57.737 30 59.108 30.792 ;
     RECT  58.993 31.776 59.108 57.432 ;
     RECT  58.849 58.656 59.108 60.648 ;
     RECT  58.381 62.496 59.108 64.2 ;
     RECT  58.381 65.184 59.108 65.208 ;
     RECT  58.849 66.336 59.108 71.688 ;
     RECT  58.141 73.008 59.108 76.392 ;
     RECT  58.921 78.096 59.108 79.848 ;
     RECT  59.108 2.148 59.212 103.152 ;
     RECT  59.212 2.418 59.3 103.152 ;
     RECT  59.3 2.418 59.404 103.422 ;
     RECT  59.404 21.12 59.843 76.536 ;
     RECT  59.843 36.288 59.933 76.536 ;
     RECT  59.933 36.288 60.041 56.904 ;
     RECT  59.933 58.08 60.185 76.536 ;
     RECT  60.185 58.08 60.257 71.112 ;
     RECT  59.843 21.12 60.329 35.208 ;
     RECT  60.041 36.288 60.437 55.416 ;
     RECT  60.041 56.544 60.437 56.904 ;
     RECT  60.329 21.12 60.473 28.824 ;
     RECT  60.185 72.144 60.473 76.536 ;
     RECT  60.437 36.288 60.509 39.912 ;
     RECT  60.437 41.136 60.545 55.416 ;
     RECT  60.437 56.544 60.581 56.616 ;
     RECT  60.473 21.12 60.617 28.536 ;
     RECT  60.473 76.368 60.617 76.536 ;
     RECT  60.617 21.12 60.649 23.976 ;
     RECT  60.257 60 60.797 71.112 ;
     RECT  60.509 36.288 60.833 38.472 ;
     RECT  60.649 20.88 61.189 23.976 ;
     RECT  61.189 20.688 61.549 23.976 ;
     RECT  60.617 25.056 61.549 28.536 ;
     RECT  60.329 30 61.549 35.208 ;
     RECT  60.545 41.664 61.549 55.416 ;
     RECT  60.581 56.592 61.549 56.616 ;
     RECT  61.549 20.112 61.808 23.976 ;
     RECT  61.549 25.056 61.808 35.208 ;
     RECT  60.833 36.288 61.808 37.896 ;
     RECT  60.509 39.888 61.808 39.912 ;
     RECT  61.549 41.664 61.808 56.616 ;
     RECT  60.257 58.08 61.808 59.016 ;
     RECT  60.797 60.624 61.808 63.576 ;
     RECT  60.797 64.56 61.808 71.112 ;
     RECT  60.473 72.144 61.808 75.384 ;
     RECT  60.617 76.368 61.808 76.392 ;
     RECT  59.404 78.576 61.808 79.848 ;
     RECT  61.808 2.148 61.912 103.152 ;
     RECT  61.912 2.418 62 103.152 ;
     RECT  62 2.418 62.104 103.422 ;
     RECT  62.104 19.92 63.241 38.088 ;
     RECT  62.104 39.408 63.241 57.288 ;
     RECT  63.241 19.92 63.277 38.184 ;
     RECT  63.241 39.216 63.277 57.288 ;
     RECT  62.104 58.416 63.277 67.464 ;
     RECT  62.104 68.448 63.277 76.68 ;
     RECT  62.104 77.808 63.277 79.848 ;
     RECT  63.277 19.92 63.313 57.288 ;
     RECT  63.313 19.92 63.349 57.384 ;
     RECT  63.277 58.416 63.349 79.848 ;
     RECT  63.349 19.92 64.692 19.944 ;
     RECT  63.349 19.944 64.716 20.016 ;
     RECT  63.349 20.016 64.692 20.04 ;
     RECT  63.349 20.04 64.716 20.112 ;
     RECT  63.349 20.112 64.692 20.136 ;
     RECT  63.349 20.136 64.716 20.208 ;
     RECT  63.349 20.208 64.692 20.232 ;
     RECT  63.349 20.232 64.716 20.304 ;
     RECT  63.349 20.304 64.692 20.328 ;
     RECT  63.349 20.328 64.716 20.4 ;
     RECT  63.349 20.4 64.692 20.424 ;
     RECT  63.349 20.424 64.716 20.496 ;
     RECT  63.349 20.496 64.692 20.52 ;
     RECT  63.349 20.52 64.716 20.592 ;
     RECT  63.349 20.592 64.692 20.616 ;
     RECT  63.349 20.616 64.716 20.688 ;
     RECT  63.349 20.688 64.692 20.712 ;
     RECT  63.349 20.712 64.716 20.784 ;
     RECT  63.349 20.784 64.692 20.808 ;
     RECT  63.349 20.808 64.716 20.88 ;
     RECT  63.349 20.88 64.692 20.904 ;
     RECT  63.349 20.904 64.716 20.976 ;
     RECT  63.349 20.976 64.692 21 ;
     RECT  63.349 21 64.716 21.072 ;
     RECT  63.349 21.072 64.692 21.096 ;
     RECT  63.349 21.096 64.716 21.168 ;
     RECT  63.349 21.168 64.692 21.192 ;
     RECT  63.349 21.192 64.716 21.264 ;
     RECT  63.349 21.264 64.692 21.288 ;
     RECT  63.349 21.288 64.716 21.36 ;
     RECT  63.349 21.36 64.692 21.384 ;
     RECT  63.349 21.384 64.716 21.456 ;
     RECT  63.349 21.456 64.692 21.48 ;
     RECT  63.349 21.48 64.716 21.552 ;
     RECT  63.349 21.552 64.692 21.576 ;
     RECT  63.349 21.576 64.716 21.648 ;
     RECT  63.349 21.648 64.692 21.672 ;
     RECT  63.349 21.672 64.716 21.744 ;
     RECT  63.349 21.744 64.692 21.768 ;
     RECT  63.349 21.768 64.716 21.84 ;
     RECT  63.349 21.84 64.692 21.864 ;
     RECT  63.349 21.864 64.716 21.936 ;
     RECT  63.349 21.936 64.692 21.96 ;
     RECT  63.349 21.96 64.716 22.032 ;
     RECT  63.349 22.032 64.692 22.056 ;
     RECT  63.349 22.056 64.716 22.128 ;
     RECT  63.349 22.128 64.692 22.152 ;
     RECT  63.349 22.152 64.716 22.224 ;
     RECT  63.349 22.224 64.692 22.248 ;
     RECT  63.349 22.248 64.716 22.32 ;
     RECT  63.349 22.32 64.692 22.344 ;
     RECT  63.349 22.344 64.716 22.416 ;
     RECT  63.349 22.416 64.692 22.44 ;
     RECT  63.349 22.44 64.716 22.512 ;
     RECT  63.349 22.512 64.692 22.536 ;
     RECT  63.349 22.536 64.716 22.608 ;
     RECT  63.349 22.608 64.692 22.632 ;
     RECT  63.349 22.632 64.716 22.704 ;
     RECT  63.349 22.704 64.692 22.728 ;
     RECT  63.349 22.728 64.716 22.8 ;
     RECT  63.349 22.8 64.692 22.824 ;
     RECT  63.349 22.824 64.716 22.896 ;
     RECT  63.349 22.896 64.692 22.92 ;
     RECT  63.349 22.92 64.716 22.992 ;
     RECT  63.349 22.992 64.692 23.016 ;
     RECT  63.349 23.016 64.716 23.088 ;
     RECT  63.349 23.088 64.692 23.112 ;
     RECT  63.349 23.112 64.716 23.184 ;
     RECT  63.349 23.184 64.692 23.208 ;
     RECT  63.349 23.208 64.716 23.28 ;
     RECT  63.349 23.28 64.692 23.304 ;
     RECT  63.349 23.304 64.716 23.376 ;
     RECT  63.349 23.376 64.692 23.4 ;
     RECT  63.349 23.4 64.716 23.472 ;
     RECT  63.349 23.472 64.692 23.496 ;
     RECT  63.349 23.496 64.716 23.568 ;
     RECT  63.349 23.568 64.692 23.592 ;
     RECT  63.349 23.592 64.716 23.664 ;
     RECT  63.349 23.664 64.692 23.688 ;
     RECT  63.349 23.688 64.716 23.76 ;
     RECT  63.349 23.76 64.692 23.784 ;
     RECT  63.349 23.784 64.716 23.856 ;
     RECT  63.349 23.856 64.692 23.88 ;
     RECT  63.349 23.88 64.716 23.952 ;
     RECT  63.349 23.952 64.692 23.976 ;
     RECT  63.349 23.976 64.716 24.048 ;
     RECT  63.349 24.048 64.692 24.072 ;
     RECT  63.349 24.072 64.716 24.144 ;
     RECT  63.349 24.144 64.692 24.168 ;
     RECT  63.349 24.168 64.716 24.24 ;
     RECT  63.349 24.24 64.692 24.264 ;
     RECT  63.349 24.264 64.716 24.336 ;
     RECT  63.349 24.336 64.692 24.36 ;
     RECT  63.349 24.36 64.716 24.432 ;
     RECT  63.349 24.432 64.692 24.456 ;
     RECT  63.349 24.456 64.716 24.528 ;
     RECT  63.349 24.528 64.692 24.552 ;
     RECT  63.349 24.552 64.716 24.624 ;
     RECT  63.349 24.624 64.692 24.648 ;
     RECT  63.349 24.648 64.716 24.72 ;
     RECT  63.349 24.72 64.692 24.744 ;
     RECT  63.349 24.744 64.716 24.816 ;
     RECT  63.349 24.816 64.692 24.84 ;
     RECT  63.349 24.84 64.716 24.912 ;
     RECT  63.349 24.912 64.692 24.936 ;
     RECT  63.349 24.936 64.716 25.008 ;
     RECT  63.349 25.008 64.692 25.032 ;
     RECT  63.349 25.032 64.716 25.104 ;
     RECT  63.349 25.104 64.692 25.128 ;
     RECT  63.349 25.128 64.716 25.2 ;
     RECT  63.349 25.2 64.692 25.224 ;
     RECT  63.349 25.224 64.716 25.296 ;
     RECT  63.349 25.296 64.692 25.32 ;
     RECT  63.349 25.32 64.716 25.392 ;
     RECT  63.349 25.392 64.692 25.416 ;
     RECT  63.349 25.416 64.716 25.488 ;
     RECT  63.349 25.488 64.692 25.512 ;
     RECT  63.349 25.512 64.716 25.584 ;
     RECT  63.349 25.584 64.692 25.608 ;
     RECT  63.349 25.608 64.716 25.68 ;
     RECT  63.349 25.68 64.692 25.704 ;
     RECT  63.349 25.704 64.716 25.776 ;
     RECT  63.349 25.776 64.692 25.8 ;
     RECT  63.349 25.8 64.716 25.872 ;
     RECT  63.349 25.872 64.692 25.896 ;
     RECT  63.349 25.896 64.716 25.968 ;
     RECT  63.349 25.968 64.692 25.992 ;
     RECT  63.349 25.992 64.716 26.064 ;
     RECT  63.349 26.064 64.692 26.088 ;
     RECT  63.349 26.088 64.716 26.16 ;
     RECT  63.349 26.16 64.692 26.184 ;
     RECT  63.349 26.184 64.716 26.256 ;
     RECT  63.349 26.256 64.692 26.28 ;
     RECT  63.349 26.28 64.716 26.352 ;
     RECT  63.349 26.352 64.692 26.376 ;
     RECT  63.349 26.376 64.716 26.448 ;
     RECT  63.349 26.448 64.692 26.472 ;
     RECT  63.349 26.472 64.716 26.544 ;
     RECT  63.349 26.544 64.692 26.568 ;
     RECT  63.349 26.568 64.716 26.64 ;
     RECT  63.349 26.64 64.692 26.664 ;
     RECT  63.349 26.664 64.716 26.736 ;
     RECT  63.349 26.736 64.692 26.76 ;
     RECT  63.349 26.76 64.716 26.832 ;
     RECT  63.349 26.832 64.692 26.856 ;
     RECT  63.349 26.856 64.716 26.928 ;
     RECT  63.349 26.928 64.692 26.952 ;
     RECT  63.349 26.952 64.716 27.024 ;
     RECT  63.349 27.024 64.692 27.048 ;
     RECT  63.349 27.048 64.716 27.12 ;
     RECT  63.349 27.12 64.692 27.144 ;
     RECT  63.349 27.144 64.716 27.216 ;
     RECT  63.349 27.216 64.692 27.24 ;
     RECT  63.349 27.24 64.716 27.312 ;
     RECT  63.349 27.312 64.692 27.336 ;
     RECT  63.349 27.336 64.716 27.408 ;
     RECT  63.349 27.408 64.692 27.432 ;
     RECT  63.349 27.432 64.716 27.504 ;
     RECT  63.349 27.504 64.692 27.528 ;
     RECT  63.349 27.528 64.716 27.6 ;
     RECT  63.349 27.6 64.692 27.624 ;
     RECT  63.349 27.624 64.716 27.696 ;
     RECT  63.349 27.696 64.692 27.72 ;
     RECT  63.349 27.72 64.716 27.792 ;
     RECT  63.349 27.792 64.692 27.816 ;
     RECT  63.349 27.816 64.716 27.888 ;
     RECT  63.349 27.888 64.692 27.912 ;
     RECT  63.349 27.912 64.716 27.984 ;
     RECT  63.349 27.984 64.692 28.008 ;
     RECT  63.349 28.008 64.716 28.08 ;
     RECT  63.349 28.08 64.692 28.104 ;
     RECT  63.349 28.104 64.716 28.176 ;
     RECT  63.349 28.176 64.692 28.2 ;
     RECT  63.349 28.2 64.716 28.272 ;
     RECT  63.349 28.272 64.692 28.296 ;
     RECT  63.349 28.296 64.716 28.368 ;
     RECT  63.349 28.368 64.692 28.392 ;
     RECT  63.349 28.392 64.716 28.464 ;
     RECT  63.349 28.464 64.692 28.488 ;
     RECT  63.349 28.488 64.716 28.56 ;
     RECT  63.349 28.56 64.692 28.584 ;
     RECT  63.349 28.584 64.716 28.656 ;
     RECT  63.349 28.656 64.692 28.68 ;
     RECT  63.349 28.68 64.716 28.752 ;
     RECT  63.349 28.752 64.692 28.776 ;
     RECT  63.349 28.776 64.716 28.848 ;
     RECT  63.349 28.848 64.692 28.872 ;
     RECT  63.349 28.872 64.716 28.944 ;
     RECT  63.349 28.944 64.692 28.968 ;
     RECT  63.349 28.968 64.716 29.04 ;
     RECT  63.349 29.04 64.692 29.064 ;
     RECT  63.349 29.064 64.716 29.136 ;
     RECT  63.349 29.136 64.692 29.16 ;
     RECT  63.349 29.16 64.716 29.232 ;
     RECT  63.349 29.232 64.692 29.256 ;
     RECT  63.349 29.256 64.716 29.328 ;
     RECT  63.349 29.328 64.692 29.352 ;
     RECT  63.349 29.352 64.716 29.424 ;
     RECT  63.349 29.424 64.692 29.448 ;
     RECT  63.349 29.448 64.716 29.52 ;
     RECT  63.349 29.52 64.692 29.544 ;
     RECT  63.349 29.544 64.716 29.616 ;
     RECT  63.349 29.616 64.692 29.64 ;
     RECT  63.349 29.64 64.716 29.712 ;
     RECT  63.349 29.712 64.692 29.736 ;
     RECT  63.349 29.736 64.716 29.808 ;
     RECT  63.349 29.808 64.692 29.832 ;
     RECT  63.349 29.832 64.716 29.904 ;
     RECT  63.349 29.904 64.692 29.928 ;
     RECT  63.349 29.928 64.716 30 ;
     RECT  63.349 30 64.692 30.024 ;
     RECT  63.349 30.024 64.716 30.096 ;
     RECT  63.349 30.096 64.692 30.12 ;
     RECT  63.349 30.12 64.716 30.192 ;
     RECT  63.349 30.192 64.692 30.216 ;
     RECT  63.349 30.216 64.716 30.288 ;
     RECT  63.349 30.288 64.692 30.312 ;
     RECT  63.349 30.312 64.716 30.384 ;
     RECT  63.349 30.384 64.692 30.408 ;
     RECT  63.349 30.408 64.716 30.48 ;
     RECT  63.349 30.48 64.692 30.504 ;
     RECT  63.349 30.504 64.716 30.576 ;
     RECT  63.349 30.576 64.692 30.6 ;
     RECT  63.349 30.6 64.716 30.672 ;
     RECT  63.349 30.672 64.692 30.696 ;
     RECT  63.349 30.696 64.716 30.768 ;
     RECT  63.349 30.768 64.692 30.792 ;
     RECT  63.349 30.792 64.716 30.864 ;
     RECT  63.349 30.864 64.692 30.888 ;
     RECT  63.349 30.888 64.716 30.96 ;
     RECT  63.349 30.96 64.692 30.984 ;
     RECT  63.349 30.984 64.716 31.056 ;
     RECT  63.349 31.056 64.692 31.08 ;
     RECT  63.349 31.08 64.716 31.152 ;
     RECT  63.349 31.152 64.692 31.176 ;
     RECT  63.349 31.176 64.716 31.248 ;
     RECT  63.349 31.248 64.692 31.272 ;
     RECT  63.349 31.272 64.716 31.344 ;
     RECT  63.349 31.344 64.692 31.368 ;
     RECT  63.349 31.368 64.716 31.44 ;
     RECT  63.349 31.44 64.692 31.464 ;
     RECT  63.349 31.464 64.716 31.536 ;
     RECT  63.349 31.536 64.692 31.56 ;
     RECT  63.349 31.56 64.716 31.632 ;
     RECT  63.349 31.632 64.692 31.656 ;
     RECT  63.349 31.656 64.716 31.728 ;
     RECT  63.349 31.728 64.692 31.752 ;
     RECT  63.349 31.752 64.716 31.824 ;
     RECT  63.349 31.824 64.692 31.848 ;
     RECT  63.349 31.848 64.716 31.92 ;
     RECT  63.349 31.92 64.692 31.944 ;
     RECT  63.349 31.944 64.716 32.016 ;
     RECT  63.349 32.016 64.692 32.04 ;
     RECT  63.349 32.04 64.716 32.112 ;
     RECT  63.349 32.112 64.692 32.136 ;
     RECT  63.349 32.136 64.716 32.208 ;
     RECT  63.349 32.208 64.692 32.232 ;
     RECT  63.349 32.232 64.716 32.304 ;
     RECT  63.349 32.304 64.692 32.328 ;
     RECT  63.349 32.328 64.716 32.4 ;
     RECT  63.349 32.4 64.692 32.424 ;
     RECT  63.349 32.424 64.716 32.496 ;
     RECT  63.349 32.496 64.692 32.52 ;
     RECT  63.349 32.52 64.716 32.592 ;
     RECT  63.349 32.592 64.692 32.616 ;
     RECT  63.349 32.616 64.716 32.688 ;
     RECT  63.349 32.688 64.692 32.712 ;
     RECT  63.349 32.712 64.716 32.784 ;
     RECT  63.349 32.784 64.692 32.808 ;
     RECT  63.349 32.808 64.716 32.88 ;
     RECT  63.349 32.88 64.692 32.904 ;
     RECT  63.349 32.904 64.716 32.976 ;
     RECT  63.349 32.976 64.692 33 ;
     RECT  63.349 33 64.716 33.072 ;
     RECT  63.349 33.072 64.692 33.096 ;
     RECT  63.349 33.096 64.716 33.168 ;
     RECT  63.349 33.168 64.692 33.192 ;
     RECT  63.349 33.192 64.716 33.264 ;
     RECT  63.349 33.264 64.692 33.288 ;
     RECT  63.349 33.288 64.716 33.36 ;
     RECT  63.349 33.36 64.692 33.384 ;
     RECT  63.349 33.384 64.716 33.456 ;
     RECT  63.349 33.456 64.692 33.48 ;
     RECT  63.349 33.48 64.716 33.552 ;
     RECT  63.349 33.552 64.692 33.576 ;
     RECT  63.349 33.576 64.716 33.648 ;
     RECT  63.349 33.648 64.692 33.672 ;
     RECT  63.349 33.672 64.716 33.744 ;
     RECT  63.349 33.744 64.692 33.768 ;
     RECT  63.349 33.768 64.716 33.84 ;
     RECT  63.349 33.84 64.692 33.864 ;
     RECT  63.349 33.864 64.716 33.936 ;
     RECT  63.349 33.936 64.692 33.96 ;
     RECT  63.349 33.96 64.716 34.032 ;
     RECT  63.349 34.032 64.692 34.056 ;
     RECT  63.349 34.056 64.716 34.128 ;
     RECT  63.349 34.128 64.692 34.152 ;
     RECT  63.349 34.152 64.716 34.224 ;
     RECT  63.349 34.224 64.692 34.248 ;
     RECT  63.349 34.248 64.716 34.32 ;
     RECT  63.349 34.32 64.692 34.344 ;
     RECT  63.349 34.344 64.716 34.416 ;
     RECT  63.349 34.416 64.692 34.44 ;
     RECT  63.349 34.44 64.716 34.512 ;
     RECT  63.349 34.512 64.692 34.536 ;
     RECT  63.349 34.536 64.716 34.608 ;
     RECT  63.349 34.608 64.692 34.632 ;
     RECT  63.349 34.632 64.716 34.704 ;
     RECT  63.349 34.704 64.692 34.728 ;
     RECT  63.349 34.728 64.716 34.8 ;
     RECT  63.349 34.8 64.692 34.824 ;
     RECT  63.349 34.824 64.716 34.896 ;
     RECT  63.349 34.896 64.692 34.92 ;
     RECT  63.349 34.92 64.716 34.992 ;
     RECT  63.349 34.992 64.692 35.016 ;
     RECT  63.349 35.016 64.716 35.088 ;
     RECT  63.349 35.088 64.692 35.112 ;
     RECT  63.349 35.112 64.716 35.184 ;
     RECT  63.349 35.184 64.692 35.208 ;
     RECT  63.349 35.208 64.716 35.28 ;
     RECT  63.349 35.28 64.692 35.304 ;
     RECT  63.349 35.304 64.716 35.376 ;
     RECT  63.349 35.376 64.692 35.4 ;
     RECT  63.349 35.4 64.716 35.472 ;
     RECT  63.349 35.472 64.692 35.496 ;
     RECT  63.349 35.496 64.716 35.568 ;
     RECT  63.349 35.568 64.692 35.592 ;
     RECT  63.349 35.592 64.716 35.664 ;
     RECT  63.349 35.664 64.692 35.688 ;
     RECT  63.349 35.688 64.716 35.76 ;
     RECT  63.349 35.76 64.692 35.784 ;
     RECT  63.349 35.784 64.716 35.856 ;
     RECT  63.349 35.856 64.692 35.88 ;
     RECT  63.349 35.88 64.716 35.952 ;
     RECT  63.349 35.952 64.692 35.976 ;
     RECT  63.349 35.976 64.716 36.048 ;
     RECT  63.349 36.048 64.692 36.072 ;
     RECT  63.349 36.072 64.716 36.144 ;
     RECT  63.349 36.144 64.692 36.168 ;
     RECT  63.349 36.168 64.716 36.24 ;
     RECT  63.349 36.24 64.692 36.264 ;
     RECT  63.349 36.264 64.716 36.336 ;
     RECT  63.349 36.336 64.692 36.36 ;
     RECT  63.349 36.36 64.716 36.432 ;
     RECT  63.349 36.432 64.692 36.456 ;
     RECT  63.349 36.456 64.716 36.528 ;
     RECT  63.349 36.528 64.692 36.552 ;
     RECT  63.349 36.552 64.716 36.624 ;
     RECT  63.349 36.624 64.692 36.648 ;
     RECT  63.349 36.648 64.716 36.72 ;
     RECT  63.349 36.72 64.692 36.744 ;
     RECT  63.349 36.744 64.716 36.816 ;
     RECT  63.349 36.816 64.692 36.84 ;
     RECT  63.349 36.84 64.716 36.912 ;
     RECT  63.349 36.912 64.692 36.936 ;
     RECT  63.349 36.936 64.716 37.008 ;
     RECT  63.349 37.008 64.692 37.032 ;
     RECT  63.349 37.032 64.716 37.104 ;
     RECT  63.349 37.104 64.692 37.128 ;
     RECT  63.349 37.128 64.716 37.2 ;
     RECT  63.349 37.2 64.692 37.224 ;
     RECT  63.349 37.224 64.716 37.296 ;
     RECT  63.349 37.296 64.692 37.32 ;
     RECT  63.349 37.32 64.716 37.392 ;
     RECT  63.349 37.392 64.692 37.416 ;
     RECT  63.349 37.416 64.716 37.488 ;
     RECT  63.349 37.488 64.692 37.512 ;
     RECT  63.349 37.512 64.716 37.584 ;
     RECT  63.349 37.584 64.692 37.608 ;
     RECT  63.349 37.608 64.716 37.68 ;
     RECT  63.349 37.68 64.692 37.704 ;
     RECT  63.349 37.704 64.716 37.776 ;
     RECT  63.349 37.776 64.692 37.8 ;
     RECT  63.349 37.8 64.716 37.872 ;
     RECT  63.349 37.872 64.692 37.896 ;
     RECT  63.349 37.896 64.716 37.968 ;
     RECT  63.349 37.968 64.692 37.992 ;
     RECT  63.349 37.992 64.716 38.064 ;
     RECT  63.349 38.064 64.692 38.088 ;
     RECT  63.349 38.088 64.716 38.16 ;
     RECT  63.349 38.16 64.692 38.184 ;
     RECT  63.349 38.184 64.716 38.256 ;
     RECT  63.349 38.256 64.692 38.28 ;
     RECT  63.349 38.28 64.716 39.12 ;
     RECT  63.349 39.12 64.692 39.144 ;
     RECT  63.349 39.144 64.716 39.216 ;
     RECT  63.349 39.216 64.692 39.24 ;
     RECT  63.349 39.24 64.716 39.312 ;
     RECT  63.349 39.312 64.692 39.336 ;
     RECT  63.349 39.336 64.716 39.408 ;
     RECT  63.349 39.408 64.692 39.432 ;
     RECT  63.349 39.432 64.716 39.504 ;
     RECT  63.349 39.504 64.692 39.528 ;
     RECT  63.349 39.528 64.716 39.6 ;
     RECT  63.349 39.6 64.692 39.624 ;
     RECT  63.349 39.624 64.716 39.696 ;
     RECT  63.349 39.696 64.692 39.72 ;
     RECT  63.349 39.72 64.716 39.792 ;
     RECT  63.349 39.792 64.692 39.816 ;
     RECT  63.349 39.816 64.716 39.888 ;
     RECT  63.349 39.888 64.692 39.912 ;
     RECT  63.349 39.912 64.716 39.984 ;
     RECT  63.349 39.984 64.692 40.008 ;
     RECT  63.349 40.008 64.716 40.08 ;
     RECT  63.349 40.08 64.692 40.104 ;
     RECT  63.349 40.104 64.716 40.176 ;
     RECT  63.349 40.176 64.692 40.2 ;
     RECT  63.349 40.2 64.716 40.272 ;
     RECT  63.349 40.272 64.692 40.296 ;
     RECT  63.349 40.296 64.716 40.368 ;
     RECT  63.349 40.368 64.692 40.392 ;
     RECT  63.349 40.392 64.716 40.464 ;
     RECT  63.349 40.464 64.692 40.488 ;
     RECT  63.349 40.488 64.716 40.56 ;
     RECT  63.349 40.56 64.692 40.584 ;
     RECT  63.349 40.584 64.716 40.656 ;
     RECT  63.349 40.656 64.692 40.68 ;
     RECT  63.349 40.68 64.716 40.752 ;
     RECT  63.349 40.752 64.692 40.776 ;
     RECT  63.349 40.776 64.716 40.848 ;
     RECT  63.349 40.848 64.692 40.872 ;
     RECT  63.349 40.872 64.716 40.944 ;
     RECT  63.349 40.944 64.692 40.968 ;
     RECT  63.349 40.968 64.716 41.04 ;
     RECT  63.349 41.04 64.692 41.064 ;
     RECT  63.349 41.064 64.716 41.136 ;
     RECT  63.349 41.136 64.692 41.16 ;
     RECT  63.349 41.16 64.716 41.232 ;
     RECT  63.349 41.232 64.692 41.256 ;
     RECT  63.349 41.256 64.716 41.328 ;
     RECT  63.349 41.328 64.692 41.352 ;
     RECT  63.349 41.352 64.716 41.424 ;
     RECT  63.349 41.424 64.692 41.448 ;
     RECT  63.349 41.448 64.716 41.52 ;
     RECT  63.349 41.52 64.692 41.544 ;
     RECT  63.349 41.544 64.716 41.616 ;
     RECT  63.349 41.616 64.692 41.64 ;
     RECT  63.349 41.64 64.716 41.712 ;
     RECT  63.349 41.712 64.692 41.736 ;
     RECT  63.349 41.736 64.716 41.808 ;
     RECT  63.349 41.808 64.692 41.832 ;
     RECT  63.349 41.832 64.716 41.904 ;
     RECT  63.349 41.904 64.692 41.928 ;
     RECT  63.349 41.928 64.716 42 ;
     RECT  63.349 42 64.692 42.024 ;
     RECT  63.349 42.024 64.716 42.096 ;
     RECT  63.349 42.096 64.692 42.12 ;
     RECT  63.349 42.12 64.716 42.192 ;
     RECT  63.349 42.192 64.692 42.216 ;
     RECT  63.349 42.216 64.716 42.288 ;
     RECT  63.349 42.288 64.692 42.312 ;
     RECT  63.349 42.312 64.716 42.384 ;
     RECT  63.349 42.384 64.692 42.408 ;
     RECT  63.349 42.408 64.716 42.48 ;
     RECT  63.349 42.48 64.692 42.504 ;
     RECT  63.349 42.504 64.716 42.576 ;
     RECT  63.349 42.576 64.692 42.6 ;
     RECT  63.349 42.6 64.716 42.672 ;
     RECT  63.349 42.672 64.692 42.696 ;
     RECT  63.349 42.696 64.716 42.768 ;
     RECT  63.349 42.768 64.692 42.792 ;
     RECT  63.349 42.792 64.716 42.864 ;
     RECT  63.349 42.864 64.692 42.888 ;
     RECT  63.349 42.888 64.716 42.96 ;
     RECT  63.349 42.96 64.692 42.984 ;
     RECT  63.349 42.984 64.716 43.056 ;
     RECT  63.349 43.056 64.692 43.08 ;
     RECT  63.349 43.08 64.716 43.152 ;
     RECT  63.349 43.152 64.692 43.176 ;
     RECT  63.349 43.176 64.716 43.248 ;
     RECT  63.349 43.248 64.692 43.272 ;
     RECT  63.349 43.272 64.716 43.344 ;
     RECT  63.349 43.344 64.692 43.368 ;
     RECT  63.349 43.368 64.716 43.44 ;
     RECT  63.349 43.44 64.692 43.464 ;
     RECT  63.349 43.464 64.716 43.536 ;
     RECT  63.349 43.536 64.692 43.56 ;
     RECT  63.349 43.56 64.716 43.632 ;
     RECT  63.349 43.632 64.692 43.656 ;
     RECT  63.349 43.656 64.716 43.728 ;
     RECT  63.349 43.728 64.692 43.752 ;
     RECT  63.349 43.752 64.716 43.824 ;
     RECT  63.349 43.824 64.692 43.848 ;
     RECT  63.349 43.848 64.716 43.92 ;
     RECT  63.349 43.92 64.692 43.944 ;
     RECT  63.349 43.944 64.716 44.016 ;
     RECT  63.349 44.016 64.692 44.04 ;
     RECT  63.349 44.04 64.716 44.112 ;
     RECT  63.349 44.112 64.692 44.136 ;
     RECT  63.349 44.136 64.716 44.208 ;
     RECT  63.349 44.208 64.692 44.232 ;
     RECT  63.349 44.232 64.716 44.304 ;
     RECT  63.349 44.304 64.692 44.328 ;
     RECT  63.349 44.328 64.716 44.4 ;
     RECT  63.349 44.4 64.692 44.424 ;
     RECT  63.349 44.424 64.716 44.496 ;
     RECT  63.349 44.496 64.692 44.52 ;
     RECT  63.349 44.52 64.716 44.592 ;
     RECT  63.349 44.592 64.692 44.616 ;
     RECT  63.349 44.616 64.716 44.688 ;
     RECT  63.349 44.688 64.692 44.712 ;
     RECT  63.349 44.712 64.716 44.784 ;
     RECT  63.349 44.784 64.692 44.808 ;
     RECT  63.349 44.808 64.716 44.88 ;
     RECT  63.349 44.88 64.692 44.904 ;
     RECT  63.349 44.904 64.716 44.976 ;
     RECT  63.349 44.976 64.692 45 ;
     RECT  63.349 45 64.716 45.072 ;
     RECT  63.349 45.072 64.692 45.096 ;
     RECT  63.349 45.096 64.716 45.168 ;
     RECT  63.349 45.168 64.692 45.192 ;
     RECT  63.349 45.192 64.716 45.264 ;
     RECT  63.349 45.264 64.692 45.288 ;
     RECT  63.349 45.288 64.716 45.36 ;
     RECT  63.349 45.36 64.692 45.384 ;
     RECT  63.349 45.384 64.716 45.456 ;
     RECT  63.349 45.456 64.692 45.48 ;
     RECT  63.349 45.48 64.716 45.552 ;
     RECT  63.349 45.552 64.692 45.576 ;
     RECT  63.349 45.576 64.716 45.648 ;
     RECT  63.349 45.648 64.692 45.672 ;
     RECT  63.349 45.672 64.716 45.744 ;
     RECT  63.349 45.744 64.692 45.768 ;
     RECT  63.349 45.768 64.716 45.84 ;
     RECT  63.349 45.84 64.692 45.864 ;
     RECT  63.349 45.864 64.716 45.936 ;
     RECT  63.349 45.936 64.692 45.96 ;
     RECT  63.349 45.96 64.716 46.032 ;
     RECT  63.349 46.032 64.692 46.056 ;
     RECT  63.349 46.056 64.716 46.128 ;
     RECT  63.349 46.128 64.692 46.152 ;
     RECT  63.349 46.152 64.716 46.224 ;
     RECT  63.349 46.224 64.692 46.248 ;
     RECT  63.349 46.248 64.716 46.32 ;
     RECT  63.349 46.32 64.692 46.344 ;
     RECT  63.349 46.344 64.716 46.416 ;
     RECT  63.349 46.416 64.692 46.44 ;
     RECT  63.349 46.44 64.716 46.512 ;
     RECT  63.349 46.512 64.692 46.536 ;
     RECT  63.349 46.536 64.716 46.608 ;
     RECT  63.349 46.608 64.692 46.632 ;
     RECT  63.349 46.632 64.716 46.704 ;
     RECT  63.349 46.704 64.692 46.728 ;
     RECT  63.349 46.728 64.716 46.8 ;
     RECT  63.349 46.8 64.692 46.824 ;
     RECT  63.349 46.824 64.716 46.896 ;
     RECT  63.349 46.896 64.692 46.92 ;
     RECT  63.349 46.92 64.716 46.992 ;
     RECT  63.349 46.992 64.692 47.016 ;
     RECT  63.349 47.016 64.716 47.088 ;
     RECT  63.349 47.088 64.692 47.112 ;
     RECT  63.349 47.112 64.716 47.184 ;
     RECT  63.349 47.184 64.692 47.208 ;
     RECT  63.349 47.208 64.716 47.28 ;
     RECT  63.349 47.28 64.692 47.304 ;
     RECT  63.349 47.304 64.716 47.376 ;
     RECT  63.349 47.376 64.692 47.4 ;
     RECT  63.349 47.4 64.716 47.472 ;
     RECT  63.349 47.472 64.692 47.496 ;
     RECT  63.349 47.496 64.716 47.568 ;
     RECT  63.349 47.568 64.692 47.592 ;
     RECT  63.349 47.592 64.716 47.664 ;
     RECT  63.349 47.664 64.692 47.688 ;
     RECT  63.349 47.688 64.716 47.76 ;
     RECT  63.349 47.76 64.692 47.784 ;
     RECT  63.349 47.784 64.716 47.856 ;
     RECT  63.349 47.856 64.692 47.88 ;
     RECT  63.349 47.88 64.716 47.952 ;
     RECT  63.349 47.952 64.692 47.976 ;
     RECT  63.349 47.976 64.716 48.048 ;
     RECT  63.349 48.048 64.692 48.072 ;
     RECT  63.349 48.072 64.716 48.144 ;
     RECT  63.349 48.144 64.692 48.168 ;
     RECT  63.349 48.168 64.716 48.24 ;
     RECT  63.349 48.24 64.692 48.264 ;
     RECT  63.349 48.264 64.716 48.336 ;
     RECT  63.349 48.336 64.692 48.36 ;
     RECT  63.349 48.36 64.716 48.432 ;
     RECT  63.349 48.432 64.692 48.456 ;
     RECT  63.349 48.456 64.716 48.528 ;
     RECT  63.349 48.528 64.692 48.552 ;
     RECT  63.349 48.552 64.716 48.624 ;
     RECT  63.349 48.624 64.692 48.648 ;
     RECT  63.349 48.648 64.716 48.72 ;
     RECT  63.349 48.72 64.692 48.744 ;
     RECT  63.349 48.744 64.716 48.816 ;
     RECT  63.349 48.816 64.692 48.84 ;
     RECT  63.349 48.84 64.716 48.912 ;
     RECT  63.349 48.912 64.692 48.936 ;
     RECT  63.349 48.936 64.716 49.008 ;
     RECT  63.349 49.008 64.692 49.032 ;
     RECT  63.349 49.032 64.716 49.104 ;
     RECT  63.349 49.104 64.692 49.128 ;
     RECT  63.349 49.128 64.716 49.2 ;
     RECT  63.349 49.2 64.692 49.224 ;
     RECT  63.349 49.224 64.716 49.296 ;
     RECT  63.349 49.296 64.692 49.32 ;
     RECT  63.349 49.32 64.716 49.392 ;
     RECT  63.349 49.392 64.692 49.416 ;
     RECT  63.349 49.416 64.716 49.488 ;
     RECT  63.349 49.488 64.692 49.512 ;
     RECT  63.349 49.512 64.716 49.584 ;
     RECT  63.349 49.584 64.692 49.608 ;
     RECT  63.349 49.608 64.716 49.68 ;
     RECT  63.349 49.68 64.692 49.704 ;
     RECT  63.349 49.704 64.716 49.776 ;
     RECT  63.349 49.776 64.692 49.8 ;
     RECT  63.349 49.8 64.716 49.872 ;
     RECT  63.349 49.872 64.692 49.896 ;
     RECT  63.349 49.896 64.716 49.968 ;
     RECT  63.349 49.968 64.692 49.992 ;
     RECT  63.349 49.992 64.716 50.064 ;
     RECT  63.349 50.064 64.692 50.088 ;
     RECT  63.349 50.088 64.716 50.16 ;
     RECT  63.349 50.16 64.692 50.184 ;
     RECT  63.349 50.184 64.716 50.256 ;
     RECT  63.349 50.256 64.692 50.28 ;
     RECT  63.349 50.28 64.716 50.352 ;
     RECT  63.349 50.352 64.692 50.376 ;
     RECT  63.349 50.376 64.716 50.448 ;
     RECT  63.349 50.448 64.692 50.472 ;
     RECT  63.349 50.472 64.716 50.544 ;
     RECT  63.349 50.544 64.692 50.568 ;
     RECT  63.349 50.568 64.716 50.64 ;
     RECT  63.349 50.64 64.692 50.664 ;
     RECT  63.349 50.664 64.716 50.736 ;
     RECT  63.349 50.736 64.692 50.76 ;
     RECT  63.349 50.76 64.716 50.832 ;
     RECT  63.349 50.832 64.692 50.856 ;
     RECT  63.349 50.856 64.716 50.928 ;
     RECT  63.349 50.928 64.692 50.952 ;
     RECT  63.349 50.952 64.716 51.024 ;
     RECT  63.349 51.024 64.692 51.048 ;
     RECT  63.349 51.048 64.716 51.12 ;
     RECT  63.349 51.12 64.692 51.144 ;
     RECT  63.349 51.144 64.716 51.216 ;
     RECT  63.349 51.216 64.692 51.24 ;
     RECT  63.349 51.24 64.716 51.312 ;
     RECT  63.349 51.312 64.692 51.336 ;
     RECT  63.349 51.336 64.716 51.408 ;
     RECT  63.349 51.408 64.692 51.432 ;
     RECT  63.349 51.432 64.716 51.504 ;
     RECT  63.349 51.504 64.692 51.528 ;
     RECT  63.349 51.528 64.716 51.6 ;
     RECT  63.349 51.6 64.692 51.624 ;
     RECT  63.349 51.624 64.716 51.696 ;
     RECT  63.349 51.696 64.692 51.72 ;
     RECT  63.349 51.72 64.716 51.792 ;
     RECT  63.349 51.792 64.692 51.816 ;
     RECT  63.349 51.816 64.716 51.888 ;
     RECT  63.349 51.888 64.692 51.912 ;
     RECT  63.349 51.912 64.716 51.984 ;
     RECT  63.349 51.984 64.692 52.008 ;
     RECT  63.349 52.008 64.716 52.08 ;
     RECT  63.349 52.08 64.692 52.104 ;
     RECT  63.349 52.104 64.716 52.176 ;
     RECT  63.349 52.176 64.692 52.2 ;
     RECT  63.349 52.2 64.716 52.272 ;
     RECT  63.349 52.272 64.692 52.296 ;
     RECT  63.349 52.296 64.716 52.368 ;
     RECT  63.349 52.368 64.692 52.392 ;
     RECT  63.349 52.392 64.716 52.464 ;
     RECT  63.349 52.464 64.692 52.488 ;
     RECT  63.349 52.488 64.716 52.56 ;
     RECT  63.349 52.56 64.692 52.584 ;
     RECT  63.349 52.584 64.716 52.656 ;
     RECT  63.349 52.656 64.692 52.68 ;
     RECT  63.349 52.68 64.716 52.752 ;
     RECT  63.349 52.752 64.692 52.776 ;
     RECT  63.349 52.776 64.716 52.848 ;
     RECT  63.349 52.848 64.692 52.872 ;
     RECT  63.349 52.872 64.716 52.944 ;
     RECT  63.349 52.944 64.692 52.968 ;
     RECT  63.349 52.968 64.716 53.04 ;
     RECT  63.349 53.04 64.692 53.064 ;
     RECT  63.349 53.064 64.716 53.136 ;
     RECT  63.349 53.136 64.692 53.16 ;
     RECT  63.349 53.16 64.716 53.232 ;
     RECT  63.349 53.232 64.692 53.256 ;
     RECT  63.349 53.256 64.716 53.328 ;
     RECT  63.349 53.328 64.692 53.352 ;
     RECT  63.349 53.352 64.716 53.424 ;
     RECT  63.349 53.424 64.692 53.448 ;
     RECT  63.349 53.448 64.716 53.52 ;
     RECT  63.349 53.52 64.692 53.544 ;
     RECT  63.349 53.544 64.716 53.616 ;
     RECT  63.349 53.616 64.692 53.64 ;
     RECT  63.349 53.64 64.716 53.712 ;
     RECT  63.349 53.712 64.692 53.736 ;
     RECT  63.349 53.736 64.716 53.808 ;
     RECT  63.349 53.808 64.692 53.832 ;
     RECT  63.349 53.832 64.716 53.904 ;
     RECT  63.349 53.904 64.692 53.928 ;
     RECT  63.349 53.928 64.716 54 ;
     RECT  63.349 54 64.692 54.024 ;
     RECT  63.349 54.024 64.716 54.096 ;
     RECT  63.349 54.096 64.692 54.12 ;
     RECT  63.349 54.12 64.716 54.192 ;
     RECT  63.349 54.192 64.692 54.216 ;
     RECT  63.349 54.216 64.716 54.288 ;
     RECT  63.349 54.288 64.692 54.312 ;
     RECT  63.349 54.312 64.716 54.384 ;
     RECT  63.349 54.384 64.692 54.408 ;
     RECT  63.349 54.408 64.716 54.48 ;
     RECT  63.349 54.48 64.692 54.504 ;
     RECT  63.349 54.504 64.716 54.576 ;
     RECT  63.349 54.576 64.692 54.6 ;
     RECT  63.349 54.6 64.716 54.672 ;
     RECT  63.349 54.672 64.692 54.696 ;
     RECT  63.349 54.696 64.716 54.768 ;
     RECT  63.349 54.768 64.692 54.792 ;
     RECT  63.349 54.792 64.716 54.864 ;
     RECT  63.349 54.864 64.692 54.888 ;
     RECT  63.349 54.888 64.716 54.96 ;
     RECT  63.349 54.96 64.692 54.984 ;
     RECT  63.349 54.984 64.716 55.056 ;
     RECT  63.349 55.056 64.692 55.08 ;
     RECT  63.349 55.08 64.716 55.152 ;
     RECT  63.349 55.152 64.692 55.176 ;
     RECT  63.349 55.176 64.716 55.248 ;
     RECT  63.349 55.248 64.692 55.272 ;
     RECT  63.349 55.272 64.716 55.344 ;
     RECT  63.349 55.344 64.692 55.368 ;
     RECT  63.349 55.368 64.716 55.44 ;
     RECT  63.349 55.44 64.692 55.464 ;
     RECT  63.349 55.464 64.716 55.536 ;
     RECT  63.349 55.536 64.692 55.56 ;
     RECT  63.349 55.56 64.716 55.632 ;
     RECT  63.349 55.632 64.692 55.656 ;
     RECT  63.349 55.656 64.716 55.728 ;
     RECT  63.349 55.728 64.692 55.752 ;
     RECT  63.349 55.752 64.716 55.824 ;
     RECT  63.349 55.824 64.692 55.848 ;
     RECT  63.349 55.848 64.716 55.92 ;
     RECT  63.349 55.92 64.692 55.944 ;
     RECT  63.349 55.944 64.716 56.016 ;
     RECT  63.349 56.016 64.692 56.04 ;
     RECT  63.349 56.04 64.716 56.112 ;
     RECT  63.349 56.112 64.692 56.136 ;
     RECT  63.349 56.136 64.716 56.208 ;
     RECT  63.349 56.208 64.692 56.232 ;
     RECT  63.349 56.232 64.716 56.304 ;
     RECT  63.349 56.304 64.692 56.328 ;
     RECT  63.349 56.328 64.716 56.4 ;
     RECT  63.349 56.4 64.692 56.424 ;
     RECT  63.349 56.424 64.716 56.496 ;
     RECT  63.349 56.496 64.692 56.52 ;
     RECT  63.349 56.52 64.716 56.592 ;
     RECT  63.349 56.592 64.692 56.616 ;
     RECT  63.349 56.616 64.716 56.688 ;
     RECT  63.349 56.688 64.692 56.712 ;
     RECT  63.349 56.712 64.716 56.784 ;
     RECT  63.349 56.784 64.692 56.808 ;
     RECT  63.349 56.808 64.716 56.88 ;
     RECT  63.349 56.88 64.692 56.904 ;
     RECT  63.349 56.904 64.716 56.976 ;
     RECT  63.349 56.976 64.692 57 ;
     RECT  63.349 57 64.716 57.072 ;
     RECT  63.349 57.072 64.692 57.096 ;
     RECT  63.349 57.096 64.716 57.168 ;
     RECT  63.349 57.168 64.692 57.192 ;
     RECT  63.349 57.192 64.716 57.264 ;
     RECT  63.349 57.264 64.692 57.288 ;
     RECT  63.349 57.288 64.716 57.36 ;
     RECT  63.349 57.36 64.692 57.384 ;
     RECT  63.349 57.384 64.716 57.456 ;
     RECT  63.349 57.456 64.692 57.48 ;
     RECT  63.349 57.48 64.716 58.32 ;
     RECT  63.349 58.32 64.692 58.344 ;
     RECT  63.349 58.344 64.716 58.416 ;
     RECT  63.349 58.416 64.692 58.44 ;
     RECT  63.349 58.44 64.716 58.512 ;
     RECT  63.349 58.512 64.692 58.536 ;
     RECT  63.349 58.536 64.716 58.608 ;
     RECT  63.349 58.608 64.692 58.632 ;
     RECT  63.349 58.632 64.716 58.704 ;
     RECT  63.349 58.704 64.692 58.728 ;
     RECT  63.349 58.728 64.716 58.8 ;
     RECT  63.349 58.8 64.692 58.824 ;
     RECT  63.349 58.824 64.716 58.896 ;
     RECT  63.349 58.896 64.692 58.92 ;
     RECT  63.349 58.92 64.716 58.992 ;
     RECT  63.349 58.992 64.692 59.016 ;
     RECT  63.349 59.016 64.716 59.088 ;
     RECT  63.349 59.088 64.692 59.112 ;
     RECT  63.349 59.112 64.716 59.184 ;
     RECT  63.349 59.184 64.692 59.208 ;
     RECT  63.349 59.208 64.716 59.28 ;
     RECT  63.349 59.28 64.692 59.304 ;
     RECT  63.349 59.304 64.716 59.376 ;
     RECT  63.349 59.376 64.692 59.4 ;
     RECT  63.349 59.4 64.716 59.472 ;
     RECT  63.349 59.472 64.692 59.496 ;
     RECT  63.349 59.496 64.716 59.568 ;
     RECT  63.349 59.568 64.692 59.592 ;
     RECT  63.349 59.592 64.716 59.664 ;
     RECT  63.349 59.664 64.692 59.688 ;
     RECT  63.349 59.688 64.716 59.76 ;
     RECT  63.349 59.76 64.692 59.784 ;
     RECT  63.349 59.784 64.716 59.856 ;
     RECT  63.349 59.856 64.692 59.88 ;
     RECT  63.349 59.88 64.716 59.952 ;
     RECT  63.349 59.952 64.692 59.976 ;
     RECT  63.349 59.976 64.716 60.048 ;
     RECT  63.349 60.048 64.692 60.072 ;
     RECT  63.349 60.072 64.716 60.144 ;
     RECT  63.349 60.144 64.692 60.168 ;
     RECT  63.349 60.168 64.716 60.24 ;
     RECT  63.349 60.24 64.692 60.264 ;
     RECT  63.349 60.264 64.716 60.336 ;
     RECT  63.349 60.336 64.692 60.36 ;
     RECT  63.349 60.36 64.716 60.432 ;
     RECT  63.349 60.432 64.692 60.456 ;
     RECT  63.349 60.456 64.716 60.528 ;
     RECT  63.349 60.528 64.692 60.552 ;
     RECT  63.349 60.552 64.716 60.624 ;
     RECT  63.349 60.624 64.692 60.648 ;
     RECT  63.349 60.648 64.716 60.72 ;
     RECT  63.349 60.72 64.692 60.744 ;
     RECT  63.349 60.744 64.716 60.816 ;
     RECT  63.349 60.816 64.692 60.84 ;
     RECT  63.349 60.84 64.716 60.912 ;
     RECT  63.349 60.912 64.692 60.936 ;
     RECT  63.349 60.936 64.716 61.008 ;
     RECT  63.349 61.008 64.692 61.032 ;
     RECT  63.349 61.032 64.716 61.104 ;
     RECT  63.349 61.104 64.692 61.128 ;
     RECT  63.349 61.128 64.716 61.2 ;
     RECT  63.349 61.2 64.692 61.224 ;
     RECT  63.349 61.224 64.716 61.296 ;
     RECT  63.349 61.296 64.692 61.32 ;
     RECT  63.349 61.32 64.716 61.392 ;
     RECT  63.349 61.392 64.692 61.416 ;
     RECT  63.349 61.416 64.716 61.488 ;
     RECT  63.349 61.488 64.692 61.512 ;
     RECT  63.349 61.512 64.716 61.584 ;
     RECT  63.349 61.584 64.692 61.608 ;
     RECT  63.349 61.608 64.716 61.68 ;
     RECT  63.349 61.68 64.692 61.704 ;
     RECT  63.349 61.704 64.716 61.776 ;
     RECT  63.349 61.776 64.692 61.8 ;
     RECT  63.349 61.8 64.716 61.872 ;
     RECT  63.349 61.872 64.692 61.896 ;
     RECT  63.349 61.896 64.716 61.968 ;
     RECT  63.349 61.968 64.692 61.992 ;
     RECT  63.349 61.992 64.716 62.064 ;
     RECT  63.349 62.064 64.692 62.088 ;
     RECT  63.349 62.088 64.716 62.16 ;
     RECT  63.349 62.16 64.692 62.184 ;
     RECT  63.349 62.184 64.716 62.256 ;
     RECT  63.349 62.256 64.692 62.28 ;
     RECT  63.349 62.28 64.716 62.352 ;
     RECT  63.349 62.352 64.692 62.376 ;
     RECT  63.349 62.376 64.716 62.448 ;
     RECT  63.349 62.448 64.692 62.472 ;
     RECT  63.349 62.472 64.716 62.544 ;
     RECT  63.349 62.544 64.692 62.568 ;
     RECT  63.349 62.568 64.716 62.64 ;
     RECT  63.349 62.64 64.692 62.664 ;
     RECT  63.349 62.664 64.716 62.736 ;
     RECT  63.349 62.736 64.692 62.76 ;
     RECT  63.349 62.76 64.716 62.832 ;
     RECT  63.349 62.832 64.692 62.856 ;
     RECT  63.349 62.856 64.716 62.928 ;
     RECT  63.349 62.928 64.692 62.952 ;
     RECT  63.349 62.952 64.716 63.024 ;
     RECT  63.349 63.024 64.692 63.048 ;
     RECT  63.349 63.048 64.716 63.12 ;
     RECT  63.349 63.12 64.692 63.144 ;
     RECT  63.349 63.144 64.716 63.216 ;
     RECT  63.349 63.216 64.692 63.24 ;
     RECT  63.349 63.24 64.716 63.312 ;
     RECT  63.349 63.312 64.692 63.336 ;
     RECT  63.349 63.336 64.716 63.408 ;
     RECT  63.349 63.408 64.692 63.432 ;
     RECT  63.349 63.432 64.716 63.504 ;
     RECT  63.349 63.504 64.692 63.528 ;
     RECT  63.349 63.528 64.716 63.6 ;
     RECT  63.349 63.6 64.692 63.624 ;
     RECT  63.349 63.624 64.716 63.696 ;
     RECT  63.349 63.696 64.692 63.72 ;
     RECT  63.349 63.72 64.716 63.792 ;
     RECT  63.349 63.792 64.692 63.816 ;
     RECT  63.349 63.816 64.716 63.888 ;
     RECT  63.349 63.888 64.692 63.912 ;
     RECT  63.349 63.912 64.716 63.984 ;
     RECT  63.349 63.984 64.692 64.008 ;
     RECT  63.349 64.008 64.716 64.08 ;
     RECT  63.349 64.08 64.692 64.104 ;
     RECT  63.349 64.104 64.716 64.176 ;
     RECT  63.349 64.176 64.692 64.2 ;
     RECT  63.349 64.2 64.716 64.272 ;
     RECT  63.349 64.272 64.692 64.296 ;
     RECT  63.349 64.296 64.716 64.368 ;
     RECT  63.349 64.368 64.692 64.392 ;
     RECT  63.349 64.392 64.716 64.464 ;
     RECT  63.349 64.464 64.692 64.488 ;
     RECT  63.349 64.488 64.716 64.56 ;
     RECT  63.349 64.56 64.692 64.584 ;
     RECT  63.349 64.584 64.716 64.656 ;
     RECT  63.349 64.656 64.692 64.68 ;
     RECT  63.349 64.68 64.716 64.752 ;
     RECT  63.349 64.752 64.692 64.776 ;
     RECT  63.349 64.776 64.716 64.848 ;
     RECT  63.349 64.848 64.692 64.872 ;
     RECT  63.349 64.872 64.716 64.944 ;
     RECT  63.349 64.944 64.692 64.968 ;
     RECT  63.349 64.968 64.716 65.04 ;
     RECT  63.349 65.04 64.692 65.064 ;
     RECT  63.349 65.064 64.716 65.136 ;
     RECT  63.349 65.136 64.692 65.16 ;
     RECT  63.349 65.16 64.716 65.232 ;
     RECT  63.349 65.232 64.692 65.256 ;
     RECT  63.349 65.256 64.716 65.328 ;
     RECT  63.349 65.328 64.692 65.352 ;
     RECT  63.349 65.352 64.716 65.424 ;
     RECT  63.349 65.424 64.692 65.448 ;
     RECT  63.349 65.448 64.716 65.52 ;
     RECT  63.349 65.52 64.692 65.544 ;
     RECT  63.349 65.544 64.716 65.616 ;
     RECT  63.349 65.616 64.692 65.64 ;
     RECT  63.349 65.64 64.716 65.712 ;
     RECT  63.349 65.712 64.692 65.736 ;
     RECT  63.349 65.736 64.716 65.808 ;
     RECT  63.349 65.808 64.692 65.832 ;
     RECT  63.349 65.832 64.716 65.904 ;
     RECT  63.349 65.904 64.692 65.928 ;
     RECT  63.349 65.928 64.716 66 ;
     RECT  63.349 66 64.692 66.024 ;
     RECT  63.349 66.024 64.716 66.096 ;
     RECT  63.349 66.096 64.692 66.12 ;
     RECT  63.349 66.12 64.716 66.192 ;
     RECT  63.349 66.192 64.692 66.216 ;
     RECT  63.349 66.216 64.716 66.288 ;
     RECT  63.349 66.288 64.692 66.312 ;
     RECT  63.349 66.312 64.716 66.384 ;
     RECT  63.349 66.384 64.692 66.408 ;
     RECT  63.349 66.408 64.716 66.48 ;
     RECT  63.349 66.48 64.692 66.504 ;
     RECT  63.349 66.504 64.716 66.576 ;
     RECT  63.349 66.576 64.692 66.6 ;
     RECT  63.349 66.6 64.716 66.672 ;
     RECT  63.349 66.672 64.692 66.696 ;
     RECT  63.349 66.696 64.716 66.768 ;
     RECT  63.349 66.768 64.692 66.792 ;
     RECT  63.349 66.792 64.716 66.864 ;
     RECT  63.349 66.864 64.692 66.888 ;
     RECT  63.349 66.888 64.716 66.96 ;
     RECT  63.349 66.96 64.692 66.984 ;
     RECT  63.349 66.984 64.716 67.056 ;
     RECT  63.349 67.056 64.692 67.08 ;
     RECT  63.349 67.08 64.716 67.152 ;
     RECT  63.349 67.152 64.692 67.176 ;
     RECT  63.349 67.176 64.716 67.248 ;
     RECT  63.349 67.248 64.692 67.272 ;
     RECT  63.349 67.272 64.716 67.344 ;
     RECT  63.349 67.344 64.692 67.368 ;
     RECT  63.349 67.368 64.716 67.44 ;
     RECT  63.349 67.44 64.692 67.464 ;
     RECT  63.349 67.464 64.716 67.536 ;
     RECT  63.349 67.536 64.692 67.56 ;
     RECT  63.349 67.56 64.716 67.632 ;
     RECT  63.349 67.632 64.692 67.656 ;
     RECT  63.349 67.656 64.716 67.728 ;
     RECT  63.349 67.728 64.692 67.752 ;
     RECT  63.349 67.752 64.716 67.824 ;
     RECT  63.349 67.824 64.692 67.848 ;
     RECT  63.349 67.848 64.716 67.92 ;
     RECT  63.349 67.92 64.692 67.944 ;
     RECT  63.349 67.944 64.716 68.016 ;
     RECT  63.349 68.016 64.692 68.04 ;
     RECT  63.349 68.04 64.716 68.112 ;
     RECT  63.349 68.112 64.692 68.136 ;
     RECT  63.349 68.136 64.716 68.208 ;
     RECT  63.349 68.208 64.692 68.232 ;
     RECT  63.349 68.232 64.716 68.304 ;
     RECT  63.349 68.304 64.692 68.328 ;
     RECT  63.349 68.328 64.716 68.4 ;
     RECT  63.349 68.4 64.692 68.424 ;
     RECT  63.349 68.424 64.716 68.496 ;
     RECT  63.349 68.496 64.692 68.52 ;
     RECT  63.349 68.52 64.716 68.592 ;
     RECT  63.349 68.592 64.692 68.616 ;
     RECT  63.349 68.616 64.716 68.688 ;
     RECT  63.349 68.688 64.692 68.712 ;
     RECT  63.349 68.712 64.716 68.784 ;
     RECT  63.349 68.784 64.692 68.808 ;
     RECT  63.349 68.808 64.716 68.88 ;
     RECT  63.349 68.88 64.692 68.904 ;
     RECT  63.349 68.904 64.716 68.976 ;
     RECT  63.349 68.976 64.692 69 ;
     RECT  63.349 69 64.716 69.072 ;
     RECT  63.349 69.072 64.692 69.096 ;
     RECT  63.349 69.096 64.716 69.168 ;
     RECT  63.349 69.168 64.692 69.192 ;
     RECT  63.349 69.192 64.716 69.264 ;
     RECT  63.349 69.264 64.692 69.288 ;
     RECT  63.349 69.288 64.716 69.36 ;
     RECT  63.349 69.36 64.692 69.384 ;
     RECT  63.349 69.384 64.716 69.456 ;
     RECT  63.349 69.456 64.692 69.48 ;
     RECT  63.349 69.48 64.716 69.552 ;
     RECT  63.349 69.552 64.692 69.576 ;
     RECT  63.349 69.576 64.716 69.648 ;
     RECT  63.349 69.648 64.692 69.672 ;
     RECT  63.349 69.672 64.716 69.744 ;
     RECT  63.349 69.744 64.692 69.768 ;
     RECT  63.349 69.768 64.716 69.84 ;
     RECT  63.349 69.84 64.692 69.864 ;
     RECT  63.349 69.864 64.716 69.936 ;
     RECT  63.349 69.936 64.692 69.96 ;
     RECT  63.349 69.96 64.716 70.032 ;
     RECT  63.349 70.032 64.692 70.056 ;
     RECT  63.349 70.056 64.716 70.128 ;
     RECT  63.349 70.128 64.692 70.152 ;
     RECT  63.349 70.152 64.716 70.224 ;
     RECT  63.349 70.224 64.692 70.248 ;
     RECT  63.349 70.248 64.716 70.32 ;
     RECT  63.349 70.32 64.692 70.344 ;
     RECT  63.349 70.344 64.716 70.416 ;
     RECT  63.349 70.416 64.692 70.44 ;
     RECT  63.349 70.44 64.716 70.512 ;
     RECT  63.349 70.512 64.692 70.536 ;
     RECT  63.349 70.536 64.716 70.608 ;
     RECT  63.349 70.608 64.692 70.632 ;
     RECT  63.349 70.632 64.716 70.704 ;
     RECT  63.349 70.704 64.692 70.728 ;
     RECT  63.349 70.728 64.716 70.8 ;
     RECT  63.349 70.8 64.692 70.824 ;
     RECT  63.349 70.824 64.716 70.896 ;
     RECT  63.349 70.896 64.692 70.92 ;
     RECT  63.349 70.92 64.716 70.992 ;
     RECT  63.349 70.992 64.692 71.016 ;
     RECT  63.349 71.016 64.716 71.088 ;
     RECT  63.349 71.088 64.692 71.112 ;
     RECT  63.349 71.112 64.716 71.184 ;
     RECT  63.349 71.184 64.692 71.208 ;
     RECT  63.349 71.208 64.716 71.28 ;
     RECT  63.349 71.28 64.692 71.304 ;
     RECT  63.349 71.304 64.716 71.376 ;
     RECT  63.349 71.376 64.692 71.4 ;
     RECT  63.349 71.4 64.716 71.472 ;
     RECT  63.349 71.472 64.692 71.496 ;
     RECT  63.349 71.496 64.716 71.568 ;
     RECT  63.349 71.568 64.692 71.592 ;
     RECT  63.349 71.592 64.716 71.664 ;
     RECT  63.349 71.664 64.692 71.688 ;
     RECT  63.349 71.688 64.716 71.76 ;
     RECT  63.349 71.76 64.692 71.784 ;
     RECT  63.349 71.784 64.716 71.856 ;
     RECT  63.349 71.856 64.692 71.88 ;
     RECT  63.349 71.88 64.716 71.952 ;
     RECT  63.349 71.952 64.692 71.976 ;
     RECT  63.349 71.976 64.716 72.048 ;
     RECT  63.349 72.048 64.692 72.072 ;
     RECT  63.349 72.072 64.716 72.144 ;
     RECT  63.349 72.144 64.692 72.168 ;
     RECT  63.349 72.168 64.716 72.24 ;
     RECT  63.349 72.24 64.692 72.264 ;
     RECT  63.349 72.264 64.716 72.336 ;
     RECT  63.349 72.336 64.692 72.36 ;
     RECT  63.349 72.36 64.716 72.432 ;
     RECT  63.349 72.432 64.692 72.456 ;
     RECT  63.349 72.456 64.716 72.528 ;
     RECT  63.349 72.528 64.692 72.552 ;
     RECT  63.349 72.552 64.716 72.624 ;
     RECT  63.349 72.624 64.692 72.648 ;
     RECT  63.349 72.648 64.716 72.72 ;
     RECT  63.349 72.72 64.692 72.744 ;
     RECT  63.349 72.744 64.716 72.816 ;
     RECT  63.349 72.816 64.692 72.84 ;
     RECT  63.349 72.84 64.716 72.912 ;
     RECT  63.349 72.912 64.692 72.936 ;
     RECT  63.349 72.936 64.716 73.008 ;
     RECT  63.349 73.008 64.692 73.032 ;
     RECT  63.349 73.032 64.716 73.104 ;
     RECT  63.349 73.104 64.692 73.128 ;
     RECT  63.349 73.128 64.716 73.2 ;
     RECT  63.349 73.2 64.692 73.224 ;
     RECT  63.349 73.224 64.716 73.296 ;
     RECT  63.349 73.296 64.692 73.32 ;
     RECT  63.349 73.32 64.716 73.392 ;
     RECT  63.349 73.392 64.692 73.416 ;
     RECT  63.349 73.416 64.716 73.488 ;
     RECT  63.349 73.488 64.692 73.512 ;
     RECT  63.349 73.512 64.716 73.584 ;
     RECT  63.349 73.584 64.692 73.608 ;
     RECT  63.349 73.608 64.716 73.68 ;
     RECT  63.349 73.68 64.692 73.704 ;
     RECT  63.349 73.704 64.716 73.776 ;
     RECT  63.349 73.776 64.692 73.8 ;
     RECT  63.349 73.8 64.716 73.872 ;
     RECT  63.349 73.872 64.692 73.896 ;
     RECT  63.349 73.896 64.716 73.968 ;
     RECT  63.349 73.968 64.692 73.992 ;
     RECT  63.349 73.992 64.716 74.064 ;
     RECT  63.349 74.064 64.692 74.088 ;
     RECT  63.349 74.088 64.716 74.16 ;
     RECT  63.349 74.16 64.692 74.184 ;
     RECT  63.349 74.184 64.716 74.256 ;
     RECT  63.349 74.256 64.692 74.28 ;
     RECT  63.349 74.28 64.716 74.352 ;
     RECT  63.349 74.352 64.692 74.376 ;
     RECT  63.349 74.376 64.716 74.448 ;
     RECT  63.349 74.448 64.692 74.472 ;
     RECT  63.349 74.472 64.716 74.544 ;
     RECT  63.349 74.544 64.692 74.568 ;
     RECT  63.349 74.568 64.716 74.64 ;
     RECT  63.349 74.64 64.692 74.664 ;
     RECT  63.349 74.664 64.716 74.736 ;
     RECT  63.349 74.736 64.692 74.76 ;
     RECT  63.349 74.76 64.716 74.832 ;
     RECT  63.349 74.832 64.692 74.856 ;
     RECT  63.349 74.856 64.716 74.928 ;
     RECT  63.349 74.928 64.692 74.952 ;
     RECT  63.349 74.952 64.716 75.024 ;
     RECT  63.349 75.024 64.692 75.048 ;
     RECT  63.349 75.048 64.716 75.12 ;
     RECT  63.349 75.12 64.692 75.144 ;
     RECT  63.349 75.144 64.716 75.216 ;
     RECT  63.349 75.216 64.692 75.24 ;
     RECT  63.349 75.24 64.716 75.312 ;
     RECT  63.349 75.312 64.692 75.336 ;
     RECT  63.349 75.336 64.716 75.408 ;
     RECT  63.349 75.408 64.692 75.432 ;
     RECT  63.349 75.432 64.716 75.504 ;
     RECT  63.349 75.504 64.692 75.528 ;
     RECT  63.349 75.528 64.716 75.6 ;
     RECT  63.349 75.6 64.692 75.624 ;
     RECT  63.349 75.624 64.716 75.696 ;
     RECT  63.349 75.696 64.692 75.72 ;
     RECT  63.349 75.72 64.716 75.792 ;
     RECT  63.349 75.792 64.692 75.816 ;
     RECT  63.349 75.816 64.716 75.888 ;
     RECT  63.349 75.888 64.692 75.912 ;
     RECT  63.349 75.912 64.716 75.984 ;
     RECT  63.349 75.984 64.692 76.008 ;
     RECT  63.349 76.008 64.716 76.08 ;
     RECT  63.349 76.08 64.692 76.104 ;
     RECT  63.349 76.104 64.716 76.176 ;
     RECT  63.349 76.176 64.692 76.2 ;
     RECT  63.349 76.2 64.716 76.272 ;
     RECT  63.349 76.272 64.692 76.296 ;
     RECT  63.349 76.296 64.716 76.368 ;
     RECT  63.349 76.368 64.692 76.392 ;
     RECT  63.349 76.392 64.716 76.464 ;
     RECT  63.349 76.464 64.692 76.488 ;
     RECT  63.349 76.488 64.716 76.56 ;
     RECT  63.349 76.56 64.692 76.584 ;
     RECT  63.349 76.584 64.716 76.656 ;
     RECT  63.349 76.656 64.692 76.68 ;
     RECT  63.349 76.68 64.716 77.52 ;
     RECT  63.349 77.52 64.692 77.544 ;
     RECT  63.349 77.544 64.716 77.616 ;
     RECT  63.349 77.616 64.692 77.64 ;
     RECT  63.349 77.64 64.716 77.712 ;
     RECT  63.349 77.712 64.692 77.736 ;
     RECT  63.349 77.736 64.716 77.808 ;
     RECT  63.349 77.808 64.692 77.832 ;
     RECT  63.349 77.832 64.716 77.904 ;
     RECT  63.349 77.904 64.692 77.928 ;
     RECT  63.349 77.928 64.716 78 ;
     RECT  63.349 78 64.692 78.024 ;
     RECT  63.349 78.024 64.716 78.096 ;
     RECT  63.349 78.096 64.692 78.12 ;
     RECT  63.349 78.12 64.716 78.192 ;
     RECT  63.349 78.192 64.692 78.216 ;
     RECT  63.349 78.216 64.716 78.288 ;
     RECT  63.349 78.288 64.692 78.312 ;
     RECT  63.349 78.312 64.716 78.384 ;
     RECT  63.349 78.384 64.692 78.408 ;
     RECT  63.349 78.408 64.716 78.48 ;
     RECT  63.349 78.48 64.692 78.504 ;
     RECT  63.349 78.504 64.716 78.576 ;
     RECT  63.349 78.576 64.692 78.6 ;
     RECT  63.349 78.6 64.716 78.672 ;
     RECT  63.349 78.672 64.692 78.696 ;
     RECT  63.349 78.696 64.716 78.768 ;
     RECT  63.349 78.768 64.692 78.792 ;
     RECT  63.349 78.792 64.716 78.864 ;
     RECT  63.349 78.864 64.692 78.888 ;
     RECT  63.349 78.888 64.716 78.96 ;
     RECT  63.349 78.96 64.692 78.984 ;
     RECT  63.349 78.984 64.716 79.056 ;
     RECT  63.349 79.056 64.692 79.08 ;
     RECT  63.349 79.08 64.716 79.152 ;
     RECT  63.349 79.152 64.692 79.176 ;
     RECT  63.349 79.176 64.716 79.248 ;
     RECT  63.349 79.248 64.692 79.272 ;
     RECT  63.349 79.272 64.716 79.344 ;
     RECT  63.349 79.344 64.692 79.368 ;
     RECT  63.349 79.368 64.716 79.44 ;
     RECT  63.349 79.44 64.692 79.464 ;
     RECT  63.349 79.464 64.716 79.536 ;
     RECT  63.349 79.536 64.692 79.56 ;
     RECT  63.349 79.56 64.716 79.632 ;
     RECT  63.349 79.632 64.692 79.656 ;
     RECT  63.349 79.656 64.716 79.728 ;
     RECT  63.349 79.728 64.692 79.752 ;
     RECT  63.349 79.752 64.716 79.824 ;
     RECT  63.349 79.824 64.692 79.848 ;
     RECT  64.716 22.848 64.757 22.872 ;
     RECT  64.716 36.288 64.757 36.312 ;
     RECT  64.716 42.048 64.757 42.072 ;
     RECT  64.716 49.728 64.757 49.752 ;
     RECT  64.716 55.968 64.757 55.992 ;
     RECT  64.716 74.016 64.757 74.04 ;
     RECT  64.716 78.624 64.757 78.672 ;
     RECT  64.716 78.696 64.757 78.768 ;
     RECT  64.716 78.792 64.757 78.864 ;
     RECT  64.716 78.888 64.757 78.96 ;
     RECT  64.716 78.984 64.757 79.056 ;
     RECT  64.716 79.08 64.757 79.152 ;
     RECT  64.716 79.176 64.757 79.248 ;
     RECT  64.716 79.272 64.757 79.32 ;
    LAYER M5 ;
     RECT  2.4 2.137 2.52 2.151 ;
     RECT  5.1 2.137 5.22 2.151 ;
     RECT  7.8 2.137 7.92 2.151 ;
     RECT  10.5 2.137 10.62 2.151 ;
     RECT  13.2 2.137 13.32 2.151 ;
     RECT  15.9 2.137 16.02 2.151 ;
     RECT  18.6 2.137 18.72 2.151 ;
     RECT  21.3 2.137 21.42 2.151 ;
     RECT  24 2.137 24.12 2.151 ;
     RECT  26.7 2.137 26.82 2.151 ;
     RECT  29.4 2.137 29.52 2.151 ;
     RECT  32.1 2.137 32.22 2.151 ;
     RECT  34.8 2.137 34.92 2.151 ;
     RECT  37.5 2.137 37.62 2.151 ;
     RECT  40.2 2.137 40.32 2.151 ;
     RECT  42.9 2.137 43.02 2.151 ;
     RECT  45.6 2.137 45.72 2.151 ;
     RECT  48.3 2.137 48.42 2.151 ;
     RECT  51 2.137 51.12 2.151 ;
     RECT  53.7 2.137 53.82 2.151 ;
     RECT  56.4 2.137 56.52 2.151 ;
     RECT  59.1 2.137 59.22 2.151 ;
     RECT  61.8 2.137 61.92 2.151 ;
     RECT  56.4 2.151 56.712 20.965 ;
     RECT  56.304 20.965 56.712 21.683 ;
     RECT  2.4 2.151 2.712 23.077 ;
     RECT  59.1 2.151 59.412 23.605 ;
     RECT  56.4 21.683 56.712 24.181 ;
     RECT  55.92 24.181 56.712 25.091 ;
     RECT  0.144 26.053 0.168 26.243 ;
     RECT  5.1 2.151 5.412 26.293 ;
     RECT  34.8 2.151 35.112 26.533 ;
     RECT  1.248 26.533 1.272 26.675 ;
     RECT  4.56 26.293 5.412 26.675 ;
     RECT  57.84 26.197 57.864 27.059 ;
     RECT  56.4 25.091 56.712 27.397 ;
     RECT  32.1 2.151 32.412 28.741 ;
     RECT  59.1 23.605 59.544 28.885 ;
     RECT  59.1 28.885 59.928 29.027 ;
     RECT  56.4 27.397 56.808 29.075 ;
     RECT  32.1 28.741 33.336 29.845 ;
     RECT  31.248 29.845 33.336 30.181 ;
     RECT  7.8 2.151 8.112 30.373 ;
     RECT  6.864 30.373 8.112 30.515 ;
     RECT  22.8 30.373 22.824 30.755 ;
     RECT  24 2.151 24.312 30.805 ;
     RECT  23.904 30.805 24.312 30.947 ;
     RECT  64.608 30.757 64.632 30.947 ;
     RECT  30.72 30.181 33.336 31.717 ;
     RECT  34.416 26.533 35.112 31.717 ;
     RECT  14.832 31.477 14.856 31.763 ;
     RECT  59.1 29.027 59.544 32.005 ;
     RECT  24 30.947 24.312 32.821 ;
     RECT  23.904 32.821 24.312 33.011 ;
     RECT  56.4 29.075 56.712 33.013 ;
     RECT  56.4 33.013 56.808 33.683 ;
     RECT  59.1 32.005 59.832 34.309 ;
     RECT  24 33.011 24.312 34.549 ;
     RECT  22.8 34.357 22.824 34.739 ;
     RECT  59.1 34.309 60.12 34.787 ;
     RECT  23.904 34.549 24.312 35.267 ;
     RECT  56.4 33.683 56.712 36.805 ;
     RECT  22.8 36.853 22.824 36.995 ;
     RECT  29.4 2.151 29.712 37.045 ;
     RECT  30.72 31.717 35.112 37.045 ;
     RECT  24 35.267 24.312 37.285 ;
     RECT  29.4 37.045 35.112 37.379 ;
     RECT  23.904 37.285 24.312 37.427 ;
     RECT  59.1 34.787 59.832 38.005 ;
     RECT  55.728 36.805 56.712 38.195 ;
     RECT  55.776 38.195 56.712 38.485 ;
     RECT  55.776 38.485 57.096 38.771 ;
     RECT  55.776 38.771 57 38.915 ;
     RECT  59.1 38.005 59.928 39.923 ;
     RECT  55.776 38.915 56.808 40.021 ;
     RECT  22.8 40.021 22.824 40.403 ;
     RECT  22.8 41.365 22.824 41.507 ;
     RECT  2.4 23.077 3.384 41.605 ;
     RECT  2.304 41.605 3.384 42.275 ;
     RECT  29.4 37.379 29.712 42.757 ;
     RECT  30.72 37.379 35.112 42.757 ;
     RECT  55.536 40.021 56.904 42.757 ;
     RECT  22.8 42.997 22.824 43.139 ;
     RECT  29.4 42.757 35.112 43.285 ;
     RECT  29.4 43.285 35.256 43.379 ;
     RECT  0.192 43.861 0.216 44.099 ;
     RECT  22.8 44.341 22.824 45.061 ;
     RECT  29.4 43.379 29.712 45.157 ;
     RECT  30.72 43.379 35.256 45.157 ;
     RECT  22.8 45.061 22.872 45.253 ;
     RECT  29.4 45.157 35.256 45.299 ;
     RECT  22.8 45.253 22.92 45.541 ;
     RECT  59.1 39.923 59.412 45.541 ;
     RECT  22.8 45.541 23.016 45.683 ;
     RECT  22.8 45.683 22.824 46.067 ;
     RECT  58.992 45.541 59.412 46.259 ;
     RECT  55.536 42.757 57.336 48.083 ;
     RECT  29.4 45.299 29.712 49.045 ;
     RECT  0.144 49.093 0.168 49.283 ;
     RECT  55.536 48.083 57 49.333 ;
     RECT  29.136 49.045 29.712 49.571 ;
     RECT  7.8 30.515 8.112 50.341 ;
     RECT  22.8 48.997 22.824 50.387 ;
     RECT  6.864 50.341 8.112 50.627 ;
     RECT  55.536 49.333 57.384 50.771 ;
     RECT  59.1 46.259 59.412 51.637 ;
     RECT  55.536 50.771 56.712 51.877 ;
     RECT  7.8 50.627 8.112 51.973 ;
     RECT  14.832 52.069 14.856 52.211 ;
     RECT  55.44 51.877 56.712 52.307 ;
     RECT  29.4 49.571 29.712 52.357 ;
     RECT  6.864 51.973 8.112 52.403 ;
     RECT  29.184 52.357 29.712 52.595 ;
     RECT  24 37.427 24.312 52.693 ;
     RECT  30.72 45.299 35.256 52.837 ;
     RECT  23.904 52.693 24.312 52.883 ;
     RECT  59.1 51.637 60.216 52.931 ;
     RECT  30.72 52.837 35.304 53.171 ;
     RECT  15.9 2.151 16.212 53.317 ;
     RECT  14.928 53.317 16.212 53.555 ;
     RECT  29.4 52.595 29.712 53.557 ;
     RECT  59.1 52.931 59.412 53.557 ;
     RECT  22.8 51.973 22.824 54.275 ;
     RECT  29.184 53.557 29.712 54.421 ;
     RECT  24 52.883 24.312 54.565 ;
     RECT  23.904 54.565 24.312 54.707 ;
     RECT  28.368 54.421 29.712 54.707 ;
     RECT  55.584 52.307 56.712 54.853 ;
     RECT  55.296 54.853 56.712 55.331 ;
     RECT  58.944 53.557 59.412 55.957 ;
     RECT  58.848 55.957 59.412 56.099 ;
     RECT  2.4 42.275 3.384 56.101 ;
     RECT  2.304 56.101 3.384 56.291 ;
     RECT  29.184 54.707 29.712 56.293 ;
     RECT  22.8 56.293 22.824 56.435 ;
     RECT  28.608 56.293 29.712 56.435 ;
     RECT  30.72 53.171 35.256 58.163 ;
     RECT  29.184 56.435 29.712 58.693 ;
     RECT  29.184 58.693 30.408 58.931 ;
     RECT  58.992 56.099 59.412 59.797 ;
     RECT  58.992 59.797 60.072 59.989 ;
     RECT  31.392 58.163 35.256 60.467 ;
     RECT  58.512 59.989 60.072 60.851 ;
     RECT  24 54.707 24.312 61.045 ;
     RECT  23.904 61.045 24.312 61.187 ;
     RECT  55.584 55.331 56.712 61.331 ;
     RECT  58.512 60.851 59.412 61.381 ;
     RECT  0.192 61.429 0.216 61.667 ;
     RECT  57.696 61.381 59.412 61.909 ;
     RECT  22.8 61.813 22.824 62.003 ;
     RECT  57.696 61.909 60.36 62.147 ;
     RECT  29.184 58.931 29.712 62.387 ;
     RECT  24 61.187 24.312 63.061 ;
     RECT  23.904 63.061 24.312 63.251 ;
     RECT  31.92 60.467 35.256 63.443 ;
     RECT  58.512 62.147 60.36 63.491 ;
     RECT  32.1 63.443 35.256 63.923 ;
     RECT  24 63.251 24.312 64.789 ;
     RECT  23.904 64.789 24.312 64.931 ;
     RECT  0.192 65.461 0.216 65.699 ;
     RECT  21.3 2.151 21.612 66.229 ;
     RECT  22.8 64.789 22.824 66.229 ;
     RECT  14.832 66.229 14.856 66.277 ;
     RECT  15.9 53.555 16.212 66.277 ;
     RECT  14.832 66.277 16.212 66.515 ;
     RECT  14.832 66.515 14.856 66.611 ;
     RECT  21.3 66.229 22.824 66.611 ;
     RECT  22.8 66.611 22.824 66.707 ;
     RECT  58.512 63.491 59.412 66.853 ;
     RECT  58.128 66.853 59.412 67.189 ;
     RECT  57.696 67.189 59.412 67.283 ;
     RECT  15.9 66.515 16.212 67.861 ;
     RECT  14.928 67.861 16.212 68.147 ;
     RECT  22.8 67.861 22.824 68.387 ;
     RECT  57.696 67.283 57.72 68.675 ;
     RECT  0.864 68.725 0.888 68.963 ;
     RECT  24 64.931 24.312 69.157 ;
     RECT  23.904 69.157 24.312 69.299 ;
     RECT  56.4 61.331 56.712 70.069 ;
     RECT  58.992 67.283 59.412 70.261 ;
     RECT  14.832 70.261 14.856 70.595 ;
     RECT  55.872 70.069 56.712 70.835 ;
     RECT  58.752 70.261 59.412 71.075 ;
     RECT  22.8 69.733 22.824 71.123 ;
     RECT  24 69.299 24.312 71.317 ;
     RECT  2.4 56.291 3.384 71.701 ;
     RECT  23.904 71.317 24.312 71.987 ;
     RECT  2.304 71.701 3.384 72.083 ;
     RECT  45.6 2.151 45.912 72.565 ;
     RECT  58.992 71.075 59.412 73.237 ;
     RECT  44.784 72.565 45.912 73.283 ;
     RECT  58.704 73.237 59.412 74.149 ;
     RECT  58.08 74.149 59.412 74.195 ;
     RECT  58.08 74.195 58.104 76.979 ;
     RECT  56.4 70.835 56.712 78.565 ;
     RECT  56.4 78.565 57.384 78.707 ;
     RECT  7.8 52.403 8.112 80.581 ;
     RECT  6.864 80.581 8.112 80.867 ;
     RECT  15.9 68.147 16.212 81.061 ;
     RECT  14.928 81.061 16.212 81.203 ;
     RECT  2.4 72.083 3.384 82.691 ;
     RECT  32.1 63.923 35.112 102.659 ;
     RECT  2.4 82.691 2.712 103.419 ;
     RECT  5.1 26.675 5.412 103.419 ;
     RECT  7.8 80.867 8.112 103.419 ;
     RECT  10.5 2.151 10.812 103.419 ;
     RECT  13.2 2.151 13.512 103.419 ;
     RECT  15.9 81.203 16.212 103.419 ;
     RECT  18.6 2.151 18.912 103.419 ;
     RECT  21.3 66.611 21.612 103.419 ;
     RECT  24 71.987 24.312 103.419 ;
     RECT  26.7 2.151 27.012 103.419 ;
     RECT  29.4 62.387 29.712 103.419 ;
     RECT  32.1 102.659 32.412 103.419 ;
     RECT  33.744 102.659 35.112 103.419 ;
     RECT  37.5 2.151 37.812 103.419 ;
     RECT  40.2 2.151 40.512 103.419 ;
     RECT  42.9 2.151 43.212 103.419 ;
     RECT  45.6 73.283 45.912 103.419 ;
     RECT  48.3 2.151 48.612 103.419 ;
     RECT  51 2.151 51.312 103.419 ;
     RECT  53.7 2.151 54.012 103.419 ;
     RECT  56.4 78.707 56.712 103.419 ;
     RECT  59.1 74.195 59.412 103.419 ;
     RECT  61.8 2.151 62.112 103.419 ;
     RECT  2.592 103.419 2.712 103.433 ;
     RECT  5.292 103.419 5.412 103.433 ;
     RECT  7.992 103.419 8.112 103.433 ;
     RECT  10.692 103.419 10.812 103.433 ;
     RECT  13.392 103.419 13.512 103.433 ;
     RECT  16.092 103.419 16.212 103.433 ;
     RECT  18.792 103.419 18.912 103.433 ;
     RECT  21.492 103.419 21.612 103.433 ;
     RECT  24.192 103.419 24.312 103.433 ;
     RECT  26.892 103.419 27.012 103.433 ;
     RECT  29.592 103.419 29.712 103.433 ;
     RECT  32.292 103.419 32.412 103.433 ;
     RECT  34.992 103.419 35.112 103.433 ;
     RECT  37.692 103.419 37.812 103.433 ;
     RECT  40.392 103.419 40.512 103.433 ;
     RECT  43.092 103.419 43.212 103.433 ;
     RECT  45.792 103.419 45.912 103.433 ;
     RECT  48.492 103.419 48.612 103.433 ;
     RECT  51.192 103.419 51.312 103.433 ;
     RECT  53.892 103.419 54.012 103.433 ;
     RECT  56.592 103.419 56.712 103.433 ;
     RECT  59.292 103.419 59.412 103.433 ;
     RECT  61.992 103.419 62.112 103.433 ;
     RECT  33.744 103.419 33.864 105.732 ;
     RECT  33.768 105.732 33.84 105.744 ;
     RECT  56.712 26.197 57.84 27.059 ;
     RECT  57.864 26.197 59.1 27.059 ;
     RECT  3.384 26.293 4.56 26.675 ;
     RECT  1.272 26.533 2.4 26.675 ;
     RECT  56.712 27.059 56.808 27.397 ;
     RECT  33.336 28.741 34.416 31.717 ;
     RECT  29.712 30.181 30.72 37.045 ;
     RECT  5.412 30.373 6.864 30.515 ;
     RECT  21.612 30.373 22.8 30.755 ;
     RECT  22.824 30.373 24 30.755 ;
     RECT  23.904 30.755 24 30.805 ;
     RECT  13.512 31.477 14.832 31.763 ;
     RECT  14.856 31.477 15.9 31.763 ;
     RECT  23.904 33.011 24 34.357 ;
     RECT  21.612 34.357 22.8 34.739 ;
     RECT  22.824 34.357 24 34.549 ;
     RECT  22.824 34.549 23.904 34.739 ;
     RECT  21.612 36.853 22.8 36.995 ;
     RECT  22.824 36.853 24 36.995 ;
     RECT  23.904 36.995 24 37.285 ;
     RECT  29.712 37.379 30.72 42.757 ;
     RECT  56.808 38.915 56.904 40.021 ;
     RECT  21.612 40.021 22.8 40.403 ;
     RECT  22.824 40.021 24 40.403 ;
     RECT  54.012 40.021 55.536 51.877 ;
     RECT  21.612 40.403 24 41.365 ;
     RECT  21.612 41.365 22.8 41.507 ;
     RECT  22.824 41.365 24 41.507 ;
     RECT  21.612 41.507 24 42.997 ;
     RECT  21.612 42.997 22.8 43.139 ;
     RECT  22.824 42.997 24 43.139 ;
     RECT  21.612 43.139 24 44.341 ;
     RECT  29.712 43.379 30.72 45.157 ;
     RECT  21.612 44.341 22.8 46.067 ;
     RECT  22.824 44.341 24 45.061 ;
     RECT  22.872 45.061 24 45.253 ;
     RECT  22.92 45.253 24 45.541 ;
     RECT  29.712 45.299 30.72 58.163 ;
     RECT  23.016 45.541 24 45.683 ;
     RECT  22.824 45.683 24 46.067 ;
     RECT  57 48.083 57.336 49.333 ;
     RECT  21.612 48.997 22.8 50.387 ;
     RECT  22.824 48.997 24 50.387 ;
     RECT  5.412 50.341 6.864 50.627 ;
     RECT  5.412 50.627 7.8 51.973 ;
     RECT  54.012 51.877 55.44 52.307 ;
     RECT  5.412 51.973 6.864 52.403 ;
     RECT  21.612 51.973 22.8 54.275 ;
     RECT  22.824 51.973 24 52.693 ;
     RECT  13.512 52.069 14.832 52.211 ;
     RECT  14.856 52.069 15.9 52.211 ;
     RECT  13.512 52.211 15.9 53.317 ;
     RECT  29.184 52.595 29.4 53.557 ;
     RECT  22.824 52.693 23.904 52.883 ;
     RECT  22.824 52.883 24 54.275 ;
     RECT  13.512 53.317 14.928 53.555 ;
     RECT  23.904 54.275 24 54.565 ;
     RECT  27.012 54.421 28.368 54.707 ;
     RECT  54.012 54.853 55.296 55.331 ;
     RECT  21.612 56.293 22.8 56.435 ;
     RECT  22.824 56.293 24 56.435 ;
     RECT  29.712 58.163 31.392 58.693 ;
     RECT  30.408 58.693 31.392 58.931 ;
     RECT  59.412 60.851 60.072 61.909 ;
     RECT  23.904 61.187 24 61.813 ;
     RECT  56.712 61.381 57.696 62.147 ;
     RECT  21.612 61.813 22.8 62.003 ;
     RECT  22.824 61.813 24 62.003 ;
     RECT  60.36 61.909 61.8 63.491 ;
     RECT  23.904 62.003 24 63.061 ;
     RECT  21.612 64.789 22.8 66.229 ;
     RECT  22.824 64.789 23.904 64.931 ;
     RECT  22.824 64.931 24 66.707 ;
     RECT  13.512 66.229 14.832 66.611 ;
     RECT  14.856 66.229 15.9 66.277 ;
     RECT  14.856 66.515 15.9 66.611 ;
     RECT  13.512 66.611 15.9 67.861 ;
     RECT  21.612 66.611 22.8 66.707 ;
     RECT  21.612 66.707 24 67.861 ;
     RECT  56.712 66.853 58.128 67.189 ;
     RECT  56.712 67.189 57.696 68.675 ;
     RECT  57.72 67.283 58.992 68.675 ;
     RECT  13.512 67.861 14.928 68.147 ;
     RECT  21.612 67.861 22.8 68.387 ;
     RECT  22.824 67.861 24 68.387 ;
     RECT  21.612 68.387 24 69.157 ;
     RECT  0.888 68.725 2.4 68.963 ;
     RECT  21.612 69.157 23.904 69.299 ;
     RECT  21.612 69.299 24 69.733 ;
     RECT  21.612 69.733 22.8 71.123 ;
     RECT  22.824 69.733 24 71.123 ;
     RECT  13.512 70.261 14.832 70.595 ;
     RECT  14.856 70.261 15.9 70.595 ;
     RECT  23.904 71.123 24 71.317 ;
     RECT  56.712 74.149 58.08 76.979 ;
     RECT  58.104 74.195 59.1 76.979 ;
     RECT  5.412 80.581 6.864 80.867 ;
     RECT  13.512 81.061 14.928 81.203 ;
     RECT  32.412 102.659 33.744 103.433 ;
     RECT  33.864 103.419 34.992 103.433 ;
  END
END qfd_rlyh_600_EW_65x106
END LIBRARY
